VERSION 5.8 ;
BUSBITCHARS "[]" ;
DIVIDERCHAR "/" ;
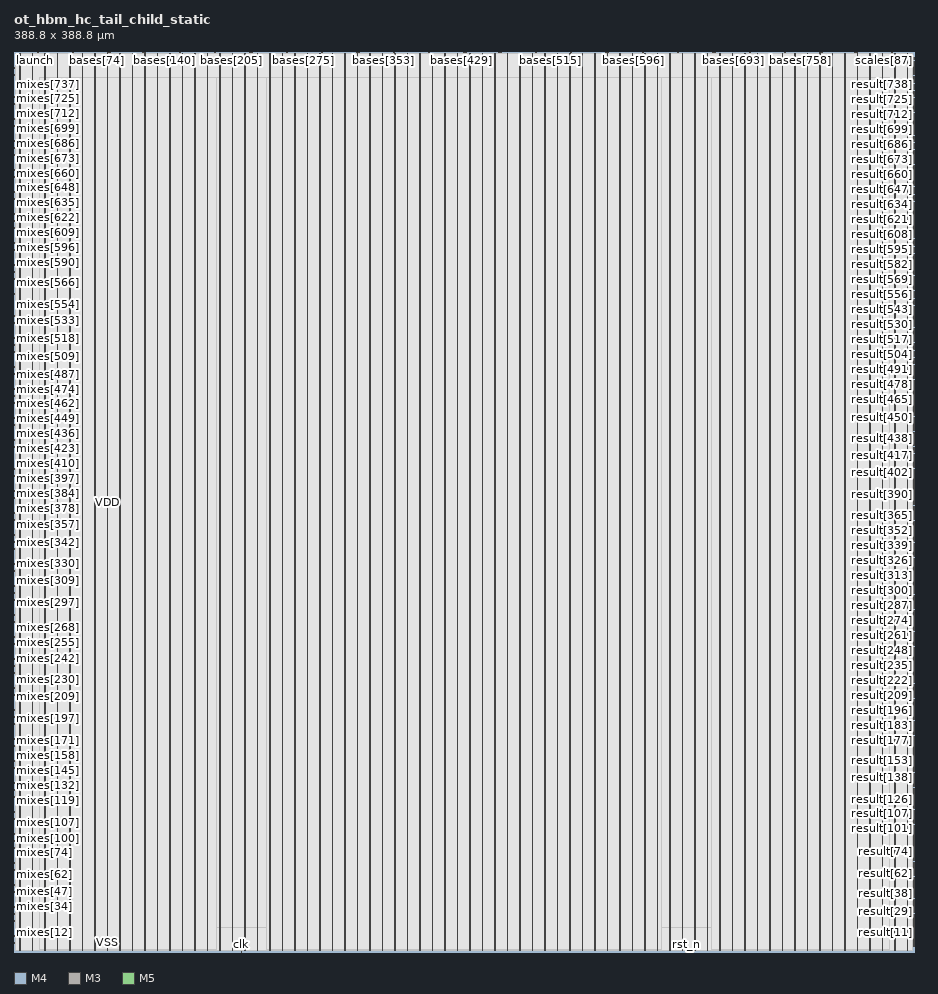
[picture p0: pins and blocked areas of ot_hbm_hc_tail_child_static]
MACRO ot_hbm_hc_tail_child_static
  CLASS BLOCK ;
  ORIGIN 0 0 ;
  FOREIGN ot_hbm_hc_tail_child_static 0 0 ;
  SIZE 388.8 BY 388.8 ;
  SYMMETRY X Y ;
  PIN mixes[0]
    DIRECTION INPUT ;
    USE SIGNAL ;
    PORT
      LAYER M4 ;
        RECT 0.000 2.400 0.192 2.424 ;
    END
  END mixes[0]
  PIN mixes[1]
    DIRECTION INPUT ;
    USE SIGNAL ;
    PORT
      LAYER M4 ;
        RECT 0.000 2.880 0.192 2.904 ;
    END
  END mixes[1]
  PIN mixes[2]
    DIRECTION INPUT ;
    USE SIGNAL ;
    PORT
      LAYER M4 ;
        RECT 0.000 3.408 0.192 3.432 ;
    END
  END mixes[2]
  PIN mixes[3]
    DIRECTION INPUT ;
    USE SIGNAL ;
    PORT
      LAYER M4 ;
        RECT 0.000 3.888 0.192 3.912 ;
    END
  END mixes[3]
  PIN mixes[4]
    DIRECTION INPUT ;
    USE SIGNAL ;
    PORT
      LAYER M4 ;
        RECT 0.000 4.416 0.192 4.440 ;
    END
  END mixes[4]
  PIN mixes[5]
    DIRECTION INPUT ;
    USE SIGNAL ;
    PORT
      LAYER M4 ;
        RECT 0.000 4.896 0.192 4.920 ;
    END
  END mixes[5]
  PIN mixes[6]
    DIRECTION INPUT ;
    USE SIGNAL ;
    PORT
      LAYER M4 ;
        RECT 0.000 5.424 0.192 5.448 ;
    END
  END mixes[6]
  PIN mixes[7]
    DIRECTION INPUT ;
    USE SIGNAL ;
    PORT
      LAYER M4 ;
        RECT 0.000 5.904 0.192 5.928 ;
    END
  END mixes[7]
  PIN mixes[8]
    DIRECTION INPUT ;
    USE SIGNAL ;
    PORT
      LAYER M4 ;
        RECT 0.000 6.384 0.192 6.408 ;
    END
  END mixes[8]
  PIN mixes[9]
    DIRECTION INPUT ;
    USE SIGNAL ;
    PORT
      LAYER M4 ;
        RECT 0.000 6.912 0.192 6.936 ;
    END
  END mixes[9]
  PIN mixes[10]
    DIRECTION INPUT ;
    USE SIGNAL ;
    PORT
      LAYER M4 ;
        RECT 0.000 7.392 0.192 7.416 ;
    END
  END mixes[10]
  PIN mixes[11]
    DIRECTION INPUT ;
    USE SIGNAL ;
    PORT
      LAYER M4 ;
        RECT 0.000 7.920 0.192 7.944 ;
    END
  END mixes[11]
  PIN mixes[12]
    DIRECTION INPUT ;
    USE SIGNAL ;
    PORT
      LAYER M4 ;
        RECT 0.000 8.400 0.192 8.424 ;
    END
  END mixes[12]
  PIN mixes[13]
    DIRECTION INPUT ;
    USE SIGNAL ;
    PORT
      LAYER M4 ;
        RECT 0.000 8.928 0.192 8.952 ;
    END
  END mixes[13]
  PIN mixes[14]
    DIRECTION INPUT ;
    USE SIGNAL ;
    PORT
      LAYER M4 ;
        RECT 0.000 9.408 0.192 9.432 ;
    END
  END mixes[14]
  PIN mixes[15]
    DIRECTION INPUT ;
    USE SIGNAL ;
    PORT
      LAYER M4 ;
        RECT 0.000 9.888 0.192 9.912 ;
    END
  END mixes[15]
  PIN mixes[16]
    DIRECTION INPUT ;
    USE SIGNAL ;
    PORT
      LAYER M4 ;
        RECT 0.000 10.416 0.192 10.440 ;
    END
  END mixes[16]
  PIN mixes[17]
    DIRECTION INPUT ;
    USE SIGNAL ;
    PORT
      LAYER M4 ;
        RECT 0.000 10.896 0.192 10.920 ;
    END
  END mixes[17]
  PIN mixes[18]
    DIRECTION INPUT ;
    USE SIGNAL ;
    PORT
      LAYER M4 ;
        RECT 0.000 11.424 0.192 11.448 ;
    END
  END mixes[18]
  PIN mixes[19]
    DIRECTION INPUT ;
    USE SIGNAL ;
    PORT
      LAYER M4 ;
        RECT 0.000 11.904 0.192 11.928 ;
    END
  END mixes[19]
  PIN mixes[20]
    DIRECTION INPUT ;
    USE SIGNAL ;
    PORT
      LAYER M4 ;
        RECT 0.000 12.432 0.192 12.456 ;
    END
  END mixes[20]
  PIN mixes[21]
    DIRECTION INPUT ;
    USE SIGNAL ;
    PORT
      LAYER M4 ;
        RECT 0.000 12.912 0.192 12.936 ;
    END
  END mixes[21]
  PIN mixes[22]
    DIRECTION INPUT ;
    USE SIGNAL ;
    PORT
      LAYER M4 ;
        RECT 0.000 13.392 0.192 13.416 ;
    END
  END mixes[22]
  PIN mixes[23]
    DIRECTION INPUT ;
    USE SIGNAL ;
    PORT
      LAYER M4 ;
        RECT 0.000 13.920 0.192 13.944 ;
    END
  END mixes[23]
  PIN mixes[24]
    DIRECTION INPUT ;
    USE SIGNAL ;
    PORT
      LAYER M4 ;
        RECT 0.000 14.400 0.192 14.424 ;
    END
  END mixes[24]
  PIN mixes[25]
    DIRECTION INPUT ;
    USE SIGNAL ;
    PORT
      LAYER M4 ;
        RECT 0.000 14.928 0.192 14.952 ;
    END
  END mixes[25]
  PIN mixes[26]
    DIRECTION INPUT ;
    USE SIGNAL ;
    PORT
      LAYER M4 ;
        RECT 0.000 15.408 0.192 15.432 ;
    END
  END mixes[26]
  PIN mixes[27]
    DIRECTION INPUT ;
    USE SIGNAL ;
    PORT
      LAYER M4 ;
        RECT 0.000 15.936 0.192 15.960 ;
    END
  END mixes[27]
  PIN mixes[28]
    DIRECTION INPUT ;
    USE SIGNAL ;
    PORT
      LAYER M4 ;
        RECT 0.000 16.416 0.192 16.440 ;
    END
  END mixes[28]
  PIN mixes[29]
    DIRECTION INPUT ;
    USE SIGNAL ;
    PORT
      LAYER M4 ;
        RECT 0.000 16.896 0.192 16.920 ;
    END
  END mixes[29]
  PIN mixes[30]
    DIRECTION INPUT ;
    USE SIGNAL ;
    PORT
      LAYER M4 ;
        RECT 0.000 17.424 0.192 17.448 ;
    END
  END mixes[30]
  PIN mixes[31]
    DIRECTION INPUT ;
    USE SIGNAL ;
    PORT
      LAYER M4 ;
        RECT 0.000 17.904 0.192 17.928 ;
    END
  END mixes[31]
  PIN mixes[32]
    DIRECTION INPUT ;
    USE SIGNAL ;
    PORT
      LAYER M4 ;
        RECT 0.000 18.432 0.192 18.456 ;
    END
  END mixes[32]
  PIN mixes[33]
    DIRECTION INPUT ;
    USE SIGNAL ;
    PORT
      LAYER M4 ;
        RECT 0.000 18.912 0.192 18.936 ;
    END
  END mixes[33]
  PIN mixes[34]
    DIRECTION INPUT ;
    USE SIGNAL ;
    PORT
      LAYER M4 ;
        RECT 0.000 19.440 0.192 19.464 ;
    END
  END mixes[34]
  PIN mixes[35]
    DIRECTION INPUT ;
    USE SIGNAL ;
    PORT
      LAYER M4 ;
        RECT 0.000 19.920 0.192 19.944 ;
    END
  END mixes[35]
  PIN mixes[36]
    DIRECTION INPUT ;
    USE SIGNAL ;
    PORT
      LAYER M4 ;
        RECT 0.000 20.400 0.192 20.424 ;
    END
  END mixes[36]
  PIN mixes[37]
    DIRECTION INPUT ;
    USE SIGNAL ;
    PORT
      LAYER M4 ;
        RECT 0.000 20.928 0.192 20.952 ;
    END
  END mixes[37]
  PIN mixes[38]
    DIRECTION INPUT ;
    USE SIGNAL ;
    PORT
      LAYER M4 ;
        RECT 0.000 21.408 0.192 21.432 ;
    END
  END mixes[38]
  PIN mixes[39]
    DIRECTION INPUT ;
    USE SIGNAL ;
    PORT
      LAYER M4 ;
        RECT 0.000 21.936 0.192 21.960 ;
    END
  END mixes[39]
  PIN mixes[40]
    DIRECTION INPUT ;
    USE SIGNAL ;
    PORT
      LAYER M4 ;
        RECT 0.000 22.416 0.192 22.440 ;
    END
  END mixes[40]
  PIN mixes[41]
    DIRECTION INPUT ;
    USE SIGNAL ;
    PORT
      LAYER M4 ;
        RECT 0.000 22.944 0.192 22.968 ;
    END
  END mixes[41]
  PIN mixes[42]
    DIRECTION INPUT ;
    USE SIGNAL ;
    PORT
      LAYER M4 ;
        RECT 0.000 23.424 0.192 23.448 ;
    END
  END mixes[42]
  PIN mixes[43]
    DIRECTION INPUT ;
    USE SIGNAL ;
    PORT
      LAYER M4 ;
        RECT 0.000 23.904 0.192 23.928 ;
    END
  END mixes[43]
  PIN mixes[44]
    DIRECTION INPUT ;
    USE SIGNAL ;
    PORT
      LAYER M4 ;
        RECT 0.000 24.432 0.192 24.456 ;
    END
  END mixes[44]
  PIN mixes[45]
    DIRECTION INPUT ;
    USE SIGNAL ;
    PORT
      LAYER M4 ;
        RECT 0.000 24.912 0.192 24.936 ;
    END
  END mixes[45]
  PIN mixes[46]
    DIRECTION INPUT ;
    USE SIGNAL ;
    PORT
      LAYER M4 ;
        RECT 0.000 25.440 0.192 25.464 ;
    END
  END mixes[46]
  PIN mixes[47]
    DIRECTION INPUT ;
    USE SIGNAL ;
    PORT
      LAYER M4 ;
        RECT 0.000 25.920 0.192 25.944 ;
    END
  END mixes[47]
  PIN mixes[48]
    DIRECTION INPUT ;
    USE SIGNAL ;
    PORT
      LAYER M4 ;
        RECT 0.000 26.448 0.192 26.472 ;
    END
  END mixes[48]
  PIN mixes[49]
    DIRECTION INPUT ;
    USE SIGNAL ;
    PORT
      LAYER M4 ;
        RECT 0.000 26.928 0.192 26.952 ;
    END
  END mixes[49]
  PIN mixes[50]
    DIRECTION INPUT ;
    USE SIGNAL ;
    PORT
      LAYER M4 ;
        RECT 0.000 27.408 0.192 27.432 ;
    END
  END mixes[50]
  PIN mixes[51]
    DIRECTION INPUT ;
    USE SIGNAL ;
    PORT
      LAYER M4 ;
        RECT 0.000 27.936 0.192 27.960 ;
    END
  END mixes[51]
  PIN mixes[52]
    DIRECTION INPUT ;
    USE SIGNAL ;
    PORT
      LAYER M4 ;
        RECT 0.000 28.416 0.192 28.440 ;
    END
  END mixes[52]
  PIN mixes[53]
    DIRECTION INPUT ;
    USE SIGNAL ;
    PORT
      LAYER M4 ;
        RECT 0.000 28.944 0.192 28.968 ;
    END
  END mixes[53]
  PIN mixes[54]
    DIRECTION INPUT ;
    USE SIGNAL ;
    PORT
      LAYER M4 ;
        RECT 0.000 29.424 0.192 29.448 ;
    END
  END mixes[54]
  PIN mixes[55]
    DIRECTION INPUT ;
    USE SIGNAL ;
    PORT
      LAYER M4 ;
        RECT 0.000 29.952 0.192 29.976 ;
    END
  END mixes[55]
  PIN mixes[56]
    DIRECTION INPUT ;
    USE SIGNAL ;
    PORT
      LAYER M4 ;
        RECT 0.000 30.432 0.192 30.456 ;
    END
  END mixes[56]
  PIN mixes[57]
    DIRECTION INPUT ;
    USE SIGNAL ;
    PORT
      LAYER M4 ;
        RECT 0.000 30.912 0.192 30.936 ;
    END
  END mixes[57]
  PIN mixes[58]
    DIRECTION INPUT ;
    USE SIGNAL ;
    PORT
      LAYER M4 ;
        RECT 0.000 31.440 0.192 31.464 ;
    END
  END mixes[58]
  PIN mixes[59]
    DIRECTION INPUT ;
    USE SIGNAL ;
    PORT
      LAYER M4 ;
        RECT 0.000 31.920 0.192 31.944 ;
    END
  END mixes[59]
  PIN mixes[60]
    DIRECTION INPUT ;
    USE SIGNAL ;
    PORT
      LAYER M4 ;
        RECT 0.000 32.448 0.192 32.472 ;
    END
  END mixes[60]
  PIN mixes[61]
    DIRECTION INPUT ;
    USE SIGNAL ;
    PORT
      LAYER M4 ;
        RECT 0.000 32.928 0.192 32.952 ;
    END
  END mixes[61]
  PIN mixes[62]
    DIRECTION INPUT ;
    USE SIGNAL ;
    PORT
      LAYER M4 ;
        RECT 0.000 33.456 0.192 33.480 ;
    END
  END mixes[62]
  PIN mixes[63]
    DIRECTION INPUT ;
    USE SIGNAL ;
    PORT
      LAYER M4 ;
        RECT 0.000 33.936 0.192 33.960 ;
    END
  END mixes[63]
  PIN mixes[64]
    DIRECTION INPUT ;
    USE SIGNAL ;
    PORT
      LAYER M4 ;
        RECT 0.000 34.416 0.192 34.440 ;
    END
  END mixes[64]
  PIN mixes[65]
    DIRECTION INPUT ;
    USE SIGNAL ;
    PORT
      LAYER M4 ;
        RECT 0.000 34.944 0.192 34.968 ;
    END
  END mixes[65]
  PIN mixes[66]
    DIRECTION INPUT ;
    USE SIGNAL ;
    PORT
      LAYER M4 ;
        RECT 0.000 35.424 0.192 35.448 ;
    END
  END mixes[66]
  PIN mixes[67]
    DIRECTION INPUT ;
    USE SIGNAL ;
    PORT
      LAYER M4 ;
        RECT 0.000 35.952 0.192 35.976 ;
    END
  END mixes[67]
  PIN mixes[68]
    DIRECTION INPUT ;
    USE SIGNAL ;
    PORT
      LAYER M4 ;
        RECT 0.000 36.432 0.192 36.456 ;
    END
  END mixes[68]
  PIN mixes[69]
    DIRECTION INPUT ;
    USE SIGNAL ;
    PORT
      LAYER M4 ;
        RECT 0.000 36.960 0.192 36.984 ;
    END
  END mixes[69]
  PIN mixes[70]
    DIRECTION INPUT ;
    USE SIGNAL ;
    PORT
      LAYER M4 ;
        RECT 0.000 37.440 0.192 37.464 ;
    END
  END mixes[70]
  PIN mixes[71]
    DIRECTION INPUT ;
    USE SIGNAL ;
    PORT
      LAYER M4 ;
        RECT 0.000 37.920 0.192 37.944 ;
    END
  END mixes[71]
  PIN mixes[72]
    DIRECTION INPUT ;
    USE SIGNAL ;
    PORT
      LAYER M4 ;
        RECT 0.000 38.448 0.192 38.472 ;
    END
  END mixes[72]
  PIN mixes[73]
    DIRECTION INPUT ;
    USE SIGNAL ;
    PORT
      LAYER M4 ;
        RECT 0.000 38.928 0.192 38.952 ;
    END
  END mixes[73]
  PIN mixes[74]
    DIRECTION INPUT ;
    USE SIGNAL ;
    PORT
      LAYER M4 ;
        RECT 0.000 39.456 0.192 39.480 ;
    END
  END mixes[74]
  PIN mixes[75]
    DIRECTION INPUT ;
    USE SIGNAL ;
    PORT
      LAYER M4 ;
        RECT 0.000 39.936 0.192 39.960 ;
    END
  END mixes[75]
  PIN mixes[76]
    DIRECTION INPUT ;
    USE SIGNAL ;
    PORT
      LAYER M4 ;
        RECT 0.000 40.464 0.192 40.488 ;
    END
  END mixes[76]
  PIN mixes[77]
    DIRECTION INPUT ;
    USE SIGNAL ;
    PORT
      LAYER M4 ;
        RECT 0.000 40.944 0.192 40.968 ;
    END
  END mixes[77]
  PIN mixes[78]
    DIRECTION INPUT ;
    USE SIGNAL ;
    PORT
      LAYER M4 ;
        RECT 0.000 41.424 0.192 41.448 ;
    END
  END mixes[78]
  PIN mixes[79]
    DIRECTION INPUT ;
    USE SIGNAL ;
    PORT
      LAYER M4 ;
        RECT 0.000 41.952 0.192 41.976 ;
    END
  END mixes[79]
  PIN mixes[80]
    DIRECTION INPUT ;
    USE SIGNAL ;
    PORT
      LAYER M4 ;
        RECT 0.000 42.432 0.192 42.456 ;
    END
  END mixes[80]
  PIN mixes[81]
    DIRECTION INPUT ;
    USE SIGNAL ;
    PORT
      LAYER M4 ;
        RECT 0.000 42.960 0.192 42.984 ;
    END
  END mixes[81]
  PIN mixes[82]
    DIRECTION INPUT ;
    USE SIGNAL ;
    PORT
      LAYER M4 ;
        RECT 0.000 43.440 0.192 43.464 ;
    END
  END mixes[82]
  PIN mixes[83]
    DIRECTION INPUT ;
    USE SIGNAL ;
    PORT
      LAYER M4 ;
        RECT 0.000 43.968 0.192 43.992 ;
    END
  END mixes[83]
  PIN mixes[84]
    DIRECTION INPUT ;
    USE SIGNAL ;
    PORT
      LAYER M4 ;
        RECT 0.000 44.448 0.192 44.472 ;
    END
  END mixes[84]
  PIN mixes[85]
    DIRECTION INPUT ;
    USE SIGNAL ;
    PORT
      LAYER M4 ;
        RECT 0.000 44.928 0.192 44.952 ;
    END
  END mixes[85]
  PIN mixes[86]
    DIRECTION INPUT ;
    USE SIGNAL ;
    PORT
      LAYER M4 ;
        RECT 0.000 45.456 0.192 45.480 ;
    END
  END mixes[86]
  PIN mixes[87]
    DIRECTION INPUT ;
    USE SIGNAL ;
    PORT
      LAYER M4 ;
        RECT 0.000 45.936 0.192 45.960 ;
    END
  END mixes[87]
  PIN mixes[88]
    DIRECTION INPUT ;
    USE SIGNAL ;
    PORT
      LAYER M4 ;
        RECT 0.000 46.464 0.192 46.488 ;
    END
  END mixes[88]
  PIN mixes[89]
    DIRECTION INPUT ;
    USE SIGNAL ;
    PORT
      LAYER M4 ;
        RECT 0.000 46.944 0.192 46.968 ;
    END
  END mixes[89]
  PIN mixes[90]
    DIRECTION INPUT ;
    USE SIGNAL ;
    PORT
      LAYER M4 ;
        RECT 0.000 47.472 0.192 47.496 ;
    END
  END mixes[90]
  PIN mixes[91]
    DIRECTION INPUT ;
    USE SIGNAL ;
    PORT
      LAYER M4 ;
        RECT 0.000 47.952 0.192 47.976 ;
    END
  END mixes[91]
  PIN mixes[92]
    DIRECTION INPUT ;
    USE SIGNAL ;
    PORT
      LAYER M4 ;
        RECT 0.000 48.432 0.192 48.456 ;
    END
  END mixes[92]
  PIN mixes[93]
    DIRECTION INPUT ;
    USE SIGNAL ;
    PORT
      LAYER M4 ;
        RECT 0.000 48.960 0.192 48.984 ;
    END
  END mixes[93]
  PIN mixes[94]
    DIRECTION INPUT ;
    USE SIGNAL ;
    PORT
      LAYER M4 ;
        RECT 0.000 49.440 0.192 49.464 ;
    END
  END mixes[94]
  PIN mixes[95]
    DIRECTION INPUT ;
    USE SIGNAL ;
    PORT
      LAYER M4 ;
        RECT 0.000 49.968 0.192 49.992 ;
    END
  END mixes[95]
  PIN mixes[96]
    DIRECTION INPUT ;
    USE SIGNAL ;
    PORT
      LAYER M4 ;
        RECT 0.000 50.448 0.192 50.472 ;
    END
  END mixes[96]
  PIN mixes[97]
    DIRECTION INPUT ;
    USE SIGNAL ;
    PORT
      LAYER M4 ;
        RECT 0.000 50.976 0.192 51.000 ;
    END
  END mixes[97]
  PIN mixes[98]
    DIRECTION INPUT ;
    USE SIGNAL ;
    PORT
      LAYER M4 ;
        RECT 0.000 51.456 0.192 51.480 ;
    END
  END mixes[98]
  PIN mixes[99]
    DIRECTION INPUT ;
    USE SIGNAL ;
    PORT
      LAYER M4 ;
        RECT 0.000 51.984 0.192 52.008 ;
    END
  END mixes[99]
  PIN mixes[100]
    DIRECTION INPUT ;
    USE SIGNAL ;
    PORT
      LAYER M4 ;
        RECT 0.000 52.464 0.192 52.488 ;
    END
  END mixes[100]
  PIN mixes[101]
    DIRECTION INPUT ;
    USE SIGNAL ;
    PORT
      LAYER M4 ;
        RECT 0.000 52.944 0.192 52.968 ;
    END
  END mixes[101]
  PIN mixes[102]
    DIRECTION INPUT ;
    USE SIGNAL ;
    PORT
      LAYER M4 ;
        RECT 0.000 53.472 0.192 53.496 ;
    END
  END mixes[102]
  PIN mixes[103]
    DIRECTION INPUT ;
    USE SIGNAL ;
    PORT
      LAYER M4 ;
        RECT 0.000 53.952 0.192 53.976 ;
    END
  END mixes[103]
  PIN mixes[104]
    DIRECTION INPUT ;
    USE SIGNAL ;
    PORT
      LAYER M4 ;
        RECT 0.000 54.480 0.192 54.504 ;
    END
  END mixes[104]
  PIN mixes[105]
    DIRECTION INPUT ;
    USE SIGNAL ;
    PORT
      LAYER M4 ;
        RECT 0.000 54.960 0.192 54.984 ;
    END
  END mixes[105]
  PIN mixes[106]
    DIRECTION INPUT ;
    USE SIGNAL ;
    PORT
      LAYER M4 ;
        RECT 0.000 55.488 0.192 55.512 ;
    END
  END mixes[106]
  PIN mixes[107]
    DIRECTION INPUT ;
    USE SIGNAL ;
    PORT
      LAYER M4 ;
        RECT 0.000 55.968 0.192 55.992 ;
    END
  END mixes[107]
  PIN mixes[108]
    DIRECTION INPUT ;
    USE SIGNAL ;
    PORT
      LAYER M4 ;
        RECT 0.000 56.448 0.192 56.472 ;
    END
  END mixes[108]
  PIN mixes[109]
    DIRECTION INPUT ;
    USE SIGNAL ;
    PORT
      LAYER M4 ;
        RECT 0.000 56.976 0.192 57.000 ;
    END
  END mixes[109]
  PIN mixes[110]
    DIRECTION INPUT ;
    USE SIGNAL ;
    PORT
      LAYER M4 ;
        RECT 0.000 57.456 0.192 57.480 ;
    END
  END mixes[110]
  PIN mixes[111]
    DIRECTION INPUT ;
    USE SIGNAL ;
    PORT
      LAYER M4 ;
        RECT 0.000 57.984 0.192 58.008 ;
    END
  END mixes[111]
  PIN mixes[112]
    DIRECTION INPUT ;
    USE SIGNAL ;
    PORT
      LAYER M4 ;
        RECT 0.000 58.464 0.192 58.488 ;
    END
  END mixes[112]
  PIN mixes[113]
    DIRECTION INPUT ;
    USE SIGNAL ;
    PORT
      LAYER M4 ;
        RECT 0.000 58.992 0.192 59.016 ;
    END
  END mixes[113]
  PIN mixes[114]
    DIRECTION INPUT ;
    USE SIGNAL ;
    PORT
      LAYER M4 ;
        RECT 0.000 59.472 0.192 59.496 ;
    END
  END mixes[114]
  PIN mixes[115]
    DIRECTION INPUT ;
    USE SIGNAL ;
    PORT
      LAYER M4 ;
        RECT 0.000 59.952 0.192 59.976 ;
    END
  END mixes[115]
  PIN mixes[116]
    DIRECTION INPUT ;
    USE SIGNAL ;
    PORT
      LAYER M4 ;
        RECT 0.000 60.480 0.192 60.504 ;
    END
  END mixes[116]
  PIN mixes[117]
    DIRECTION INPUT ;
    USE SIGNAL ;
    PORT
      LAYER M4 ;
        RECT 0.000 60.960 0.192 60.984 ;
    END
  END mixes[117]
  PIN mixes[118]
    DIRECTION INPUT ;
    USE SIGNAL ;
    PORT
      LAYER M4 ;
        RECT 0.000 61.488 0.192 61.512 ;
    END
  END mixes[118]
  PIN mixes[119]
    DIRECTION INPUT ;
    USE SIGNAL ;
    PORT
      LAYER M4 ;
        RECT 0.000 61.968 0.192 61.992 ;
    END
  END mixes[119]
  PIN mixes[120]
    DIRECTION INPUT ;
    USE SIGNAL ;
    PORT
      LAYER M4 ;
        RECT 0.000 62.496 0.192 62.520 ;
    END
  END mixes[120]
  PIN mixes[121]
    DIRECTION INPUT ;
    USE SIGNAL ;
    PORT
      LAYER M4 ;
        RECT 0.000 62.976 0.192 63.000 ;
    END
  END mixes[121]
  PIN mixes[122]
    DIRECTION INPUT ;
    USE SIGNAL ;
    PORT
      LAYER M4 ;
        RECT 0.000 63.456 0.192 63.480 ;
    END
  END mixes[122]
  PIN mixes[123]
    DIRECTION INPUT ;
    USE SIGNAL ;
    PORT
      LAYER M4 ;
        RECT 0.000 63.984 0.192 64.008 ;
    END
  END mixes[123]
  PIN mixes[124]
    DIRECTION INPUT ;
    USE SIGNAL ;
    PORT
      LAYER M4 ;
        RECT 0.000 64.464 0.192 64.488 ;
    END
  END mixes[124]
  PIN mixes[125]
    DIRECTION INPUT ;
    USE SIGNAL ;
    PORT
      LAYER M4 ;
        RECT 0.000 64.992 0.192 65.016 ;
    END
  END mixes[125]
  PIN mixes[126]
    DIRECTION INPUT ;
    USE SIGNAL ;
    PORT
      LAYER M4 ;
        RECT 0.000 65.472 0.192 65.496 ;
    END
  END mixes[126]
  PIN mixes[127]
    DIRECTION INPUT ;
    USE SIGNAL ;
    PORT
      LAYER M4 ;
        RECT 0.000 66.000 0.192 66.024 ;
    END
  END mixes[127]
  PIN mixes[128]
    DIRECTION INPUT ;
    USE SIGNAL ;
    PORT
      LAYER M4 ;
        RECT 0.000 66.480 0.192 66.504 ;
    END
  END mixes[128]
  PIN mixes[129]
    DIRECTION INPUT ;
    USE SIGNAL ;
    PORT
      LAYER M4 ;
        RECT 0.000 66.960 0.192 66.984 ;
    END
  END mixes[129]
  PIN mixes[130]
    DIRECTION INPUT ;
    USE SIGNAL ;
    PORT
      LAYER M4 ;
        RECT 0.000 67.488 0.192 67.512 ;
    END
  END mixes[130]
  PIN mixes[131]
    DIRECTION INPUT ;
    USE SIGNAL ;
    PORT
      LAYER M4 ;
        RECT 0.000 67.968 0.192 67.992 ;
    END
  END mixes[131]
  PIN mixes[132]
    DIRECTION INPUT ;
    USE SIGNAL ;
    PORT
      LAYER M4 ;
        RECT 0.000 68.496 0.192 68.520 ;
    END
  END mixes[132]
  PIN mixes[133]
    DIRECTION INPUT ;
    USE SIGNAL ;
    PORT
      LAYER M4 ;
        RECT 0.000 68.976 0.192 69.000 ;
    END
  END mixes[133]
  PIN mixes[134]
    DIRECTION INPUT ;
    USE SIGNAL ;
    PORT
      LAYER M4 ;
        RECT 0.000 69.504 0.192 69.528 ;
    END
  END mixes[134]
  PIN mixes[135]
    DIRECTION INPUT ;
    USE SIGNAL ;
    PORT
      LAYER M4 ;
        RECT 0.000 69.984 0.192 70.008 ;
    END
  END mixes[135]
  PIN mixes[136]
    DIRECTION INPUT ;
    USE SIGNAL ;
    PORT
      LAYER M4 ;
        RECT 0.000 70.464 0.192 70.488 ;
    END
  END mixes[136]
  PIN mixes[137]
    DIRECTION INPUT ;
    USE SIGNAL ;
    PORT
      LAYER M4 ;
        RECT 0.000 70.992 0.192 71.016 ;
    END
  END mixes[137]
  PIN mixes[138]
    DIRECTION INPUT ;
    USE SIGNAL ;
    PORT
      LAYER M4 ;
        RECT 0.000 71.472 0.192 71.496 ;
    END
  END mixes[138]
  PIN mixes[139]
    DIRECTION INPUT ;
    USE SIGNAL ;
    PORT
      LAYER M4 ;
        RECT 0.000 72.000 0.192 72.024 ;
    END
  END mixes[139]
  PIN mixes[140]
    DIRECTION INPUT ;
    USE SIGNAL ;
    PORT
      LAYER M4 ;
        RECT 0.000 72.480 0.192 72.504 ;
    END
  END mixes[140]
  PIN mixes[141]
    DIRECTION INPUT ;
    USE SIGNAL ;
    PORT
      LAYER M4 ;
        RECT 0.000 73.008 0.192 73.032 ;
    END
  END mixes[141]
  PIN mixes[142]
    DIRECTION INPUT ;
    USE SIGNAL ;
    PORT
      LAYER M4 ;
        RECT 0.000 73.488 0.192 73.512 ;
    END
  END mixes[142]
  PIN mixes[143]
    DIRECTION INPUT ;
    USE SIGNAL ;
    PORT
      LAYER M4 ;
        RECT 0.000 73.968 0.192 73.992 ;
    END
  END mixes[143]
  PIN mixes[144]
    DIRECTION INPUT ;
    USE SIGNAL ;
    PORT
      LAYER M4 ;
        RECT 0.000 74.496 0.192 74.520 ;
    END
  END mixes[144]
  PIN mixes[145]
    DIRECTION INPUT ;
    USE SIGNAL ;
    PORT
      LAYER M4 ;
        RECT 0.000 74.976 0.192 75.000 ;
    END
  END mixes[145]
  PIN mixes[146]
    DIRECTION INPUT ;
    USE SIGNAL ;
    PORT
      LAYER M4 ;
        RECT 0.000 75.504 0.192 75.528 ;
    END
  END mixes[146]
  PIN mixes[147]
    DIRECTION INPUT ;
    USE SIGNAL ;
    PORT
      LAYER M4 ;
        RECT 0.000 75.984 0.192 76.008 ;
    END
  END mixes[147]
  PIN mixes[148]
    DIRECTION INPUT ;
    USE SIGNAL ;
    PORT
      LAYER M4 ;
        RECT 0.000 76.512 0.192 76.536 ;
    END
  END mixes[148]
  PIN mixes[149]
    DIRECTION INPUT ;
    USE SIGNAL ;
    PORT
      LAYER M4 ;
        RECT 0.000 76.992 0.192 77.016 ;
    END
  END mixes[149]
  PIN mixes[150]
    DIRECTION INPUT ;
    USE SIGNAL ;
    PORT
      LAYER M4 ;
        RECT 0.000 77.472 0.192 77.496 ;
    END
  END mixes[150]
  PIN mixes[151]
    DIRECTION INPUT ;
    USE SIGNAL ;
    PORT
      LAYER M4 ;
        RECT 0.000 78.000 0.192 78.024 ;
    END
  END mixes[151]
  PIN mixes[152]
    DIRECTION INPUT ;
    USE SIGNAL ;
    PORT
      LAYER M4 ;
        RECT 0.000 78.480 0.192 78.504 ;
    END
  END mixes[152]
  PIN mixes[153]
    DIRECTION INPUT ;
    USE SIGNAL ;
    PORT
      LAYER M4 ;
        RECT 0.000 79.008 0.192 79.032 ;
    END
  END mixes[153]
  PIN mixes[154]
    DIRECTION INPUT ;
    USE SIGNAL ;
    PORT
      LAYER M4 ;
        RECT 0.000 79.488 0.192 79.512 ;
    END
  END mixes[154]
  PIN mixes[155]
    DIRECTION INPUT ;
    USE SIGNAL ;
    PORT
      LAYER M4 ;
        RECT 0.000 80.016 0.192 80.040 ;
    END
  END mixes[155]
  PIN mixes[156]
    DIRECTION INPUT ;
    USE SIGNAL ;
    PORT
      LAYER M4 ;
        RECT 0.000 80.496 0.192 80.520 ;
    END
  END mixes[156]
  PIN mixes[157]
    DIRECTION INPUT ;
    USE SIGNAL ;
    PORT
      LAYER M4 ;
        RECT 0.000 80.976 0.192 81.000 ;
    END
  END mixes[157]
  PIN mixes[158]
    DIRECTION INPUT ;
    USE SIGNAL ;
    PORT
      LAYER M4 ;
        RECT 0.000 81.504 0.192 81.528 ;
    END
  END mixes[158]
  PIN mixes[159]
    DIRECTION INPUT ;
    USE SIGNAL ;
    PORT
      LAYER M4 ;
        RECT 0.000 81.984 0.192 82.008 ;
    END
  END mixes[159]
  PIN mixes[160]
    DIRECTION INPUT ;
    USE SIGNAL ;
    PORT
      LAYER M4 ;
        RECT 0.000 82.512 0.192 82.536 ;
    END
  END mixes[160]
  PIN mixes[161]
    DIRECTION INPUT ;
    USE SIGNAL ;
    PORT
      LAYER M4 ;
        RECT 0.000 82.992 0.192 83.016 ;
    END
  END mixes[161]
  PIN mixes[162]
    DIRECTION INPUT ;
    USE SIGNAL ;
    PORT
      LAYER M4 ;
        RECT 0.000 83.520 0.192 83.544 ;
    END
  END mixes[162]
  PIN mixes[163]
    DIRECTION INPUT ;
    USE SIGNAL ;
    PORT
      LAYER M4 ;
        RECT 0.000 84.000 0.192 84.024 ;
    END
  END mixes[163]
  PIN mixes[164]
    DIRECTION INPUT ;
    USE SIGNAL ;
    PORT
      LAYER M4 ;
        RECT 0.000 84.480 0.192 84.504 ;
    END
  END mixes[164]
  PIN mixes[165]
    DIRECTION INPUT ;
    USE SIGNAL ;
    PORT
      LAYER M4 ;
        RECT 0.000 85.008 0.192 85.032 ;
    END
  END mixes[165]
  PIN mixes[166]
    DIRECTION INPUT ;
    USE SIGNAL ;
    PORT
      LAYER M4 ;
        RECT 0.000 85.488 0.192 85.512 ;
    END
  END mixes[166]
  PIN mixes[167]
    DIRECTION INPUT ;
    USE SIGNAL ;
    PORT
      LAYER M4 ;
        RECT 0.000 86.016 0.192 86.040 ;
    END
  END mixes[167]
  PIN mixes[168]
    DIRECTION INPUT ;
    USE SIGNAL ;
    PORT
      LAYER M4 ;
        RECT 0.000 86.496 0.192 86.520 ;
    END
  END mixes[168]
  PIN mixes[169]
    DIRECTION INPUT ;
    USE SIGNAL ;
    PORT
      LAYER M4 ;
        RECT 0.000 87.024 0.192 87.048 ;
    END
  END mixes[169]
  PIN mixes[170]
    DIRECTION INPUT ;
    USE SIGNAL ;
    PORT
      LAYER M4 ;
        RECT 0.000 87.504 0.192 87.528 ;
    END
  END mixes[170]
  PIN mixes[171]
    DIRECTION INPUT ;
    USE SIGNAL ;
    PORT
      LAYER M4 ;
        RECT 0.000 87.984 0.192 88.008 ;
    END
  END mixes[171]
  PIN mixes[172]
    DIRECTION INPUT ;
    USE SIGNAL ;
    PORT
      LAYER M4 ;
        RECT 0.000 88.512 0.192 88.536 ;
    END
  END mixes[172]
  PIN mixes[173]
    DIRECTION INPUT ;
    USE SIGNAL ;
    PORT
      LAYER M4 ;
        RECT 0.000 88.992 0.192 89.016 ;
    END
  END mixes[173]
  PIN mixes[174]
    DIRECTION INPUT ;
    USE SIGNAL ;
    PORT
      LAYER M4 ;
        RECT 0.000 89.520 0.192 89.544 ;
    END
  END mixes[174]
  PIN mixes[175]
    DIRECTION INPUT ;
    USE SIGNAL ;
    PORT
      LAYER M4 ;
        RECT 0.000 90.000 0.192 90.024 ;
    END
  END mixes[175]
  PIN mixes[176]
    DIRECTION INPUT ;
    USE SIGNAL ;
    PORT
      LAYER M4 ;
        RECT 0.000 90.528 0.192 90.552 ;
    END
  END mixes[176]
  PIN mixes[177]
    DIRECTION INPUT ;
    USE SIGNAL ;
    PORT
      LAYER M4 ;
        RECT 0.000 91.008 0.192 91.032 ;
    END
  END mixes[177]
  PIN mixes[178]
    DIRECTION INPUT ;
    USE SIGNAL ;
    PORT
      LAYER M4 ;
        RECT 0.000 91.488 0.192 91.512 ;
    END
  END mixes[178]
  PIN mixes[179]
    DIRECTION INPUT ;
    USE SIGNAL ;
    PORT
      LAYER M4 ;
        RECT 0.000 92.016 0.192 92.040 ;
    END
  END mixes[179]
  PIN mixes[180]
    DIRECTION INPUT ;
    USE SIGNAL ;
    PORT
      LAYER M4 ;
        RECT 0.000 92.496 0.192 92.520 ;
    END
  END mixes[180]
  PIN mixes[181]
    DIRECTION INPUT ;
    USE SIGNAL ;
    PORT
      LAYER M4 ;
        RECT 0.000 93.024 0.192 93.048 ;
    END
  END mixes[181]
  PIN mixes[182]
    DIRECTION INPUT ;
    USE SIGNAL ;
    PORT
      LAYER M4 ;
        RECT 0.000 93.504 0.192 93.528 ;
    END
  END mixes[182]
  PIN mixes[183]
    DIRECTION INPUT ;
    USE SIGNAL ;
    PORT
      LAYER M4 ;
        RECT 0.000 94.032 0.192 94.056 ;
    END
  END mixes[183]
  PIN mixes[184]
    DIRECTION INPUT ;
    USE SIGNAL ;
    PORT
      LAYER M4 ;
        RECT 0.000 94.512 0.192 94.536 ;
    END
  END mixes[184]
  PIN mixes[185]
    DIRECTION INPUT ;
    USE SIGNAL ;
    PORT
      LAYER M4 ;
        RECT 0.000 94.992 0.192 95.016 ;
    END
  END mixes[185]
  PIN mixes[186]
    DIRECTION INPUT ;
    USE SIGNAL ;
    PORT
      LAYER M4 ;
        RECT 0.000 95.520 0.192 95.544 ;
    END
  END mixes[186]
  PIN mixes[187]
    DIRECTION INPUT ;
    USE SIGNAL ;
    PORT
      LAYER M4 ;
        RECT 0.000 96.000 0.192 96.024 ;
    END
  END mixes[187]
  PIN mixes[188]
    DIRECTION INPUT ;
    USE SIGNAL ;
    PORT
      LAYER M4 ;
        RECT 0.000 96.528 0.192 96.552 ;
    END
  END mixes[188]
  PIN mixes[189]
    DIRECTION INPUT ;
    USE SIGNAL ;
    PORT
      LAYER M4 ;
        RECT 0.000 97.008 0.192 97.032 ;
    END
  END mixes[189]
  PIN mixes[190]
    DIRECTION INPUT ;
    USE SIGNAL ;
    PORT
      LAYER M4 ;
        RECT 0.000 97.536 0.192 97.560 ;
    END
  END mixes[190]
  PIN mixes[191]
    DIRECTION INPUT ;
    USE SIGNAL ;
    PORT
      LAYER M4 ;
        RECT 0.000 98.016 0.192 98.040 ;
    END
  END mixes[191]
  PIN mixes[192]
    DIRECTION INPUT ;
    USE SIGNAL ;
    PORT
      LAYER M4 ;
        RECT 0.000 98.496 0.192 98.520 ;
    END
  END mixes[192]
  PIN mixes[193]
    DIRECTION INPUT ;
    USE SIGNAL ;
    PORT
      LAYER M4 ;
        RECT 0.000 99.024 0.192 99.048 ;
    END
  END mixes[193]
  PIN mixes[194]
    DIRECTION INPUT ;
    USE SIGNAL ;
    PORT
      LAYER M4 ;
        RECT 0.000 99.504 0.192 99.528 ;
    END
  END mixes[194]
  PIN mixes[195]
    DIRECTION INPUT ;
    USE SIGNAL ;
    PORT
      LAYER M4 ;
        RECT 0.000 100.032 0.192 100.056 ;
    END
  END mixes[195]
  PIN mixes[196]
    DIRECTION INPUT ;
    USE SIGNAL ;
    PORT
      LAYER M4 ;
        RECT 0.000 100.512 0.192 100.536 ;
    END
  END mixes[196]
  PIN mixes[197]
    DIRECTION INPUT ;
    USE SIGNAL ;
    PORT
      LAYER M4 ;
        RECT 0.000 101.040 0.192 101.064 ;
    END
  END mixes[197]
  PIN mixes[198]
    DIRECTION INPUT ;
    USE SIGNAL ;
    PORT
      LAYER M4 ;
        RECT 0.000 101.520 0.192 101.544 ;
    END
  END mixes[198]
  PIN mixes[199]
    DIRECTION INPUT ;
    USE SIGNAL ;
    PORT
      LAYER M4 ;
        RECT 0.000 102.000 0.192 102.024 ;
    END
  END mixes[199]
  PIN mixes[200]
    DIRECTION INPUT ;
    USE SIGNAL ;
    PORT
      LAYER M4 ;
        RECT 0.000 102.528 0.192 102.552 ;
    END
  END mixes[200]
  PIN mixes[201]
    DIRECTION INPUT ;
    USE SIGNAL ;
    PORT
      LAYER M4 ;
        RECT 0.000 103.008 0.192 103.032 ;
    END
  END mixes[201]
  PIN mixes[202]
    DIRECTION INPUT ;
    USE SIGNAL ;
    PORT
      LAYER M4 ;
        RECT 0.000 103.536 0.192 103.560 ;
    END
  END mixes[202]
  PIN mixes[203]
    DIRECTION INPUT ;
    USE SIGNAL ;
    PORT
      LAYER M4 ;
        RECT 0.000 104.016 0.192 104.040 ;
    END
  END mixes[203]
  PIN mixes[204]
    DIRECTION INPUT ;
    USE SIGNAL ;
    PORT
      LAYER M4 ;
        RECT 0.000 104.544 0.192 104.568 ;
    END
  END mixes[204]
  PIN mixes[205]
    DIRECTION INPUT ;
    USE SIGNAL ;
    PORT
      LAYER M4 ;
        RECT 0.000 105.024 0.192 105.048 ;
    END
  END mixes[205]
  PIN mixes[206]
    DIRECTION INPUT ;
    USE SIGNAL ;
    PORT
      LAYER M4 ;
        RECT 0.000 105.504 0.192 105.528 ;
    END
  END mixes[206]
  PIN mixes[207]
    DIRECTION INPUT ;
    USE SIGNAL ;
    PORT
      LAYER M4 ;
        RECT 0.000 106.032 0.192 106.056 ;
    END
  END mixes[207]
  PIN mixes[208]
    DIRECTION INPUT ;
    USE SIGNAL ;
    PORT
      LAYER M4 ;
        RECT 0.000 106.512 0.192 106.536 ;
    END
  END mixes[208]
  PIN mixes[209]
    DIRECTION INPUT ;
    USE SIGNAL ;
    PORT
      LAYER M4 ;
        RECT 0.000 107.040 0.192 107.064 ;
    END
  END mixes[209]
  PIN mixes[210]
    DIRECTION INPUT ;
    USE SIGNAL ;
    PORT
      LAYER M4 ;
        RECT 0.000 107.520 0.192 107.544 ;
    END
  END mixes[210]
  PIN mixes[211]
    DIRECTION INPUT ;
    USE SIGNAL ;
    PORT
      LAYER M4 ;
        RECT 0.000 108.048 0.192 108.072 ;
    END
  END mixes[211]
  PIN mixes[212]
    DIRECTION INPUT ;
    USE SIGNAL ;
    PORT
      LAYER M4 ;
        RECT 0.000 108.528 0.192 108.552 ;
    END
  END mixes[212]
  PIN mixes[213]
    DIRECTION INPUT ;
    USE SIGNAL ;
    PORT
      LAYER M4 ;
        RECT 0.000 109.008 0.192 109.032 ;
    END
  END mixes[213]
  PIN mixes[214]
    DIRECTION INPUT ;
    USE SIGNAL ;
    PORT
      LAYER M4 ;
        RECT 0.000 109.536 0.192 109.560 ;
    END
  END mixes[214]
  PIN mixes[215]
    DIRECTION INPUT ;
    USE SIGNAL ;
    PORT
      LAYER M4 ;
        RECT 0.000 110.016 0.192 110.040 ;
    END
  END mixes[215]
  PIN mixes[216]
    DIRECTION INPUT ;
    USE SIGNAL ;
    PORT
      LAYER M4 ;
        RECT 0.000 110.544 0.192 110.568 ;
    END
  END mixes[216]
  PIN mixes[217]
    DIRECTION INPUT ;
    USE SIGNAL ;
    PORT
      LAYER M4 ;
        RECT 0.000 111.024 0.192 111.048 ;
    END
  END mixes[217]
  PIN mixes[218]
    DIRECTION INPUT ;
    USE SIGNAL ;
    PORT
      LAYER M4 ;
        RECT 0.000 111.552 0.192 111.576 ;
    END
  END mixes[218]
  PIN mixes[219]
    DIRECTION INPUT ;
    USE SIGNAL ;
    PORT
      LAYER M4 ;
        RECT 0.000 112.032 0.192 112.056 ;
    END
  END mixes[219]
  PIN mixes[220]
    DIRECTION INPUT ;
    USE SIGNAL ;
    PORT
      LAYER M4 ;
        RECT 0.000 112.512 0.192 112.536 ;
    END
  END mixes[220]
  PIN mixes[221]
    DIRECTION INPUT ;
    USE SIGNAL ;
    PORT
      LAYER M4 ;
        RECT 0.000 113.040 0.192 113.064 ;
    END
  END mixes[221]
  PIN mixes[222]
    DIRECTION INPUT ;
    USE SIGNAL ;
    PORT
      LAYER M4 ;
        RECT 0.000 113.520 0.192 113.544 ;
    END
  END mixes[222]
  PIN mixes[223]
    DIRECTION INPUT ;
    USE SIGNAL ;
    PORT
      LAYER M4 ;
        RECT 0.000 114.048 0.192 114.072 ;
    END
  END mixes[223]
  PIN mixes[224]
    DIRECTION INPUT ;
    USE SIGNAL ;
    PORT
      LAYER M4 ;
        RECT 0.000 114.528 0.192 114.552 ;
    END
  END mixes[224]
  PIN mixes[225]
    DIRECTION INPUT ;
    USE SIGNAL ;
    PORT
      LAYER M4 ;
        RECT 0.000 115.056 0.192 115.080 ;
    END
  END mixes[225]
  PIN mixes[226]
    DIRECTION INPUT ;
    USE SIGNAL ;
    PORT
      LAYER M4 ;
        RECT 0.000 115.536 0.192 115.560 ;
    END
  END mixes[226]
  PIN mixes[227]
    DIRECTION INPUT ;
    USE SIGNAL ;
    PORT
      LAYER M4 ;
        RECT 0.000 116.064 0.192 116.088 ;
    END
  END mixes[227]
  PIN mixes[228]
    DIRECTION INPUT ;
    USE SIGNAL ;
    PORT
      LAYER M4 ;
        RECT 0.000 116.544 0.192 116.568 ;
    END
  END mixes[228]
  PIN mixes[229]
    DIRECTION INPUT ;
    USE SIGNAL ;
    PORT
      LAYER M4 ;
        RECT 0.000 117.024 0.192 117.048 ;
    END
  END mixes[229]
  PIN mixes[230]
    DIRECTION INPUT ;
    USE SIGNAL ;
    PORT
      LAYER M4 ;
        RECT 0.000 117.552 0.192 117.576 ;
    END
  END mixes[230]
  PIN mixes[231]
    DIRECTION INPUT ;
    USE SIGNAL ;
    PORT
      LAYER M4 ;
        RECT 0.000 118.032 0.192 118.056 ;
    END
  END mixes[231]
  PIN mixes[232]
    DIRECTION INPUT ;
    USE SIGNAL ;
    PORT
      LAYER M4 ;
        RECT 0.000 118.560 0.192 118.584 ;
    END
  END mixes[232]
  PIN mixes[233]
    DIRECTION INPUT ;
    USE SIGNAL ;
    PORT
      LAYER M4 ;
        RECT 0.000 119.040 0.192 119.064 ;
    END
  END mixes[233]
  PIN mixes[234]
    DIRECTION INPUT ;
    USE SIGNAL ;
    PORT
      LAYER M4 ;
        RECT 0.000 119.568 0.192 119.592 ;
    END
  END mixes[234]
  PIN mixes[235]
    DIRECTION INPUT ;
    USE SIGNAL ;
    PORT
      LAYER M4 ;
        RECT 0.000 120.048 0.192 120.072 ;
    END
  END mixes[235]
  PIN mixes[236]
    DIRECTION INPUT ;
    USE SIGNAL ;
    PORT
      LAYER M4 ;
        RECT 0.000 120.528 0.192 120.552 ;
    END
  END mixes[236]
  PIN mixes[237]
    DIRECTION INPUT ;
    USE SIGNAL ;
    PORT
      LAYER M4 ;
        RECT 0.000 121.056 0.192 121.080 ;
    END
  END mixes[237]
  PIN mixes[238]
    DIRECTION INPUT ;
    USE SIGNAL ;
    PORT
      LAYER M4 ;
        RECT 0.000 121.536 0.192 121.560 ;
    END
  END mixes[238]
  PIN mixes[239]
    DIRECTION INPUT ;
    USE SIGNAL ;
    PORT
      LAYER M4 ;
        RECT 0.000 122.064 0.192 122.088 ;
    END
  END mixes[239]
  PIN mixes[240]
    DIRECTION INPUT ;
    USE SIGNAL ;
    PORT
      LAYER M4 ;
        RECT 0.000 122.544 0.192 122.568 ;
    END
  END mixes[240]
  PIN mixes[241]
    DIRECTION INPUT ;
    USE SIGNAL ;
    PORT
      LAYER M4 ;
        RECT 0.000 123.072 0.192 123.096 ;
    END
  END mixes[241]
  PIN mixes[242]
    DIRECTION INPUT ;
    USE SIGNAL ;
    PORT
      LAYER M4 ;
        RECT 0.000 123.552 0.192 123.576 ;
    END
  END mixes[242]
  PIN mixes[243]
    DIRECTION INPUT ;
    USE SIGNAL ;
    PORT
      LAYER M4 ;
        RECT 0.000 124.032 0.192 124.056 ;
    END
  END mixes[243]
  PIN mixes[244]
    DIRECTION INPUT ;
    USE SIGNAL ;
    PORT
      LAYER M4 ;
        RECT 0.000 124.560 0.192 124.584 ;
    END
  END mixes[244]
  PIN mixes[245]
    DIRECTION INPUT ;
    USE SIGNAL ;
    PORT
      LAYER M4 ;
        RECT 0.000 125.040 0.192 125.064 ;
    END
  END mixes[245]
  PIN mixes[246]
    DIRECTION INPUT ;
    USE SIGNAL ;
    PORT
      LAYER M4 ;
        RECT 0.000 125.568 0.192 125.592 ;
    END
  END mixes[246]
  PIN mixes[247]
    DIRECTION INPUT ;
    USE SIGNAL ;
    PORT
      LAYER M4 ;
        RECT 0.000 126.048 0.192 126.072 ;
    END
  END mixes[247]
  PIN mixes[248]
    DIRECTION INPUT ;
    USE SIGNAL ;
    PORT
      LAYER M4 ;
        RECT 0.000 126.576 0.192 126.600 ;
    END
  END mixes[248]
  PIN mixes[249]
    DIRECTION INPUT ;
    USE SIGNAL ;
    PORT
      LAYER M4 ;
        RECT 0.000 127.056 0.192 127.080 ;
    END
  END mixes[249]
  PIN mixes[250]
    DIRECTION INPUT ;
    USE SIGNAL ;
    PORT
      LAYER M4 ;
        RECT 0.000 127.536 0.192 127.560 ;
    END
  END mixes[250]
  PIN mixes[251]
    DIRECTION INPUT ;
    USE SIGNAL ;
    PORT
      LAYER M4 ;
        RECT 0.000 128.064 0.192 128.088 ;
    END
  END mixes[251]
  PIN mixes[252]
    DIRECTION INPUT ;
    USE SIGNAL ;
    PORT
      LAYER M4 ;
        RECT 0.000 128.544 0.192 128.568 ;
    END
  END mixes[252]
  PIN mixes[253]
    DIRECTION INPUT ;
    USE SIGNAL ;
    PORT
      LAYER M4 ;
        RECT 0.000 129.072 0.192 129.096 ;
    END
  END mixes[253]
  PIN mixes[254]
    DIRECTION INPUT ;
    USE SIGNAL ;
    PORT
      LAYER M4 ;
        RECT 0.000 129.552 0.192 129.576 ;
    END
  END mixes[254]
  PIN mixes[255]
    DIRECTION INPUT ;
    USE SIGNAL ;
    PORT
      LAYER M4 ;
        RECT 0.000 130.080 0.192 130.104 ;
    END
  END mixes[255]
  PIN mixes[256]
    DIRECTION INPUT ;
    USE SIGNAL ;
    PORT
      LAYER M4 ;
        RECT 0.000 130.560 0.192 130.584 ;
    END
  END mixes[256]
  PIN mixes[257]
    DIRECTION INPUT ;
    USE SIGNAL ;
    PORT
      LAYER M4 ;
        RECT 0.000 131.040 0.192 131.064 ;
    END
  END mixes[257]
  PIN mixes[258]
    DIRECTION INPUT ;
    USE SIGNAL ;
    PORT
      LAYER M4 ;
        RECT 0.000 131.568 0.192 131.592 ;
    END
  END mixes[258]
  PIN mixes[259]
    DIRECTION INPUT ;
    USE SIGNAL ;
    PORT
      LAYER M4 ;
        RECT 0.000 132.048 0.192 132.072 ;
    END
  END mixes[259]
  PIN mixes[260]
    DIRECTION INPUT ;
    USE SIGNAL ;
    PORT
      LAYER M4 ;
        RECT 0.000 132.576 0.192 132.600 ;
    END
  END mixes[260]
  PIN mixes[261]
    DIRECTION INPUT ;
    USE SIGNAL ;
    PORT
      LAYER M4 ;
        RECT 0.000 133.056 0.192 133.080 ;
    END
  END mixes[261]
  PIN mixes[262]
    DIRECTION INPUT ;
    USE SIGNAL ;
    PORT
      LAYER M4 ;
        RECT 0.000 133.584 0.192 133.608 ;
    END
  END mixes[262]
  PIN mixes[263]
    DIRECTION INPUT ;
    USE SIGNAL ;
    PORT
      LAYER M4 ;
        RECT 0.000 134.064 0.192 134.088 ;
    END
  END mixes[263]
  PIN mixes[264]
    DIRECTION INPUT ;
    USE SIGNAL ;
    PORT
      LAYER M4 ;
        RECT 0.000 134.544 0.192 134.568 ;
    END
  END mixes[264]
  PIN mixes[265]
    DIRECTION INPUT ;
    USE SIGNAL ;
    PORT
      LAYER M4 ;
        RECT 0.000 135.072 0.192 135.096 ;
    END
  END mixes[265]
  PIN mixes[266]
    DIRECTION INPUT ;
    USE SIGNAL ;
    PORT
      LAYER M4 ;
        RECT 0.000 135.552 0.192 135.576 ;
    END
  END mixes[266]
  PIN mixes[267]
    DIRECTION INPUT ;
    USE SIGNAL ;
    PORT
      LAYER M4 ;
        RECT 0.000 136.080 0.192 136.104 ;
    END
  END mixes[267]
  PIN mixes[268]
    DIRECTION INPUT ;
    USE SIGNAL ;
    PORT
      LAYER M4 ;
        RECT 0.000 136.560 0.192 136.584 ;
    END
  END mixes[268]
  PIN mixes[269]
    DIRECTION INPUT ;
    USE SIGNAL ;
    PORT
      LAYER M4 ;
        RECT 0.000 137.088 0.192 137.112 ;
    END
  END mixes[269]
  PIN mixes[270]
    DIRECTION INPUT ;
    USE SIGNAL ;
    PORT
      LAYER M4 ;
        RECT 0.000 137.568 0.192 137.592 ;
    END
  END mixes[270]
  PIN mixes[271]
    DIRECTION INPUT ;
    USE SIGNAL ;
    PORT
      LAYER M4 ;
        RECT 0.000 138.048 0.192 138.072 ;
    END
  END mixes[271]
  PIN mixes[272]
    DIRECTION INPUT ;
    USE SIGNAL ;
    PORT
      LAYER M4 ;
        RECT 0.000 138.576 0.192 138.600 ;
    END
  END mixes[272]
  PIN mixes[273]
    DIRECTION INPUT ;
    USE SIGNAL ;
    PORT
      LAYER M4 ;
        RECT 0.000 139.056 0.192 139.080 ;
    END
  END mixes[273]
  PIN mixes[274]
    DIRECTION INPUT ;
    USE SIGNAL ;
    PORT
      LAYER M4 ;
        RECT 0.000 139.584 0.192 139.608 ;
    END
  END mixes[274]
  PIN mixes[275]
    DIRECTION INPUT ;
    USE SIGNAL ;
    PORT
      LAYER M4 ;
        RECT 0.000 140.064 0.192 140.088 ;
    END
  END mixes[275]
  PIN mixes[276]
    DIRECTION INPUT ;
    USE SIGNAL ;
    PORT
      LAYER M4 ;
        RECT 0.000 140.592 0.192 140.616 ;
    END
  END mixes[276]
  PIN mixes[277]
    DIRECTION INPUT ;
    USE SIGNAL ;
    PORT
      LAYER M4 ;
        RECT 0.000 141.072 0.192 141.096 ;
    END
  END mixes[277]
  PIN mixes[278]
    DIRECTION INPUT ;
    USE SIGNAL ;
    PORT
      LAYER M4 ;
        RECT 0.000 141.552 0.192 141.576 ;
    END
  END mixes[278]
  PIN mixes[279]
    DIRECTION INPUT ;
    USE SIGNAL ;
    PORT
      LAYER M4 ;
        RECT 0.000 142.080 0.192 142.104 ;
    END
  END mixes[279]
  PIN mixes[280]
    DIRECTION INPUT ;
    USE SIGNAL ;
    PORT
      LAYER M4 ;
        RECT 0.000 142.560 0.192 142.584 ;
    END
  END mixes[280]
  PIN mixes[281]
    DIRECTION INPUT ;
    USE SIGNAL ;
    PORT
      LAYER M4 ;
        RECT 0.000 143.088 0.192 143.112 ;
    END
  END mixes[281]
  PIN mixes[282]
    DIRECTION INPUT ;
    USE SIGNAL ;
    PORT
      LAYER M4 ;
        RECT 0.000 143.568 0.192 143.592 ;
    END
  END mixes[282]
  PIN mixes[283]
    DIRECTION INPUT ;
    USE SIGNAL ;
    PORT
      LAYER M4 ;
        RECT 0.000 144.096 0.192 144.120 ;
    END
  END mixes[283]
  PIN mixes[284]
    DIRECTION INPUT ;
    USE SIGNAL ;
    PORT
      LAYER M4 ;
        RECT 0.000 144.576 0.192 144.600 ;
    END
  END mixes[284]
  PIN mixes[285]
    DIRECTION INPUT ;
    USE SIGNAL ;
    PORT
      LAYER M4 ;
        RECT 0.000 145.056 0.192 145.080 ;
    END
  END mixes[285]
  PIN mixes[286]
    DIRECTION INPUT ;
    USE SIGNAL ;
    PORT
      LAYER M4 ;
        RECT 0.000 145.584 0.192 145.608 ;
    END
  END mixes[286]
  PIN mixes[287]
    DIRECTION INPUT ;
    USE SIGNAL ;
    PORT
      LAYER M4 ;
        RECT 0.000 146.064 0.192 146.088 ;
    END
  END mixes[287]
  PIN mixes[288]
    DIRECTION INPUT ;
    USE SIGNAL ;
    PORT
      LAYER M4 ;
        RECT 0.000 146.592 0.192 146.616 ;
    END
  END mixes[288]
  PIN mixes[289]
    DIRECTION INPUT ;
    USE SIGNAL ;
    PORT
      LAYER M4 ;
        RECT 0.000 147.072 0.192 147.096 ;
    END
  END mixes[289]
  PIN mixes[290]
    DIRECTION INPUT ;
    USE SIGNAL ;
    PORT
      LAYER M4 ;
        RECT 0.000 147.600 0.192 147.624 ;
    END
  END mixes[290]
  PIN mixes[291]
    DIRECTION INPUT ;
    USE SIGNAL ;
    PORT
      LAYER M4 ;
        RECT 0.000 148.080 0.192 148.104 ;
    END
  END mixes[291]
  PIN mixes[292]
    DIRECTION INPUT ;
    USE SIGNAL ;
    PORT
      LAYER M4 ;
        RECT 0.000 148.560 0.192 148.584 ;
    END
  END mixes[292]
  PIN mixes[293]
    DIRECTION INPUT ;
    USE SIGNAL ;
    PORT
      LAYER M4 ;
        RECT 0.000 149.088 0.192 149.112 ;
    END
  END mixes[293]
  PIN mixes[294]
    DIRECTION INPUT ;
    USE SIGNAL ;
    PORT
      LAYER M4 ;
        RECT 0.000 149.568 0.192 149.592 ;
    END
  END mixes[294]
  PIN mixes[295]
    DIRECTION INPUT ;
    USE SIGNAL ;
    PORT
      LAYER M4 ;
        RECT 0.000 150.096 0.192 150.120 ;
    END
  END mixes[295]
  PIN mixes[296]
    DIRECTION INPUT ;
    USE SIGNAL ;
    PORT
      LAYER M4 ;
        RECT 0.000 150.576 0.192 150.600 ;
    END
  END mixes[296]
  PIN mixes[297]
    DIRECTION INPUT ;
    USE SIGNAL ;
    PORT
      LAYER M4 ;
        RECT 0.000 151.104 0.192 151.128 ;
    END
  END mixes[297]
  PIN mixes[298]
    DIRECTION INPUT ;
    USE SIGNAL ;
    PORT
      LAYER M4 ;
        RECT 0.000 151.584 0.192 151.608 ;
    END
  END mixes[298]
  PIN mixes[299]
    DIRECTION INPUT ;
    USE SIGNAL ;
    PORT
      LAYER M4 ;
        RECT 0.000 152.064 0.192 152.088 ;
    END
  END mixes[299]
  PIN mixes[300]
    DIRECTION INPUT ;
    USE SIGNAL ;
    PORT
      LAYER M4 ;
        RECT 0.000 152.592 0.192 152.616 ;
    END
  END mixes[300]
  PIN mixes[301]
    DIRECTION INPUT ;
    USE SIGNAL ;
    PORT
      LAYER M4 ;
        RECT 0.000 153.072 0.192 153.096 ;
    END
  END mixes[301]
  PIN mixes[302]
    DIRECTION INPUT ;
    USE SIGNAL ;
    PORT
      LAYER M4 ;
        RECT 0.000 153.600 0.192 153.624 ;
    END
  END mixes[302]
  PIN mixes[303]
    DIRECTION INPUT ;
    USE SIGNAL ;
    PORT
      LAYER M4 ;
        RECT 0.000 154.080 0.192 154.104 ;
    END
  END mixes[303]
  PIN mixes[304]
    DIRECTION INPUT ;
    USE SIGNAL ;
    PORT
      LAYER M4 ;
        RECT 0.000 154.608 0.192 154.632 ;
    END
  END mixes[304]
  PIN mixes[305]
    DIRECTION INPUT ;
    USE SIGNAL ;
    PORT
      LAYER M4 ;
        RECT 0.000 155.088 0.192 155.112 ;
    END
  END mixes[305]
  PIN mixes[306]
    DIRECTION INPUT ;
    USE SIGNAL ;
    PORT
      LAYER M4 ;
        RECT 0.000 155.568 0.192 155.592 ;
    END
  END mixes[306]
  PIN mixes[307]
    DIRECTION INPUT ;
    USE SIGNAL ;
    PORT
      LAYER M4 ;
        RECT 0.000 156.096 0.192 156.120 ;
    END
  END mixes[307]
  PIN mixes[308]
    DIRECTION INPUT ;
    USE SIGNAL ;
    PORT
      LAYER M4 ;
        RECT 0.000 156.576 0.192 156.600 ;
    END
  END mixes[308]
  PIN mixes[309]
    DIRECTION INPUT ;
    USE SIGNAL ;
    PORT
      LAYER M4 ;
        RECT 0.000 157.104 0.192 157.128 ;
    END
  END mixes[309]
  PIN mixes[310]
    DIRECTION INPUT ;
    USE SIGNAL ;
    PORT
      LAYER M4 ;
        RECT 0.000 157.584 0.192 157.608 ;
    END
  END mixes[310]
  PIN mixes[311]
    DIRECTION INPUT ;
    USE SIGNAL ;
    PORT
      LAYER M4 ;
        RECT 0.000 158.112 0.192 158.136 ;
    END
  END mixes[311]
  PIN mixes[312]
    DIRECTION INPUT ;
    USE SIGNAL ;
    PORT
      LAYER M4 ;
        RECT 0.000 158.592 0.192 158.616 ;
    END
  END mixes[312]
  PIN mixes[313]
    DIRECTION INPUT ;
    USE SIGNAL ;
    PORT
      LAYER M4 ;
        RECT 0.000 159.072 0.192 159.096 ;
    END
  END mixes[313]
  PIN mixes[314]
    DIRECTION INPUT ;
    USE SIGNAL ;
    PORT
      LAYER M4 ;
        RECT 0.000 159.600 0.192 159.624 ;
    END
  END mixes[314]
  PIN mixes[315]
    DIRECTION INPUT ;
    USE SIGNAL ;
    PORT
      LAYER M4 ;
        RECT 0.000 160.080 0.192 160.104 ;
    END
  END mixes[315]
  PIN mixes[316]
    DIRECTION INPUT ;
    USE SIGNAL ;
    PORT
      LAYER M4 ;
        RECT 0.000 160.608 0.192 160.632 ;
    END
  END mixes[316]
  PIN mixes[317]
    DIRECTION INPUT ;
    USE SIGNAL ;
    PORT
      LAYER M4 ;
        RECT 0.000 161.088 0.192 161.112 ;
    END
  END mixes[317]
  PIN mixes[318]
    DIRECTION INPUT ;
    USE SIGNAL ;
    PORT
      LAYER M4 ;
        RECT 0.000 161.616 0.192 161.640 ;
    END
  END mixes[318]
  PIN mixes[319]
    DIRECTION INPUT ;
    USE SIGNAL ;
    PORT
      LAYER M4 ;
        RECT 0.000 162.096 0.192 162.120 ;
    END
  END mixes[319]
  PIN mixes[320]
    DIRECTION INPUT ;
    USE SIGNAL ;
    PORT
      LAYER M4 ;
        RECT 0.000 162.576 0.192 162.600 ;
    END
  END mixes[320]
  PIN mixes[321]
    DIRECTION INPUT ;
    USE SIGNAL ;
    PORT
      LAYER M4 ;
        RECT 0.000 163.104 0.192 163.128 ;
    END
  END mixes[321]
  PIN mixes[322]
    DIRECTION INPUT ;
    USE SIGNAL ;
    PORT
      LAYER M4 ;
        RECT 0.000 163.584 0.192 163.608 ;
    END
  END mixes[322]
  PIN mixes[323]
    DIRECTION INPUT ;
    USE SIGNAL ;
    PORT
      LAYER M4 ;
        RECT 0.000 164.112 0.192 164.136 ;
    END
  END mixes[323]
  PIN mixes[324]
    DIRECTION INPUT ;
    USE SIGNAL ;
    PORT
      LAYER M4 ;
        RECT 0.000 164.592 0.192 164.616 ;
    END
  END mixes[324]
  PIN mixes[325]
    DIRECTION INPUT ;
    USE SIGNAL ;
    PORT
      LAYER M4 ;
        RECT 0.000 165.120 0.192 165.144 ;
    END
  END mixes[325]
  PIN mixes[326]
    DIRECTION INPUT ;
    USE SIGNAL ;
    PORT
      LAYER M4 ;
        RECT 0.000 165.600 0.192 165.624 ;
    END
  END mixes[326]
  PIN mixes[327]
    DIRECTION INPUT ;
    USE SIGNAL ;
    PORT
      LAYER M4 ;
        RECT 0.000 166.080 0.192 166.104 ;
    END
  END mixes[327]
  PIN mixes[328]
    DIRECTION INPUT ;
    USE SIGNAL ;
    PORT
      LAYER M4 ;
        RECT 0.000 166.608 0.192 166.632 ;
    END
  END mixes[328]
  PIN mixes[329]
    DIRECTION INPUT ;
    USE SIGNAL ;
    PORT
      LAYER M4 ;
        RECT 0.000 167.088 0.192 167.112 ;
    END
  END mixes[329]
  PIN mixes[330]
    DIRECTION INPUT ;
    USE SIGNAL ;
    PORT
      LAYER M4 ;
        RECT 0.000 167.616 0.192 167.640 ;
    END
  END mixes[330]
  PIN mixes[331]
    DIRECTION INPUT ;
    USE SIGNAL ;
    PORT
      LAYER M4 ;
        RECT 0.000 168.096 0.192 168.120 ;
    END
  END mixes[331]
  PIN mixes[332]
    DIRECTION INPUT ;
    USE SIGNAL ;
    PORT
      LAYER M4 ;
        RECT 0.000 168.624 0.192 168.648 ;
    END
  END mixes[332]
  PIN mixes[333]
    DIRECTION INPUT ;
    USE SIGNAL ;
    PORT
      LAYER M4 ;
        RECT 0.000 169.104 0.192 169.128 ;
    END
  END mixes[333]
  PIN mixes[334]
    DIRECTION INPUT ;
    USE SIGNAL ;
    PORT
      LAYER M4 ;
        RECT 0.000 169.584 0.192 169.608 ;
    END
  END mixes[334]
  PIN mixes[335]
    DIRECTION INPUT ;
    USE SIGNAL ;
    PORT
      LAYER M4 ;
        RECT 0.000 170.112 0.192 170.136 ;
    END
  END mixes[335]
  PIN mixes[336]
    DIRECTION INPUT ;
    USE SIGNAL ;
    PORT
      LAYER M4 ;
        RECT 0.000 170.592 0.192 170.616 ;
    END
  END mixes[336]
  PIN mixes[337]
    DIRECTION INPUT ;
    USE SIGNAL ;
    PORT
      LAYER M4 ;
        RECT 0.000 171.120 0.192 171.144 ;
    END
  END mixes[337]
  PIN mixes[338]
    DIRECTION INPUT ;
    USE SIGNAL ;
    PORT
      LAYER M4 ;
        RECT 0.000 171.600 0.192 171.624 ;
    END
  END mixes[338]
  PIN mixes[339]
    DIRECTION INPUT ;
    USE SIGNAL ;
    PORT
      LAYER M4 ;
        RECT 0.000 172.128 0.192 172.152 ;
    END
  END mixes[339]
  PIN mixes[340]
    DIRECTION INPUT ;
    USE SIGNAL ;
    PORT
      LAYER M4 ;
        RECT 0.000 172.608 0.192 172.632 ;
    END
  END mixes[340]
  PIN mixes[341]
    DIRECTION INPUT ;
    USE SIGNAL ;
    PORT
      LAYER M4 ;
        RECT 0.000 173.088 0.192 173.112 ;
    END
  END mixes[341]
  PIN mixes[342]
    DIRECTION INPUT ;
    USE SIGNAL ;
    PORT
      LAYER M4 ;
        RECT 0.000 173.616 0.192 173.640 ;
    END
  END mixes[342]
  PIN mixes[343]
    DIRECTION INPUT ;
    USE SIGNAL ;
    PORT
      LAYER M4 ;
        RECT 0.000 174.096 0.192 174.120 ;
    END
  END mixes[343]
  PIN mixes[344]
    DIRECTION INPUT ;
    USE SIGNAL ;
    PORT
      LAYER M4 ;
        RECT 0.000 174.624 0.192 174.648 ;
    END
  END mixes[344]
  PIN mixes[345]
    DIRECTION INPUT ;
    USE SIGNAL ;
    PORT
      LAYER M4 ;
        RECT 0.000 175.104 0.192 175.128 ;
    END
  END mixes[345]
  PIN mixes[346]
    DIRECTION INPUT ;
    USE SIGNAL ;
    PORT
      LAYER M4 ;
        RECT 0.000 175.632 0.192 175.656 ;
    END
  END mixes[346]
  PIN mixes[347]
    DIRECTION INPUT ;
    USE SIGNAL ;
    PORT
      LAYER M4 ;
        RECT 0.000 176.112 0.192 176.136 ;
    END
  END mixes[347]
  PIN mixes[348]
    DIRECTION INPUT ;
    USE SIGNAL ;
    PORT
      LAYER M4 ;
        RECT 0.000 176.592 0.192 176.616 ;
    END
  END mixes[348]
  PIN mixes[349]
    DIRECTION INPUT ;
    USE SIGNAL ;
    PORT
      LAYER M4 ;
        RECT 0.000 177.120 0.192 177.144 ;
    END
  END mixes[349]
  PIN mixes[350]
    DIRECTION INPUT ;
    USE SIGNAL ;
    PORT
      LAYER M4 ;
        RECT 0.000 177.600 0.192 177.624 ;
    END
  END mixes[350]
  PIN mixes[351]
    DIRECTION INPUT ;
    USE SIGNAL ;
    PORT
      LAYER M4 ;
        RECT 0.000 178.128 0.192 178.152 ;
    END
  END mixes[351]
  PIN mixes[352]
    DIRECTION INPUT ;
    USE SIGNAL ;
    PORT
      LAYER M4 ;
        RECT 0.000 178.608 0.192 178.632 ;
    END
  END mixes[352]
  PIN mixes[353]
    DIRECTION INPUT ;
    USE SIGNAL ;
    PORT
      LAYER M4 ;
        RECT 0.000 179.136 0.192 179.160 ;
    END
  END mixes[353]
  PIN mixes[354]
    DIRECTION INPUT ;
    USE SIGNAL ;
    PORT
      LAYER M4 ;
        RECT 0.000 179.616 0.192 179.640 ;
    END
  END mixes[354]
  PIN mixes[355]
    DIRECTION INPUT ;
    USE SIGNAL ;
    PORT
      LAYER M4 ;
        RECT 0.000 180.144 0.192 180.168 ;
    END
  END mixes[355]
  PIN mixes[356]
    DIRECTION INPUT ;
    USE SIGNAL ;
    PORT
      LAYER M4 ;
        RECT 0.000 180.624 0.192 180.648 ;
    END
  END mixes[356]
  PIN mixes[357]
    DIRECTION INPUT ;
    USE SIGNAL ;
    PORT
      LAYER M4 ;
        RECT 0.000 181.104 0.192 181.128 ;
    END
  END mixes[357]
  PIN mixes[358]
    DIRECTION INPUT ;
    USE SIGNAL ;
    PORT
      LAYER M4 ;
        RECT 0.000 181.632 0.192 181.656 ;
    END
  END mixes[358]
  PIN mixes[359]
    DIRECTION INPUT ;
    USE SIGNAL ;
    PORT
      LAYER M4 ;
        RECT 0.000 182.112 0.192 182.136 ;
    END
  END mixes[359]
  PIN mixes[360]
    DIRECTION INPUT ;
    USE SIGNAL ;
    PORT
      LAYER M4 ;
        RECT 0.000 182.640 0.192 182.664 ;
    END
  END mixes[360]
  PIN mixes[361]
    DIRECTION INPUT ;
    USE SIGNAL ;
    PORT
      LAYER M4 ;
        RECT 0.000 183.120 0.192 183.144 ;
    END
  END mixes[361]
  PIN mixes[362]
    DIRECTION INPUT ;
    USE SIGNAL ;
    PORT
      LAYER M4 ;
        RECT 0.000 183.648 0.192 183.672 ;
    END
  END mixes[362]
  PIN mixes[363]
    DIRECTION INPUT ;
    USE SIGNAL ;
    PORT
      LAYER M4 ;
        RECT 0.000 184.128 0.192 184.152 ;
    END
  END mixes[363]
  PIN mixes[364]
    DIRECTION INPUT ;
    USE SIGNAL ;
    PORT
      LAYER M4 ;
        RECT 0.000 184.608 0.192 184.632 ;
    END
  END mixes[364]
  PIN mixes[365]
    DIRECTION INPUT ;
    USE SIGNAL ;
    PORT
      LAYER M4 ;
        RECT 0.000 185.136 0.192 185.160 ;
    END
  END mixes[365]
  PIN mixes[366]
    DIRECTION INPUT ;
    USE SIGNAL ;
    PORT
      LAYER M4 ;
        RECT 0.000 185.616 0.192 185.640 ;
    END
  END mixes[366]
  PIN mixes[367]
    DIRECTION INPUT ;
    USE SIGNAL ;
    PORT
      LAYER M4 ;
        RECT 0.000 186.144 0.192 186.168 ;
    END
  END mixes[367]
  PIN mixes[368]
    DIRECTION INPUT ;
    USE SIGNAL ;
    PORT
      LAYER M4 ;
        RECT 0.000 186.624 0.192 186.648 ;
    END
  END mixes[368]
  PIN mixes[369]
    DIRECTION INPUT ;
    USE SIGNAL ;
    PORT
      LAYER M4 ;
        RECT 0.000 187.152 0.192 187.176 ;
    END
  END mixes[369]
  PIN mixes[370]
    DIRECTION INPUT ;
    USE SIGNAL ;
    PORT
      LAYER M4 ;
        RECT 0.000 187.632 0.192 187.656 ;
    END
  END mixes[370]
  PIN mixes[371]
    DIRECTION INPUT ;
    USE SIGNAL ;
    PORT
      LAYER M4 ;
        RECT 0.000 188.112 0.192 188.136 ;
    END
  END mixes[371]
  PIN mixes[372]
    DIRECTION INPUT ;
    USE SIGNAL ;
    PORT
      LAYER M4 ;
        RECT 0.000 188.640 0.192 188.664 ;
    END
  END mixes[372]
  PIN mixes[373]
    DIRECTION INPUT ;
    USE SIGNAL ;
    PORT
      LAYER M4 ;
        RECT 0.000 189.120 0.192 189.144 ;
    END
  END mixes[373]
  PIN mixes[374]
    DIRECTION INPUT ;
    USE SIGNAL ;
    PORT
      LAYER M4 ;
        RECT 0.000 189.648 0.192 189.672 ;
    END
  END mixes[374]
  PIN mixes[375]
    DIRECTION INPUT ;
    USE SIGNAL ;
    PORT
      LAYER M4 ;
        RECT 0.000 190.128 0.192 190.152 ;
    END
  END mixes[375]
  PIN mixes[376]
    DIRECTION INPUT ;
    USE SIGNAL ;
    PORT
      LAYER M4 ;
        RECT 0.000 190.656 0.192 190.680 ;
    END
  END mixes[376]
  PIN mixes[377]
    DIRECTION INPUT ;
    USE SIGNAL ;
    PORT
      LAYER M4 ;
        RECT 0.000 191.136 0.192 191.160 ;
    END
  END mixes[377]
  PIN mixes[378]
    DIRECTION INPUT ;
    USE SIGNAL ;
    PORT
      LAYER M4 ;
        RECT 0.000 191.616 0.192 191.640 ;
    END
  END mixes[378]
  PIN mixes[379]
    DIRECTION INPUT ;
    USE SIGNAL ;
    PORT
      LAYER M4 ;
        RECT 0.000 192.144 0.192 192.168 ;
    END
  END mixes[379]
  PIN mixes[380]
    DIRECTION INPUT ;
    USE SIGNAL ;
    PORT
      LAYER M4 ;
        RECT 0.000 192.624 0.192 192.648 ;
    END
  END mixes[380]
  PIN mixes[381]
    DIRECTION INPUT ;
    USE SIGNAL ;
    PORT
      LAYER M4 ;
        RECT 0.000 193.152 0.192 193.176 ;
    END
  END mixes[381]
  PIN mixes[382]
    DIRECTION INPUT ;
    USE SIGNAL ;
    PORT
      LAYER M4 ;
        RECT 0.000 193.632 0.192 193.656 ;
    END
  END mixes[382]
  PIN mixes[383]
    DIRECTION INPUT ;
    USE SIGNAL ;
    PORT
      LAYER M4 ;
        RECT 0.000 194.160 0.192 194.184 ;
    END
  END mixes[383]
  PIN mixes[384]
    DIRECTION INPUT ;
    USE SIGNAL ;
    PORT
      LAYER M4 ;
        RECT 0.000 194.640 0.192 194.664 ;
    END
  END mixes[384]
  PIN mixes[385]
    DIRECTION INPUT ;
    USE SIGNAL ;
    PORT
      LAYER M4 ;
        RECT 0.000 195.120 0.192 195.144 ;
    END
  END mixes[385]
  PIN mixes[386]
    DIRECTION INPUT ;
    USE SIGNAL ;
    PORT
      LAYER M4 ;
        RECT 0.000 195.648 0.192 195.672 ;
    END
  END mixes[386]
  PIN mixes[387]
    DIRECTION INPUT ;
    USE SIGNAL ;
    PORT
      LAYER M4 ;
        RECT 0.000 196.128 0.192 196.152 ;
    END
  END mixes[387]
  PIN mixes[388]
    DIRECTION INPUT ;
    USE SIGNAL ;
    PORT
      LAYER M4 ;
        RECT 0.000 196.656 0.192 196.680 ;
    END
  END mixes[388]
  PIN mixes[389]
    DIRECTION INPUT ;
    USE SIGNAL ;
    PORT
      LAYER M4 ;
        RECT 0.000 197.136 0.192 197.160 ;
    END
  END mixes[389]
  PIN mixes[390]
    DIRECTION INPUT ;
    USE SIGNAL ;
    PORT
      LAYER M4 ;
        RECT 0.000 197.664 0.192 197.688 ;
    END
  END mixes[390]
  PIN mixes[391]
    DIRECTION INPUT ;
    USE SIGNAL ;
    PORT
      LAYER M4 ;
        RECT 0.000 198.144 0.192 198.168 ;
    END
  END mixes[391]
  PIN mixes[392]
    DIRECTION INPUT ;
    USE SIGNAL ;
    PORT
      LAYER M4 ;
        RECT 0.000 198.624 0.192 198.648 ;
    END
  END mixes[392]
  PIN mixes[393]
    DIRECTION INPUT ;
    USE SIGNAL ;
    PORT
      LAYER M4 ;
        RECT 0.000 199.152 0.192 199.176 ;
    END
  END mixes[393]
  PIN mixes[394]
    DIRECTION INPUT ;
    USE SIGNAL ;
    PORT
      LAYER M4 ;
        RECT 0.000 199.632 0.192 199.656 ;
    END
  END mixes[394]
  PIN mixes[395]
    DIRECTION INPUT ;
    USE SIGNAL ;
    PORT
      LAYER M4 ;
        RECT 0.000 200.160 0.192 200.184 ;
    END
  END mixes[395]
  PIN mixes[396]
    DIRECTION INPUT ;
    USE SIGNAL ;
    PORT
      LAYER M4 ;
        RECT 0.000 200.640 0.192 200.664 ;
    END
  END mixes[396]
  PIN mixes[397]
    DIRECTION INPUT ;
    USE SIGNAL ;
    PORT
      LAYER M4 ;
        RECT 0.000 201.168 0.192 201.192 ;
    END
  END mixes[397]
  PIN mixes[398]
    DIRECTION INPUT ;
    USE SIGNAL ;
    PORT
      LAYER M4 ;
        RECT 0.000 201.648 0.192 201.672 ;
    END
  END mixes[398]
  PIN mixes[399]
    DIRECTION INPUT ;
    USE SIGNAL ;
    PORT
      LAYER M4 ;
        RECT 0.000 202.128 0.192 202.152 ;
    END
  END mixes[399]
  PIN mixes[400]
    DIRECTION INPUT ;
    USE SIGNAL ;
    PORT
      LAYER M4 ;
        RECT 0.000 202.656 0.192 202.680 ;
    END
  END mixes[400]
  PIN mixes[401]
    DIRECTION INPUT ;
    USE SIGNAL ;
    PORT
      LAYER M4 ;
        RECT 0.000 203.136 0.192 203.160 ;
    END
  END mixes[401]
  PIN mixes[402]
    DIRECTION INPUT ;
    USE SIGNAL ;
    PORT
      LAYER M4 ;
        RECT 0.000 203.664 0.192 203.688 ;
    END
  END mixes[402]
  PIN mixes[403]
    DIRECTION INPUT ;
    USE SIGNAL ;
    PORT
      LAYER M4 ;
        RECT 0.000 204.144 0.192 204.168 ;
    END
  END mixes[403]
  PIN mixes[404]
    DIRECTION INPUT ;
    USE SIGNAL ;
    PORT
      LAYER M4 ;
        RECT 0.000 204.672 0.192 204.696 ;
    END
  END mixes[404]
  PIN mixes[405]
    DIRECTION INPUT ;
    USE SIGNAL ;
    PORT
      LAYER M4 ;
        RECT 0.000 205.152 0.192 205.176 ;
    END
  END mixes[405]
  PIN mixes[406]
    DIRECTION INPUT ;
    USE SIGNAL ;
    PORT
      LAYER M4 ;
        RECT 0.000 205.632 0.192 205.656 ;
    END
  END mixes[406]
  PIN mixes[407]
    DIRECTION INPUT ;
    USE SIGNAL ;
    PORT
      LAYER M4 ;
        RECT 0.000 206.160 0.192 206.184 ;
    END
  END mixes[407]
  PIN mixes[408]
    DIRECTION INPUT ;
    USE SIGNAL ;
    PORT
      LAYER M4 ;
        RECT 0.000 206.640 0.192 206.664 ;
    END
  END mixes[408]
  PIN mixes[409]
    DIRECTION INPUT ;
    USE SIGNAL ;
    PORT
      LAYER M4 ;
        RECT 0.000 207.168 0.192 207.192 ;
    END
  END mixes[409]
  PIN mixes[410]
    DIRECTION INPUT ;
    USE SIGNAL ;
    PORT
      LAYER M4 ;
        RECT 0.000 207.648 0.192 207.672 ;
    END
  END mixes[410]
  PIN mixes[411]
    DIRECTION INPUT ;
    USE SIGNAL ;
    PORT
      LAYER M4 ;
        RECT 0.000 208.176 0.192 208.200 ;
    END
  END mixes[411]
  PIN mixes[412]
    DIRECTION INPUT ;
    USE SIGNAL ;
    PORT
      LAYER M4 ;
        RECT 0.000 208.656 0.192 208.680 ;
    END
  END mixes[412]
  PIN mixes[413]
    DIRECTION INPUT ;
    USE SIGNAL ;
    PORT
      LAYER M4 ;
        RECT 0.000 209.136 0.192 209.160 ;
    END
  END mixes[413]
  PIN mixes[414]
    DIRECTION INPUT ;
    USE SIGNAL ;
    PORT
      LAYER M4 ;
        RECT 0.000 209.664 0.192 209.688 ;
    END
  END mixes[414]
  PIN mixes[415]
    DIRECTION INPUT ;
    USE SIGNAL ;
    PORT
      LAYER M4 ;
        RECT 0.000 210.144 0.192 210.168 ;
    END
  END mixes[415]
  PIN mixes[416]
    DIRECTION INPUT ;
    USE SIGNAL ;
    PORT
      LAYER M4 ;
        RECT 0.000 210.672 0.192 210.696 ;
    END
  END mixes[416]
  PIN mixes[417]
    DIRECTION INPUT ;
    USE SIGNAL ;
    PORT
      LAYER M4 ;
        RECT 0.000 211.152 0.192 211.176 ;
    END
  END mixes[417]
  PIN mixes[418]
    DIRECTION INPUT ;
    USE SIGNAL ;
    PORT
      LAYER M4 ;
        RECT 0.000 211.680 0.192 211.704 ;
    END
  END mixes[418]
  PIN mixes[419]
    DIRECTION INPUT ;
    USE SIGNAL ;
    PORT
      LAYER M4 ;
        RECT 0.000 212.160 0.192 212.184 ;
    END
  END mixes[419]
  PIN mixes[420]
    DIRECTION INPUT ;
    USE SIGNAL ;
    PORT
      LAYER M4 ;
        RECT 0.000 212.640 0.192 212.664 ;
    END
  END mixes[420]
  PIN mixes[421]
    DIRECTION INPUT ;
    USE SIGNAL ;
    PORT
      LAYER M4 ;
        RECT 0.000 213.168 0.192 213.192 ;
    END
  END mixes[421]
  PIN mixes[422]
    DIRECTION INPUT ;
    USE SIGNAL ;
    PORT
      LAYER M4 ;
        RECT 0.000 213.648 0.192 213.672 ;
    END
  END mixes[422]
  PIN mixes[423]
    DIRECTION INPUT ;
    USE SIGNAL ;
    PORT
      LAYER M4 ;
        RECT 0.000 214.176 0.192 214.200 ;
    END
  END mixes[423]
  PIN mixes[424]
    DIRECTION INPUT ;
    USE SIGNAL ;
    PORT
      LAYER M4 ;
        RECT 0.000 214.656 0.192 214.680 ;
    END
  END mixes[424]
  PIN mixes[425]
    DIRECTION INPUT ;
    USE SIGNAL ;
    PORT
      LAYER M4 ;
        RECT 0.000 215.184 0.192 215.208 ;
    END
  END mixes[425]
  PIN mixes[426]
    DIRECTION INPUT ;
    USE SIGNAL ;
    PORT
      LAYER M4 ;
        RECT 0.000 215.664 0.192 215.688 ;
    END
  END mixes[426]
  PIN mixes[427]
    DIRECTION INPUT ;
    USE SIGNAL ;
    PORT
      LAYER M4 ;
        RECT 0.000 216.144 0.192 216.168 ;
    END
  END mixes[427]
  PIN mixes[428]
    DIRECTION INPUT ;
    USE SIGNAL ;
    PORT
      LAYER M4 ;
        RECT 0.000 216.672 0.192 216.696 ;
    END
  END mixes[428]
  PIN mixes[429]
    DIRECTION INPUT ;
    USE SIGNAL ;
    PORT
      LAYER M4 ;
        RECT 0.000 217.152 0.192 217.176 ;
    END
  END mixes[429]
  PIN mixes[430]
    DIRECTION INPUT ;
    USE SIGNAL ;
    PORT
      LAYER M4 ;
        RECT 0.000 217.680 0.192 217.704 ;
    END
  END mixes[430]
  PIN mixes[431]
    DIRECTION INPUT ;
    USE SIGNAL ;
    PORT
      LAYER M4 ;
        RECT 0.000 218.160 0.192 218.184 ;
    END
  END mixes[431]
  PIN mixes[432]
    DIRECTION INPUT ;
    USE SIGNAL ;
    PORT
      LAYER M4 ;
        RECT 0.000 218.688 0.192 218.712 ;
    END
  END mixes[432]
  PIN mixes[433]
    DIRECTION INPUT ;
    USE SIGNAL ;
    PORT
      LAYER M4 ;
        RECT 0.000 219.168 0.192 219.192 ;
    END
  END mixes[433]
  PIN mixes[434]
    DIRECTION INPUT ;
    USE SIGNAL ;
    PORT
      LAYER M4 ;
        RECT 0.000 219.648 0.192 219.672 ;
    END
  END mixes[434]
  PIN mixes[435]
    DIRECTION INPUT ;
    USE SIGNAL ;
    PORT
      LAYER M4 ;
        RECT 0.000 220.176 0.192 220.200 ;
    END
  END mixes[435]
  PIN mixes[436]
    DIRECTION INPUT ;
    USE SIGNAL ;
    PORT
      LAYER M4 ;
        RECT 0.000 220.656 0.192 220.680 ;
    END
  END mixes[436]
  PIN mixes[437]
    DIRECTION INPUT ;
    USE SIGNAL ;
    PORT
      LAYER M4 ;
        RECT 0.000 221.184 0.192 221.208 ;
    END
  END mixes[437]
  PIN mixes[438]
    DIRECTION INPUT ;
    USE SIGNAL ;
    PORT
      LAYER M4 ;
        RECT 0.000 221.664 0.192 221.688 ;
    END
  END mixes[438]
  PIN mixes[439]
    DIRECTION INPUT ;
    USE SIGNAL ;
    PORT
      LAYER M4 ;
        RECT 0.000 222.192 0.192 222.216 ;
    END
  END mixes[439]
  PIN mixes[440]
    DIRECTION INPUT ;
    USE SIGNAL ;
    PORT
      LAYER M4 ;
        RECT 0.000 222.672 0.192 222.696 ;
    END
  END mixes[440]
  PIN mixes[441]
    DIRECTION INPUT ;
    USE SIGNAL ;
    PORT
      LAYER M4 ;
        RECT 0.000 223.152 0.192 223.176 ;
    END
  END mixes[441]
  PIN mixes[442]
    DIRECTION INPUT ;
    USE SIGNAL ;
    PORT
      LAYER M4 ;
        RECT 0.000 223.680 0.192 223.704 ;
    END
  END mixes[442]
  PIN mixes[443]
    DIRECTION INPUT ;
    USE SIGNAL ;
    PORT
      LAYER M4 ;
        RECT 0.000 224.160 0.192 224.184 ;
    END
  END mixes[443]
  PIN mixes[444]
    DIRECTION INPUT ;
    USE SIGNAL ;
    PORT
      LAYER M4 ;
        RECT 0.000 224.688 0.192 224.712 ;
    END
  END mixes[444]
  PIN mixes[445]
    DIRECTION INPUT ;
    USE SIGNAL ;
    PORT
      LAYER M4 ;
        RECT 0.000 225.168 0.192 225.192 ;
    END
  END mixes[445]
  PIN mixes[446]
    DIRECTION INPUT ;
    USE SIGNAL ;
    PORT
      LAYER M4 ;
        RECT 0.000 225.696 0.192 225.720 ;
    END
  END mixes[446]
  PIN mixes[447]
    DIRECTION INPUT ;
    USE SIGNAL ;
    PORT
      LAYER M4 ;
        RECT 0.000 226.176 0.192 226.200 ;
    END
  END mixes[447]
  PIN mixes[448]
    DIRECTION INPUT ;
    USE SIGNAL ;
    PORT
      LAYER M4 ;
        RECT 0.000 226.656 0.192 226.680 ;
    END
  END mixes[448]
  PIN mixes[449]
    DIRECTION INPUT ;
    USE SIGNAL ;
    PORT
      LAYER M4 ;
        RECT 0.000 227.184 0.192 227.208 ;
    END
  END mixes[449]
  PIN mixes[450]
    DIRECTION INPUT ;
    USE SIGNAL ;
    PORT
      LAYER M4 ;
        RECT 0.000 227.664 0.192 227.688 ;
    END
  END mixes[450]
  PIN mixes[451]
    DIRECTION INPUT ;
    USE SIGNAL ;
    PORT
      LAYER M4 ;
        RECT 0.000 228.192 0.192 228.216 ;
    END
  END mixes[451]
  PIN mixes[452]
    DIRECTION INPUT ;
    USE SIGNAL ;
    PORT
      LAYER M4 ;
        RECT 0.000 228.672 0.192 228.696 ;
    END
  END mixes[452]
  PIN mixes[453]
    DIRECTION INPUT ;
    USE SIGNAL ;
    PORT
      LAYER M4 ;
        RECT 0.000 229.200 0.192 229.224 ;
    END
  END mixes[453]
  PIN mixes[454]
    DIRECTION INPUT ;
    USE SIGNAL ;
    PORT
      LAYER M4 ;
        RECT 0.000 229.680 0.192 229.704 ;
    END
  END mixes[454]
  PIN mixes[455]
    DIRECTION INPUT ;
    USE SIGNAL ;
    PORT
      LAYER M4 ;
        RECT 0.000 230.160 0.192 230.184 ;
    END
  END mixes[455]
  PIN mixes[456]
    DIRECTION INPUT ;
    USE SIGNAL ;
    PORT
      LAYER M4 ;
        RECT 0.000 230.688 0.192 230.712 ;
    END
  END mixes[456]
  PIN mixes[457]
    DIRECTION INPUT ;
    USE SIGNAL ;
    PORT
      LAYER M4 ;
        RECT 0.000 231.168 0.192 231.192 ;
    END
  END mixes[457]
  PIN mixes[458]
    DIRECTION INPUT ;
    USE SIGNAL ;
    PORT
      LAYER M4 ;
        RECT 0.000 231.696 0.192 231.720 ;
    END
  END mixes[458]
  PIN mixes[459]
    DIRECTION INPUT ;
    USE SIGNAL ;
    PORT
      LAYER M4 ;
        RECT 0.000 232.176 0.192 232.200 ;
    END
  END mixes[459]
  PIN mixes[460]
    DIRECTION INPUT ;
    USE SIGNAL ;
    PORT
      LAYER M4 ;
        RECT 0.000 232.704 0.192 232.728 ;
    END
  END mixes[460]
  PIN mixes[461]
    DIRECTION INPUT ;
    USE SIGNAL ;
    PORT
      LAYER M4 ;
        RECT 0.000 233.184 0.192 233.208 ;
    END
  END mixes[461]
  PIN mixes[462]
    DIRECTION INPUT ;
    USE SIGNAL ;
    PORT
      LAYER M4 ;
        RECT 0.000 233.664 0.192 233.688 ;
    END
  END mixes[462]
  PIN mixes[463]
    DIRECTION INPUT ;
    USE SIGNAL ;
    PORT
      LAYER M4 ;
        RECT 0.000 234.192 0.192 234.216 ;
    END
  END mixes[463]
  PIN mixes[464]
    DIRECTION INPUT ;
    USE SIGNAL ;
    PORT
      LAYER M4 ;
        RECT 0.000 234.672 0.192 234.696 ;
    END
  END mixes[464]
  PIN mixes[465]
    DIRECTION INPUT ;
    USE SIGNAL ;
    PORT
      LAYER M4 ;
        RECT 0.000 235.200 0.192 235.224 ;
    END
  END mixes[465]
  PIN mixes[466]
    DIRECTION INPUT ;
    USE SIGNAL ;
    PORT
      LAYER M4 ;
        RECT 0.000 235.680 0.192 235.704 ;
    END
  END mixes[466]
  PIN mixes[467]
    DIRECTION INPUT ;
    USE SIGNAL ;
    PORT
      LAYER M4 ;
        RECT 0.000 236.208 0.192 236.232 ;
    END
  END mixes[467]
  PIN mixes[468]
    DIRECTION INPUT ;
    USE SIGNAL ;
    PORT
      LAYER M4 ;
        RECT 0.000 236.688 0.192 236.712 ;
    END
  END mixes[468]
  PIN mixes[469]
    DIRECTION INPUT ;
    USE SIGNAL ;
    PORT
      LAYER M4 ;
        RECT 0.000 237.168 0.192 237.192 ;
    END
  END mixes[469]
  PIN mixes[470]
    DIRECTION INPUT ;
    USE SIGNAL ;
    PORT
      LAYER M4 ;
        RECT 0.000 237.696 0.192 237.720 ;
    END
  END mixes[470]
  PIN mixes[471]
    DIRECTION INPUT ;
    USE SIGNAL ;
    PORT
      LAYER M4 ;
        RECT 0.000 238.176 0.192 238.200 ;
    END
  END mixes[471]
  PIN mixes[472]
    DIRECTION INPUT ;
    USE SIGNAL ;
    PORT
      LAYER M4 ;
        RECT 0.000 238.704 0.192 238.728 ;
    END
  END mixes[472]
  PIN mixes[473]
    DIRECTION INPUT ;
    USE SIGNAL ;
    PORT
      LAYER M4 ;
        RECT 0.000 239.184 0.192 239.208 ;
    END
  END mixes[473]
  PIN mixes[474]
    DIRECTION INPUT ;
    USE SIGNAL ;
    PORT
      LAYER M4 ;
        RECT 0.000 239.712 0.192 239.736 ;
    END
  END mixes[474]
  PIN mixes[475]
    DIRECTION INPUT ;
    USE SIGNAL ;
    PORT
      LAYER M4 ;
        RECT 0.000 240.192 0.192 240.216 ;
    END
  END mixes[475]
  PIN mixes[476]
    DIRECTION INPUT ;
    USE SIGNAL ;
    PORT
      LAYER M4 ;
        RECT 0.000 240.672 0.192 240.696 ;
    END
  END mixes[476]
  PIN mixes[477]
    DIRECTION INPUT ;
    USE SIGNAL ;
    PORT
      LAYER M4 ;
        RECT 0.000 241.200 0.192 241.224 ;
    END
  END mixes[477]
  PIN mixes[478]
    DIRECTION INPUT ;
    USE SIGNAL ;
    PORT
      LAYER M4 ;
        RECT 0.000 241.680 0.192 241.704 ;
    END
  END mixes[478]
  PIN mixes[479]
    DIRECTION INPUT ;
    USE SIGNAL ;
    PORT
      LAYER M4 ;
        RECT 0.000 242.208 0.192 242.232 ;
    END
  END mixes[479]
  PIN mixes[480]
    DIRECTION INPUT ;
    USE SIGNAL ;
    PORT
      LAYER M4 ;
        RECT 0.000 242.688 0.192 242.712 ;
    END
  END mixes[480]
  PIN mixes[481]
    DIRECTION INPUT ;
    USE SIGNAL ;
    PORT
      LAYER M4 ;
        RECT 0.000 243.216 0.192 243.240 ;
    END
  END mixes[481]
  PIN mixes[482]
    DIRECTION INPUT ;
    USE SIGNAL ;
    PORT
      LAYER M4 ;
        RECT 0.000 243.696 0.192 243.720 ;
    END
  END mixes[482]
  PIN mixes[483]
    DIRECTION INPUT ;
    USE SIGNAL ;
    PORT
      LAYER M4 ;
        RECT 0.000 244.224 0.192 244.248 ;
    END
  END mixes[483]
  PIN mixes[484]
    DIRECTION INPUT ;
    USE SIGNAL ;
    PORT
      LAYER M4 ;
        RECT 0.000 244.704 0.192 244.728 ;
    END
  END mixes[484]
  PIN mixes[485]
    DIRECTION INPUT ;
    USE SIGNAL ;
    PORT
      LAYER M4 ;
        RECT 0.000 245.184 0.192 245.208 ;
    END
  END mixes[485]
  PIN mixes[486]
    DIRECTION INPUT ;
    USE SIGNAL ;
    PORT
      LAYER M4 ;
        RECT 0.000 245.712 0.192 245.736 ;
    END
  END mixes[486]
  PIN mixes[487]
    DIRECTION INPUT ;
    USE SIGNAL ;
    PORT
      LAYER M4 ;
        RECT 0.000 246.192 0.192 246.216 ;
    END
  END mixes[487]
  PIN mixes[488]
    DIRECTION INPUT ;
    USE SIGNAL ;
    PORT
      LAYER M4 ;
        RECT 0.000 246.720 0.192 246.744 ;
    END
  END mixes[488]
  PIN mixes[489]
    DIRECTION INPUT ;
    USE SIGNAL ;
    PORT
      LAYER M4 ;
        RECT 0.000 247.200 0.192 247.224 ;
    END
  END mixes[489]
  PIN mixes[490]
    DIRECTION INPUT ;
    USE SIGNAL ;
    PORT
      LAYER M4 ;
        RECT 0.000 247.728 0.192 247.752 ;
    END
  END mixes[490]
  PIN mixes[491]
    DIRECTION INPUT ;
    USE SIGNAL ;
    PORT
      LAYER M4 ;
        RECT 0.000 248.208 0.192 248.232 ;
    END
  END mixes[491]
  PIN mixes[492]
    DIRECTION INPUT ;
    USE SIGNAL ;
    PORT
      LAYER M4 ;
        RECT 0.000 248.688 0.192 248.712 ;
    END
  END mixes[492]
  PIN mixes[493]
    DIRECTION INPUT ;
    USE SIGNAL ;
    PORT
      LAYER M4 ;
        RECT 0.000 249.216 0.192 249.240 ;
    END
  END mixes[493]
  PIN mixes[494]
    DIRECTION INPUT ;
    USE SIGNAL ;
    PORT
      LAYER M4 ;
        RECT 0.000 249.696 0.192 249.720 ;
    END
  END mixes[494]
  PIN mixes[495]
    DIRECTION INPUT ;
    USE SIGNAL ;
    PORT
      LAYER M4 ;
        RECT 0.000 250.224 0.192 250.248 ;
    END
  END mixes[495]
  PIN mixes[496]
    DIRECTION INPUT ;
    USE SIGNAL ;
    PORT
      LAYER M4 ;
        RECT 0.000 250.704 0.192 250.728 ;
    END
  END mixes[496]
  PIN mixes[497]
    DIRECTION INPUT ;
    USE SIGNAL ;
    PORT
      LAYER M4 ;
        RECT 0.000 251.232 0.192 251.256 ;
    END
  END mixes[497]
  PIN mixes[498]
    DIRECTION INPUT ;
    USE SIGNAL ;
    PORT
      LAYER M4 ;
        RECT 0.000 251.712 0.192 251.736 ;
    END
  END mixes[498]
  PIN mixes[499]
    DIRECTION INPUT ;
    USE SIGNAL ;
    PORT
      LAYER M4 ;
        RECT 0.000 252.192 0.192 252.216 ;
    END
  END mixes[499]
  PIN mixes[500]
    DIRECTION INPUT ;
    USE SIGNAL ;
    PORT
      LAYER M4 ;
        RECT 0.000 252.720 0.192 252.744 ;
    END
  END mixes[500]
  PIN mixes[501]
    DIRECTION INPUT ;
    USE SIGNAL ;
    PORT
      LAYER M4 ;
        RECT 0.000 253.200 0.192 253.224 ;
    END
  END mixes[501]
  PIN mixes[502]
    DIRECTION INPUT ;
    USE SIGNAL ;
    PORT
      LAYER M4 ;
        RECT 0.000 253.728 0.192 253.752 ;
    END
  END mixes[502]
  PIN mixes[503]
    DIRECTION INPUT ;
    USE SIGNAL ;
    PORT
      LAYER M4 ;
        RECT 0.000 254.208 0.192 254.232 ;
    END
  END mixes[503]
  PIN mixes[504]
    DIRECTION INPUT ;
    USE SIGNAL ;
    PORT
      LAYER M4 ;
        RECT 0.000 254.736 0.192 254.760 ;
    END
  END mixes[504]
  PIN mixes[505]
    DIRECTION INPUT ;
    USE SIGNAL ;
    PORT
      LAYER M4 ;
        RECT 0.000 255.216 0.192 255.240 ;
    END
  END mixes[505]
  PIN mixes[506]
    DIRECTION INPUT ;
    USE SIGNAL ;
    PORT
      LAYER M4 ;
        RECT 0.000 255.696 0.192 255.720 ;
    END
  END mixes[506]
  PIN mixes[507]
    DIRECTION INPUT ;
    USE SIGNAL ;
    PORT
      LAYER M4 ;
        RECT 0.000 256.224 0.192 256.248 ;
    END
  END mixes[507]
  PIN mixes[508]
    DIRECTION INPUT ;
    USE SIGNAL ;
    PORT
      LAYER M4 ;
        RECT 0.000 256.704 0.192 256.728 ;
    END
  END mixes[508]
  PIN mixes[509]
    DIRECTION INPUT ;
    USE SIGNAL ;
    PORT
      LAYER M4 ;
        RECT 0.000 257.232 0.192 257.256 ;
    END
  END mixes[509]
  PIN mixes[510]
    DIRECTION INPUT ;
    USE SIGNAL ;
    PORT
      LAYER M4 ;
        RECT 0.000 257.712 0.192 257.736 ;
    END
  END mixes[510]
  PIN mixes[511]
    DIRECTION INPUT ;
    USE SIGNAL ;
    PORT
      LAYER M4 ;
        RECT 0.000 258.240 0.192 258.264 ;
    END
  END mixes[511]
  PIN mixes[512]
    DIRECTION INPUT ;
    USE SIGNAL ;
    PORT
      LAYER M4 ;
        RECT 0.000 258.720 0.192 258.744 ;
    END
  END mixes[512]
  PIN mixes[513]
    DIRECTION INPUT ;
    USE SIGNAL ;
    PORT
      LAYER M4 ;
        RECT 0.000 259.200 0.192 259.224 ;
    END
  END mixes[513]
  PIN mixes[514]
    DIRECTION INPUT ;
    USE SIGNAL ;
    PORT
      LAYER M4 ;
        RECT 0.000 259.728 0.192 259.752 ;
    END
  END mixes[514]
  PIN mixes[515]
    DIRECTION INPUT ;
    USE SIGNAL ;
    PORT
      LAYER M4 ;
        RECT 0.000 260.208 0.192 260.232 ;
    END
  END mixes[515]
  PIN mixes[516]
    DIRECTION INPUT ;
    USE SIGNAL ;
    PORT
      LAYER M4 ;
        RECT 0.000 260.736 0.192 260.760 ;
    END
  END mixes[516]
  PIN mixes[517]
    DIRECTION INPUT ;
    USE SIGNAL ;
    PORT
      LAYER M4 ;
        RECT 0.000 261.216 0.192 261.240 ;
    END
  END mixes[517]
  PIN mixes[518]
    DIRECTION INPUT ;
    USE SIGNAL ;
    PORT
      LAYER M4 ;
        RECT 0.000 261.744 0.192 261.768 ;
    END
  END mixes[518]
  PIN mixes[519]
    DIRECTION INPUT ;
    USE SIGNAL ;
    PORT
      LAYER M4 ;
        RECT 0.000 262.224 0.192 262.248 ;
    END
  END mixes[519]
  PIN mixes[520]
    DIRECTION INPUT ;
    USE SIGNAL ;
    PORT
      LAYER M4 ;
        RECT 0.000 262.704 0.192 262.728 ;
    END
  END mixes[520]
  PIN mixes[521]
    DIRECTION INPUT ;
    USE SIGNAL ;
    PORT
      LAYER M4 ;
        RECT 0.000 263.232 0.192 263.256 ;
    END
  END mixes[521]
  PIN mixes[522]
    DIRECTION INPUT ;
    USE SIGNAL ;
    PORT
      LAYER M4 ;
        RECT 0.000 263.712 0.192 263.736 ;
    END
  END mixes[522]
  PIN mixes[523]
    DIRECTION INPUT ;
    USE SIGNAL ;
    PORT
      LAYER M4 ;
        RECT 0.000 264.240 0.192 264.264 ;
    END
  END mixes[523]
  PIN mixes[524]
    DIRECTION INPUT ;
    USE SIGNAL ;
    PORT
      LAYER M4 ;
        RECT 0.000 264.720 0.192 264.744 ;
    END
  END mixes[524]
  PIN mixes[525]
    DIRECTION INPUT ;
    USE SIGNAL ;
    PORT
      LAYER M4 ;
        RECT 0.000 265.248 0.192 265.272 ;
    END
  END mixes[525]
  PIN mixes[526]
    DIRECTION INPUT ;
    USE SIGNAL ;
    PORT
      LAYER M4 ;
        RECT 0.000 265.728 0.192 265.752 ;
    END
  END mixes[526]
  PIN mixes[527]
    DIRECTION INPUT ;
    USE SIGNAL ;
    PORT
      LAYER M4 ;
        RECT 0.000 266.208 0.192 266.232 ;
    END
  END mixes[527]
  PIN mixes[528]
    DIRECTION INPUT ;
    USE SIGNAL ;
    PORT
      LAYER M4 ;
        RECT 0.000 266.736 0.192 266.760 ;
    END
  END mixes[528]
  PIN mixes[529]
    DIRECTION INPUT ;
    USE SIGNAL ;
    PORT
      LAYER M4 ;
        RECT 0.000 267.216 0.192 267.240 ;
    END
  END mixes[529]
  PIN mixes[530]
    DIRECTION INPUT ;
    USE SIGNAL ;
    PORT
      LAYER M4 ;
        RECT 0.000 267.744 0.192 267.768 ;
    END
  END mixes[530]
  PIN mixes[531]
    DIRECTION INPUT ;
    USE SIGNAL ;
    PORT
      LAYER M4 ;
        RECT 0.000 268.224 0.192 268.248 ;
    END
  END mixes[531]
  PIN mixes[532]
    DIRECTION INPUT ;
    USE SIGNAL ;
    PORT
      LAYER M4 ;
        RECT 0.000 268.752 0.192 268.776 ;
    END
  END mixes[532]
  PIN mixes[533]
    DIRECTION INPUT ;
    USE SIGNAL ;
    PORT
      LAYER M4 ;
        RECT 0.000 269.232 0.192 269.256 ;
    END
  END mixes[533]
  PIN mixes[534]
    DIRECTION INPUT ;
    USE SIGNAL ;
    PORT
      LAYER M4 ;
        RECT 0.000 269.712 0.192 269.736 ;
    END
  END mixes[534]
  PIN mixes[535]
    DIRECTION INPUT ;
    USE SIGNAL ;
    PORT
      LAYER M4 ;
        RECT 0.000 270.240 0.192 270.264 ;
    END
  END mixes[535]
  PIN mixes[536]
    DIRECTION INPUT ;
    USE SIGNAL ;
    PORT
      LAYER M4 ;
        RECT 0.000 270.720 0.192 270.744 ;
    END
  END mixes[536]
  PIN mixes[537]
    DIRECTION INPUT ;
    USE SIGNAL ;
    PORT
      LAYER M4 ;
        RECT 0.000 271.248 0.192 271.272 ;
    END
  END mixes[537]
  PIN mixes[538]
    DIRECTION INPUT ;
    USE SIGNAL ;
    PORT
      LAYER M4 ;
        RECT 0.000 271.728 0.192 271.752 ;
    END
  END mixes[538]
  PIN mixes[539]
    DIRECTION INPUT ;
    USE SIGNAL ;
    PORT
      LAYER M4 ;
        RECT 0.000 272.256 0.192 272.280 ;
    END
  END mixes[539]
  PIN mixes[540]
    DIRECTION INPUT ;
    USE SIGNAL ;
    PORT
      LAYER M4 ;
        RECT 0.000 272.736 0.192 272.760 ;
    END
  END mixes[540]
  PIN mixes[541]
    DIRECTION INPUT ;
    USE SIGNAL ;
    PORT
      LAYER M4 ;
        RECT 0.000 273.216 0.192 273.240 ;
    END
  END mixes[541]
  PIN mixes[542]
    DIRECTION INPUT ;
    USE SIGNAL ;
    PORT
      LAYER M4 ;
        RECT 0.000 273.744 0.192 273.768 ;
    END
  END mixes[542]
  PIN mixes[543]
    DIRECTION INPUT ;
    USE SIGNAL ;
    PORT
      LAYER M4 ;
        RECT 0.000 274.224 0.192 274.248 ;
    END
  END mixes[543]
  PIN mixes[544]
    DIRECTION INPUT ;
    USE SIGNAL ;
    PORT
      LAYER M4 ;
        RECT 0.000 274.752 0.192 274.776 ;
    END
  END mixes[544]
  PIN mixes[545]
    DIRECTION INPUT ;
    USE SIGNAL ;
    PORT
      LAYER M4 ;
        RECT 0.000 275.232 0.192 275.256 ;
    END
  END mixes[545]
  PIN mixes[546]
    DIRECTION INPUT ;
    USE SIGNAL ;
    PORT
      LAYER M4 ;
        RECT 0.000 275.760 0.192 275.784 ;
    END
  END mixes[546]
  PIN mixes[547]
    DIRECTION INPUT ;
    USE SIGNAL ;
    PORT
      LAYER M4 ;
        RECT 0.000 276.240 0.192 276.264 ;
    END
  END mixes[547]
  PIN mixes[548]
    DIRECTION INPUT ;
    USE SIGNAL ;
    PORT
      LAYER M4 ;
        RECT 0.000 276.720 0.192 276.744 ;
    END
  END mixes[548]
  PIN mixes[549]
    DIRECTION INPUT ;
    USE SIGNAL ;
    PORT
      LAYER M4 ;
        RECT 0.000 277.248 0.192 277.272 ;
    END
  END mixes[549]
  PIN mixes[550]
    DIRECTION INPUT ;
    USE SIGNAL ;
    PORT
      LAYER M4 ;
        RECT 0.000 277.728 0.192 277.752 ;
    END
  END mixes[550]
  PIN mixes[551]
    DIRECTION INPUT ;
    USE SIGNAL ;
    PORT
      LAYER M4 ;
        RECT 0.000 278.256 0.192 278.280 ;
    END
  END mixes[551]
  PIN mixes[552]
    DIRECTION INPUT ;
    USE SIGNAL ;
    PORT
      LAYER M4 ;
        RECT 0.000 278.736 0.192 278.760 ;
    END
  END mixes[552]
  PIN mixes[553]
    DIRECTION INPUT ;
    USE SIGNAL ;
    PORT
      LAYER M4 ;
        RECT 0.000 279.264 0.192 279.288 ;
    END
  END mixes[553]
  PIN mixes[554]
    DIRECTION INPUT ;
    USE SIGNAL ;
    PORT
      LAYER M4 ;
        RECT 0.000 279.744 0.192 279.768 ;
    END
  END mixes[554]
  PIN mixes[555]
    DIRECTION INPUT ;
    USE SIGNAL ;
    PORT
      LAYER M4 ;
        RECT 0.000 280.224 0.192 280.248 ;
    END
  END mixes[555]
  PIN mixes[556]
    DIRECTION INPUT ;
    USE SIGNAL ;
    PORT
      LAYER M4 ;
        RECT 0.000 280.752 0.192 280.776 ;
    END
  END mixes[556]
  PIN mixes[557]
    DIRECTION INPUT ;
    USE SIGNAL ;
    PORT
      LAYER M4 ;
        RECT 0.000 281.232 0.192 281.256 ;
    END
  END mixes[557]
  PIN mixes[558]
    DIRECTION INPUT ;
    USE SIGNAL ;
    PORT
      LAYER M4 ;
        RECT 0.000 281.760 0.192 281.784 ;
    END
  END mixes[558]
  PIN mixes[559]
    DIRECTION INPUT ;
    USE SIGNAL ;
    PORT
      LAYER M4 ;
        RECT 0.000 282.240 0.192 282.264 ;
    END
  END mixes[559]
  PIN mixes[560]
    DIRECTION INPUT ;
    USE SIGNAL ;
    PORT
      LAYER M4 ;
        RECT 0.000 282.768 0.192 282.792 ;
    END
  END mixes[560]
  PIN mixes[561]
    DIRECTION INPUT ;
    USE SIGNAL ;
    PORT
      LAYER M4 ;
        RECT 0.000 283.248 0.192 283.272 ;
    END
  END mixes[561]
  PIN mixes[562]
    DIRECTION INPUT ;
    USE SIGNAL ;
    PORT
      LAYER M4 ;
        RECT 0.000 283.728 0.192 283.752 ;
    END
  END mixes[562]
  PIN mixes[563]
    DIRECTION INPUT ;
    USE SIGNAL ;
    PORT
      LAYER M4 ;
        RECT 0.000 284.256 0.192 284.280 ;
    END
  END mixes[563]
  PIN mixes[564]
    DIRECTION INPUT ;
    USE SIGNAL ;
    PORT
      LAYER M4 ;
        RECT 0.000 284.736 0.192 284.760 ;
    END
  END mixes[564]
  PIN mixes[565]
    DIRECTION INPUT ;
    USE SIGNAL ;
    PORT
      LAYER M4 ;
        RECT 0.000 285.264 0.192 285.288 ;
    END
  END mixes[565]
  PIN mixes[566]
    DIRECTION INPUT ;
    USE SIGNAL ;
    PORT
      LAYER M4 ;
        RECT 0.000 285.744 0.192 285.768 ;
    END
  END mixes[566]
  PIN mixes[567]
    DIRECTION INPUT ;
    USE SIGNAL ;
    PORT
      LAYER M4 ;
        RECT 0.000 286.272 0.192 286.296 ;
    END
  END mixes[567]
  PIN mixes[568]
    DIRECTION INPUT ;
    USE SIGNAL ;
    PORT
      LAYER M4 ;
        RECT 0.000 286.752 0.192 286.776 ;
    END
  END mixes[568]
  PIN mixes[569]
    DIRECTION INPUT ;
    USE SIGNAL ;
    PORT
      LAYER M4 ;
        RECT 0.000 287.232 0.192 287.256 ;
    END
  END mixes[569]
  PIN mixes[570]
    DIRECTION INPUT ;
    USE SIGNAL ;
    PORT
      LAYER M4 ;
        RECT 0.000 287.760 0.192 287.784 ;
    END
  END mixes[570]
  PIN mixes[571]
    DIRECTION INPUT ;
    USE SIGNAL ;
    PORT
      LAYER M4 ;
        RECT 0.000 288.240 0.192 288.264 ;
    END
  END mixes[571]
  PIN mixes[572]
    DIRECTION INPUT ;
    USE SIGNAL ;
    PORT
      LAYER M4 ;
        RECT 0.000 288.768 0.192 288.792 ;
    END
  END mixes[572]
  PIN mixes[573]
    DIRECTION INPUT ;
    USE SIGNAL ;
    PORT
      LAYER M4 ;
        RECT 0.000 289.248 0.192 289.272 ;
    END
  END mixes[573]
  PIN mixes[574]
    DIRECTION INPUT ;
    USE SIGNAL ;
    PORT
      LAYER M4 ;
        RECT 0.000 289.776 0.192 289.800 ;
    END
  END mixes[574]
  PIN mixes[575]
    DIRECTION INPUT ;
    USE SIGNAL ;
    PORT
      LAYER M4 ;
        RECT 0.000 290.256 0.192 290.280 ;
    END
  END mixes[575]
  PIN mixes[576]
    DIRECTION INPUT ;
    USE SIGNAL ;
    PORT
      LAYER M4 ;
        RECT 0.000 290.736 0.192 290.760 ;
    END
  END mixes[576]
  PIN mixes[577]
    DIRECTION INPUT ;
    USE SIGNAL ;
    PORT
      LAYER M4 ;
        RECT 0.000 291.264 0.192 291.288 ;
    END
  END mixes[577]
  PIN mixes[578]
    DIRECTION INPUT ;
    USE SIGNAL ;
    PORT
      LAYER M4 ;
        RECT 0.000 291.744 0.192 291.768 ;
    END
  END mixes[578]
  PIN mixes[579]
    DIRECTION INPUT ;
    USE SIGNAL ;
    PORT
      LAYER M4 ;
        RECT 0.000 292.272 0.192 292.296 ;
    END
  END mixes[579]
  PIN mixes[580]
    DIRECTION INPUT ;
    USE SIGNAL ;
    PORT
      LAYER M4 ;
        RECT 0.000 292.752 0.192 292.776 ;
    END
  END mixes[580]
  PIN mixes[581]
    DIRECTION INPUT ;
    USE SIGNAL ;
    PORT
      LAYER M4 ;
        RECT 0.000 293.280 0.192 293.304 ;
    END
  END mixes[581]
  PIN mixes[582]
    DIRECTION INPUT ;
    USE SIGNAL ;
    PORT
      LAYER M4 ;
        RECT 0.000 293.760 0.192 293.784 ;
    END
  END mixes[582]
  PIN mixes[583]
    DIRECTION INPUT ;
    USE SIGNAL ;
    PORT
      LAYER M4 ;
        RECT 0.000 294.240 0.192 294.264 ;
    END
  END mixes[583]
  PIN mixes[584]
    DIRECTION INPUT ;
    USE SIGNAL ;
    PORT
      LAYER M4 ;
        RECT 0.000 294.768 0.192 294.792 ;
    END
  END mixes[584]
  PIN mixes[585]
    DIRECTION INPUT ;
    USE SIGNAL ;
    PORT
      LAYER M4 ;
        RECT 0.000 295.248 0.192 295.272 ;
    END
  END mixes[585]
  PIN mixes[586]
    DIRECTION INPUT ;
    USE SIGNAL ;
    PORT
      LAYER M4 ;
        RECT 0.000 295.776 0.192 295.800 ;
    END
  END mixes[586]
  PIN mixes[587]
    DIRECTION INPUT ;
    USE SIGNAL ;
    PORT
      LAYER M4 ;
        RECT 0.000 296.256 0.192 296.280 ;
    END
  END mixes[587]
  PIN mixes[588]
    DIRECTION INPUT ;
    USE SIGNAL ;
    PORT
      LAYER M4 ;
        RECT 0.000 296.784 0.192 296.808 ;
    END
  END mixes[588]
  PIN mixes[589]
    DIRECTION INPUT ;
    USE SIGNAL ;
    PORT
      LAYER M4 ;
        RECT 0.000 297.264 0.192 297.288 ;
    END
  END mixes[589]
  PIN mixes[590]
    DIRECTION INPUT ;
    USE SIGNAL ;
    PORT
      LAYER M4 ;
        RECT 0.000 297.744 0.192 297.768 ;
    END
  END mixes[590]
  PIN mixes[591]
    DIRECTION INPUT ;
    USE SIGNAL ;
    PORT
      LAYER M4 ;
        RECT 0.000 298.272 0.192 298.296 ;
    END
  END mixes[591]
  PIN mixes[592]
    DIRECTION INPUT ;
    USE SIGNAL ;
    PORT
      LAYER M4 ;
        RECT 0.000 298.752 0.192 298.776 ;
    END
  END mixes[592]
  PIN mixes[593]
    DIRECTION INPUT ;
    USE SIGNAL ;
    PORT
      LAYER M4 ;
        RECT 0.000 299.280 0.192 299.304 ;
    END
  END mixes[593]
  PIN mixes[594]
    DIRECTION INPUT ;
    USE SIGNAL ;
    PORT
      LAYER M4 ;
        RECT 0.000 299.760 0.192 299.784 ;
    END
  END mixes[594]
  PIN mixes[595]
    DIRECTION INPUT ;
    USE SIGNAL ;
    PORT
      LAYER M4 ;
        RECT 0.000 300.288 0.192 300.312 ;
    END
  END mixes[595]
  PIN mixes[596]
    DIRECTION INPUT ;
    USE SIGNAL ;
    PORT
      LAYER M4 ;
        RECT 0.000 300.768 0.192 300.792 ;
    END
  END mixes[596]
  PIN mixes[597]
    DIRECTION INPUT ;
    USE SIGNAL ;
    PORT
      LAYER M4 ;
        RECT 0.000 301.248 0.192 301.272 ;
    END
  END mixes[597]
  PIN mixes[598]
    DIRECTION INPUT ;
    USE SIGNAL ;
    PORT
      LAYER M4 ;
        RECT 0.000 301.776 0.192 301.800 ;
    END
  END mixes[598]
  PIN mixes[599]
    DIRECTION INPUT ;
    USE SIGNAL ;
    PORT
      LAYER M4 ;
        RECT 0.000 302.256 0.192 302.280 ;
    END
  END mixes[599]
  PIN mixes[600]
    DIRECTION INPUT ;
    USE SIGNAL ;
    PORT
      LAYER M4 ;
        RECT 0.000 302.784 0.192 302.808 ;
    END
  END mixes[600]
  PIN mixes[601]
    DIRECTION INPUT ;
    USE SIGNAL ;
    PORT
      LAYER M4 ;
        RECT 0.000 303.264 0.192 303.288 ;
    END
  END mixes[601]
  PIN mixes[602]
    DIRECTION INPUT ;
    USE SIGNAL ;
    PORT
      LAYER M4 ;
        RECT 0.000 303.792 0.192 303.816 ;
    END
  END mixes[602]
  PIN mixes[603]
    DIRECTION INPUT ;
    USE SIGNAL ;
    PORT
      LAYER M4 ;
        RECT 0.000 304.272 0.192 304.296 ;
    END
  END mixes[603]
  PIN mixes[604]
    DIRECTION INPUT ;
    USE SIGNAL ;
    PORT
      LAYER M4 ;
        RECT 0.000 304.752 0.192 304.776 ;
    END
  END mixes[604]
  PIN mixes[605]
    DIRECTION INPUT ;
    USE SIGNAL ;
    PORT
      LAYER M4 ;
        RECT 0.000 305.280 0.192 305.304 ;
    END
  END mixes[605]
  PIN mixes[606]
    DIRECTION INPUT ;
    USE SIGNAL ;
    PORT
      LAYER M4 ;
        RECT 0.000 305.760 0.192 305.784 ;
    END
  END mixes[606]
  PIN mixes[607]
    DIRECTION INPUT ;
    USE SIGNAL ;
    PORT
      LAYER M4 ;
        RECT 0.000 306.288 0.192 306.312 ;
    END
  END mixes[607]
  PIN mixes[608]
    DIRECTION INPUT ;
    USE SIGNAL ;
    PORT
      LAYER M4 ;
        RECT 0.000 306.768 0.192 306.792 ;
    END
  END mixes[608]
  PIN mixes[609]
    DIRECTION INPUT ;
    USE SIGNAL ;
    PORT
      LAYER M4 ;
        RECT 0.000 307.296 0.192 307.320 ;
    END
  END mixes[609]
  PIN mixes[610]
    DIRECTION INPUT ;
    USE SIGNAL ;
    PORT
      LAYER M4 ;
        RECT 0.000 307.776 0.192 307.800 ;
    END
  END mixes[610]
  PIN mixes[611]
    DIRECTION INPUT ;
    USE SIGNAL ;
    PORT
      LAYER M4 ;
        RECT 0.000 308.304 0.192 308.328 ;
    END
  END mixes[611]
  PIN mixes[612]
    DIRECTION INPUT ;
    USE SIGNAL ;
    PORT
      LAYER M4 ;
        RECT 0.000 308.784 0.192 308.808 ;
    END
  END mixes[612]
  PIN mixes[613]
    DIRECTION INPUT ;
    USE SIGNAL ;
    PORT
      LAYER M4 ;
        RECT 0.000 309.264 0.192 309.288 ;
    END
  END mixes[613]
  PIN mixes[614]
    DIRECTION INPUT ;
    USE SIGNAL ;
    PORT
      LAYER M4 ;
        RECT 0.000 309.792 0.192 309.816 ;
    END
  END mixes[614]
  PIN mixes[615]
    DIRECTION INPUT ;
    USE SIGNAL ;
    PORT
      LAYER M4 ;
        RECT 0.000 310.272 0.192 310.296 ;
    END
  END mixes[615]
  PIN mixes[616]
    DIRECTION INPUT ;
    USE SIGNAL ;
    PORT
      LAYER M4 ;
        RECT 0.000 310.800 0.192 310.824 ;
    END
  END mixes[616]
  PIN mixes[617]
    DIRECTION INPUT ;
    USE SIGNAL ;
    PORT
      LAYER M4 ;
        RECT 0.000 311.280 0.192 311.304 ;
    END
  END mixes[617]
  PIN mixes[618]
    DIRECTION INPUT ;
    USE SIGNAL ;
    PORT
      LAYER M4 ;
        RECT 0.000 311.808 0.192 311.832 ;
    END
  END mixes[618]
  PIN mixes[619]
    DIRECTION INPUT ;
    USE SIGNAL ;
    PORT
      LAYER M4 ;
        RECT 0.000 312.288 0.192 312.312 ;
    END
  END mixes[619]
  PIN mixes[620]
    DIRECTION INPUT ;
    USE SIGNAL ;
    PORT
      LAYER M4 ;
        RECT 0.000 312.768 0.192 312.792 ;
    END
  END mixes[620]
  PIN mixes[621]
    DIRECTION INPUT ;
    USE SIGNAL ;
    PORT
      LAYER M4 ;
        RECT 0.000 313.296 0.192 313.320 ;
    END
  END mixes[621]
  PIN mixes[622]
    DIRECTION INPUT ;
    USE SIGNAL ;
    PORT
      LAYER M4 ;
        RECT 0.000 313.776 0.192 313.800 ;
    END
  END mixes[622]
  PIN mixes[623]
    DIRECTION INPUT ;
    USE SIGNAL ;
    PORT
      LAYER M4 ;
        RECT 0.000 314.304 0.192 314.328 ;
    END
  END mixes[623]
  PIN mixes[624]
    DIRECTION INPUT ;
    USE SIGNAL ;
    PORT
      LAYER M4 ;
        RECT 0.000 314.784 0.192 314.808 ;
    END
  END mixes[624]
  PIN mixes[625]
    DIRECTION INPUT ;
    USE SIGNAL ;
    PORT
      LAYER M4 ;
        RECT 0.000 315.312 0.192 315.336 ;
    END
  END mixes[625]
  PIN mixes[626]
    DIRECTION INPUT ;
    USE SIGNAL ;
    PORT
      LAYER M4 ;
        RECT 0.000 315.792 0.192 315.816 ;
    END
  END mixes[626]
  PIN mixes[627]
    DIRECTION INPUT ;
    USE SIGNAL ;
    PORT
      LAYER M4 ;
        RECT 0.000 316.272 0.192 316.296 ;
    END
  END mixes[627]
  PIN mixes[628]
    DIRECTION INPUT ;
    USE SIGNAL ;
    PORT
      LAYER M4 ;
        RECT 0.000 316.800 0.192 316.824 ;
    END
  END mixes[628]
  PIN mixes[629]
    DIRECTION INPUT ;
    USE SIGNAL ;
    PORT
      LAYER M4 ;
        RECT 0.000 317.280 0.192 317.304 ;
    END
  END mixes[629]
  PIN mixes[630]
    DIRECTION INPUT ;
    USE SIGNAL ;
    PORT
      LAYER M4 ;
        RECT 0.000 317.808 0.192 317.832 ;
    END
  END mixes[630]
  PIN mixes[631]
    DIRECTION INPUT ;
    USE SIGNAL ;
    PORT
      LAYER M4 ;
        RECT 0.000 318.288 0.192 318.312 ;
    END
  END mixes[631]
  PIN mixes[632]
    DIRECTION INPUT ;
    USE SIGNAL ;
    PORT
      LAYER M4 ;
        RECT 0.000 318.816 0.192 318.840 ;
    END
  END mixes[632]
  PIN mixes[633]
    DIRECTION INPUT ;
    USE SIGNAL ;
    PORT
      LAYER M4 ;
        RECT 0.000 319.296 0.192 319.320 ;
    END
  END mixes[633]
  PIN mixes[634]
    DIRECTION INPUT ;
    USE SIGNAL ;
    PORT
      LAYER M4 ;
        RECT 0.000 319.776 0.192 319.800 ;
    END
  END mixes[634]
  PIN mixes[635]
    DIRECTION INPUT ;
    USE SIGNAL ;
    PORT
      LAYER M4 ;
        RECT 0.000 320.304 0.192 320.328 ;
    END
  END mixes[635]
  PIN mixes[636]
    DIRECTION INPUT ;
    USE SIGNAL ;
    PORT
      LAYER M4 ;
        RECT 0.000 320.784 0.192 320.808 ;
    END
  END mixes[636]
  PIN mixes[637]
    DIRECTION INPUT ;
    USE SIGNAL ;
    PORT
      LAYER M4 ;
        RECT 0.000 321.312 0.192 321.336 ;
    END
  END mixes[637]
  PIN mixes[638]
    DIRECTION INPUT ;
    USE SIGNAL ;
    PORT
      LAYER M4 ;
        RECT 0.000 321.792 0.192 321.816 ;
    END
  END mixes[638]
  PIN mixes[639]
    DIRECTION INPUT ;
    USE SIGNAL ;
    PORT
      LAYER M4 ;
        RECT 0.000 322.320 0.192 322.344 ;
    END
  END mixes[639]
  PIN mixes[640]
    DIRECTION INPUT ;
    USE SIGNAL ;
    PORT
      LAYER M4 ;
        RECT 0.000 322.800 0.192 322.824 ;
    END
  END mixes[640]
  PIN mixes[641]
    DIRECTION INPUT ;
    USE SIGNAL ;
    PORT
      LAYER M4 ;
        RECT 0.000 323.280 0.192 323.304 ;
    END
  END mixes[641]
  PIN mixes[642]
    DIRECTION INPUT ;
    USE SIGNAL ;
    PORT
      LAYER M4 ;
        RECT 0.000 323.808 0.192 323.832 ;
    END
  END mixes[642]
  PIN mixes[643]
    DIRECTION INPUT ;
    USE SIGNAL ;
    PORT
      LAYER M4 ;
        RECT 0.000 324.288 0.192 324.312 ;
    END
  END mixes[643]
  PIN mixes[644]
    DIRECTION INPUT ;
    USE SIGNAL ;
    PORT
      LAYER M4 ;
        RECT 0.000 324.816 0.192 324.840 ;
    END
  END mixes[644]
  PIN mixes[645]
    DIRECTION INPUT ;
    USE SIGNAL ;
    PORT
      LAYER M4 ;
        RECT 0.000 325.296 0.192 325.320 ;
    END
  END mixes[645]
  PIN mixes[646]
    DIRECTION INPUT ;
    USE SIGNAL ;
    PORT
      LAYER M4 ;
        RECT 0.000 325.824 0.192 325.848 ;
    END
  END mixes[646]
  PIN mixes[647]
    DIRECTION INPUT ;
    USE SIGNAL ;
    PORT
      LAYER M4 ;
        RECT 0.000 326.304 0.192 326.328 ;
    END
  END mixes[647]
  PIN mixes[648]
    DIRECTION INPUT ;
    USE SIGNAL ;
    PORT
      LAYER M4 ;
        RECT 0.000 326.784 0.192 326.808 ;
    END
  END mixes[648]
  PIN mixes[649]
    DIRECTION INPUT ;
    USE SIGNAL ;
    PORT
      LAYER M4 ;
        RECT 0.000 327.312 0.192 327.336 ;
    END
  END mixes[649]
  PIN mixes[650]
    DIRECTION INPUT ;
    USE SIGNAL ;
    PORT
      LAYER M4 ;
        RECT 0.000 327.792 0.192 327.816 ;
    END
  END mixes[650]
  PIN mixes[651]
    DIRECTION INPUT ;
    USE SIGNAL ;
    PORT
      LAYER M4 ;
        RECT 0.000 328.320 0.192 328.344 ;
    END
  END mixes[651]
  PIN mixes[652]
    DIRECTION INPUT ;
    USE SIGNAL ;
    PORT
      LAYER M4 ;
        RECT 0.000 328.800 0.192 328.824 ;
    END
  END mixes[652]
  PIN mixes[653]
    DIRECTION INPUT ;
    USE SIGNAL ;
    PORT
      LAYER M4 ;
        RECT 0.000 329.328 0.192 329.352 ;
    END
  END mixes[653]
  PIN mixes[654]
    DIRECTION INPUT ;
    USE SIGNAL ;
    PORT
      LAYER M4 ;
        RECT 0.000 329.808 0.192 329.832 ;
    END
  END mixes[654]
  PIN mixes[655]
    DIRECTION INPUT ;
    USE SIGNAL ;
    PORT
      LAYER M4 ;
        RECT 0.000 330.288 0.192 330.312 ;
    END
  END mixes[655]
  PIN mixes[656]
    DIRECTION INPUT ;
    USE SIGNAL ;
    PORT
      LAYER M4 ;
        RECT 0.000 330.816 0.192 330.840 ;
    END
  END mixes[656]
  PIN mixes[657]
    DIRECTION INPUT ;
    USE SIGNAL ;
    PORT
      LAYER M4 ;
        RECT 0.000 331.296 0.192 331.320 ;
    END
  END mixes[657]
  PIN mixes[658]
    DIRECTION INPUT ;
    USE SIGNAL ;
    PORT
      LAYER M4 ;
        RECT 0.000 331.824 0.192 331.848 ;
    END
  END mixes[658]
  PIN mixes[659]
    DIRECTION INPUT ;
    USE SIGNAL ;
    PORT
      LAYER M4 ;
        RECT 0.000 332.304 0.192 332.328 ;
    END
  END mixes[659]
  PIN mixes[660]
    DIRECTION INPUT ;
    USE SIGNAL ;
    PORT
      LAYER M4 ;
        RECT 0.000 332.832 0.192 332.856 ;
    END
  END mixes[660]
  PIN mixes[661]
    DIRECTION INPUT ;
    USE SIGNAL ;
    PORT
      LAYER M4 ;
        RECT 0.000 333.312 0.192 333.336 ;
    END
  END mixes[661]
  PIN mixes[662]
    DIRECTION INPUT ;
    USE SIGNAL ;
    PORT
      LAYER M4 ;
        RECT 0.000 333.792 0.192 333.816 ;
    END
  END mixes[662]
  PIN mixes[663]
    DIRECTION INPUT ;
    USE SIGNAL ;
    PORT
      LAYER M4 ;
        RECT 0.000 334.320 0.192 334.344 ;
    END
  END mixes[663]
  PIN mixes[664]
    DIRECTION INPUT ;
    USE SIGNAL ;
    PORT
      LAYER M4 ;
        RECT 0.000 334.800 0.192 334.824 ;
    END
  END mixes[664]
  PIN mixes[665]
    DIRECTION INPUT ;
    USE SIGNAL ;
    PORT
      LAYER M4 ;
        RECT 0.000 335.328 0.192 335.352 ;
    END
  END mixes[665]
  PIN mixes[666]
    DIRECTION INPUT ;
    USE SIGNAL ;
    PORT
      LAYER M4 ;
        RECT 0.000 335.808 0.192 335.832 ;
    END
  END mixes[666]
  PIN mixes[667]
    DIRECTION INPUT ;
    USE SIGNAL ;
    PORT
      LAYER M4 ;
        RECT 0.000 336.336 0.192 336.360 ;
    END
  END mixes[667]
  PIN mixes[668]
    DIRECTION INPUT ;
    USE SIGNAL ;
    PORT
      LAYER M4 ;
        RECT 0.000 336.816 0.192 336.840 ;
    END
  END mixes[668]
  PIN mixes[669]
    DIRECTION INPUT ;
    USE SIGNAL ;
    PORT
      LAYER M4 ;
        RECT 0.000 337.296 0.192 337.320 ;
    END
  END mixes[669]
  PIN mixes[670]
    DIRECTION INPUT ;
    USE SIGNAL ;
    PORT
      LAYER M4 ;
        RECT 0.000 337.824 0.192 337.848 ;
    END
  END mixes[670]
  PIN mixes[671]
    DIRECTION INPUT ;
    USE SIGNAL ;
    PORT
      LAYER M4 ;
        RECT 0.000 338.304 0.192 338.328 ;
    END
  END mixes[671]
  PIN mixes[672]
    DIRECTION INPUT ;
    USE SIGNAL ;
    PORT
      LAYER M4 ;
        RECT 0.000 338.832 0.192 338.856 ;
    END
  END mixes[672]
  PIN mixes[673]
    DIRECTION INPUT ;
    USE SIGNAL ;
    PORT
      LAYER M4 ;
        RECT 0.000 339.312 0.192 339.336 ;
    END
  END mixes[673]
  PIN mixes[674]
    DIRECTION INPUT ;
    USE SIGNAL ;
    PORT
      LAYER M4 ;
        RECT 0.000 339.840 0.192 339.864 ;
    END
  END mixes[674]
  PIN mixes[675]
    DIRECTION INPUT ;
    USE SIGNAL ;
    PORT
      LAYER M4 ;
        RECT 0.000 340.320 0.192 340.344 ;
    END
  END mixes[675]
  PIN mixes[676]
    DIRECTION INPUT ;
    USE SIGNAL ;
    PORT
      LAYER M4 ;
        RECT 0.000 340.800 0.192 340.824 ;
    END
  END mixes[676]
  PIN mixes[677]
    DIRECTION INPUT ;
    USE SIGNAL ;
    PORT
      LAYER M4 ;
        RECT 0.000 341.328 0.192 341.352 ;
    END
  END mixes[677]
  PIN mixes[678]
    DIRECTION INPUT ;
    USE SIGNAL ;
    PORT
      LAYER M4 ;
        RECT 0.000 341.808 0.192 341.832 ;
    END
  END mixes[678]
  PIN mixes[679]
    DIRECTION INPUT ;
    USE SIGNAL ;
    PORT
      LAYER M4 ;
        RECT 0.000 342.336 0.192 342.360 ;
    END
  END mixes[679]
  PIN mixes[680]
    DIRECTION INPUT ;
    USE SIGNAL ;
    PORT
      LAYER M4 ;
        RECT 0.000 342.816 0.192 342.840 ;
    END
  END mixes[680]
  PIN mixes[681]
    DIRECTION INPUT ;
    USE SIGNAL ;
    PORT
      LAYER M4 ;
        RECT 0.000 343.344 0.192 343.368 ;
    END
  END mixes[681]
  PIN mixes[682]
    DIRECTION INPUT ;
    USE SIGNAL ;
    PORT
      LAYER M4 ;
        RECT 0.000 343.824 0.192 343.848 ;
    END
  END mixes[682]
  PIN mixes[683]
    DIRECTION INPUT ;
    USE SIGNAL ;
    PORT
      LAYER M4 ;
        RECT 0.000 344.304 0.192 344.328 ;
    END
  END mixes[683]
  PIN mixes[684]
    DIRECTION INPUT ;
    USE SIGNAL ;
    PORT
      LAYER M4 ;
        RECT 0.000 344.832 0.192 344.856 ;
    END
  END mixes[684]
  PIN mixes[685]
    DIRECTION INPUT ;
    USE SIGNAL ;
    PORT
      LAYER M4 ;
        RECT 0.000 345.312 0.192 345.336 ;
    END
  END mixes[685]
  PIN mixes[686]
    DIRECTION INPUT ;
    USE SIGNAL ;
    PORT
      LAYER M4 ;
        RECT 0.000 345.840 0.192 345.864 ;
    END
  END mixes[686]
  PIN mixes[687]
    DIRECTION INPUT ;
    USE SIGNAL ;
    PORT
      LAYER M4 ;
        RECT 0.000 346.320 0.192 346.344 ;
    END
  END mixes[687]
  PIN mixes[688]
    DIRECTION INPUT ;
    USE SIGNAL ;
    PORT
      LAYER M4 ;
        RECT 0.000 346.848 0.192 346.872 ;
    END
  END mixes[688]
  PIN mixes[689]
    DIRECTION INPUT ;
    USE SIGNAL ;
    PORT
      LAYER M4 ;
        RECT 0.000 347.328 0.192 347.352 ;
    END
  END mixes[689]
  PIN mixes[690]
    DIRECTION INPUT ;
    USE SIGNAL ;
    PORT
      LAYER M4 ;
        RECT 0.000 347.808 0.192 347.832 ;
    END
  END mixes[690]
  PIN mixes[691]
    DIRECTION INPUT ;
    USE SIGNAL ;
    PORT
      LAYER M4 ;
        RECT 0.000 348.336 0.192 348.360 ;
    END
  END mixes[691]
  PIN mixes[692]
    DIRECTION INPUT ;
    USE SIGNAL ;
    PORT
      LAYER M4 ;
        RECT 0.000 348.816 0.192 348.840 ;
    END
  END mixes[692]
  PIN mixes[693]
    DIRECTION INPUT ;
    USE SIGNAL ;
    PORT
      LAYER M4 ;
        RECT 0.000 349.344 0.192 349.368 ;
    END
  END mixes[693]
  PIN mixes[694]
    DIRECTION INPUT ;
    USE SIGNAL ;
    PORT
      LAYER M4 ;
        RECT 0.000 349.824 0.192 349.848 ;
    END
  END mixes[694]
  PIN mixes[695]
    DIRECTION INPUT ;
    USE SIGNAL ;
    PORT
      LAYER M4 ;
        RECT 0.000 350.352 0.192 350.376 ;
    END
  END mixes[695]
  PIN mixes[696]
    DIRECTION INPUT ;
    USE SIGNAL ;
    PORT
      LAYER M4 ;
        RECT 0.000 350.832 0.192 350.856 ;
    END
  END mixes[696]
  PIN mixes[697]
    DIRECTION INPUT ;
    USE SIGNAL ;
    PORT
      LAYER M4 ;
        RECT 0.000 351.312 0.192 351.336 ;
    END
  END mixes[697]
  PIN mixes[698]
    DIRECTION INPUT ;
    USE SIGNAL ;
    PORT
      LAYER M4 ;
        RECT 0.000 351.840 0.192 351.864 ;
    END
  END mixes[698]
  PIN mixes[699]
    DIRECTION INPUT ;
    USE SIGNAL ;
    PORT
      LAYER M4 ;
        RECT 0.000 352.320 0.192 352.344 ;
    END
  END mixes[699]
  PIN mixes[700]
    DIRECTION INPUT ;
    USE SIGNAL ;
    PORT
      LAYER M4 ;
        RECT 0.000 352.848 0.192 352.872 ;
    END
  END mixes[700]
  PIN mixes[701]
    DIRECTION INPUT ;
    USE SIGNAL ;
    PORT
      LAYER M4 ;
        RECT 0.000 353.328 0.192 353.352 ;
    END
  END mixes[701]
  PIN mixes[702]
    DIRECTION INPUT ;
    USE SIGNAL ;
    PORT
      LAYER M4 ;
        RECT 0.000 353.856 0.192 353.880 ;
    END
  END mixes[702]
  PIN mixes[703]
    DIRECTION INPUT ;
    USE SIGNAL ;
    PORT
      LAYER M4 ;
        RECT 0.000 354.336 0.192 354.360 ;
    END
  END mixes[703]
  PIN mixes[704]
    DIRECTION INPUT ;
    USE SIGNAL ;
    PORT
      LAYER M4 ;
        RECT 0.000 354.816 0.192 354.840 ;
    END
  END mixes[704]
  PIN mixes[705]
    DIRECTION INPUT ;
    USE SIGNAL ;
    PORT
      LAYER M4 ;
        RECT 0.000 355.344 0.192 355.368 ;
    END
  END mixes[705]
  PIN mixes[706]
    DIRECTION INPUT ;
    USE SIGNAL ;
    PORT
      LAYER M4 ;
        RECT 0.000 355.824 0.192 355.848 ;
    END
  END mixes[706]
  PIN mixes[707]
    DIRECTION INPUT ;
    USE SIGNAL ;
    PORT
      LAYER M4 ;
        RECT 0.000 356.352 0.192 356.376 ;
    END
  END mixes[707]
  PIN mixes[708]
    DIRECTION INPUT ;
    USE SIGNAL ;
    PORT
      LAYER M4 ;
        RECT 0.000 356.832 0.192 356.856 ;
    END
  END mixes[708]
  PIN mixes[709]
    DIRECTION INPUT ;
    USE SIGNAL ;
    PORT
      LAYER M4 ;
        RECT 0.000 357.360 0.192 357.384 ;
    END
  END mixes[709]
  PIN mixes[710]
    DIRECTION INPUT ;
    USE SIGNAL ;
    PORT
      LAYER M4 ;
        RECT 0.000 357.840 0.192 357.864 ;
    END
  END mixes[710]
  PIN mixes[711]
    DIRECTION INPUT ;
    USE SIGNAL ;
    PORT
      LAYER M4 ;
        RECT 0.000 358.320 0.192 358.344 ;
    END
  END mixes[711]
  PIN mixes[712]
    DIRECTION INPUT ;
    USE SIGNAL ;
    PORT
      LAYER M4 ;
        RECT 0.000 358.848 0.192 358.872 ;
    END
  END mixes[712]
  PIN mixes[713]
    DIRECTION INPUT ;
    USE SIGNAL ;
    PORT
      LAYER M4 ;
        RECT 0.000 359.328 0.192 359.352 ;
    END
  END mixes[713]
  PIN mixes[714]
    DIRECTION INPUT ;
    USE SIGNAL ;
    PORT
      LAYER M4 ;
        RECT 0.000 359.856 0.192 359.880 ;
    END
  END mixes[714]
  PIN mixes[715]
    DIRECTION INPUT ;
    USE SIGNAL ;
    PORT
      LAYER M4 ;
        RECT 0.000 360.336 0.192 360.360 ;
    END
  END mixes[715]
  PIN mixes[716]
    DIRECTION INPUT ;
    USE SIGNAL ;
    PORT
      LAYER M4 ;
        RECT 0.000 360.864 0.192 360.888 ;
    END
  END mixes[716]
  PIN mixes[717]
    DIRECTION INPUT ;
    USE SIGNAL ;
    PORT
      LAYER M4 ;
        RECT 0.000 361.344 0.192 361.368 ;
    END
  END mixes[717]
  PIN mixes[718]
    DIRECTION INPUT ;
    USE SIGNAL ;
    PORT
      LAYER M4 ;
        RECT 0.000 361.824 0.192 361.848 ;
    END
  END mixes[718]
  PIN mixes[719]
    DIRECTION INPUT ;
    USE SIGNAL ;
    PORT
      LAYER M4 ;
        RECT 0.000 362.352 0.192 362.376 ;
    END
  END mixes[719]
  PIN mixes[720]
    DIRECTION INPUT ;
    USE SIGNAL ;
    PORT
      LAYER M4 ;
        RECT 0.000 362.832 0.192 362.856 ;
    END
  END mixes[720]
  PIN mixes[721]
    DIRECTION INPUT ;
    USE SIGNAL ;
    PORT
      LAYER M4 ;
        RECT 0.000 363.360 0.192 363.384 ;
    END
  END mixes[721]
  PIN mixes[722]
    DIRECTION INPUT ;
    USE SIGNAL ;
    PORT
      LAYER M4 ;
        RECT 0.000 363.840 0.192 363.864 ;
    END
  END mixes[722]
  PIN mixes[723]
    DIRECTION INPUT ;
    USE SIGNAL ;
    PORT
      LAYER M4 ;
        RECT 0.000 364.368 0.192 364.392 ;
    END
  END mixes[723]
  PIN mixes[724]
    DIRECTION INPUT ;
    USE SIGNAL ;
    PORT
      LAYER M4 ;
        RECT 0.000 364.848 0.192 364.872 ;
    END
  END mixes[724]
  PIN mixes[725]
    DIRECTION INPUT ;
    USE SIGNAL ;
    PORT
      LAYER M4 ;
        RECT 0.000 365.328 0.192 365.352 ;
    END
  END mixes[725]
  PIN mixes[726]
    DIRECTION INPUT ;
    USE SIGNAL ;
    PORT
      LAYER M4 ;
        RECT 0.000 365.856 0.192 365.880 ;
    END
  END mixes[726]
  PIN mixes[727]
    DIRECTION INPUT ;
    USE SIGNAL ;
    PORT
      LAYER M4 ;
        RECT 0.000 366.336 0.192 366.360 ;
    END
  END mixes[727]
  PIN mixes[728]
    DIRECTION INPUT ;
    USE SIGNAL ;
    PORT
      LAYER M4 ;
        RECT 0.000 366.864 0.192 366.888 ;
    END
  END mixes[728]
  PIN mixes[729]
    DIRECTION INPUT ;
    USE SIGNAL ;
    PORT
      LAYER M4 ;
        RECT 0.000 367.344 0.192 367.368 ;
    END
  END mixes[729]
  PIN mixes[730]
    DIRECTION INPUT ;
    USE SIGNAL ;
    PORT
      LAYER M4 ;
        RECT 0.000 367.872 0.192 367.896 ;
    END
  END mixes[730]
  PIN mixes[731]
    DIRECTION INPUT ;
    USE SIGNAL ;
    PORT
      LAYER M4 ;
        RECT 0.000 368.352 0.192 368.376 ;
    END
  END mixes[731]
  PIN mixes[732]
    DIRECTION INPUT ;
    USE SIGNAL ;
    PORT
      LAYER M4 ;
        RECT 0.000 368.832 0.192 368.856 ;
    END
  END mixes[732]
  PIN mixes[733]
    DIRECTION INPUT ;
    USE SIGNAL ;
    PORT
      LAYER M4 ;
        RECT 0.000 369.360 0.192 369.384 ;
    END
  END mixes[733]
  PIN mixes[734]
    DIRECTION INPUT ;
    USE SIGNAL ;
    PORT
      LAYER M4 ;
        RECT 0.000 369.840 0.192 369.864 ;
    END
  END mixes[734]
  PIN mixes[735]
    DIRECTION INPUT ;
    USE SIGNAL ;
    PORT
      LAYER M4 ;
        RECT 0.000 370.368 0.192 370.392 ;
    END
  END mixes[735]
  PIN mixes[736]
    DIRECTION INPUT ;
    USE SIGNAL ;
    PORT
      LAYER M4 ;
        RECT 0.000 370.848 0.192 370.872 ;
    END
  END mixes[736]
  PIN mixes[737]
    DIRECTION INPUT ;
    USE SIGNAL ;
    PORT
      LAYER M4 ;
        RECT 0.000 371.376 0.192 371.400 ;
    END
  END mixes[737]
  PIN mixes[738]
    DIRECTION INPUT ;
    USE SIGNAL ;
    PORT
      LAYER M4 ;
        RECT 0.000 371.856 0.192 371.880 ;
    END
  END mixes[738]
  PIN mixes[739]
    DIRECTION INPUT ;
    USE SIGNAL ;
    PORT
      LAYER M4 ;
        RECT 0.000 372.384 0.192 372.408 ;
    END
  END mixes[739]
  PIN mixes[740]
    DIRECTION INPUT ;
    USE SIGNAL ;
    PORT
      LAYER M4 ;
        RECT 0.000 372.864 0.192 372.888 ;
    END
  END mixes[740]
  PIN mixes[741]
    DIRECTION INPUT ;
    USE SIGNAL ;
    PORT
      LAYER M4 ;
        RECT 0.000 373.344 0.192 373.368 ;
    END
  END mixes[741]
  PIN mixes[742]
    DIRECTION INPUT ;
    USE SIGNAL ;
    PORT
      LAYER M4 ;
        RECT 0.000 373.872 0.192 373.896 ;
    END
  END mixes[742]
  PIN mixes[743]
    DIRECTION INPUT ;
    USE SIGNAL ;
    PORT
      LAYER M4 ;
        RECT 0.000 374.352 0.192 374.376 ;
    END
  END mixes[743]
  PIN mixes[744]
    DIRECTION INPUT ;
    USE SIGNAL ;
    PORT
      LAYER M4 ;
        RECT 0.000 374.880 0.192 374.904 ;
    END
  END mixes[744]
  PIN mixes[745]
    DIRECTION INPUT ;
    USE SIGNAL ;
    PORT
      LAYER M4 ;
        RECT 0.000 375.360 0.192 375.384 ;
    END
  END mixes[745]
  PIN mixes[746]
    DIRECTION INPUT ;
    USE SIGNAL ;
    PORT
      LAYER M4 ;
        RECT 0.000 375.888 0.192 375.912 ;
    END
  END mixes[746]
  PIN mixes[747]
    DIRECTION INPUT ;
    USE SIGNAL ;
    PORT
      LAYER M4 ;
        RECT 0.000 376.368 0.192 376.392 ;
    END
  END mixes[747]
  PIN mixes[748]
    DIRECTION INPUT ;
    USE SIGNAL ;
    PORT
      LAYER M4 ;
        RECT 0.000 376.848 0.192 376.872 ;
    END
  END mixes[748]
  PIN mixes[749]
    DIRECTION INPUT ;
    USE SIGNAL ;
    PORT
      LAYER M4 ;
        RECT 0.000 377.376 0.192 377.400 ;
    END
  END mixes[749]
  PIN mixes[750]
    DIRECTION INPUT ;
    USE SIGNAL ;
    PORT
      LAYER M4 ;
        RECT 0.000 377.856 0.192 377.880 ;
    END
  END mixes[750]
  PIN mixes[751]
    DIRECTION INPUT ;
    USE SIGNAL ;
    PORT
      LAYER M4 ;
        RECT 0.000 378.384 0.192 378.408 ;
    END
  END mixes[751]
  PIN mixes[752]
    DIRECTION INPUT ;
    USE SIGNAL ;
    PORT
      LAYER M4 ;
        RECT 0.000 378.864 0.192 378.888 ;
    END
  END mixes[752]
  PIN mixes[753]
    DIRECTION INPUT ;
    USE SIGNAL ;
    PORT
      LAYER M4 ;
        RECT 0.000 379.392 0.192 379.416 ;
    END
  END mixes[753]
  PIN mixes[754]
    DIRECTION INPUT ;
    USE SIGNAL ;
    PORT
      LAYER M4 ;
        RECT 0.000 379.872 0.192 379.896 ;
    END
  END mixes[754]
  PIN mixes[755]
    DIRECTION INPUT ;
    USE SIGNAL ;
    PORT
      LAYER M4 ;
        RECT 0.000 380.352 0.192 380.376 ;
    END
  END mixes[755]
  PIN mixes[756]
    DIRECTION INPUT ;
    USE SIGNAL ;
    PORT
      LAYER M4 ;
        RECT 0.000 380.880 0.192 380.904 ;
    END
  END mixes[756]
  PIN mixes[757]
    DIRECTION INPUT ;
    USE SIGNAL ;
    PORT
      LAYER M4 ;
        RECT 0.000 381.360 0.192 381.384 ;
    END
  END mixes[757]
  PIN mixes[758]
    DIRECTION INPUT ;
    USE SIGNAL ;
    PORT
      LAYER M4 ;
        RECT 0.000 381.888 0.192 381.912 ;
    END
  END mixes[758]
  PIN mixes[759]
    DIRECTION INPUT ;
    USE SIGNAL ;
    PORT
      LAYER M4 ;
        RECT 0.000 382.368 0.192 382.392 ;
    END
  END mixes[759]
  PIN mixes[760]
    DIRECTION INPUT ;
    USE SIGNAL ;
    PORT
      LAYER M4 ;
        RECT 0.000 382.896 0.192 382.920 ;
    END
  END mixes[760]
  PIN mixes[761]
    DIRECTION INPUT ;
    USE SIGNAL ;
    PORT
      LAYER M4 ;
        RECT 0.000 383.376 0.192 383.400 ;
    END
  END mixes[761]
  PIN mixes[762]
    DIRECTION INPUT ;
    USE SIGNAL ;
    PORT
      LAYER M4 ;
        RECT 0.000 383.856 0.192 383.880 ;
    END
  END mixes[762]
  PIN mixes[763]
    DIRECTION INPUT ;
    USE SIGNAL ;
    PORT
      LAYER M4 ;
        RECT 0.000 384.384 0.192 384.408 ;
    END
  END mixes[763]
  PIN mixes[764]
    DIRECTION INPUT ;
    USE SIGNAL ;
    PORT
      LAYER M4 ;
        RECT 0.000 384.864 0.192 384.888 ;
    END
  END mixes[764]
  PIN mixes[765]
    DIRECTION INPUT ;
    USE SIGNAL ;
    PORT
      LAYER M4 ;
        RECT 0.000 385.392 0.192 385.416 ;
    END
  END mixes[765]
  PIN mixes[766]
    DIRECTION INPUT ;
    USE SIGNAL ;
    PORT
      LAYER M4 ;
        RECT 0.000 385.872 0.192 385.896 ;
    END
  END mixes[766]
  PIN mixes[767]
    DIRECTION INPUT ;
    USE SIGNAL ;
    PORT
      LAYER M4 ;
        RECT 0.000 386.400 0.192 386.424 ;
    END
  END mixes[767]
  PIN launch
    DIRECTION INPUT ;
    USE SIGNAL ;
    PORT
      LAYER M3 ;
        RECT 2.373 388.608 2.397 388.800 ;
    END
  END launch
  PIN bases[0]
    DIRECTION INPUT ;
    USE SIGNAL ;
    PORT
      LAYER M5 ;
        RECT 2.832 388.608 2.856 388.800 ;
    END
  END bases[0]
  PIN bases[1]
    DIRECTION INPUT ;
    USE SIGNAL ;
    PORT
      LAYER M3 ;
        RECT 3.273 388.608 3.297 388.800 ;
    END
  END bases[1]
  PIN bases[2]
    DIRECTION INPUT ;
    USE SIGNAL ;
    PORT
      LAYER M5 ;
        RECT 3.696 388.608 3.720 388.800 ;
    END
  END bases[2]
  PIN bases[3]
    DIRECTION INPUT ;
    USE SIGNAL ;
    PORT
      LAYER M3 ;
        RECT 4.137 388.608 4.161 388.800 ;
    END
  END bases[3]
  PIN bases[4]
    DIRECTION INPUT ;
    USE SIGNAL ;
    PORT
      LAYER M5 ;
        RECT 4.608 388.608 4.632 388.800 ;
    END
  END bases[4]
  PIN bases[5]
    DIRECTION INPUT ;
    USE SIGNAL ;
    PORT
      LAYER M3 ;
        RECT 5.037 388.608 5.061 388.800 ;
    END
  END bases[5]
  PIN bases[6]
    DIRECTION INPUT ;
    USE SIGNAL ;
    PORT
      LAYER M5 ;
        RECT 5.472 388.608 5.496 388.800 ;
    END
  END bases[6]
  PIN bases[7]
    DIRECTION INPUT ;
    USE SIGNAL ;
    PORT
      LAYER M3 ;
        RECT 5.937 388.608 5.961 388.800 ;
    END
  END bases[7]
  PIN bases[8]
    DIRECTION INPUT ;
    USE SIGNAL ;
    PORT
      LAYER M5 ;
        RECT 6.384 388.608 6.408 388.800 ;
    END
  END bases[8]
  PIN bases[9]
    DIRECTION INPUT ;
    USE SIGNAL ;
    PORT
      LAYER M3 ;
        RECT 6.801 388.608 6.825 388.800 ;
    END
  END bases[9]
  PIN bases[10]
    DIRECTION INPUT ;
    USE SIGNAL ;
    PORT
      LAYER M5 ;
        RECT 7.248 388.608 7.272 388.800 ;
    END
  END bases[10]
  PIN bases[11]
    DIRECTION INPUT ;
    USE SIGNAL ;
    PORT
      LAYER M3 ;
        RECT 7.701 388.608 7.725 388.800 ;
    END
  END bases[11]
  PIN bases[12]
    DIRECTION INPUT ;
    USE SIGNAL ;
    PORT
      LAYER M5 ;
        RECT 8.160 388.608 8.184 388.800 ;
    END
  END bases[12]
  PIN bases[13]
    DIRECTION INPUT ;
    USE SIGNAL ;
    PORT
      LAYER M3 ;
        RECT 8.601 388.608 8.625 388.800 ;
    END
  END bases[13]
  PIN bases[14]
    DIRECTION INPUT ;
    USE SIGNAL ;
    PORT
      LAYER M5 ;
        RECT 9.024 388.608 9.048 388.800 ;
    END
  END bases[14]
  PIN bases[15]
    DIRECTION INPUT ;
    USE SIGNAL ;
    PORT
      LAYER M3 ;
        RECT 9.465 388.608 9.489 388.800 ;
    END
  END bases[15]
  PIN bases[16]
    DIRECTION INPUT ;
    USE SIGNAL ;
    PORT
      LAYER M5 ;
        RECT 9.936 388.608 9.960 388.800 ;
    END
  END bases[16]
  PIN bases[17]
    DIRECTION INPUT ;
    USE SIGNAL ;
    PORT
      LAYER M3 ;
        RECT 10.365 388.608 10.389 388.800 ;
    END
  END bases[17]
  PIN bases[18]
    DIRECTION INPUT ;
    USE SIGNAL ;
    PORT
      LAYER M5 ;
        RECT 10.800 388.608 10.824 388.800 ;
    END
  END bases[18]
  PIN bases[19]
    DIRECTION INPUT ;
    USE SIGNAL ;
    PORT
      LAYER M3 ;
        RECT 11.265 388.608 11.289 388.800 ;
    END
  END bases[19]
  PIN bases[20]
    DIRECTION INPUT ;
    USE SIGNAL ;
    PORT
      LAYER M5 ;
        RECT 11.712 388.608 11.736 388.800 ;
    END
  END bases[20]
  PIN bases[21]
    DIRECTION INPUT ;
    USE SIGNAL ;
    PORT
      LAYER M3 ;
        RECT 12.165 388.608 12.189 388.800 ;
    END
  END bases[21]
  PIN bases[22]
    DIRECTION INPUT ;
    USE SIGNAL ;
    PORT
      LAYER M5 ;
        RECT 12.576 388.608 12.600 388.800 ;
    END
  END bases[22]
  PIN bases[23]
    DIRECTION INPUT ;
    USE SIGNAL ;
    PORT
      LAYER M3 ;
        RECT 13.029 388.608 13.053 388.800 ;
    END
  END bases[23]
  PIN bases[24]
    DIRECTION INPUT ;
    USE SIGNAL ;
    PORT
      LAYER M5 ;
        RECT 13.488 388.608 13.512 388.800 ;
    END
  END bases[24]
  PIN bases[25]
    DIRECTION INPUT ;
    USE SIGNAL ;
    PORT
      LAYER M3 ;
        RECT 13.929 388.608 13.953 388.800 ;
    END
  END bases[25]
  PIN bases[26]
    DIRECTION INPUT ;
    USE SIGNAL ;
    PORT
      LAYER M5 ;
        RECT 14.352 388.608 14.376 388.800 ;
    END
  END bases[26]
  PIN bases[27]
    DIRECTION INPUT ;
    USE SIGNAL ;
    PORT
      LAYER M3 ;
        RECT 14.829 388.608 14.853 388.800 ;
    END
  END bases[27]
  PIN bases[28]
    DIRECTION INPUT ;
    USE SIGNAL ;
    PORT
      LAYER M5 ;
        RECT 15.264 388.608 15.288 388.800 ;
    END
  END bases[28]
  PIN bases[29]
    DIRECTION INPUT ;
    USE SIGNAL ;
    PORT
      LAYER M3 ;
        RECT 15.693 388.608 15.717 388.800 ;
    END
  END bases[29]
  PIN bases[30]
    DIRECTION INPUT ;
    USE SIGNAL ;
    PORT
      LAYER M5 ;
        RECT 16.128 388.608 16.152 388.800 ;
    END
  END bases[30]
  PIN bases[31]
    DIRECTION INPUT ;
    USE SIGNAL ;
    PORT
      LAYER M3 ;
        RECT 16.593 388.608 16.617 388.800 ;
    END
  END bases[31]
  PIN bases[32]
    DIRECTION INPUT ;
    USE SIGNAL ;
    PORT
      LAYER M5 ;
        RECT 17.040 388.608 17.064 388.800 ;
    END
  END bases[32]
  PIN bases[33]
    DIRECTION INPUT ;
    USE SIGNAL ;
    PORT
      LAYER M3 ;
        RECT 17.493 388.608 17.517 388.800 ;
    END
  END bases[33]
  PIN bases[34]
    DIRECTION INPUT ;
    USE SIGNAL ;
    PORT
      LAYER M5 ;
        RECT 17.904 388.608 17.928 388.800 ;
    END
  END bases[34]
  PIN bases[35]
    DIRECTION INPUT ;
    USE SIGNAL ;
    PORT
      LAYER M3 ;
        RECT 18.357 388.608 18.381 388.800 ;
    END
  END bases[35]
  PIN bases[36]
    DIRECTION INPUT ;
    USE SIGNAL ;
    PORT
      LAYER M5 ;
        RECT 18.816 388.608 18.840 388.800 ;
    END
  END bases[36]
  PIN bases[37]
    DIRECTION INPUT ;
    USE SIGNAL ;
    PORT
      LAYER M3 ;
        RECT 19.257 388.608 19.281 388.800 ;
    END
  END bases[37]
  PIN bases[38]
    DIRECTION INPUT ;
    USE SIGNAL ;
    PORT
      LAYER M5 ;
        RECT 19.728 388.608 19.752 388.800 ;
    END
  END bases[38]
  PIN bases[39]
    DIRECTION INPUT ;
    USE SIGNAL ;
    PORT
      LAYER M3 ;
        RECT 20.157 388.608 20.181 388.800 ;
    END
  END bases[39]
  PIN bases[40]
    DIRECTION INPUT ;
    USE SIGNAL ;
    PORT
      LAYER M5 ;
        RECT 20.592 388.608 20.616 388.800 ;
    END
  END bases[40]
  PIN bases[41]
    DIRECTION INPUT ;
    USE SIGNAL ;
    PORT
      LAYER M3 ;
        RECT 21.021 388.608 21.045 388.800 ;
    END
  END bases[41]
  PIN bases[42]
    DIRECTION INPUT ;
    USE SIGNAL ;
    PORT
      LAYER M5 ;
        RECT 21.504 388.608 21.528 388.800 ;
    END
  END bases[42]
  PIN bases[43]
    DIRECTION INPUT ;
    USE SIGNAL ;
    PORT
      LAYER M3 ;
        RECT 21.921 388.608 21.945 388.800 ;
    END
  END bases[43]
  PIN bases[44]
    DIRECTION INPUT ;
    USE SIGNAL ;
    PORT
      LAYER M5 ;
        RECT 22.368 388.608 22.392 388.800 ;
    END
  END bases[44]
  PIN bases[45]
    DIRECTION INPUT ;
    USE SIGNAL ;
    PORT
      LAYER M3 ;
        RECT 22.821 388.608 22.845 388.800 ;
    END
  END bases[45]
  PIN bases[46]
    DIRECTION INPUT ;
    USE SIGNAL ;
    PORT
      LAYER M5 ;
        RECT 23.280 388.608 23.304 388.800 ;
    END
  END bases[46]
  PIN bases[47]
    DIRECTION INPUT ;
    USE SIGNAL ;
    PORT
      LAYER M3 ;
        RECT 23.721 388.608 23.745 388.800 ;
    END
  END bases[47]
  PIN bases[48]
    DIRECTION INPUT ;
    USE SIGNAL ;
    PORT
      LAYER M5 ;
        RECT 24.144 388.608 24.168 388.800 ;
    END
  END bases[48]
  PIN bases[49]
    DIRECTION INPUT ;
    USE SIGNAL ;
    PORT
      LAYER M3 ;
        RECT 24.585 388.608 24.609 388.800 ;
    END
  END bases[49]
  PIN bases[50]
    DIRECTION INPUT ;
    USE SIGNAL ;
    PORT
      LAYER M5 ;
        RECT 25.056 388.608 25.080 388.800 ;
    END
  END bases[50]
  PIN bases[51]
    DIRECTION INPUT ;
    USE SIGNAL ;
    PORT
      LAYER M3 ;
        RECT 25.485 388.608 25.509 388.800 ;
    END
  END bases[51]
  PIN bases[52]
    DIRECTION INPUT ;
    USE SIGNAL ;
    PORT
      LAYER M5 ;
        RECT 25.920 388.608 25.944 388.800 ;
    END
  END bases[52]
  PIN bases[53]
    DIRECTION INPUT ;
    USE SIGNAL ;
    PORT
      LAYER M3 ;
        RECT 26.385 388.608 26.409 388.800 ;
    END
  END bases[53]
  PIN bases[54]
    DIRECTION INPUT ;
    USE SIGNAL ;
    PORT
      LAYER M5 ;
        RECT 26.832 388.608 26.856 388.800 ;
    END
  END bases[54]
  PIN bases[55]
    DIRECTION INPUT ;
    USE SIGNAL ;
    PORT
      LAYER M3 ;
        RECT 27.249 388.608 27.273 388.800 ;
    END
  END bases[55]
  PIN bases[56]
    DIRECTION INPUT ;
    USE SIGNAL ;
    PORT
      LAYER M5 ;
        RECT 27.696 388.608 27.720 388.800 ;
    END
  END bases[56]
  PIN bases[57]
    DIRECTION INPUT ;
    USE SIGNAL ;
    PORT
      LAYER M3 ;
        RECT 28.149 388.608 28.173 388.800 ;
    END
  END bases[57]
  PIN bases[58]
    DIRECTION INPUT ;
    USE SIGNAL ;
    PORT
      LAYER M5 ;
        RECT 28.608 388.608 28.632 388.800 ;
    END
  END bases[58]
  PIN bases[59]
    DIRECTION INPUT ;
    USE SIGNAL ;
    PORT
      LAYER M3 ;
        RECT 29.049 388.608 29.073 388.800 ;
    END
  END bases[59]
  PIN bases[60]
    DIRECTION INPUT ;
    USE SIGNAL ;
    PORT
      LAYER M5 ;
        RECT 29.472 388.608 29.496 388.800 ;
    END
  END bases[60]
  PIN bases[61]
    DIRECTION INPUT ;
    USE SIGNAL ;
    PORT
      LAYER M3 ;
        RECT 29.913 388.608 29.937 388.800 ;
    END
  END bases[61]
  PIN bases[62]
    DIRECTION INPUT ;
    USE SIGNAL ;
    PORT
      LAYER M5 ;
        RECT 30.384 388.608 30.408 388.800 ;
    END
  END bases[62]
  PIN bases[63]
    DIRECTION INPUT ;
    USE SIGNAL ;
    PORT
      LAYER M3 ;
        RECT 30.813 388.608 30.837 388.800 ;
    END
  END bases[63]
  PIN bases[64]
    DIRECTION INPUT ;
    USE SIGNAL ;
    PORT
      LAYER M5 ;
        RECT 31.248 388.608 31.272 388.800 ;
    END
  END bases[64]
  PIN bases[65]
    DIRECTION INPUT ;
    USE SIGNAL ;
    PORT
      LAYER M3 ;
        RECT 31.713 388.608 31.737 388.800 ;
    END
  END bases[65]
  PIN bases[66]
    DIRECTION INPUT ;
    USE SIGNAL ;
    PORT
      LAYER M5 ;
        RECT 32.160 388.608 32.184 388.800 ;
    END
  END bases[66]
  PIN bases[67]
    DIRECTION INPUT ;
    USE SIGNAL ;
    PORT
      LAYER M3 ;
        RECT 32.613 388.608 32.637 388.800 ;
    END
  END bases[67]
  PIN bases[68]
    DIRECTION INPUT ;
    USE SIGNAL ;
    PORT
      LAYER M5 ;
        RECT 33.024 388.608 33.048 388.800 ;
    END
  END bases[68]
  PIN bases[69]
    DIRECTION INPUT ;
    USE SIGNAL ;
    PORT
      LAYER M3 ;
        RECT 33.477 388.608 33.501 388.800 ;
    END
  END bases[69]
  PIN bases[70]
    DIRECTION INPUT ;
    USE SIGNAL ;
    PORT
      LAYER M5 ;
        RECT 33.936 388.608 33.960 388.800 ;
    END
  END bases[70]
  PIN bases[71]
    DIRECTION INPUT ;
    USE SIGNAL ;
    PORT
      LAYER M3 ;
        RECT 34.377 388.608 34.401 388.800 ;
    END
  END bases[71]
  PIN bases[72]
    DIRECTION INPUT ;
    USE SIGNAL ;
    PORT
      LAYER M5 ;
        RECT 34.800 388.608 34.824 388.800 ;
    END
  END bases[72]
  PIN bases[73]
    DIRECTION INPUT ;
    USE SIGNAL ;
    PORT
      LAYER M3 ;
        RECT 35.277 388.608 35.301 388.800 ;
    END
  END bases[73]
  PIN bases[74]
    DIRECTION INPUT ;
    USE SIGNAL ;
    PORT
      LAYER M5 ;
        RECT 35.712 388.608 35.736 388.800 ;
    END
  END bases[74]
  PIN bases[75]
    DIRECTION INPUT ;
    USE SIGNAL ;
    PORT
      LAYER M3 ;
        RECT 36.141 388.608 36.165 388.800 ;
    END
  END bases[75]
  PIN bases[76]
    DIRECTION INPUT ;
    USE SIGNAL ;
    PORT
      LAYER M5 ;
        RECT 36.576 388.608 36.600 388.800 ;
    END
  END bases[76]
  PIN bases[77]
    DIRECTION INPUT ;
    USE SIGNAL ;
    PORT
      LAYER M3 ;
        RECT 37.041 388.608 37.065 388.800 ;
    END
  END bases[77]
  PIN bases[78]
    DIRECTION INPUT ;
    USE SIGNAL ;
    PORT
      LAYER M5 ;
        RECT 37.488 388.608 37.512 388.800 ;
    END
  END bases[78]
  PIN bases[79]
    DIRECTION INPUT ;
    USE SIGNAL ;
    PORT
      LAYER M3 ;
        RECT 37.941 388.608 37.965 388.800 ;
    END
  END bases[79]
  PIN bases[80]
    DIRECTION INPUT ;
    USE SIGNAL ;
    PORT
      LAYER M5 ;
        RECT 38.352 388.608 38.376 388.800 ;
    END
  END bases[80]
  PIN bases[81]
    DIRECTION INPUT ;
    USE SIGNAL ;
    PORT
      LAYER M3 ;
        RECT 38.805 388.608 38.829 388.800 ;
    END
  END bases[81]
  PIN bases[82]
    DIRECTION INPUT ;
    USE SIGNAL ;
    PORT
      LAYER M5 ;
        RECT 39.264 388.608 39.288 388.800 ;
    END
  END bases[82]
  PIN bases[83]
    DIRECTION INPUT ;
    USE SIGNAL ;
    PORT
      LAYER M3 ;
        RECT 39.705 388.608 39.729 388.800 ;
    END
  END bases[83]
  PIN bases[84]
    DIRECTION INPUT ;
    USE SIGNAL ;
    PORT
      LAYER M5 ;
        RECT 40.128 388.608 40.152 388.800 ;
    END
  END bases[84]
  PIN bases[85]
    DIRECTION INPUT ;
    USE SIGNAL ;
    PORT
      LAYER M3 ;
        RECT 40.605 388.608 40.629 388.800 ;
    END
  END bases[85]
  PIN bases[86]
    DIRECTION INPUT ;
    USE SIGNAL ;
    PORT
      LAYER M5 ;
        RECT 41.040 388.608 41.064 388.800 ;
    END
  END bases[86]
  PIN bases[87]
    DIRECTION INPUT ;
    USE SIGNAL ;
    PORT
      LAYER M3 ;
        RECT 41.469 388.608 41.493 388.800 ;
    END
  END bases[87]
  PIN bases[88]
    DIRECTION INPUT ;
    USE SIGNAL ;
    PORT
      LAYER M5 ;
        RECT 41.952 388.608 41.976 388.800 ;
    END
  END bases[88]
  PIN bases[89]
    DIRECTION INPUT ;
    USE SIGNAL ;
    PORT
      LAYER M3 ;
        RECT 42.369 388.608 42.393 388.800 ;
    END
  END bases[89]
  PIN bases[90]
    DIRECTION INPUT ;
    USE SIGNAL ;
    PORT
      LAYER M5 ;
        RECT 42.816 388.608 42.840 388.800 ;
    END
  END bases[90]
  PIN bases[91]
    DIRECTION INPUT ;
    USE SIGNAL ;
    PORT
      LAYER M3 ;
        RECT 43.269 388.608 43.293 388.800 ;
    END
  END bases[91]
  PIN bases[92]
    DIRECTION INPUT ;
    USE SIGNAL ;
    PORT
      LAYER M5 ;
        RECT 43.728 388.608 43.752 388.800 ;
    END
  END bases[92]
  PIN bases[93]
    DIRECTION INPUT ;
    USE SIGNAL ;
    PORT
      LAYER M3 ;
        RECT 44.169 388.608 44.193 388.800 ;
    END
  END bases[93]
  PIN bases[94]
    DIRECTION INPUT ;
    USE SIGNAL ;
    PORT
      LAYER M5 ;
        RECT 44.592 388.608 44.616 388.800 ;
    END
  END bases[94]
  PIN bases[95]
    DIRECTION INPUT ;
    USE SIGNAL ;
    PORT
      LAYER M3 ;
        RECT 45.033 388.608 45.057 388.800 ;
    END
  END bases[95]
  PIN bases[96]
    DIRECTION INPUT ;
    USE SIGNAL ;
    PORT
      LAYER M5 ;
        RECT 45.504 388.608 45.528 388.800 ;
    END
  END bases[96]
  PIN bases[97]
    DIRECTION INPUT ;
    USE SIGNAL ;
    PORT
      LAYER M3 ;
        RECT 45.933 388.608 45.957 388.800 ;
    END
  END bases[97]
  PIN bases[98]
    DIRECTION INPUT ;
    USE SIGNAL ;
    PORT
      LAYER M5 ;
        RECT 46.368 388.608 46.392 388.800 ;
    END
  END bases[98]
  PIN bases[99]
    DIRECTION INPUT ;
    USE SIGNAL ;
    PORT
      LAYER M3 ;
        RECT 46.833 388.608 46.857 388.800 ;
    END
  END bases[99]
  PIN bases[100]
    DIRECTION INPUT ;
    USE SIGNAL ;
    PORT
      LAYER M5 ;
        RECT 47.280 388.608 47.304 388.800 ;
    END
  END bases[100]
  PIN bases[101]
    DIRECTION INPUT ;
    USE SIGNAL ;
    PORT
      LAYER M3 ;
        RECT 47.697 388.608 47.721 388.800 ;
    END
  END bases[101]
  PIN bases[102]
    DIRECTION INPUT ;
    USE SIGNAL ;
    PORT
      LAYER M5 ;
        RECT 48.144 388.608 48.168 388.800 ;
    END
  END bases[102]
  PIN bases[103]
    DIRECTION INPUT ;
    USE SIGNAL ;
    PORT
      LAYER M3 ;
        RECT 48.597 388.608 48.621 388.800 ;
    END
  END bases[103]
  PIN bases[104]
    DIRECTION INPUT ;
    USE SIGNAL ;
    PORT
      LAYER M5 ;
        RECT 49.056 388.608 49.080 388.800 ;
    END
  END bases[104]
  PIN bases[105]
    DIRECTION INPUT ;
    USE SIGNAL ;
    PORT
      LAYER M3 ;
        RECT 49.497 388.608 49.521 388.800 ;
    END
  END bases[105]
  PIN bases[106]
    DIRECTION INPUT ;
    USE SIGNAL ;
    PORT
      LAYER M5 ;
        RECT 49.920 388.608 49.944 388.800 ;
    END
  END bases[106]
  PIN bases[107]
    DIRECTION INPUT ;
    USE SIGNAL ;
    PORT
      LAYER M3 ;
        RECT 50.361 388.608 50.385 388.800 ;
    END
  END bases[107]
  PIN bases[108]
    DIRECTION INPUT ;
    USE SIGNAL ;
    PORT
      LAYER M5 ;
        RECT 50.832 388.608 50.856 388.800 ;
    END
  END bases[108]
  PIN bases[109]
    DIRECTION INPUT ;
    USE SIGNAL ;
    PORT
      LAYER M3 ;
        RECT 51.261 388.608 51.285 388.800 ;
    END
  END bases[109]
  PIN bases[110]
    DIRECTION INPUT ;
    USE SIGNAL ;
    PORT
      LAYER M5 ;
        RECT 51.696 388.608 51.720 388.800 ;
    END
  END bases[110]
  PIN bases[111]
    DIRECTION INPUT ;
    USE SIGNAL ;
    PORT
      LAYER M3 ;
        RECT 52.161 388.608 52.185 388.800 ;
    END
  END bases[111]
  PIN bases[112]
    DIRECTION INPUT ;
    USE SIGNAL ;
    PORT
      LAYER M5 ;
        RECT 52.608 388.608 52.632 388.800 ;
    END
  END bases[112]
  PIN bases[113]
    DIRECTION INPUT ;
    USE SIGNAL ;
    PORT
      LAYER M3 ;
        RECT 53.025 388.608 53.049 388.800 ;
    END
  END bases[113]
  PIN bases[114]
    DIRECTION INPUT ;
    USE SIGNAL ;
    PORT
      LAYER M5 ;
        RECT 53.472 388.608 53.496 388.800 ;
    END
  END bases[114]
  PIN bases[115]
    DIRECTION INPUT ;
    USE SIGNAL ;
    PORT
      LAYER M3 ;
        RECT 53.925 388.608 53.949 388.800 ;
    END
  END bases[115]
  PIN bases[116]
    DIRECTION INPUT ;
    USE SIGNAL ;
    PORT
      LAYER M5 ;
        RECT 54.384 388.608 54.408 388.800 ;
    END
  END bases[116]
  PIN bases[117]
    DIRECTION INPUT ;
    USE SIGNAL ;
    PORT
      LAYER M3 ;
        RECT 54.825 388.608 54.849 388.800 ;
    END
  END bases[117]
  PIN bases[118]
    DIRECTION INPUT ;
    USE SIGNAL ;
    PORT
      LAYER M5 ;
        RECT 55.248 388.608 55.272 388.800 ;
    END
  END bases[118]
  PIN bases[119]
    DIRECTION INPUT ;
    USE SIGNAL ;
    PORT
      LAYER M3 ;
        RECT 55.725 388.608 55.749 388.800 ;
    END
  END bases[119]
  PIN bases[120]
    DIRECTION INPUT ;
    USE SIGNAL ;
    PORT
      LAYER M5 ;
        RECT 56.160 388.608 56.184 388.800 ;
    END
  END bases[120]
  PIN bases[121]
    DIRECTION INPUT ;
    USE SIGNAL ;
    PORT
      LAYER M3 ;
        RECT 56.589 388.608 56.613 388.800 ;
    END
  END bases[121]
  PIN bases[122]
    DIRECTION INPUT ;
    USE SIGNAL ;
    PORT
      LAYER M5 ;
        RECT 57.024 388.608 57.048 388.800 ;
    END
  END bases[122]
  PIN bases[123]
    DIRECTION INPUT ;
    USE SIGNAL ;
    PORT
      LAYER M3 ;
        RECT 57.489 388.608 57.513 388.800 ;
    END
  END bases[123]
  PIN bases[124]
    DIRECTION INPUT ;
    USE SIGNAL ;
    PORT
      LAYER M5 ;
        RECT 57.936 388.608 57.960 388.800 ;
    END
  END bases[124]
  PIN bases[125]
    DIRECTION INPUT ;
    USE SIGNAL ;
    PORT
      LAYER M3 ;
        RECT 58.389 388.608 58.413 388.800 ;
    END
  END bases[125]
  PIN bases[126]
    DIRECTION INPUT ;
    USE SIGNAL ;
    PORT
      LAYER M5 ;
        RECT 58.800 388.608 58.824 388.800 ;
    END
  END bases[126]
  PIN bases[127]
    DIRECTION INPUT ;
    USE SIGNAL ;
    PORT
      LAYER M3 ;
        RECT 59.253 388.608 59.277 388.800 ;
    END
  END bases[127]
  PIN bases[128]
    DIRECTION INPUT ;
    USE SIGNAL ;
    PORT
      LAYER M5 ;
        RECT 59.712 388.608 59.736 388.800 ;
    END
  END bases[128]
  PIN bases[129]
    DIRECTION INPUT ;
    USE SIGNAL ;
    PORT
      LAYER M3 ;
        RECT 60.153 388.608 60.177 388.800 ;
    END
  END bases[129]
  PIN bases[130]
    DIRECTION INPUT ;
    USE SIGNAL ;
    PORT
      LAYER M5 ;
        RECT 60.576 388.608 60.600 388.800 ;
    END
  END bases[130]
  PIN bases[131]
    DIRECTION INPUT ;
    USE SIGNAL ;
    PORT
      LAYER M3 ;
        RECT 61.053 388.608 61.077 388.800 ;
    END
  END bases[131]
  PIN bases[132]
    DIRECTION INPUT ;
    USE SIGNAL ;
    PORT
      LAYER M5 ;
        RECT 61.488 388.608 61.512 388.800 ;
    END
  END bases[132]
  PIN bases[133]
    DIRECTION INPUT ;
    USE SIGNAL ;
    PORT
      LAYER M3 ;
        RECT 61.917 388.608 61.941 388.800 ;
    END
  END bases[133]
  PIN bases[134]
    DIRECTION INPUT ;
    USE SIGNAL ;
    PORT
      LAYER M5 ;
        RECT 62.352 388.608 62.376 388.800 ;
    END
  END bases[134]
  PIN bases[135]
    DIRECTION INPUT ;
    USE SIGNAL ;
    PORT
      LAYER M3 ;
        RECT 62.817 388.608 62.841 388.800 ;
    END
  END bases[135]
  PIN bases[136]
    DIRECTION INPUT ;
    USE SIGNAL ;
    PORT
      LAYER M5 ;
        RECT 63.264 388.608 63.288 388.800 ;
    END
  END bases[136]
  PIN bases[137]
    DIRECTION INPUT ;
    USE SIGNAL ;
    PORT
      LAYER M3 ;
        RECT 63.717 388.608 63.741 388.800 ;
    END
  END bases[137]
  PIN bases[138]
    DIRECTION INPUT ;
    USE SIGNAL ;
    PORT
      LAYER M5 ;
        RECT 64.176 388.608 64.200 388.800 ;
    END
  END bases[138]
  PIN bases[139]
    DIRECTION INPUT ;
    USE SIGNAL ;
    PORT
      LAYER M3 ;
        RECT 64.581 388.608 64.605 388.800 ;
    END
  END bases[139]
  PIN bases[140]
    DIRECTION INPUT ;
    USE SIGNAL ;
    PORT
      LAYER M5 ;
        RECT 65.040 388.608 65.064 388.800 ;
    END
  END bases[140]
  PIN bases[141]
    DIRECTION INPUT ;
    USE SIGNAL ;
    PORT
      LAYER M3 ;
        RECT 65.481 388.608 65.505 388.800 ;
    END
  END bases[141]
  PIN bases[142]
    DIRECTION INPUT ;
    USE SIGNAL ;
    PORT
      LAYER M5 ;
        RECT 65.952 388.608 65.976 388.800 ;
    END
  END bases[142]
  PIN bases[143]
    DIRECTION INPUT ;
    USE SIGNAL ;
    PORT
      LAYER M3 ;
        RECT 66.381 388.608 66.405 388.800 ;
    END
  END bases[143]
  PIN bases[144]
    DIRECTION INPUT ;
    USE SIGNAL ;
    PORT
      LAYER M5 ;
        RECT 66.816 388.608 66.840 388.800 ;
    END
  END bases[144]
  PIN bases[145]
    DIRECTION INPUT ;
    USE SIGNAL ;
    PORT
      LAYER M3 ;
        RECT 67.281 388.608 67.305 388.800 ;
    END
  END bases[145]
  PIN bases[146]
    DIRECTION INPUT ;
    USE SIGNAL ;
    PORT
      LAYER M5 ;
        RECT 67.728 388.608 67.752 388.800 ;
    END
  END bases[146]
  PIN bases[147]
    DIRECTION INPUT ;
    USE SIGNAL ;
    PORT
      LAYER M3 ;
        RECT 68.145 388.608 68.169 388.800 ;
    END
  END bases[147]
  PIN bases[148]
    DIRECTION INPUT ;
    USE SIGNAL ;
    PORT
      LAYER M5 ;
        RECT 68.592 388.608 68.616 388.800 ;
    END
  END bases[148]
  PIN bases[149]
    DIRECTION INPUT ;
    USE SIGNAL ;
    PORT
      LAYER M3 ;
        RECT 69.045 388.608 69.069 388.800 ;
    END
  END bases[149]
  PIN bases[150]
    DIRECTION INPUT ;
    USE SIGNAL ;
    PORT
      LAYER M5 ;
        RECT 69.504 388.608 69.528 388.800 ;
    END
  END bases[150]
  PIN bases[151]
    DIRECTION INPUT ;
    USE SIGNAL ;
    PORT
      LAYER M3 ;
        RECT 69.945 388.608 69.969 388.800 ;
    END
  END bases[151]
  PIN bases[152]
    DIRECTION INPUT ;
    USE SIGNAL ;
    PORT
      LAYER M5 ;
        RECT 70.368 388.608 70.392 388.800 ;
    END
  END bases[152]
  PIN bases[153]
    DIRECTION INPUT ;
    USE SIGNAL ;
    PORT
      LAYER M3 ;
        RECT 70.809 388.608 70.833 388.800 ;
    END
  END bases[153]
  PIN bases[154]
    DIRECTION INPUT ;
    USE SIGNAL ;
    PORT
      LAYER M5 ;
        RECT 71.280 388.608 71.304 388.800 ;
    END
  END bases[154]
  PIN bases[155]
    DIRECTION INPUT ;
    USE SIGNAL ;
    PORT
      LAYER M3 ;
        RECT 71.709 388.608 71.733 388.800 ;
    END
  END bases[155]
  PIN bases[156]
    DIRECTION INPUT ;
    USE SIGNAL ;
    PORT
      LAYER M5 ;
        RECT 72.144 388.608 72.168 388.800 ;
    END
  END bases[156]
  PIN bases[157]
    DIRECTION INPUT ;
    USE SIGNAL ;
    PORT
      LAYER M3 ;
        RECT 72.609 388.608 72.633 388.800 ;
    END
  END bases[157]
  PIN bases[158]
    DIRECTION INPUT ;
    USE SIGNAL ;
    PORT
      LAYER M5 ;
        RECT 73.056 388.608 73.080 388.800 ;
    END
  END bases[158]
  PIN bases[159]
    DIRECTION INPUT ;
    USE SIGNAL ;
    PORT
      LAYER M3 ;
        RECT 73.473 388.608 73.497 388.800 ;
    END
  END bases[159]
  PIN bases[160]
    DIRECTION INPUT ;
    USE SIGNAL ;
    PORT
      LAYER M5 ;
        RECT 73.920 388.608 73.944 388.800 ;
    END
  END bases[160]
  PIN bases[161]
    DIRECTION INPUT ;
    USE SIGNAL ;
    PORT
      LAYER M3 ;
        RECT 74.373 388.608 74.397 388.800 ;
    END
  END bases[161]
  PIN bases[162]
    DIRECTION INPUT ;
    USE SIGNAL ;
    PORT
      LAYER M5 ;
        RECT 74.832 388.608 74.856 388.800 ;
    END
  END bases[162]
  PIN bases[163]
    DIRECTION INPUT ;
    USE SIGNAL ;
    PORT
      LAYER M3 ;
        RECT 75.273 388.608 75.297 388.800 ;
    END
  END bases[163]
  PIN bases[164]
    DIRECTION INPUT ;
    USE SIGNAL ;
    PORT
      LAYER M5 ;
        RECT 75.696 388.608 75.720 388.800 ;
    END
  END bases[164]
  PIN bases[165]
    DIRECTION INPUT ;
    USE SIGNAL ;
    PORT
      LAYER M3 ;
        RECT 76.137 388.608 76.161 388.800 ;
    END
  END bases[165]
  PIN bases[166]
    DIRECTION INPUT ;
    USE SIGNAL ;
    PORT
      LAYER M5 ;
        RECT 76.608 388.608 76.632 388.800 ;
    END
  END bases[166]
  PIN bases[167]
    DIRECTION INPUT ;
    USE SIGNAL ;
    PORT
      LAYER M3 ;
        RECT 77.037 388.608 77.061 388.800 ;
    END
  END bases[167]
  PIN bases[168]
    DIRECTION INPUT ;
    USE SIGNAL ;
    PORT
      LAYER M5 ;
        RECT 77.472 388.608 77.496 388.800 ;
    END
  END bases[168]
  PIN bases[169]
    DIRECTION INPUT ;
    USE SIGNAL ;
    PORT
      LAYER M3 ;
        RECT 77.937 388.608 77.961 388.800 ;
    END
  END bases[169]
  PIN bases[170]
    DIRECTION INPUT ;
    USE SIGNAL ;
    PORT
      LAYER M5 ;
        RECT 78.384 388.608 78.408 388.800 ;
    END
  END bases[170]
  PIN bases[171]
    DIRECTION INPUT ;
    USE SIGNAL ;
    PORT
      LAYER M3 ;
        RECT 78.837 388.608 78.861 388.800 ;
    END
  END bases[171]
  PIN bases[172]
    DIRECTION INPUT ;
    USE SIGNAL ;
    PORT
      LAYER M5 ;
        RECT 79.248 388.608 79.272 388.800 ;
    END
  END bases[172]
  PIN bases[173]
    DIRECTION INPUT ;
    USE SIGNAL ;
    PORT
      LAYER M3 ;
        RECT 79.701 388.608 79.725 388.800 ;
    END
  END bases[173]
  PIN bases[174]
    DIRECTION INPUT ;
    USE SIGNAL ;
    PORT
      LAYER M5 ;
        RECT 80.160 388.608 80.184 388.800 ;
    END
  END bases[174]
  PIN bases[175]
    DIRECTION INPUT ;
    USE SIGNAL ;
    PORT
      LAYER M3 ;
        RECT 80.601 388.608 80.625 388.800 ;
    END
  END bases[175]
  PIN bases[176]
    DIRECTION INPUT ;
    USE SIGNAL ;
    PORT
      LAYER M5 ;
        RECT 81.024 388.608 81.048 388.800 ;
    END
  END bases[176]
  PIN bases[177]
    DIRECTION INPUT ;
    USE SIGNAL ;
    PORT
      LAYER M3 ;
        RECT 81.501 388.608 81.525 388.800 ;
    END
  END bases[177]
  PIN bases[178]
    DIRECTION INPUT ;
    USE SIGNAL ;
    PORT
      LAYER M5 ;
        RECT 81.936 388.608 81.960 388.800 ;
    END
  END bases[178]
  PIN bases[179]
    DIRECTION INPUT ;
    USE SIGNAL ;
    PORT
      LAYER M3 ;
        RECT 82.365 388.608 82.389 388.800 ;
    END
  END bases[179]
  PIN bases[180]
    DIRECTION INPUT ;
    USE SIGNAL ;
    PORT
      LAYER M5 ;
        RECT 82.800 388.608 82.824 388.800 ;
    END
  END bases[180]
  PIN bases[181]
    DIRECTION INPUT ;
    USE SIGNAL ;
    PORT
      LAYER M3 ;
        RECT 83.265 388.608 83.289 388.800 ;
    END
  END bases[181]
  PIN bases[182]
    DIRECTION INPUT ;
    USE SIGNAL ;
    PORT
      LAYER M5 ;
        RECT 83.712 388.608 83.736 388.800 ;
    END
  END bases[182]
  PIN bases[183]
    DIRECTION INPUT ;
    USE SIGNAL ;
    PORT
      LAYER M3 ;
        RECT 84.165 388.608 84.189 388.800 ;
    END
  END bases[183]
  PIN bases[184]
    DIRECTION INPUT ;
    USE SIGNAL ;
    PORT
      LAYER M5 ;
        RECT 84.624 388.608 84.648 388.800 ;
    END
  END bases[184]
  PIN bases[185]
    DIRECTION INPUT ;
    USE SIGNAL ;
    PORT
      LAYER M3 ;
        RECT 85.029 388.608 85.053 388.800 ;
    END
  END bases[185]
  PIN bases[186]
    DIRECTION INPUT ;
    USE SIGNAL ;
    PORT
      LAYER M5 ;
        RECT 85.488 388.608 85.512 388.800 ;
    END
  END bases[186]
  PIN bases[187]
    DIRECTION INPUT ;
    USE SIGNAL ;
    PORT
      LAYER M3 ;
        RECT 85.929 388.608 85.953 388.800 ;
    END
  END bases[187]
  PIN bases[188]
    DIRECTION INPUT ;
    USE SIGNAL ;
    PORT
      LAYER M5 ;
        RECT 86.400 388.608 86.424 388.800 ;
    END
  END bases[188]
  PIN bases[189]
    DIRECTION INPUT ;
    USE SIGNAL ;
    PORT
      LAYER M3 ;
        RECT 86.829 388.608 86.853 388.800 ;
    END
  END bases[189]
  PIN bases[190]
    DIRECTION INPUT ;
    USE SIGNAL ;
    PORT
      LAYER M5 ;
        RECT 87.264 388.608 87.288 388.800 ;
    END
  END bases[190]
  PIN bases[191]
    DIRECTION INPUT ;
    USE SIGNAL ;
    PORT
      LAYER M3 ;
        RECT 87.729 388.608 87.753 388.800 ;
    END
  END bases[191]
  PIN bases[192]
    DIRECTION INPUT ;
    USE SIGNAL ;
    PORT
      LAYER M5 ;
        RECT 88.176 388.608 88.200 388.800 ;
    END
  END bases[192]
  PIN bases[193]
    DIRECTION INPUT ;
    USE SIGNAL ;
    PORT
      LAYER M3 ;
        RECT 88.593 388.608 88.617 388.800 ;
    END
  END bases[193]
  PIN bases[194]
    DIRECTION INPUT ;
    USE SIGNAL ;
    PORT
      LAYER M5 ;
        RECT 89.040 388.608 89.064 388.800 ;
    END
  END bases[194]
  PIN bases[195]
    DIRECTION INPUT ;
    USE SIGNAL ;
    PORT
      LAYER M3 ;
        RECT 89.493 388.608 89.517 388.800 ;
    END
  END bases[195]
  PIN bases[196]
    DIRECTION INPUT ;
    USE SIGNAL ;
    PORT
      LAYER M5 ;
        RECT 89.952 388.608 89.976 388.800 ;
    END
  END bases[196]
  PIN bases[197]
    DIRECTION INPUT ;
    USE SIGNAL ;
    PORT
      LAYER M3 ;
        RECT 90.393 388.608 90.417 388.800 ;
    END
  END bases[197]
  PIN bases[198]
    DIRECTION INPUT ;
    USE SIGNAL ;
    PORT
      LAYER M5 ;
        RECT 90.816 388.608 90.840 388.800 ;
    END
  END bases[198]
  PIN bases[199]
    DIRECTION INPUT ;
    USE SIGNAL ;
    PORT
      LAYER M3 ;
        RECT 91.257 388.608 91.281 388.800 ;
    END
  END bases[199]
  PIN bases[200]
    DIRECTION INPUT ;
    USE SIGNAL ;
    PORT
      LAYER M5 ;
        RECT 91.728 388.608 91.752 388.800 ;
    END
  END bases[200]
  PIN bases[201]
    DIRECTION INPUT ;
    USE SIGNAL ;
    PORT
      LAYER M3 ;
        RECT 92.157 388.608 92.181 388.800 ;
    END
  END bases[201]
  PIN bases[202]
    DIRECTION INPUT ;
    USE SIGNAL ;
    PORT
      LAYER M5 ;
        RECT 92.592 388.608 92.616 388.800 ;
    END
  END bases[202]
  PIN bases[203]
    DIRECTION INPUT ;
    USE SIGNAL ;
    PORT
      LAYER M3 ;
        RECT 93.057 388.608 93.081 388.800 ;
    END
  END bases[203]
  PIN bases[204]
    DIRECTION INPUT ;
    USE SIGNAL ;
    PORT
      LAYER M5 ;
        RECT 93.504 388.608 93.528 388.800 ;
    END
  END bases[204]
  PIN bases[205]
    DIRECTION INPUT ;
    USE SIGNAL ;
    PORT
      LAYER M3 ;
        RECT 93.921 388.608 93.945 388.800 ;
    END
  END bases[205]
  PIN bases[206]
    DIRECTION INPUT ;
    USE SIGNAL ;
    PORT
      LAYER M5 ;
        RECT 94.368 388.608 94.392 388.800 ;
    END
  END bases[206]
  PIN bases[207]
    DIRECTION INPUT ;
    USE SIGNAL ;
    PORT
      LAYER M3 ;
        RECT 94.821 388.608 94.845 388.800 ;
    END
  END bases[207]
  PIN bases[208]
    DIRECTION INPUT ;
    USE SIGNAL ;
    PORT
      LAYER M5 ;
        RECT 95.280 388.608 95.304 388.800 ;
    END
  END bases[208]
  PIN bases[209]
    DIRECTION INPUT ;
    USE SIGNAL ;
    PORT
      LAYER M3 ;
        RECT 95.721 388.608 95.745 388.800 ;
    END
  END bases[209]
  PIN bases[210]
    DIRECTION INPUT ;
    USE SIGNAL ;
    PORT
      LAYER M5 ;
        RECT 96.144 388.608 96.168 388.800 ;
    END
  END bases[210]
  PIN bases[211]
    DIRECTION INPUT ;
    USE SIGNAL ;
    PORT
      LAYER M3 ;
        RECT 96.585 388.608 96.609 388.800 ;
    END
  END bases[211]
  PIN bases[212]
    DIRECTION INPUT ;
    USE SIGNAL ;
    PORT
      LAYER M5 ;
        RECT 97.056 388.608 97.080 388.800 ;
    END
  END bases[212]
  PIN bases[213]
    DIRECTION INPUT ;
    USE SIGNAL ;
    PORT
      LAYER M3 ;
        RECT 97.485 388.608 97.509 388.800 ;
    END
  END bases[213]
  PIN bases[214]
    DIRECTION INPUT ;
    USE SIGNAL ;
    PORT
      LAYER M5 ;
        RECT 97.920 388.608 97.944 388.800 ;
    END
  END bases[214]
  PIN bases[215]
    DIRECTION INPUT ;
    USE SIGNAL ;
    PORT
      LAYER M3 ;
        RECT 98.385 388.608 98.409 388.800 ;
    END
  END bases[215]
  PIN bases[216]
    DIRECTION INPUT ;
    USE SIGNAL ;
    PORT
      LAYER M5 ;
        RECT 98.832 388.608 98.856 388.800 ;
    END
  END bases[216]
  PIN bases[217]
    DIRECTION INPUT ;
    USE SIGNAL ;
    PORT
      LAYER M3 ;
        RECT 99.285 388.608 99.309 388.800 ;
    END
  END bases[217]
  PIN bases[218]
    DIRECTION INPUT ;
    USE SIGNAL ;
    PORT
      LAYER M5 ;
        RECT 99.696 388.608 99.720 388.800 ;
    END
  END bases[218]
  PIN bases[219]
    DIRECTION INPUT ;
    USE SIGNAL ;
    PORT
      LAYER M3 ;
        RECT 100.149 388.608 100.173 388.800 ;
    END
  END bases[219]
  PIN bases[220]
    DIRECTION INPUT ;
    USE SIGNAL ;
    PORT
      LAYER M5 ;
        RECT 100.608 388.608 100.632 388.800 ;
    END
  END bases[220]
  PIN bases[221]
    DIRECTION INPUT ;
    USE SIGNAL ;
    PORT
      LAYER M3 ;
        RECT 101.049 388.608 101.073 388.800 ;
    END
  END bases[221]
  PIN bases[222]
    DIRECTION INPUT ;
    USE SIGNAL ;
    PORT
      LAYER M5 ;
        RECT 101.472 388.608 101.496 388.800 ;
    END
  END bases[222]
  PIN bases[223]
    DIRECTION INPUT ;
    USE SIGNAL ;
    PORT
      LAYER M3 ;
        RECT 101.949 388.608 101.973 388.800 ;
    END
  END bases[223]
  PIN bases[224]
    DIRECTION INPUT ;
    USE SIGNAL ;
    PORT
      LAYER M5 ;
        RECT 102.384 388.608 102.408 388.800 ;
    END
  END bases[224]
  PIN bases[225]
    DIRECTION INPUT ;
    USE SIGNAL ;
    PORT
      LAYER M3 ;
        RECT 102.813 388.608 102.837 388.800 ;
    END
  END bases[225]
  PIN bases[226]
    DIRECTION INPUT ;
    USE SIGNAL ;
    PORT
      LAYER M5 ;
        RECT 103.248 388.608 103.272 388.800 ;
    END
  END bases[226]
  PIN bases[227]
    DIRECTION INPUT ;
    USE SIGNAL ;
    PORT
      LAYER M3 ;
        RECT 103.713 388.608 103.737 388.800 ;
    END
  END bases[227]
  PIN bases[228]
    DIRECTION INPUT ;
    USE SIGNAL ;
    PORT
      LAYER M5 ;
        RECT 104.160 388.608 104.184 388.800 ;
    END
  END bases[228]
  PIN bases[229]
    DIRECTION INPUT ;
    USE SIGNAL ;
    PORT
      LAYER M3 ;
        RECT 104.613 388.608 104.637 388.800 ;
    END
  END bases[229]
  PIN bases[230]
    DIRECTION INPUT ;
    USE SIGNAL ;
    PORT
      LAYER M5 ;
        RECT 105.024 388.608 105.048 388.800 ;
    END
  END bases[230]
  PIN bases[231]
    DIRECTION INPUT ;
    USE SIGNAL ;
    PORT
      LAYER M3 ;
        RECT 105.477 388.608 105.501 388.800 ;
    END
  END bases[231]
  PIN bases[232]
    DIRECTION INPUT ;
    USE SIGNAL ;
    PORT
      LAYER M5 ;
        RECT 105.936 388.608 105.960 388.800 ;
    END
  END bases[232]
  PIN bases[233]
    DIRECTION INPUT ;
    USE SIGNAL ;
    PORT
      LAYER M3 ;
        RECT 106.377 388.608 106.401 388.800 ;
    END
  END bases[233]
  PIN bases[234]
    DIRECTION INPUT ;
    USE SIGNAL ;
    PORT
      LAYER M5 ;
        RECT 106.848 388.608 106.872 388.800 ;
    END
  END bases[234]
  PIN bases[235]
    DIRECTION INPUT ;
    USE SIGNAL ;
    PORT
      LAYER M3 ;
        RECT 107.277 388.608 107.301 388.800 ;
    END
  END bases[235]
  PIN bases[236]
    DIRECTION INPUT ;
    USE SIGNAL ;
    PORT
      LAYER M5 ;
        RECT 107.712 388.608 107.736 388.800 ;
    END
  END bases[236]
  PIN bases[237]
    DIRECTION INPUT ;
    USE SIGNAL ;
    PORT
      LAYER M3 ;
        RECT 108.141 388.608 108.165 388.800 ;
    END
  END bases[237]
  PIN bases[238]
    DIRECTION INPUT ;
    USE SIGNAL ;
    PORT
      LAYER M5 ;
        RECT 108.624 388.608 108.648 388.800 ;
    END
  END bases[238]
  PIN bases[239]
    DIRECTION INPUT ;
    USE SIGNAL ;
    PORT
      LAYER M3 ;
        RECT 109.041 388.608 109.065 388.800 ;
    END
  END bases[239]
  PIN bases[240]
    DIRECTION INPUT ;
    USE SIGNAL ;
    PORT
      LAYER M5 ;
        RECT 109.488 388.608 109.512 388.800 ;
    END
  END bases[240]
  PIN bases[241]
    DIRECTION INPUT ;
    USE SIGNAL ;
    PORT
      LAYER M3 ;
        RECT 109.941 388.608 109.965 388.800 ;
    END
  END bases[241]
  PIN bases[242]
    DIRECTION INPUT ;
    USE SIGNAL ;
    PORT
      LAYER M5 ;
        RECT 110.400 388.608 110.424 388.800 ;
    END
  END bases[242]
  PIN bases[243]
    DIRECTION INPUT ;
    USE SIGNAL ;
    PORT
      LAYER M3 ;
        RECT 110.841 388.608 110.865 388.800 ;
    END
  END bases[243]
  PIN bases[244]
    DIRECTION INPUT ;
    USE SIGNAL ;
    PORT
      LAYER M5 ;
        RECT 111.264 388.608 111.288 388.800 ;
    END
  END bases[244]
  PIN bases[245]
    DIRECTION INPUT ;
    USE SIGNAL ;
    PORT
      LAYER M3 ;
        RECT 111.705 388.608 111.729 388.800 ;
    END
  END bases[245]
  PIN bases[246]
    DIRECTION INPUT ;
    USE SIGNAL ;
    PORT
      LAYER M5 ;
        RECT 112.176 388.608 112.200 388.800 ;
    END
  END bases[246]
  PIN bases[247]
    DIRECTION INPUT ;
    USE SIGNAL ;
    PORT
      LAYER M3 ;
        RECT 112.605 388.608 112.629 388.800 ;
    END
  END bases[247]
  PIN bases[248]
    DIRECTION INPUT ;
    USE SIGNAL ;
    PORT
      LAYER M5 ;
        RECT 113.040 388.608 113.064 388.800 ;
    END
  END bases[248]
  PIN bases[249]
    DIRECTION INPUT ;
    USE SIGNAL ;
    PORT
      LAYER M3 ;
        RECT 113.505 388.608 113.529 388.800 ;
    END
  END bases[249]
  PIN bases[250]
    DIRECTION INPUT ;
    USE SIGNAL ;
    PORT
      LAYER M5 ;
        RECT 113.952 388.608 113.976 388.800 ;
    END
  END bases[250]
  PIN bases[251]
    DIRECTION INPUT ;
    USE SIGNAL ;
    PORT
      LAYER M3 ;
        RECT 114.369 388.608 114.393 388.800 ;
    END
  END bases[251]
  PIN bases[252]
    DIRECTION INPUT ;
    USE SIGNAL ;
    PORT
      LAYER M5 ;
        RECT 114.816 388.608 114.840 388.800 ;
    END
  END bases[252]
  PIN bases[253]
    DIRECTION INPUT ;
    USE SIGNAL ;
    PORT
      LAYER M3 ;
        RECT 115.269 388.608 115.293 388.800 ;
    END
  END bases[253]
  PIN bases[254]
    DIRECTION INPUT ;
    USE SIGNAL ;
    PORT
      LAYER M5 ;
        RECT 115.728 388.608 115.752 388.800 ;
    END
  END bases[254]
  PIN bases[255]
    DIRECTION INPUT ;
    USE SIGNAL ;
    PORT
      LAYER M3 ;
        RECT 116.169 388.608 116.193 388.800 ;
    END
  END bases[255]
  PIN bases[256]
    DIRECTION INPUT ;
    USE SIGNAL ;
    PORT
      LAYER M5 ;
        RECT 116.592 388.608 116.616 388.800 ;
    END
  END bases[256]
  PIN bases[257]
    DIRECTION INPUT ;
    USE SIGNAL ;
    PORT
      LAYER M3 ;
        RECT 117.033 388.608 117.057 388.800 ;
    END
  END bases[257]
  PIN bases[258]
    DIRECTION INPUT ;
    USE SIGNAL ;
    PORT
      LAYER M5 ;
        RECT 117.504 388.608 117.528 388.800 ;
    END
  END bases[258]
  PIN bases[259]
    DIRECTION INPUT ;
    USE SIGNAL ;
    PORT
      LAYER M3 ;
        RECT 117.933 388.608 117.957 388.800 ;
    END
  END bases[259]
  PIN bases[260]
    DIRECTION INPUT ;
    USE SIGNAL ;
    PORT
      LAYER M5 ;
        RECT 118.368 388.608 118.392 388.800 ;
    END
  END bases[260]
  PIN bases[261]
    DIRECTION INPUT ;
    USE SIGNAL ;
    PORT
      LAYER M3 ;
        RECT 118.833 388.608 118.857 388.800 ;
    END
  END bases[261]
  PIN bases[262]
    DIRECTION INPUT ;
    USE SIGNAL ;
    PORT
      LAYER M5 ;
        RECT 119.280 388.608 119.304 388.800 ;
    END
  END bases[262]
  PIN bases[263]
    DIRECTION INPUT ;
    USE SIGNAL ;
    PORT
      LAYER M3 ;
        RECT 119.697 388.608 119.721 388.800 ;
    END
  END bases[263]
  PIN bases[264]
    DIRECTION INPUT ;
    USE SIGNAL ;
    PORT
      LAYER M5 ;
        RECT 120.144 388.608 120.168 388.800 ;
    END
  END bases[264]
  PIN bases[265]
    DIRECTION INPUT ;
    USE SIGNAL ;
    PORT
      LAYER M3 ;
        RECT 120.597 388.608 120.621 388.800 ;
    END
  END bases[265]
  PIN bases[266]
    DIRECTION INPUT ;
    USE SIGNAL ;
    PORT
      LAYER M5 ;
        RECT 121.056 388.608 121.080 388.800 ;
    END
  END bases[266]
  PIN bases[267]
    DIRECTION INPUT ;
    USE SIGNAL ;
    PORT
      LAYER M3 ;
        RECT 121.497 388.608 121.521 388.800 ;
    END
  END bases[267]
  PIN bases[268]
    DIRECTION INPUT ;
    USE SIGNAL ;
    PORT
      LAYER M5 ;
        RECT 121.920 388.608 121.944 388.800 ;
    END
  END bases[268]
  PIN bases[269]
    DIRECTION INPUT ;
    USE SIGNAL ;
    PORT
      LAYER M3 ;
        RECT 122.397 388.608 122.421 388.800 ;
    END
  END bases[269]
  PIN bases[270]
    DIRECTION INPUT ;
    USE SIGNAL ;
    PORT
      LAYER M5 ;
        RECT 122.832 388.608 122.856 388.800 ;
    END
  END bases[270]
  PIN bases[271]
    DIRECTION INPUT ;
    USE SIGNAL ;
    PORT
      LAYER M3 ;
        RECT 123.261 388.608 123.285 388.800 ;
    END
  END bases[271]
  PIN bases[272]
    DIRECTION INPUT ;
    USE SIGNAL ;
    PORT
      LAYER M5 ;
        RECT 123.696 388.608 123.720 388.800 ;
    END
  END bases[272]
  PIN bases[273]
    DIRECTION INPUT ;
    USE SIGNAL ;
    PORT
      LAYER M3 ;
        RECT 124.161 388.608 124.185 388.800 ;
    END
  END bases[273]
  PIN bases[274]
    DIRECTION INPUT ;
    USE SIGNAL ;
    PORT
      LAYER M5 ;
        RECT 124.608 388.608 124.632 388.800 ;
    END
  END bases[274]
  PIN bases[275]
    DIRECTION INPUT ;
    USE SIGNAL ;
    PORT
      LAYER M3 ;
        RECT 125.061 388.608 125.085 388.800 ;
    END
  END bases[275]
  PIN bases[276]
    DIRECTION INPUT ;
    USE SIGNAL ;
    PORT
      LAYER M5 ;
        RECT 125.472 388.608 125.496 388.800 ;
    END
  END bases[276]
  PIN bases[277]
    DIRECTION INPUT ;
    USE SIGNAL ;
    PORT
      LAYER M3 ;
        RECT 125.925 388.608 125.949 388.800 ;
    END
  END bases[277]
  PIN bases[278]
    DIRECTION INPUT ;
    USE SIGNAL ;
    PORT
      LAYER M5 ;
        RECT 126.384 388.608 126.408 388.800 ;
    END
  END bases[278]
  PIN bases[279]
    DIRECTION INPUT ;
    USE SIGNAL ;
    PORT
      LAYER M3 ;
        RECT 126.825 388.608 126.849 388.800 ;
    END
  END bases[279]
  PIN bases[280]
    DIRECTION INPUT ;
    USE SIGNAL ;
    PORT
      LAYER M5 ;
        RECT 127.248 388.608 127.272 388.800 ;
    END
  END bases[280]
  PIN bases[281]
    DIRECTION INPUT ;
    USE SIGNAL ;
    PORT
      LAYER M3 ;
        RECT 127.725 388.608 127.749 388.800 ;
    END
  END bases[281]
  PIN bases[282]
    DIRECTION INPUT ;
    USE SIGNAL ;
    PORT
      LAYER M5 ;
        RECT 128.160 388.608 128.184 388.800 ;
    END
  END bases[282]
  PIN bases[283]
    DIRECTION INPUT ;
    USE SIGNAL ;
    PORT
      LAYER M3 ;
        RECT 128.589 388.608 128.613 388.800 ;
    END
  END bases[283]
  PIN bases[284]
    DIRECTION INPUT ;
    USE SIGNAL ;
    PORT
      LAYER M5 ;
        RECT 129.072 388.608 129.096 388.800 ;
    END
  END bases[284]
  PIN bases[285]
    DIRECTION INPUT ;
    USE SIGNAL ;
    PORT
      LAYER M3 ;
        RECT 129.489 388.608 129.513 388.800 ;
    END
  END bases[285]
  PIN bases[286]
    DIRECTION INPUT ;
    USE SIGNAL ;
    PORT
      LAYER M5 ;
        RECT 129.936 388.608 129.960 388.800 ;
    END
  END bases[286]
  PIN bases[287]
    DIRECTION INPUT ;
    USE SIGNAL ;
    PORT
      LAYER M3 ;
        RECT 130.389 388.608 130.413 388.800 ;
    END
  END bases[287]
  PIN bases[288]
    DIRECTION INPUT ;
    USE SIGNAL ;
    PORT
      LAYER M5 ;
        RECT 130.848 388.608 130.872 388.800 ;
    END
  END bases[288]
  PIN bases[289]
    DIRECTION INPUT ;
    USE SIGNAL ;
    PORT
      LAYER M3 ;
        RECT 131.289 388.608 131.313 388.800 ;
    END
  END bases[289]
  PIN bases[290]
    DIRECTION INPUT ;
    USE SIGNAL ;
    PORT
      LAYER M5 ;
        RECT 131.712 388.608 131.736 388.800 ;
    END
  END bases[290]
  PIN bases[291]
    DIRECTION INPUT ;
    USE SIGNAL ;
    PORT
      LAYER M3 ;
        RECT 132.153 388.608 132.177 388.800 ;
    END
  END bases[291]
  PIN bases[292]
    DIRECTION INPUT ;
    USE SIGNAL ;
    PORT
      LAYER M5 ;
        RECT 132.624 388.608 132.648 388.800 ;
    END
  END bases[292]
  PIN bases[293]
    DIRECTION INPUT ;
    USE SIGNAL ;
    PORT
      LAYER M3 ;
        RECT 133.053 388.608 133.077 388.800 ;
    END
  END bases[293]
  PIN bases[294]
    DIRECTION INPUT ;
    USE SIGNAL ;
    PORT
      LAYER M5 ;
        RECT 133.488 388.608 133.512 388.800 ;
    END
  END bases[294]
  PIN bases[295]
    DIRECTION INPUT ;
    USE SIGNAL ;
    PORT
      LAYER M3 ;
        RECT 133.953 388.608 133.977 388.800 ;
    END
  END bases[295]
  PIN bases[296]
    DIRECTION INPUT ;
    USE SIGNAL ;
    PORT
      LAYER M5 ;
        RECT 134.400 388.608 134.424 388.800 ;
    END
  END bases[296]
  PIN bases[297]
    DIRECTION INPUT ;
    USE SIGNAL ;
    PORT
      LAYER M3 ;
        RECT 134.817 388.608 134.841 388.800 ;
    END
  END bases[297]
  PIN bases[298]
    DIRECTION INPUT ;
    USE SIGNAL ;
    PORT
      LAYER M5 ;
        RECT 135.264 388.608 135.288 388.800 ;
    END
  END bases[298]
  PIN bases[299]
    DIRECTION INPUT ;
    USE SIGNAL ;
    PORT
      LAYER M3 ;
        RECT 135.717 388.608 135.741 388.800 ;
    END
  END bases[299]
  PIN bases[300]
    DIRECTION INPUT ;
    USE SIGNAL ;
    PORT
      LAYER M5 ;
        RECT 136.176 388.608 136.200 388.800 ;
    END
  END bases[300]
  PIN bases[301]
    DIRECTION INPUT ;
    USE SIGNAL ;
    PORT
      LAYER M3 ;
        RECT 136.617 388.608 136.641 388.800 ;
    END
  END bases[301]
  PIN bases[302]
    DIRECTION INPUT ;
    USE SIGNAL ;
    PORT
      LAYER M5 ;
        RECT 137.040 388.608 137.064 388.800 ;
    END
  END bases[302]
  PIN bases[303]
    DIRECTION INPUT ;
    USE SIGNAL ;
    PORT
      LAYER M3 ;
        RECT 137.481 388.608 137.505 388.800 ;
    END
  END bases[303]
  PIN bases[304]
    DIRECTION INPUT ;
    USE SIGNAL ;
    PORT
      LAYER M5 ;
        RECT 137.952 388.608 137.976 388.800 ;
    END
  END bases[304]
  PIN bases[305]
    DIRECTION INPUT ;
    USE SIGNAL ;
    PORT
      LAYER M3 ;
        RECT 138.381 388.608 138.405 388.800 ;
    END
  END bases[305]
  PIN bases[306]
    DIRECTION INPUT ;
    USE SIGNAL ;
    PORT
      LAYER M5 ;
        RECT 138.816 388.608 138.840 388.800 ;
    END
  END bases[306]
  PIN bases[307]
    DIRECTION INPUT ;
    USE SIGNAL ;
    PORT
      LAYER M3 ;
        RECT 139.281 388.608 139.305 388.800 ;
    END
  END bases[307]
  PIN bases[308]
    DIRECTION INPUT ;
    USE SIGNAL ;
    PORT
      LAYER M5 ;
        RECT 139.728 388.608 139.752 388.800 ;
    END
  END bases[308]
  PIN bases[309]
    DIRECTION INPUT ;
    USE SIGNAL ;
    PORT
      LAYER M3 ;
        RECT 140.145 388.608 140.169 388.800 ;
    END
  END bases[309]
  PIN bases[310]
    DIRECTION INPUT ;
    USE SIGNAL ;
    PORT
      LAYER M5 ;
        RECT 140.592 388.608 140.616 388.800 ;
    END
  END bases[310]
  PIN bases[311]
    DIRECTION INPUT ;
    USE SIGNAL ;
    PORT
      LAYER M3 ;
        RECT 141.045 388.608 141.069 388.800 ;
    END
  END bases[311]
  PIN bases[312]
    DIRECTION INPUT ;
    USE SIGNAL ;
    PORT
      LAYER M5 ;
        RECT 141.504 388.608 141.528 388.800 ;
    END
  END bases[312]
  PIN bases[313]
    DIRECTION INPUT ;
    USE SIGNAL ;
    PORT
      LAYER M3 ;
        RECT 141.945 388.608 141.969 388.800 ;
    END
  END bases[313]
  PIN bases[314]
    DIRECTION INPUT ;
    USE SIGNAL ;
    PORT
      LAYER M5 ;
        RECT 142.368 388.608 142.392 388.800 ;
    END
  END bases[314]
  PIN bases[315]
    DIRECTION INPUT ;
    USE SIGNAL ;
    PORT
      LAYER M3 ;
        RECT 142.845 388.608 142.869 388.800 ;
    END
  END bases[315]
  PIN bases[316]
    DIRECTION INPUT ;
    USE SIGNAL ;
    PORT
      LAYER M5 ;
        RECT 143.280 388.608 143.304 388.800 ;
    END
  END bases[316]
  PIN bases[317]
    DIRECTION INPUT ;
    USE SIGNAL ;
    PORT
      LAYER M3 ;
        RECT 143.709 388.608 143.733 388.800 ;
    END
  END bases[317]
  PIN bases[318]
    DIRECTION INPUT ;
    USE SIGNAL ;
    PORT
      LAYER M5 ;
        RECT 144.144 388.608 144.168 388.800 ;
    END
  END bases[318]
  PIN bases[319]
    DIRECTION INPUT ;
    USE SIGNAL ;
    PORT
      LAYER M3 ;
        RECT 144.609 388.608 144.633 388.800 ;
    END
  END bases[319]
  PIN bases[320]
    DIRECTION INPUT ;
    USE SIGNAL ;
    PORT
      LAYER M5 ;
        RECT 145.056 388.608 145.080 388.800 ;
    END
  END bases[320]
  PIN bases[321]
    DIRECTION INPUT ;
    USE SIGNAL ;
    PORT
      LAYER M3 ;
        RECT 145.509 388.608 145.533 388.800 ;
    END
  END bases[321]
  PIN bases[322]
    DIRECTION INPUT ;
    USE SIGNAL ;
    PORT
      LAYER M5 ;
        RECT 145.920 388.608 145.944 388.800 ;
    END
  END bases[322]
  PIN bases[323]
    DIRECTION INPUT ;
    USE SIGNAL ;
    PORT
      LAYER M3 ;
        RECT 146.373 388.608 146.397 388.800 ;
    END
  END bases[323]
  PIN bases[324]
    DIRECTION INPUT ;
    USE SIGNAL ;
    PORT
      LAYER M5 ;
        RECT 146.832 388.608 146.856 388.800 ;
    END
  END bases[324]
  PIN bases[325]
    DIRECTION INPUT ;
    USE SIGNAL ;
    PORT
      LAYER M3 ;
        RECT 147.273 388.608 147.297 388.800 ;
    END
  END bases[325]
  PIN bases[326]
    DIRECTION INPUT ;
    USE SIGNAL ;
    PORT
      LAYER M5 ;
        RECT 147.696 388.608 147.720 388.800 ;
    END
  END bases[326]
  PIN bases[327]
    DIRECTION INPUT ;
    USE SIGNAL ;
    PORT
      LAYER M3 ;
        RECT 148.173 388.608 148.197 388.800 ;
    END
  END bases[327]
  PIN bases[328]
    DIRECTION INPUT ;
    USE SIGNAL ;
    PORT
      LAYER M5 ;
        RECT 148.608 388.608 148.632 388.800 ;
    END
  END bases[328]
  PIN bases[329]
    DIRECTION INPUT ;
    USE SIGNAL ;
    PORT
      LAYER M3 ;
        RECT 149.037 388.608 149.061 388.800 ;
    END
  END bases[329]
  PIN bases[330]
    DIRECTION INPUT ;
    USE SIGNAL ;
    PORT
      LAYER M5 ;
        RECT 149.472 388.608 149.496 388.800 ;
    END
  END bases[330]
  PIN bases[331]
    DIRECTION INPUT ;
    USE SIGNAL ;
    PORT
      LAYER M3 ;
        RECT 149.937 388.608 149.961 388.800 ;
    END
  END bases[331]
  PIN bases[332]
    DIRECTION INPUT ;
    USE SIGNAL ;
    PORT
      LAYER M5 ;
        RECT 150.384 388.608 150.408 388.800 ;
    END
  END bases[332]
  PIN bases[333]
    DIRECTION INPUT ;
    USE SIGNAL ;
    PORT
      LAYER M3 ;
        RECT 150.837 388.608 150.861 388.800 ;
    END
  END bases[333]
  PIN bases[334]
    DIRECTION INPUT ;
    USE SIGNAL ;
    PORT
      LAYER M5 ;
        RECT 151.296 388.608 151.320 388.800 ;
    END
  END bases[334]
  PIN bases[335]
    DIRECTION INPUT ;
    USE SIGNAL ;
    PORT
      LAYER M3 ;
        RECT 151.701 388.608 151.725 388.800 ;
    END
  END bases[335]
  PIN bases[336]
    DIRECTION INPUT ;
    USE SIGNAL ;
    PORT
      LAYER M5 ;
        RECT 152.160 388.608 152.184 388.800 ;
    END
  END bases[336]
  PIN bases[337]
    DIRECTION INPUT ;
    USE SIGNAL ;
    PORT
      LAYER M3 ;
        RECT 152.601 388.608 152.625 388.800 ;
    END
  END bases[337]
  PIN bases[338]
    DIRECTION INPUT ;
    USE SIGNAL ;
    PORT
      LAYER M5 ;
        RECT 153.072 388.608 153.096 388.800 ;
    END
  END bases[338]
  PIN bases[339]
    DIRECTION INPUT ;
    USE SIGNAL ;
    PORT
      LAYER M3 ;
        RECT 153.501 388.608 153.525 388.800 ;
    END
  END bases[339]
  PIN bases[340]
    DIRECTION INPUT ;
    USE SIGNAL ;
    PORT
      LAYER M5 ;
        RECT 153.936 388.608 153.960 388.800 ;
    END
  END bases[340]
  PIN bases[341]
    DIRECTION INPUT ;
    USE SIGNAL ;
    PORT
      LAYER M3 ;
        RECT 154.401 388.608 154.425 388.800 ;
    END
  END bases[341]
  PIN bases[342]
    DIRECTION INPUT ;
    USE SIGNAL ;
    PORT
      LAYER M5 ;
        RECT 154.848 388.608 154.872 388.800 ;
    END
  END bases[342]
  PIN bases[343]
    DIRECTION INPUT ;
    USE SIGNAL ;
    PORT
      LAYER M3 ;
        RECT 155.265 388.608 155.289 388.800 ;
    END
  END bases[343]
  PIN bases[344]
    DIRECTION INPUT ;
    USE SIGNAL ;
    PORT
      LAYER M5 ;
        RECT 155.712 388.608 155.736 388.800 ;
    END
  END bases[344]
  PIN bases[345]
    DIRECTION INPUT ;
    USE SIGNAL ;
    PORT
      LAYER M3 ;
        RECT 156.165 388.608 156.189 388.800 ;
    END
  END bases[345]
  PIN bases[346]
    DIRECTION INPUT ;
    USE SIGNAL ;
    PORT
      LAYER M5 ;
        RECT 156.624 388.608 156.648 388.800 ;
    END
  END bases[346]
  PIN bases[347]
    DIRECTION INPUT ;
    USE SIGNAL ;
    PORT
      LAYER M3 ;
        RECT 157.065 388.608 157.089 388.800 ;
    END
  END bases[347]
  PIN bases[348]
    DIRECTION INPUT ;
    USE SIGNAL ;
    PORT
      LAYER M5 ;
        RECT 157.488 388.608 157.512 388.800 ;
    END
  END bases[348]
  PIN bases[349]
    DIRECTION INPUT ;
    USE SIGNAL ;
    PORT
      LAYER M3 ;
        RECT 157.929 388.608 157.953 388.800 ;
    END
  END bases[349]
  PIN bases[350]
    DIRECTION INPUT ;
    USE SIGNAL ;
    PORT
      LAYER M5 ;
        RECT 158.400 388.608 158.424 388.800 ;
    END
  END bases[350]
  PIN bases[351]
    DIRECTION INPUT ;
    USE SIGNAL ;
    PORT
      LAYER M3 ;
        RECT 158.829 388.608 158.853 388.800 ;
    END
  END bases[351]
  PIN bases[352]
    DIRECTION INPUT ;
    USE SIGNAL ;
    PORT
      LAYER M5 ;
        RECT 159.264 388.608 159.288 388.800 ;
    END
  END bases[352]
  PIN bases[353]
    DIRECTION INPUT ;
    USE SIGNAL ;
    PORT
      LAYER M3 ;
        RECT 159.729 388.608 159.753 388.800 ;
    END
  END bases[353]
  PIN bases[354]
    DIRECTION INPUT ;
    USE SIGNAL ;
    PORT
      LAYER M5 ;
        RECT 160.176 388.608 160.200 388.800 ;
    END
  END bases[354]
  PIN bases[355]
    DIRECTION INPUT ;
    USE SIGNAL ;
    PORT
      LAYER M3 ;
        RECT 160.593 388.608 160.617 388.800 ;
    END
  END bases[355]
  PIN bases[356]
    DIRECTION INPUT ;
    USE SIGNAL ;
    PORT
      LAYER M5 ;
        RECT 161.040 388.608 161.064 388.800 ;
    END
  END bases[356]
  PIN bases[357]
    DIRECTION INPUT ;
    USE SIGNAL ;
    PORT
      LAYER M3 ;
        RECT 161.493 388.608 161.517 388.800 ;
    END
  END bases[357]
  PIN bases[358]
    DIRECTION INPUT ;
    USE SIGNAL ;
    PORT
      LAYER M5 ;
        RECT 161.952 388.608 161.976 388.800 ;
    END
  END bases[358]
  PIN bases[359]
    DIRECTION INPUT ;
    USE SIGNAL ;
    PORT
      LAYER M3 ;
        RECT 162.393 388.608 162.417 388.800 ;
    END
  END bases[359]
  PIN bases[360]
    DIRECTION INPUT ;
    USE SIGNAL ;
    PORT
      LAYER M5 ;
        RECT 162.816 388.608 162.840 388.800 ;
    END
  END bases[360]
  PIN bases[361]
    DIRECTION INPUT ;
    USE SIGNAL ;
    PORT
      LAYER M3 ;
        RECT 163.257 388.608 163.281 388.800 ;
    END
  END bases[361]
  PIN bases[362]
    DIRECTION INPUT ;
    USE SIGNAL ;
    PORT
      LAYER M5 ;
        RECT 163.728 388.608 163.752 388.800 ;
    END
  END bases[362]
  PIN bases[363]
    DIRECTION INPUT ;
    USE SIGNAL ;
    PORT
      LAYER M3 ;
        RECT 164.157 388.608 164.181 388.800 ;
    END
  END bases[363]
  PIN bases[364]
    DIRECTION INPUT ;
    USE SIGNAL ;
    PORT
      LAYER M5 ;
        RECT 164.592 388.608 164.616 388.800 ;
    END
  END bases[364]
  PIN bases[365]
    DIRECTION INPUT ;
    USE SIGNAL ;
    PORT
      LAYER M3 ;
        RECT 165.057 388.608 165.081 388.800 ;
    END
  END bases[365]
  PIN bases[366]
    DIRECTION INPUT ;
    USE SIGNAL ;
    PORT
      LAYER M5 ;
        RECT 165.504 388.608 165.528 388.800 ;
    END
  END bases[366]
  PIN bases[367]
    DIRECTION INPUT ;
    USE SIGNAL ;
    PORT
      LAYER M3 ;
        RECT 165.957 388.608 165.981 388.800 ;
    END
  END bases[367]
  PIN bases[368]
    DIRECTION INPUT ;
    USE SIGNAL ;
    PORT
      LAYER M5 ;
        RECT 166.368 388.608 166.392 388.800 ;
    END
  END bases[368]
  PIN bases[369]
    DIRECTION INPUT ;
    USE SIGNAL ;
    PORT
      LAYER M3 ;
        RECT 166.821 388.608 166.845 388.800 ;
    END
  END bases[369]
  PIN bases[370]
    DIRECTION INPUT ;
    USE SIGNAL ;
    PORT
      LAYER M5 ;
        RECT 167.280 388.608 167.304 388.800 ;
    END
  END bases[370]
  PIN bases[371]
    DIRECTION INPUT ;
    USE SIGNAL ;
    PORT
      LAYER M3 ;
        RECT 167.721 388.608 167.745 388.800 ;
    END
  END bases[371]
  PIN bases[372]
    DIRECTION INPUT ;
    USE SIGNAL ;
    PORT
      LAYER M5 ;
        RECT 168.144 388.608 168.168 388.800 ;
    END
  END bases[372]
  PIN bases[373]
    DIRECTION INPUT ;
    USE SIGNAL ;
    PORT
      LAYER M3 ;
        RECT 168.621 388.608 168.645 388.800 ;
    END
  END bases[373]
  PIN bases[374]
    DIRECTION INPUT ;
    USE SIGNAL ;
    PORT
      LAYER M5 ;
        RECT 169.056 388.608 169.080 388.800 ;
    END
  END bases[374]
  PIN bases[375]
    DIRECTION INPUT ;
    USE SIGNAL ;
    PORT
      LAYER M3 ;
        RECT 169.485 388.608 169.509 388.800 ;
    END
  END bases[375]
  PIN bases[376]
    DIRECTION INPUT ;
    USE SIGNAL ;
    PORT
      LAYER M5 ;
        RECT 169.920 388.608 169.944 388.800 ;
    END
  END bases[376]
  PIN bases[377]
    DIRECTION INPUT ;
    USE SIGNAL ;
    PORT
      LAYER M3 ;
        RECT 170.385 388.608 170.409 388.800 ;
    END
  END bases[377]
  PIN bases[378]
    DIRECTION INPUT ;
    USE SIGNAL ;
    PORT
      LAYER M5 ;
        RECT 170.832 388.608 170.856 388.800 ;
    END
  END bases[378]
  PIN bases[379]
    DIRECTION INPUT ;
    USE SIGNAL ;
    PORT
      LAYER M3 ;
        RECT 171.285 388.608 171.309 388.800 ;
    END
  END bases[379]
  PIN bases[380]
    DIRECTION INPUT ;
    USE SIGNAL ;
    PORT
      LAYER M5 ;
        RECT 171.696 388.608 171.720 388.800 ;
    END
  END bases[380]
  PIN bases[381]
    DIRECTION INPUT ;
    USE SIGNAL ;
    PORT
      LAYER M3 ;
        RECT 172.149 388.608 172.173 388.800 ;
    END
  END bases[381]
  PIN bases[382]
    DIRECTION INPUT ;
    USE SIGNAL ;
    PORT
      LAYER M5 ;
        RECT 172.608 388.608 172.632 388.800 ;
    END
  END bases[382]
  PIN bases[383]
    DIRECTION INPUT ;
    USE SIGNAL ;
    PORT
      LAYER M3 ;
        RECT 173.049 388.608 173.073 388.800 ;
    END
  END bases[383]
  PIN bases[384]
    DIRECTION INPUT ;
    USE SIGNAL ;
    PORT
      LAYER M5 ;
        RECT 173.520 388.608 173.544 388.800 ;
    END
  END bases[384]
  PIN bases[385]
    DIRECTION INPUT ;
    USE SIGNAL ;
    PORT
      LAYER M3 ;
        RECT 173.949 388.608 173.973 388.800 ;
    END
  END bases[385]
  PIN bases[386]
    DIRECTION INPUT ;
    USE SIGNAL ;
    PORT
      LAYER M5 ;
        RECT 174.384 388.608 174.408 388.800 ;
    END
  END bases[386]
  PIN bases[387]
    DIRECTION INPUT ;
    USE SIGNAL ;
    PORT
      LAYER M3 ;
        RECT 174.813 388.608 174.837 388.800 ;
    END
  END bases[387]
  PIN bases[388]
    DIRECTION INPUT ;
    USE SIGNAL ;
    PORT
      LAYER M5 ;
        RECT 175.296 388.608 175.320 388.800 ;
    END
  END bases[388]
  PIN bases[389]
    DIRECTION INPUT ;
    USE SIGNAL ;
    PORT
      LAYER M3 ;
        RECT 175.713 388.608 175.737 388.800 ;
    END
  END bases[389]
  PIN bases[390]
    DIRECTION INPUT ;
    USE SIGNAL ;
    PORT
      LAYER M5 ;
        RECT 176.160 388.608 176.184 388.800 ;
    END
  END bases[390]
  PIN bases[391]
    DIRECTION INPUT ;
    USE SIGNAL ;
    PORT
      LAYER M3 ;
        RECT 176.613 388.608 176.637 388.800 ;
    END
  END bases[391]
  PIN bases[392]
    DIRECTION INPUT ;
    USE SIGNAL ;
    PORT
      LAYER M5 ;
        RECT 177.072 388.608 177.096 388.800 ;
    END
  END bases[392]
  PIN bases[393]
    DIRECTION INPUT ;
    USE SIGNAL ;
    PORT
      LAYER M3 ;
        RECT 177.513 388.608 177.537 388.800 ;
    END
  END bases[393]
  PIN bases[394]
    DIRECTION INPUT ;
    USE SIGNAL ;
    PORT
      LAYER M5 ;
        RECT 177.936 388.608 177.960 388.800 ;
    END
  END bases[394]
  PIN bases[395]
    DIRECTION INPUT ;
    USE SIGNAL ;
    PORT
      LAYER M3 ;
        RECT 178.377 388.608 178.401 388.800 ;
    END
  END bases[395]
  PIN bases[396]
    DIRECTION INPUT ;
    USE SIGNAL ;
    PORT
      LAYER M5 ;
        RECT 178.848 388.608 178.872 388.800 ;
    END
  END bases[396]
  PIN bases[397]
    DIRECTION INPUT ;
    USE SIGNAL ;
    PORT
      LAYER M3 ;
        RECT 179.277 388.608 179.301 388.800 ;
    END
  END bases[397]
  PIN bases[398]
    DIRECTION INPUT ;
    USE SIGNAL ;
    PORT
      LAYER M5 ;
        RECT 179.712 388.608 179.736 388.800 ;
    END
  END bases[398]
  PIN bases[399]
    DIRECTION INPUT ;
    USE SIGNAL ;
    PORT
      LAYER M3 ;
        RECT 180.177 388.608 180.201 388.800 ;
    END
  END bases[399]
  PIN bases[400]
    DIRECTION INPUT ;
    USE SIGNAL ;
    PORT
      LAYER M5 ;
        RECT 180.624 388.608 180.648 388.800 ;
    END
  END bases[400]
  PIN bases[401]
    DIRECTION INPUT ;
    USE SIGNAL ;
    PORT
      LAYER M3 ;
        RECT 181.041 388.608 181.065 388.800 ;
    END
  END bases[401]
  PIN bases[402]
    DIRECTION INPUT ;
    USE SIGNAL ;
    PORT
      LAYER M5 ;
        RECT 181.488 388.608 181.512 388.800 ;
    END
  END bases[402]
  PIN bases[403]
    DIRECTION INPUT ;
    USE SIGNAL ;
    PORT
      LAYER M3 ;
        RECT 181.941 388.608 181.965 388.800 ;
    END
  END bases[403]
  PIN bases[404]
    DIRECTION INPUT ;
    USE SIGNAL ;
    PORT
      LAYER M5 ;
        RECT 182.400 388.608 182.424 388.800 ;
    END
  END bases[404]
  PIN bases[405]
    DIRECTION INPUT ;
    USE SIGNAL ;
    PORT
      LAYER M3 ;
        RECT 182.841 388.608 182.865 388.800 ;
    END
  END bases[405]
  PIN bases[406]
    DIRECTION INPUT ;
    USE SIGNAL ;
    PORT
      LAYER M5 ;
        RECT 183.264 388.608 183.288 388.800 ;
    END
  END bases[406]
  PIN bases[407]
    DIRECTION INPUT ;
    USE SIGNAL ;
    PORT
      LAYER M3 ;
        RECT 183.705 388.608 183.729 388.800 ;
    END
  END bases[407]
  PIN bases[408]
    DIRECTION INPUT ;
    USE SIGNAL ;
    PORT
      LAYER M5 ;
        RECT 184.176 388.608 184.200 388.800 ;
    END
  END bases[408]
  PIN bases[409]
    DIRECTION INPUT ;
    USE SIGNAL ;
    PORT
      LAYER M3 ;
        RECT 184.605 388.608 184.629 388.800 ;
    END
  END bases[409]
  PIN bases[410]
    DIRECTION INPUT ;
    USE SIGNAL ;
    PORT
      LAYER M5 ;
        RECT 185.040 388.608 185.064 388.800 ;
    END
  END bases[410]
  PIN bases[411]
    DIRECTION INPUT ;
    USE SIGNAL ;
    PORT
      LAYER M3 ;
        RECT 185.505 388.608 185.529 388.800 ;
    END
  END bases[411]
  PIN bases[412]
    DIRECTION INPUT ;
    USE SIGNAL ;
    PORT
      LAYER M5 ;
        RECT 185.952 388.608 185.976 388.800 ;
    END
  END bases[412]
  PIN bases[413]
    DIRECTION INPUT ;
    USE SIGNAL ;
    PORT
      LAYER M3 ;
        RECT 186.405 388.608 186.429 388.800 ;
    END
  END bases[413]
  PIN bases[414]
    DIRECTION INPUT ;
    USE SIGNAL ;
    PORT
      LAYER M5 ;
        RECT 186.816 388.608 186.840 388.800 ;
    END
  END bases[414]
  PIN bases[415]
    DIRECTION INPUT ;
    USE SIGNAL ;
    PORT
      LAYER M3 ;
        RECT 187.269 388.608 187.293 388.800 ;
    END
  END bases[415]
  PIN bases[416]
    DIRECTION INPUT ;
    USE SIGNAL ;
    PORT
      LAYER M5 ;
        RECT 187.728 388.608 187.752 388.800 ;
    END
  END bases[416]
  PIN bases[417]
    DIRECTION INPUT ;
    USE SIGNAL ;
    PORT
      LAYER M3 ;
        RECT 188.169 388.608 188.193 388.800 ;
    END
  END bases[417]
  PIN bases[418]
    DIRECTION INPUT ;
    USE SIGNAL ;
    PORT
      LAYER M5 ;
        RECT 188.592 388.608 188.616 388.800 ;
    END
  END bases[418]
  PIN bases[419]
    DIRECTION INPUT ;
    USE SIGNAL ;
    PORT
      LAYER M3 ;
        RECT 189.069 388.608 189.093 388.800 ;
    END
  END bases[419]
  PIN bases[420]
    DIRECTION INPUT ;
    USE SIGNAL ;
    PORT
      LAYER M5 ;
        RECT 189.504 388.608 189.528 388.800 ;
    END
  END bases[420]
  PIN bases[421]
    DIRECTION INPUT ;
    USE SIGNAL ;
    PORT
      LAYER M3 ;
        RECT 189.933 388.608 189.957 388.800 ;
    END
  END bases[421]
  PIN bases[422]
    DIRECTION INPUT ;
    USE SIGNAL ;
    PORT
      LAYER M5 ;
        RECT 190.368 388.608 190.392 388.800 ;
    END
  END bases[422]
  PIN bases[423]
    DIRECTION INPUT ;
    USE SIGNAL ;
    PORT
      LAYER M3 ;
        RECT 190.833 388.608 190.857 388.800 ;
    END
  END bases[423]
  PIN bases[424]
    DIRECTION INPUT ;
    USE SIGNAL ;
    PORT
      LAYER M5 ;
        RECT 191.280 388.608 191.304 388.800 ;
    END
  END bases[424]
  PIN bases[425]
    DIRECTION INPUT ;
    USE SIGNAL ;
    PORT
      LAYER M3 ;
        RECT 191.733 388.608 191.757 388.800 ;
    END
  END bases[425]
  PIN bases[426]
    DIRECTION INPUT ;
    USE SIGNAL ;
    PORT
      LAYER M5 ;
        RECT 192.144 388.608 192.168 388.800 ;
    END
  END bases[426]
  PIN bases[427]
    DIRECTION INPUT ;
    USE SIGNAL ;
    PORT
      LAYER M3 ;
        RECT 192.597 388.608 192.621 388.800 ;
    END
  END bases[427]
  PIN bases[428]
    DIRECTION INPUT ;
    USE SIGNAL ;
    PORT
      LAYER M5 ;
        RECT 193.056 388.608 193.080 388.800 ;
    END
  END bases[428]
  PIN bases[429]
    DIRECTION INPUT ;
    USE SIGNAL ;
    PORT
      LAYER M3 ;
        RECT 193.497 388.608 193.521 388.800 ;
    END
  END bases[429]
  PIN bases[430]
    DIRECTION INPUT ;
    USE SIGNAL ;
    PORT
      LAYER M5 ;
        RECT 193.920 388.608 193.944 388.800 ;
    END
  END bases[430]
  PIN bases[431]
    DIRECTION INPUT ;
    USE SIGNAL ;
    PORT
      LAYER M3 ;
        RECT 194.397 388.608 194.421 388.800 ;
    END
  END bases[431]
  PIN bases[432]
    DIRECTION INPUT ;
    USE SIGNAL ;
    PORT
      LAYER M5 ;
        RECT 194.832 388.608 194.856 388.800 ;
    END
  END bases[432]
  PIN bases[433]
    DIRECTION INPUT ;
    USE SIGNAL ;
    PORT
      LAYER M3 ;
        RECT 195.261 388.608 195.285 388.800 ;
    END
  END bases[433]
  PIN bases[434]
    DIRECTION INPUT ;
    USE SIGNAL ;
    PORT
      LAYER M5 ;
        RECT 195.744 388.608 195.768 388.800 ;
    END
  END bases[434]
  PIN bases[435]
    DIRECTION INPUT ;
    USE SIGNAL ;
    PORT
      LAYER M3 ;
        RECT 196.161 388.608 196.185 388.800 ;
    END
  END bases[435]
  PIN bases[436]
    DIRECTION INPUT ;
    USE SIGNAL ;
    PORT
      LAYER M5 ;
        RECT 196.608 388.608 196.632 388.800 ;
    END
  END bases[436]
  PIN bases[437]
    DIRECTION INPUT ;
    USE SIGNAL ;
    PORT
      LAYER M3 ;
        RECT 197.061 388.608 197.085 388.800 ;
    END
  END bases[437]
  PIN bases[438]
    DIRECTION INPUT ;
    USE SIGNAL ;
    PORT
      LAYER M5 ;
        RECT 197.520 388.608 197.544 388.800 ;
    END
  END bases[438]
  PIN bases[439]
    DIRECTION INPUT ;
    USE SIGNAL ;
    PORT
      LAYER M3 ;
        RECT 197.961 388.608 197.985 388.800 ;
    END
  END bases[439]
  PIN bases[440]
    DIRECTION INPUT ;
    USE SIGNAL ;
    PORT
      LAYER M5 ;
        RECT 198.384 388.608 198.408 388.800 ;
    END
  END bases[440]
  PIN bases[441]
    DIRECTION INPUT ;
    USE SIGNAL ;
    PORT
      LAYER M3 ;
        RECT 198.825 388.608 198.849 388.800 ;
    END
  END bases[441]
  PIN bases[442]
    DIRECTION INPUT ;
    USE SIGNAL ;
    PORT
      LAYER M5 ;
        RECT 199.296 388.608 199.320 388.800 ;
    END
  END bases[442]
  PIN bases[443]
    DIRECTION INPUT ;
    USE SIGNAL ;
    PORT
      LAYER M3 ;
        RECT 199.725 388.608 199.749 388.800 ;
    END
  END bases[443]
  PIN bases[444]
    DIRECTION INPUT ;
    USE SIGNAL ;
    PORT
      LAYER M5 ;
        RECT 200.160 388.608 200.184 388.800 ;
    END
  END bases[444]
  PIN bases[445]
    DIRECTION INPUT ;
    USE SIGNAL ;
    PORT
      LAYER M3 ;
        RECT 200.625 388.608 200.649 388.800 ;
    END
  END bases[445]
  PIN bases[446]
    DIRECTION INPUT ;
    USE SIGNAL ;
    PORT
      LAYER M5 ;
        RECT 201.072 388.608 201.096 388.800 ;
    END
  END bases[446]
  PIN bases[447]
    DIRECTION INPUT ;
    USE SIGNAL ;
    PORT
      LAYER M3 ;
        RECT 201.489 388.608 201.513 388.800 ;
    END
  END bases[447]
  PIN bases[448]
    DIRECTION INPUT ;
    USE SIGNAL ;
    PORT
      LAYER M5 ;
        RECT 201.936 388.608 201.960 388.800 ;
    END
  END bases[448]
  PIN bases[449]
    DIRECTION INPUT ;
    USE SIGNAL ;
    PORT
      LAYER M3 ;
        RECT 202.389 388.608 202.413 388.800 ;
    END
  END bases[449]
  PIN bases[450]
    DIRECTION INPUT ;
    USE SIGNAL ;
    PORT
      LAYER M5 ;
        RECT 202.848 388.608 202.872 388.800 ;
    END
  END bases[450]
  PIN bases[451]
    DIRECTION INPUT ;
    USE SIGNAL ;
    PORT
      LAYER M3 ;
        RECT 203.289 388.608 203.313 388.800 ;
    END
  END bases[451]
  PIN bases[452]
    DIRECTION INPUT ;
    USE SIGNAL ;
    PORT
      LAYER M5 ;
        RECT 203.712 388.608 203.736 388.800 ;
    END
  END bases[452]
  PIN bases[453]
    DIRECTION INPUT ;
    USE SIGNAL ;
    PORT
      LAYER M3 ;
        RECT 204.153 388.608 204.177 388.800 ;
    END
  END bases[453]
  PIN bases[454]
    DIRECTION INPUT ;
    USE SIGNAL ;
    PORT
      LAYER M5 ;
        RECT 204.624 388.608 204.648 388.800 ;
    END
  END bases[454]
  PIN bases[455]
    DIRECTION INPUT ;
    USE SIGNAL ;
    PORT
      LAYER M3 ;
        RECT 205.053 388.608 205.077 388.800 ;
    END
  END bases[455]
  PIN bases[456]
    DIRECTION INPUT ;
    USE SIGNAL ;
    PORT
      LAYER M5 ;
        RECT 205.488 388.608 205.512 388.800 ;
    END
  END bases[456]
  PIN bases[457]
    DIRECTION INPUT ;
    USE SIGNAL ;
    PORT
      LAYER M3 ;
        RECT 205.953 388.608 205.977 388.800 ;
    END
  END bases[457]
  PIN bases[458]
    DIRECTION INPUT ;
    USE SIGNAL ;
    PORT
      LAYER M5 ;
        RECT 206.400 388.608 206.424 388.800 ;
    END
  END bases[458]
  PIN bases[459]
    DIRECTION INPUT ;
    USE SIGNAL ;
    PORT
      LAYER M3 ;
        RECT 206.817 388.608 206.841 388.800 ;
    END
  END bases[459]
  PIN bases[460]
    DIRECTION INPUT ;
    USE SIGNAL ;
    PORT
      LAYER M5 ;
        RECT 207.264 388.608 207.288 388.800 ;
    END
  END bases[460]
  PIN bases[461]
    DIRECTION INPUT ;
    USE SIGNAL ;
    PORT
      LAYER M3 ;
        RECT 207.717 388.608 207.741 388.800 ;
    END
  END bases[461]
  PIN bases[462]
    DIRECTION INPUT ;
    USE SIGNAL ;
    PORT
      LAYER M5 ;
        RECT 208.176 388.608 208.200 388.800 ;
    END
  END bases[462]
  PIN bases[463]
    DIRECTION INPUT ;
    USE SIGNAL ;
    PORT
      LAYER M3 ;
        RECT 208.617 388.608 208.641 388.800 ;
    END
  END bases[463]
  PIN bases[464]
    DIRECTION INPUT ;
    USE SIGNAL ;
    PORT
      LAYER M5 ;
        RECT 209.040 388.608 209.064 388.800 ;
    END
  END bases[464]
  PIN bases[465]
    DIRECTION INPUT ;
    USE SIGNAL ;
    PORT
      LAYER M3 ;
        RECT 209.517 388.608 209.541 388.800 ;
    END
  END bases[465]
  PIN bases[466]
    DIRECTION INPUT ;
    USE SIGNAL ;
    PORT
      LAYER M5 ;
        RECT 209.952 388.608 209.976 388.800 ;
    END
  END bases[466]
  PIN bases[467]
    DIRECTION INPUT ;
    USE SIGNAL ;
    PORT
      LAYER M3 ;
        RECT 210.381 388.608 210.405 388.800 ;
    END
  END bases[467]
  PIN bases[468]
    DIRECTION INPUT ;
    USE SIGNAL ;
    PORT
      LAYER M5 ;
        RECT 210.816 388.608 210.840 388.800 ;
    END
  END bases[468]
  PIN bases[469]
    DIRECTION INPUT ;
    USE SIGNAL ;
    PORT
      LAYER M3 ;
        RECT 211.281 388.608 211.305 388.800 ;
    END
  END bases[469]
  PIN bases[470]
    DIRECTION INPUT ;
    USE SIGNAL ;
    PORT
      LAYER M5 ;
        RECT 211.728 388.608 211.752 388.800 ;
    END
  END bases[470]
  PIN bases[471]
    DIRECTION INPUT ;
    USE SIGNAL ;
    PORT
      LAYER M3 ;
        RECT 212.181 388.608 212.205 388.800 ;
    END
  END bases[471]
  PIN bases[472]
    DIRECTION INPUT ;
    USE SIGNAL ;
    PORT
      LAYER M5 ;
        RECT 212.592 388.608 212.616 388.800 ;
    END
  END bases[472]
  PIN bases[473]
    DIRECTION INPUT ;
    USE SIGNAL ;
    PORT
      LAYER M3 ;
        RECT 213.045 388.608 213.069 388.800 ;
    END
  END bases[473]
  PIN bases[474]
    DIRECTION INPUT ;
    USE SIGNAL ;
    PORT
      LAYER M5 ;
        RECT 213.504 388.608 213.528 388.800 ;
    END
  END bases[474]
  PIN bases[475]
    DIRECTION INPUT ;
    USE SIGNAL ;
    PORT
      LAYER M3 ;
        RECT 213.945 388.608 213.969 388.800 ;
    END
  END bases[475]
  PIN bases[476]
    DIRECTION INPUT ;
    USE SIGNAL ;
    PORT
      LAYER M5 ;
        RECT 214.368 388.608 214.392 388.800 ;
    END
  END bases[476]
  PIN bases[477]
    DIRECTION INPUT ;
    USE SIGNAL ;
    PORT
      LAYER M3 ;
        RECT 214.845 388.608 214.869 388.800 ;
    END
  END bases[477]
  PIN bases[478]
    DIRECTION INPUT ;
    USE SIGNAL ;
    PORT
      LAYER M5 ;
        RECT 215.280 388.608 215.304 388.800 ;
    END
  END bases[478]
  PIN bases[479]
    DIRECTION INPUT ;
    USE SIGNAL ;
    PORT
      LAYER M3 ;
        RECT 215.709 388.608 215.733 388.800 ;
    END
  END bases[479]
  PIN bases[480]
    DIRECTION INPUT ;
    USE SIGNAL ;
    PORT
      LAYER M5 ;
        RECT 216.144 388.608 216.168 388.800 ;
    END
  END bases[480]
  PIN bases[481]
    DIRECTION INPUT ;
    USE SIGNAL ;
    PORT
      LAYER M3 ;
        RECT 216.609 388.608 216.633 388.800 ;
    END
  END bases[481]
  PIN bases[482]
    DIRECTION INPUT ;
    USE SIGNAL ;
    PORT
      LAYER M5 ;
        RECT 217.056 388.608 217.080 388.800 ;
    END
  END bases[482]
  PIN bases[483]
    DIRECTION INPUT ;
    USE SIGNAL ;
    PORT
      LAYER M3 ;
        RECT 217.509 388.608 217.533 388.800 ;
    END
  END bases[483]
  PIN bases[484]
    DIRECTION INPUT ;
    USE SIGNAL ;
    PORT
      LAYER M5 ;
        RECT 217.968 388.608 217.992 388.800 ;
    END
  END bases[484]
  PIN bases[485]
    DIRECTION INPUT ;
    USE SIGNAL ;
    PORT
      LAYER M3 ;
        RECT 218.373 388.608 218.397 388.800 ;
    END
  END bases[485]
  PIN bases[486]
    DIRECTION INPUT ;
    USE SIGNAL ;
    PORT
      LAYER M5 ;
        RECT 218.832 388.608 218.856 388.800 ;
    END
  END bases[486]
  PIN bases[487]
    DIRECTION INPUT ;
    USE SIGNAL ;
    PORT
      LAYER M3 ;
        RECT 219.273 388.608 219.297 388.800 ;
    END
  END bases[487]
  PIN bases[488]
    DIRECTION INPUT ;
    USE SIGNAL ;
    PORT
      LAYER M5 ;
        RECT 219.744 388.608 219.768 388.800 ;
    END
  END bases[488]
  PIN bases[489]
    DIRECTION INPUT ;
    USE SIGNAL ;
    PORT
      LAYER M3 ;
        RECT 220.173 388.608 220.197 388.800 ;
    END
  END bases[489]
  PIN bases[490]
    DIRECTION INPUT ;
    USE SIGNAL ;
    PORT
      LAYER M5 ;
        RECT 220.608 388.608 220.632 388.800 ;
    END
  END bases[490]
  PIN bases[491]
    DIRECTION INPUT ;
    USE SIGNAL ;
    PORT
      LAYER M3 ;
        RECT 221.073 388.608 221.097 388.800 ;
    END
  END bases[491]
  PIN bases[492]
    DIRECTION INPUT ;
    USE SIGNAL ;
    PORT
      LAYER M5 ;
        RECT 221.520 388.608 221.544 388.800 ;
    END
  END bases[492]
  PIN bases[493]
    DIRECTION INPUT ;
    USE SIGNAL ;
    PORT
      LAYER M3 ;
        RECT 221.937 388.608 221.961 388.800 ;
    END
  END bases[493]
  PIN bases[494]
    DIRECTION INPUT ;
    USE SIGNAL ;
    PORT
      LAYER M5 ;
        RECT 222.384 388.608 222.408 388.800 ;
    END
  END bases[494]
  PIN bases[495]
    DIRECTION INPUT ;
    USE SIGNAL ;
    PORT
      LAYER M3 ;
        RECT 222.837 388.608 222.861 388.800 ;
    END
  END bases[495]
  PIN bases[496]
    DIRECTION INPUT ;
    USE SIGNAL ;
    PORT
      LAYER M5 ;
        RECT 223.296 388.608 223.320 388.800 ;
    END
  END bases[496]
  PIN bases[497]
    DIRECTION INPUT ;
    USE SIGNAL ;
    PORT
      LAYER M3 ;
        RECT 223.737 388.608 223.761 388.800 ;
    END
  END bases[497]
  PIN bases[498]
    DIRECTION INPUT ;
    USE SIGNAL ;
    PORT
      LAYER M5 ;
        RECT 224.160 388.608 224.184 388.800 ;
    END
  END bases[498]
  PIN bases[499]
    DIRECTION INPUT ;
    USE SIGNAL ;
    PORT
      LAYER M3 ;
        RECT 224.601 388.608 224.625 388.800 ;
    END
  END bases[499]
  PIN bases[500]
    DIRECTION INPUT ;
    USE SIGNAL ;
    PORT
      LAYER M5 ;
        RECT 225.072 388.608 225.096 388.800 ;
    END
  END bases[500]
  PIN bases[501]
    DIRECTION INPUT ;
    USE SIGNAL ;
    PORT
      LAYER M3 ;
        RECT 225.501 388.608 225.525 388.800 ;
    END
  END bases[501]
  PIN bases[502]
    DIRECTION INPUT ;
    USE SIGNAL ;
    PORT
      LAYER M5 ;
        RECT 225.936 388.608 225.960 388.800 ;
    END
  END bases[502]
  PIN bases[503]
    DIRECTION INPUT ;
    USE SIGNAL ;
    PORT
      LAYER M3 ;
        RECT 226.401 388.608 226.425 388.800 ;
    END
  END bases[503]
  PIN bases[504]
    DIRECTION INPUT ;
    USE SIGNAL ;
    PORT
      LAYER M5 ;
        RECT 226.848 388.608 226.872 388.800 ;
    END
  END bases[504]
  PIN bases[505]
    DIRECTION INPUT ;
    USE SIGNAL ;
    PORT
      LAYER M3 ;
        RECT 227.265 388.608 227.289 388.800 ;
    END
  END bases[505]
  PIN bases[506]
    DIRECTION INPUT ;
    USE SIGNAL ;
    PORT
      LAYER M5 ;
        RECT 227.712 388.608 227.736 388.800 ;
    END
  END bases[506]
  PIN bases[507]
    DIRECTION INPUT ;
    USE SIGNAL ;
    PORT
      LAYER M3 ;
        RECT 228.165 388.608 228.189 388.800 ;
    END
  END bases[507]
  PIN bases[508]
    DIRECTION INPUT ;
    USE SIGNAL ;
    PORT
      LAYER M5 ;
        RECT 228.624 388.608 228.648 388.800 ;
    END
  END bases[508]
  PIN bases[509]
    DIRECTION INPUT ;
    USE SIGNAL ;
    PORT
      LAYER M3 ;
        RECT 229.065 388.608 229.089 388.800 ;
    END
  END bases[509]
  PIN bases[510]
    DIRECTION INPUT ;
    USE SIGNAL ;
    PORT
      LAYER M5 ;
        RECT 229.488 388.608 229.512 388.800 ;
    END
  END bases[510]
  PIN bases[511]
    DIRECTION INPUT ;
    USE SIGNAL ;
    PORT
      LAYER M3 ;
        RECT 229.929 388.608 229.953 388.800 ;
    END
  END bases[511]
  PIN bases[512]
    DIRECTION INPUT ;
    USE SIGNAL ;
    PORT
      LAYER M5 ;
        RECT 230.400 388.608 230.424 388.800 ;
    END
  END bases[512]
  PIN bases[513]
    DIRECTION INPUT ;
    USE SIGNAL ;
    PORT
      LAYER M3 ;
        RECT 230.829 388.608 230.853 388.800 ;
    END
  END bases[513]
  PIN bases[514]
    DIRECTION INPUT ;
    USE SIGNAL ;
    PORT
      LAYER M5 ;
        RECT 231.264 388.608 231.288 388.800 ;
    END
  END bases[514]
  PIN bases[515]
    DIRECTION INPUT ;
    USE SIGNAL ;
    PORT
      LAYER M3 ;
        RECT 231.729 388.608 231.753 388.800 ;
    END
  END bases[515]
  PIN bases[516]
    DIRECTION INPUT ;
    USE SIGNAL ;
    PORT
      LAYER M5 ;
        RECT 232.176 388.608 232.200 388.800 ;
    END
  END bases[516]
  PIN bases[517]
    DIRECTION INPUT ;
    USE SIGNAL ;
    PORT
      LAYER M3 ;
        RECT 232.629 388.608 232.653 388.800 ;
    END
  END bases[517]
  PIN bases[518]
    DIRECTION INPUT ;
    USE SIGNAL ;
    PORT
      LAYER M5 ;
        RECT 233.040 388.608 233.064 388.800 ;
    END
  END bases[518]
  PIN bases[519]
    DIRECTION INPUT ;
    USE SIGNAL ;
    PORT
      LAYER M3 ;
        RECT 233.493 388.608 233.517 388.800 ;
    END
  END bases[519]
  PIN bases[520]
    DIRECTION INPUT ;
    USE SIGNAL ;
    PORT
      LAYER M5 ;
        RECT 233.952 388.608 233.976 388.800 ;
    END
  END bases[520]
  PIN bases[521]
    DIRECTION INPUT ;
    USE SIGNAL ;
    PORT
      LAYER M3 ;
        RECT 234.393 388.608 234.417 388.800 ;
    END
  END bases[521]
  PIN bases[522]
    DIRECTION INPUT ;
    USE SIGNAL ;
    PORT
      LAYER M5 ;
        RECT 234.816 388.608 234.840 388.800 ;
    END
  END bases[522]
  PIN bases[523]
    DIRECTION INPUT ;
    USE SIGNAL ;
    PORT
      LAYER M3 ;
        RECT 235.293 388.608 235.317 388.800 ;
    END
  END bases[523]
  PIN bases[524]
    DIRECTION INPUT ;
    USE SIGNAL ;
    PORT
      LAYER M5 ;
        RECT 235.728 388.608 235.752 388.800 ;
    END
  END bases[524]
  PIN bases[525]
    DIRECTION INPUT ;
    USE SIGNAL ;
    PORT
      LAYER M3 ;
        RECT 236.157 388.608 236.181 388.800 ;
    END
  END bases[525]
  PIN bases[526]
    DIRECTION INPUT ;
    USE SIGNAL ;
    PORT
      LAYER M5 ;
        RECT 236.592 388.608 236.616 388.800 ;
    END
  END bases[526]
  PIN bases[527]
    DIRECTION INPUT ;
    USE SIGNAL ;
    PORT
      LAYER M3 ;
        RECT 237.057 388.608 237.081 388.800 ;
    END
  END bases[527]
  PIN bases[528]
    DIRECTION INPUT ;
    USE SIGNAL ;
    PORT
      LAYER M5 ;
        RECT 237.504 388.608 237.528 388.800 ;
    END
  END bases[528]
  PIN bases[529]
    DIRECTION INPUT ;
    USE SIGNAL ;
    PORT
      LAYER M3 ;
        RECT 237.957 388.608 237.981 388.800 ;
    END
  END bases[529]
  PIN bases[530]
    DIRECTION INPUT ;
    USE SIGNAL ;
    PORT
      LAYER M5 ;
        RECT 238.416 388.608 238.440 388.800 ;
    END
  END bases[530]
  PIN bases[531]
    DIRECTION INPUT ;
    USE SIGNAL ;
    PORT
      LAYER M3 ;
        RECT 238.821 388.608 238.845 388.800 ;
    END
  END bases[531]
  PIN bases[532]
    DIRECTION INPUT ;
    USE SIGNAL ;
    PORT
      LAYER M5 ;
        RECT 239.280 388.608 239.304 388.800 ;
    END
  END bases[532]
  PIN bases[533]
    DIRECTION INPUT ;
    USE SIGNAL ;
    PORT
      LAYER M3 ;
        RECT 239.721 388.608 239.745 388.800 ;
    END
  END bases[533]
  PIN bases[534]
    DIRECTION INPUT ;
    USE SIGNAL ;
    PORT
      LAYER M5 ;
        RECT 240.192 388.608 240.216 388.800 ;
    END
  END bases[534]
  PIN bases[535]
    DIRECTION INPUT ;
    USE SIGNAL ;
    PORT
      LAYER M3 ;
        RECT 240.621 388.608 240.645 388.800 ;
    END
  END bases[535]
  PIN bases[536]
    DIRECTION INPUT ;
    USE SIGNAL ;
    PORT
      LAYER M5 ;
        RECT 241.056 388.608 241.080 388.800 ;
    END
  END bases[536]
  PIN bases[537]
    DIRECTION INPUT ;
    USE SIGNAL ;
    PORT
      LAYER M3 ;
        RECT 241.521 388.608 241.545 388.800 ;
    END
  END bases[537]
  PIN bases[538]
    DIRECTION INPUT ;
    USE SIGNAL ;
    PORT
      LAYER M5 ;
        RECT 241.968 388.608 241.992 388.800 ;
    END
  END bases[538]
  PIN bases[539]
    DIRECTION INPUT ;
    USE SIGNAL ;
    PORT
      LAYER M3 ;
        RECT 242.385 388.608 242.409 388.800 ;
    END
  END bases[539]
  PIN bases[540]
    DIRECTION INPUT ;
    USE SIGNAL ;
    PORT
      LAYER M5 ;
        RECT 242.832 388.608 242.856 388.800 ;
    END
  END bases[540]
  PIN bases[541]
    DIRECTION INPUT ;
    USE SIGNAL ;
    PORT
      LAYER M3 ;
        RECT 243.285 388.608 243.309 388.800 ;
    END
  END bases[541]
  PIN bases[542]
    DIRECTION INPUT ;
    USE SIGNAL ;
    PORT
      LAYER M5 ;
        RECT 243.744 388.608 243.768 388.800 ;
    END
  END bases[542]
  PIN bases[543]
    DIRECTION INPUT ;
    USE SIGNAL ;
    PORT
      LAYER M3 ;
        RECT 244.185 388.608 244.209 388.800 ;
    END
  END bases[543]
  PIN bases[544]
    DIRECTION INPUT ;
    USE SIGNAL ;
    PORT
      LAYER M5 ;
        RECT 244.608 388.608 244.632 388.800 ;
    END
  END bases[544]
  PIN bases[545]
    DIRECTION INPUT ;
    USE SIGNAL ;
    PORT
      LAYER M3 ;
        RECT 245.049 388.608 245.073 388.800 ;
    END
  END bases[545]
  PIN bases[546]
    DIRECTION INPUT ;
    USE SIGNAL ;
    PORT
      LAYER M5 ;
        RECT 245.520 388.608 245.544 388.800 ;
    END
  END bases[546]
  PIN bases[547]
    DIRECTION INPUT ;
    USE SIGNAL ;
    PORT
      LAYER M3 ;
        RECT 245.949 388.608 245.973 388.800 ;
    END
  END bases[547]
  PIN bases[548]
    DIRECTION INPUT ;
    USE SIGNAL ;
    PORT
      LAYER M5 ;
        RECT 246.384 388.608 246.408 388.800 ;
    END
  END bases[548]
  PIN bases[549]
    DIRECTION INPUT ;
    USE SIGNAL ;
    PORT
      LAYER M3 ;
        RECT 246.849 388.608 246.873 388.800 ;
    END
  END bases[549]
  PIN bases[550]
    DIRECTION INPUT ;
    USE SIGNAL ;
    PORT
      LAYER M5 ;
        RECT 247.296 388.608 247.320 388.800 ;
    END
  END bases[550]
  PIN bases[551]
    DIRECTION INPUT ;
    USE SIGNAL ;
    PORT
      LAYER M3 ;
        RECT 247.713 388.608 247.737 388.800 ;
    END
  END bases[551]
  PIN bases[552]
    DIRECTION INPUT ;
    USE SIGNAL ;
    PORT
      LAYER M5 ;
        RECT 248.160 388.608 248.184 388.800 ;
    END
  END bases[552]
  PIN bases[553]
    DIRECTION INPUT ;
    USE SIGNAL ;
    PORT
      LAYER M3 ;
        RECT 248.613 388.608 248.637 388.800 ;
    END
  END bases[553]
  PIN bases[554]
    DIRECTION INPUT ;
    USE SIGNAL ;
    PORT
      LAYER M5 ;
        RECT 249.072 388.608 249.096 388.800 ;
    END
  END bases[554]
  PIN bases[555]
    DIRECTION INPUT ;
    USE SIGNAL ;
    PORT
      LAYER M3 ;
        RECT 249.513 388.608 249.537 388.800 ;
    END
  END bases[555]
  PIN bases[556]
    DIRECTION INPUT ;
    USE SIGNAL ;
    PORT
      LAYER M5 ;
        RECT 249.936 388.608 249.960 388.800 ;
    END
  END bases[556]
  PIN bases[557]
    DIRECTION INPUT ;
    USE SIGNAL ;
    PORT
      LAYER M3 ;
        RECT 250.377 388.608 250.401 388.800 ;
    END
  END bases[557]
  PIN bases[558]
    DIRECTION INPUT ;
    USE SIGNAL ;
    PORT
      LAYER M5 ;
        RECT 250.848 388.608 250.872 388.800 ;
    END
  END bases[558]
  PIN bases[559]
    DIRECTION INPUT ;
    USE SIGNAL ;
    PORT
      LAYER M3 ;
        RECT 251.277 388.608 251.301 388.800 ;
    END
  END bases[559]
  PIN bases[560]
    DIRECTION INPUT ;
    USE SIGNAL ;
    PORT
      LAYER M5 ;
        RECT 251.712 388.608 251.736 388.800 ;
    END
  END bases[560]
  PIN bases[561]
    DIRECTION INPUT ;
    USE SIGNAL ;
    PORT
      LAYER M3 ;
        RECT 252.177 388.608 252.201 388.800 ;
    END
  END bases[561]
  PIN bases[562]
    DIRECTION INPUT ;
    USE SIGNAL ;
    PORT
      LAYER M5 ;
        RECT 252.624 388.608 252.648 388.800 ;
    END
  END bases[562]
  PIN bases[563]
    DIRECTION INPUT ;
    USE SIGNAL ;
    PORT
      LAYER M3 ;
        RECT 253.077 388.608 253.101 388.800 ;
    END
  END bases[563]
  PIN bases[564]
    DIRECTION INPUT ;
    USE SIGNAL ;
    PORT
      LAYER M5 ;
        RECT 253.488 388.608 253.512 388.800 ;
    END
  END bases[564]
  PIN bases[565]
    DIRECTION INPUT ;
    USE SIGNAL ;
    PORT
      LAYER M3 ;
        RECT 253.941 388.608 253.965 388.800 ;
    END
  END bases[565]
  PIN bases[566]
    DIRECTION INPUT ;
    USE SIGNAL ;
    PORT
      LAYER M5 ;
        RECT 254.400 388.608 254.424 388.800 ;
    END
  END bases[566]
  PIN bases[567]
    DIRECTION INPUT ;
    USE SIGNAL ;
    PORT
      LAYER M3 ;
        RECT 254.841 388.608 254.865 388.800 ;
    END
  END bases[567]
  PIN bases[568]
    DIRECTION INPUT ;
    USE SIGNAL ;
    PORT
      LAYER M5 ;
        RECT 255.264 388.608 255.288 388.800 ;
    END
  END bases[568]
  PIN bases[569]
    DIRECTION INPUT ;
    USE SIGNAL ;
    PORT
      LAYER M3 ;
        RECT 255.741 388.608 255.765 388.800 ;
    END
  END bases[569]
  PIN bases[570]
    DIRECTION INPUT ;
    USE SIGNAL ;
    PORT
      LAYER M5 ;
        RECT 256.176 388.608 256.200 388.800 ;
    END
  END bases[570]
  PIN bases[571]
    DIRECTION INPUT ;
    USE SIGNAL ;
    PORT
      LAYER M3 ;
        RECT 256.605 388.608 256.629 388.800 ;
    END
  END bases[571]
  PIN bases[572]
    DIRECTION INPUT ;
    USE SIGNAL ;
    PORT
      LAYER M5 ;
        RECT 257.040 388.608 257.064 388.800 ;
    END
  END bases[572]
  PIN bases[573]
    DIRECTION INPUT ;
    USE SIGNAL ;
    PORT
      LAYER M3 ;
        RECT 257.505 388.608 257.529 388.800 ;
    END
  END bases[573]
  PIN bases[574]
    DIRECTION INPUT ;
    USE SIGNAL ;
    PORT
      LAYER M5 ;
        RECT 257.952 388.608 257.976 388.800 ;
    END
  END bases[574]
  PIN bases[575]
    DIRECTION INPUT ;
    USE SIGNAL ;
    PORT
      LAYER M3 ;
        RECT 258.405 388.608 258.429 388.800 ;
    END
  END bases[575]
  PIN bases[576]
    DIRECTION INPUT ;
    USE SIGNAL ;
    PORT
      LAYER M5 ;
        RECT 258.816 388.608 258.840 388.800 ;
    END
  END bases[576]
  PIN bases[577]
    DIRECTION INPUT ;
    USE SIGNAL ;
    PORT
      LAYER M3 ;
        RECT 259.269 388.608 259.293 388.800 ;
    END
  END bases[577]
  PIN bases[578]
    DIRECTION INPUT ;
    USE SIGNAL ;
    PORT
      LAYER M5 ;
        RECT 259.728 388.608 259.752 388.800 ;
    END
  END bases[578]
  PIN bases[579]
    DIRECTION INPUT ;
    USE SIGNAL ;
    PORT
      LAYER M3 ;
        RECT 260.169 388.608 260.193 388.800 ;
    END
  END bases[579]
  PIN bases[580]
    DIRECTION INPUT ;
    USE SIGNAL ;
    PORT
      LAYER M5 ;
        RECT 260.640 388.608 260.664 388.800 ;
    END
  END bases[580]
  PIN bases[581]
    DIRECTION INPUT ;
    USE SIGNAL ;
    PORT
      LAYER M3 ;
        RECT 261.069 388.608 261.093 388.800 ;
    END
  END bases[581]
  PIN bases[582]
    DIRECTION INPUT ;
    USE SIGNAL ;
    PORT
      LAYER M5 ;
        RECT 261.504 388.608 261.528 388.800 ;
    END
  END bases[582]
  PIN bases[583]
    DIRECTION INPUT ;
    USE SIGNAL ;
    PORT
      LAYER M3 ;
        RECT 261.933 388.608 261.957 388.800 ;
    END
  END bases[583]
  PIN bases[584]
    DIRECTION INPUT ;
    USE SIGNAL ;
    PORT
      LAYER M5 ;
        RECT 262.416 388.608 262.440 388.800 ;
    END
  END bases[584]
  PIN bases[585]
    DIRECTION INPUT ;
    USE SIGNAL ;
    PORT
      LAYER M3 ;
        RECT 262.833 388.608 262.857 388.800 ;
    END
  END bases[585]
  PIN bases[586]
    DIRECTION INPUT ;
    USE SIGNAL ;
    PORT
      LAYER M5 ;
        RECT 263.280 388.608 263.304 388.800 ;
    END
  END bases[586]
  PIN bases[587]
    DIRECTION INPUT ;
    USE SIGNAL ;
    PORT
      LAYER M3 ;
        RECT 263.733 388.608 263.757 388.800 ;
    END
  END bases[587]
  PIN bases[588]
    DIRECTION INPUT ;
    USE SIGNAL ;
    PORT
      LAYER M5 ;
        RECT 264.192 388.608 264.216 388.800 ;
    END
  END bases[588]
  PIN bases[589]
    DIRECTION INPUT ;
    USE SIGNAL ;
    PORT
      LAYER M3 ;
        RECT 264.633 388.608 264.657 388.800 ;
    END
  END bases[589]
  PIN bases[590]
    DIRECTION INPUT ;
    USE SIGNAL ;
    PORT
      LAYER M5 ;
        RECT 265.056 388.608 265.080 388.800 ;
    END
  END bases[590]
  PIN bases[591]
    DIRECTION INPUT ;
    USE SIGNAL ;
    PORT
      LAYER M3 ;
        RECT 265.497 388.608 265.521 388.800 ;
    END
  END bases[591]
  PIN bases[592]
    DIRECTION INPUT ;
    USE SIGNAL ;
    PORT
      LAYER M5 ;
        RECT 265.968 388.608 265.992 388.800 ;
    END
  END bases[592]
  PIN bases[593]
    DIRECTION INPUT ;
    USE SIGNAL ;
    PORT
      LAYER M3 ;
        RECT 266.397 388.608 266.421 388.800 ;
    END
  END bases[593]
  PIN bases[594]
    DIRECTION INPUT ;
    USE SIGNAL ;
    PORT
      LAYER M5 ;
        RECT 266.832 388.608 266.856 388.800 ;
    END
  END bases[594]
  PIN bases[595]
    DIRECTION INPUT ;
    USE SIGNAL ;
    PORT
      LAYER M3 ;
        RECT 267.297 388.608 267.321 388.800 ;
    END
  END bases[595]
  PIN bases[596]
    DIRECTION INPUT ;
    USE SIGNAL ;
    PORT
      LAYER M5 ;
        RECT 267.744 388.608 267.768 388.800 ;
    END
  END bases[596]
  PIN bases[597]
    DIRECTION INPUT ;
    USE SIGNAL ;
    PORT
      LAYER M3 ;
        RECT 268.161 388.608 268.185 388.800 ;
    END
  END bases[597]
  PIN bases[598]
    DIRECTION INPUT ;
    USE SIGNAL ;
    PORT
      LAYER M5 ;
        RECT 268.608 388.608 268.632 388.800 ;
    END
  END bases[598]
  PIN bases[599]
    DIRECTION INPUT ;
    USE SIGNAL ;
    PORT
      LAYER M3 ;
        RECT 269.061 388.608 269.085 388.800 ;
    END
  END bases[599]
  PIN bases[600]
    DIRECTION INPUT ;
    USE SIGNAL ;
    PORT
      LAYER M5 ;
        RECT 269.520 388.608 269.544 388.800 ;
    END
  END bases[600]
  PIN bases[601]
    DIRECTION INPUT ;
    USE SIGNAL ;
    PORT
      LAYER M3 ;
        RECT 269.961 388.608 269.985 388.800 ;
    END
  END bases[601]
  PIN bases[602]
    DIRECTION INPUT ;
    USE SIGNAL ;
    PORT
      LAYER M5 ;
        RECT 270.384 388.608 270.408 388.800 ;
    END
  END bases[602]
  PIN bases[603]
    DIRECTION INPUT ;
    USE SIGNAL ;
    PORT
      LAYER M3 ;
        RECT 270.825 388.608 270.849 388.800 ;
    END
  END bases[603]
  PIN bases[604]
    DIRECTION INPUT ;
    USE SIGNAL ;
    PORT
      LAYER M5 ;
        RECT 271.296 388.608 271.320 388.800 ;
    END
  END bases[604]
  PIN bases[605]
    DIRECTION INPUT ;
    USE SIGNAL ;
    PORT
      LAYER M3 ;
        RECT 271.725 388.608 271.749 388.800 ;
    END
  END bases[605]
  PIN bases[606]
    DIRECTION INPUT ;
    USE SIGNAL ;
    PORT
      LAYER M5 ;
        RECT 272.160 388.608 272.184 388.800 ;
    END
  END bases[606]
  PIN bases[607]
    DIRECTION INPUT ;
    USE SIGNAL ;
    PORT
      LAYER M3 ;
        RECT 272.625 388.608 272.649 388.800 ;
    END
  END bases[607]
  PIN bases[608]
    DIRECTION INPUT ;
    USE SIGNAL ;
    PORT
      LAYER M5 ;
        RECT 273.072 388.608 273.096 388.800 ;
    END
  END bases[608]
  PIN bases[609]
    DIRECTION INPUT ;
    USE SIGNAL ;
    PORT
      LAYER M3 ;
        RECT 273.489 388.608 273.513 388.800 ;
    END
  END bases[609]
  PIN bases[610]
    DIRECTION INPUT ;
    USE SIGNAL ;
    PORT
      LAYER M5 ;
        RECT 273.936 388.608 273.960 388.800 ;
    END
  END bases[610]
  PIN bases[611]
    DIRECTION INPUT ;
    USE SIGNAL ;
    PORT
      LAYER M3 ;
        RECT 274.389 388.608 274.413 388.800 ;
    END
  END bases[611]
  PIN bases[612]
    DIRECTION INPUT ;
    USE SIGNAL ;
    PORT
      LAYER M5 ;
        RECT 274.848 388.608 274.872 388.800 ;
    END
  END bases[612]
  PIN bases[613]
    DIRECTION INPUT ;
    USE SIGNAL ;
    PORT
      LAYER M3 ;
        RECT 275.289 388.608 275.313 388.800 ;
    END
  END bases[613]
  PIN bases[614]
    DIRECTION INPUT ;
    USE SIGNAL ;
    PORT
      LAYER M5 ;
        RECT 275.712 388.608 275.736 388.800 ;
    END
  END bases[614]
  PIN bases[615]
    DIRECTION INPUT ;
    USE SIGNAL ;
    PORT
      LAYER M3 ;
        RECT 276.189 388.608 276.213 388.800 ;
    END
  END bases[615]
  PIN bases[616]
    DIRECTION INPUT ;
    USE SIGNAL ;
    PORT
      LAYER M5 ;
        RECT 276.624 388.608 276.648 388.800 ;
    END
  END bases[616]
  PIN bases[617]
    DIRECTION INPUT ;
    USE SIGNAL ;
    PORT
      LAYER M3 ;
        RECT 277.053 388.608 277.077 388.800 ;
    END
  END bases[617]
  PIN bases[618]
    DIRECTION INPUT ;
    USE SIGNAL ;
    PORT
      LAYER M5 ;
        RECT 277.488 388.608 277.512 388.800 ;
    END
  END bases[618]
  PIN bases[619]
    DIRECTION INPUT ;
    USE SIGNAL ;
    PORT
      LAYER M3 ;
        RECT 277.953 388.608 277.977 388.800 ;
    END
  END bases[619]
  PIN bases[620]
    DIRECTION INPUT ;
    USE SIGNAL ;
    PORT
      LAYER M5 ;
        RECT 278.400 388.608 278.424 388.800 ;
    END
  END bases[620]
  PIN bases[621]
    DIRECTION INPUT ;
    USE SIGNAL ;
    PORT
      LAYER M3 ;
        RECT 278.853 388.608 278.877 388.800 ;
    END
  END bases[621]
  PIN bases[622]
    DIRECTION INPUT ;
    USE SIGNAL ;
    PORT
      LAYER M5 ;
        RECT 279.264 388.608 279.288 388.800 ;
    END
  END bases[622]
  PIN bases[623]
    DIRECTION INPUT ;
    USE SIGNAL ;
    PORT
      LAYER M3 ;
        RECT 279.717 388.608 279.741 388.800 ;
    END
  END bases[623]
  PIN bases[624]
    DIRECTION INPUT ;
    USE SIGNAL ;
    PORT
      LAYER M5 ;
        RECT 280.176 388.608 280.200 388.800 ;
    END
  END bases[624]
  PIN bases[625]
    DIRECTION INPUT ;
    USE SIGNAL ;
    PORT
      LAYER M3 ;
        RECT 280.617 388.608 280.641 388.800 ;
    END
  END bases[625]
  PIN bases[626]
    DIRECTION INPUT ;
    USE SIGNAL ;
    PORT
      LAYER M5 ;
        RECT 281.040 388.608 281.064 388.800 ;
    END
  END bases[626]
  PIN bases[627]
    DIRECTION INPUT ;
    USE SIGNAL ;
    PORT
      LAYER M3 ;
        RECT 281.517 388.608 281.541 388.800 ;
    END
  END bases[627]
  PIN bases[628]
    DIRECTION INPUT ;
    USE SIGNAL ;
    PORT
      LAYER M5 ;
        RECT 281.952 388.608 281.976 388.800 ;
    END
  END bases[628]
  PIN bases[629]
    DIRECTION INPUT ;
    USE SIGNAL ;
    PORT
      LAYER M3 ;
        RECT 282.381 388.608 282.405 388.800 ;
    END
  END bases[629]
  PIN bases[630]
    DIRECTION INPUT ;
    USE SIGNAL ;
    PORT
      LAYER M5 ;
        RECT 282.864 388.608 282.888 388.800 ;
    END
  END bases[630]
  PIN bases[631]
    DIRECTION INPUT ;
    USE SIGNAL ;
    PORT
      LAYER M3 ;
        RECT 283.281 388.608 283.305 388.800 ;
    END
  END bases[631]
  PIN bases[632]
    DIRECTION INPUT ;
    USE SIGNAL ;
    PORT
      LAYER M5 ;
        RECT 283.728 388.608 283.752 388.800 ;
    END
  END bases[632]
  PIN bases[633]
    DIRECTION INPUT ;
    USE SIGNAL ;
    PORT
      LAYER M3 ;
        RECT 284.181 388.608 284.205 388.800 ;
    END
  END bases[633]
  PIN bases[634]
    DIRECTION INPUT ;
    USE SIGNAL ;
    PORT
      LAYER M5 ;
        RECT 284.640 388.608 284.664 388.800 ;
    END
  END bases[634]
  PIN bases[635]
    DIRECTION INPUT ;
    USE SIGNAL ;
    PORT
      LAYER M3 ;
        RECT 285.081 388.608 285.105 388.800 ;
    END
  END bases[635]
  PIN bases[636]
    DIRECTION INPUT ;
    USE SIGNAL ;
    PORT
      LAYER M5 ;
        RECT 285.504 388.608 285.528 388.800 ;
    END
  END bases[636]
  PIN bases[637]
    DIRECTION INPUT ;
    USE SIGNAL ;
    PORT
      LAYER M3 ;
        RECT 285.945 388.608 285.969 388.800 ;
    END
  END bases[637]
  PIN bases[638]
    DIRECTION INPUT ;
    USE SIGNAL ;
    PORT
      LAYER M5 ;
        RECT 286.416 388.608 286.440 388.800 ;
    END
  END bases[638]
  PIN bases[639]
    DIRECTION INPUT ;
    USE SIGNAL ;
    PORT
      LAYER M3 ;
        RECT 286.845 388.608 286.869 388.800 ;
    END
  END bases[639]
  PIN bases[640]
    DIRECTION INPUT ;
    USE SIGNAL ;
    PORT
      LAYER M5 ;
        RECT 287.280 388.608 287.304 388.800 ;
    END
  END bases[640]
  PIN bases[641]
    DIRECTION INPUT ;
    USE SIGNAL ;
    PORT
      LAYER M3 ;
        RECT 287.745 388.608 287.769 388.800 ;
    END
  END bases[641]
  PIN bases[642]
    DIRECTION INPUT ;
    USE SIGNAL ;
    PORT
      LAYER M5 ;
        RECT 288.192 388.608 288.216 388.800 ;
    END
  END bases[642]
  PIN bases[643]
    DIRECTION INPUT ;
    USE SIGNAL ;
    PORT
      LAYER M3 ;
        RECT 288.609 388.608 288.633 388.800 ;
    END
  END bases[643]
  PIN bases[644]
    DIRECTION INPUT ;
    USE SIGNAL ;
    PORT
      LAYER M5 ;
        RECT 289.056 388.608 289.080 388.800 ;
    END
  END bases[644]
  PIN bases[645]
    DIRECTION INPUT ;
    USE SIGNAL ;
    PORT
      LAYER M3 ;
        RECT 289.509 388.608 289.533 388.800 ;
    END
  END bases[645]
  PIN bases[646]
    DIRECTION INPUT ;
    USE SIGNAL ;
    PORT
      LAYER M5 ;
        RECT 289.968 388.608 289.992 388.800 ;
    END
  END bases[646]
  PIN bases[647]
    DIRECTION INPUT ;
    USE SIGNAL ;
    PORT
      LAYER M3 ;
        RECT 290.409 388.608 290.433 388.800 ;
    END
  END bases[647]
  PIN bases[648]
    DIRECTION INPUT ;
    USE SIGNAL ;
    PORT
      LAYER M5 ;
        RECT 290.832 388.608 290.856 388.800 ;
    END
  END bases[648]
  PIN bases[649]
    DIRECTION INPUT ;
    USE SIGNAL ;
    PORT
      LAYER M3 ;
        RECT 291.273 388.608 291.297 388.800 ;
    END
  END bases[649]
  PIN bases[650]
    DIRECTION INPUT ;
    USE SIGNAL ;
    PORT
      LAYER M5 ;
        RECT 291.744 388.608 291.768 388.800 ;
    END
  END bases[650]
  PIN bases[651]
    DIRECTION INPUT ;
    USE SIGNAL ;
    PORT
      LAYER M3 ;
        RECT 292.173 388.608 292.197 388.800 ;
    END
  END bases[651]
  PIN bases[652]
    DIRECTION INPUT ;
    USE SIGNAL ;
    PORT
      LAYER M5 ;
        RECT 292.608 388.608 292.632 388.800 ;
    END
  END bases[652]
  PIN bases[653]
    DIRECTION INPUT ;
    USE SIGNAL ;
    PORT
      LAYER M3 ;
        RECT 293.073 388.608 293.097 388.800 ;
    END
  END bases[653]
  PIN bases[654]
    DIRECTION INPUT ;
    USE SIGNAL ;
    PORT
      LAYER M5 ;
        RECT 293.520 388.608 293.544 388.800 ;
    END
  END bases[654]
  PIN bases[655]
    DIRECTION INPUT ;
    USE SIGNAL ;
    PORT
      LAYER M3 ;
        RECT 293.937 388.608 293.961 388.800 ;
    END
  END bases[655]
  PIN bases[656]
    DIRECTION INPUT ;
    USE SIGNAL ;
    PORT
      LAYER M5 ;
        RECT 294.384 388.608 294.408 388.800 ;
    END
  END bases[656]
  PIN bases[657]
    DIRECTION INPUT ;
    USE SIGNAL ;
    PORT
      LAYER M3 ;
        RECT 294.837 388.608 294.861 388.800 ;
    END
  END bases[657]
  PIN bases[658]
    DIRECTION INPUT ;
    USE SIGNAL ;
    PORT
      LAYER M5 ;
        RECT 295.296 388.608 295.320 388.800 ;
    END
  END bases[658]
  PIN bases[659]
    DIRECTION INPUT ;
    USE SIGNAL ;
    PORT
      LAYER M3 ;
        RECT 295.737 388.608 295.761 388.800 ;
    END
  END bases[659]
  PIN bases[660]
    DIRECTION INPUT ;
    USE SIGNAL ;
    PORT
      LAYER M5 ;
        RECT 296.160 388.608 296.184 388.800 ;
    END
  END bases[660]
  PIN bases[661]
    DIRECTION INPUT ;
    USE SIGNAL ;
    PORT
      LAYER M3 ;
        RECT 296.637 388.608 296.661 388.800 ;
    END
  END bases[661]
  PIN bases[662]
    DIRECTION INPUT ;
    USE SIGNAL ;
    PORT
      LAYER M5 ;
        RECT 297.072 388.608 297.096 388.800 ;
    END
  END bases[662]
  PIN bases[663]
    DIRECTION INPUT ;
    USE SIGNAL ;
    PORT
      LAYER M3 ;
        RECT 297.501 388.608 297.525 388.800 ;
    END
  END bases[663]
  PIN bases[664]
    DIRECTION INPUT ;
    USE SIGNAL ;
    PORT
      LAYER M5 ;
        RECT 297.936 388.608 297.960 388.800 ;
    END
  END bases[664]
  PIN bases[665]
    DIRECTION INPUT ;
    USE SIGNAL ;
    PORT
      LAYER M3 ;
        RECT 298.401 388.608 298.425 388.800 ;
    END
  END bases[665]
  PIN bases[666]
    DIRECTION INPUT ;
    USE SIGNAL ;
    PORT
      LAYER M5 ;
        RECT 298.848 388.608 298.872 388.800 ;
    END
  END bases[666]
  PIN bases[667]
    DIRECTION INPUT ;
    USE SIGNAL ;
    PORT
      LAYER M3 ;
        RECT 299.301 388.608 299.325 388.800 ;
    END
  END bases[667]
  PIN bases[668]
    DIRECTION INPUT ;
    USE SIGNAL ;
    PORT
      LAYER M5 ;
        RECT 299.712 388.608 299.736 388.800 ;
    END
  END bases[668]
  PIN bases[669]
    DIRECTION INPUT ;
    USE SIGNAL ;
    PORT
      LAYER M3 ;
        RECT 300.165 388.608 300.189 388.800 ;
    END
  END bases[669]
  PIN bases[670]
    DIRECTION INPUT ;
    USE SIGNAL ;
    PORT
      LAYER M5 ;
        RECT 300.624 388.608 300.648 388.800 ;
    END
  END bases[670]
  PIN bases[671]
    DIRECTION INPUT ;
    USE SIGNAL ;
    PORT
      LAYER M3 ;
        RECT 301.065 388.608 301.089 388.800 ;
    END
  END bases[671]
  PIN bases[672]
    DIRECTION INPUT ;
    USE SIGNAL ;
    PORT
      LAYER M5 ;
        RECT 301.488 388.608 301.512 388.800 ;
    END
  END bases[672]
  PIN bases[673]
    DIRECTION INPUT ;
    USE SIGNAL ;
    PORT
      LAYER M3 ;
        RECT 301.965 388.608 301.989 388.800 ;
    END
  END bases[673]
  PIN bases[674]
    DIRECTION INPUT ;
    USE SIGNAL ;
    PORT
      LAYER M5 ;
        RECT 302.400 388.608 302.424 388.800 ;
    END
  END bases[674]
  PIN bases[675]
    DIRECTION INPUT ;
    USE SIGNAL ;
    PORT
      LAYER M3 ;
        RECT 302.829 388.608 302.853 388.800 ;
    END
  END bases[675]
  PIN bases[676]
    DIRECTION INPUT ;
    USE SIGNAL ;
    PORT
      LAYER M5 ;
        RECT 303.264 388.608 303.288 388.800 ;
    END
  END bases[676]
  PIN bases[677]
    DIRECTION INPUT ;
    USE SIGNAL ;
    PORT
      LAYER M3 ;
        RECT 303.729 388.608 303.753 388.800 ;
    END
  END bases[677]
  PIN bases[678]
    DIRECTION INPUT ;
    USE SIGNAL ;
    PORT
      LAYER M5 ;
        RECT 304.176 388.608 304.200 388.800 ;
    END
  END bases[678]
  PIN bases[679]
    DIRECTION INPUT ;
    USE SIGNAL ;
    PORT
      LAYER M3 ;
        RECT 304.629 388.608 304.653 388.800 ;
    END
  END bases[679]
  PIN bases[680]
    DIRECTION INPUT ;
    USE SIGNAL ;
    PORT
      LAYER M5 ;
        RECT 305.088 388.608 305.112 388.800 ;
    END
  END bases[680]
  PIN bases[681]
    DIRECTION INPUT ;
    USE SIGNAL ;
    PORT
      LAYER M3 ;
        RECT 305.493 388.608 305.517 388.800 ;
    END
  END bases[681]
  PIN bases[682]
    DIRECTION INPUT ;
    USE SIGNAL ;
    PORT
      LAYER M5 ;
        RECT 305.952 388.608 305.976 388.800 ;
    END
  END bases[682]
  PIN bases[683]
    DIRECTION INPUT ;
    USE SIGNAL ;
    PORT
      LAYER M3 ;
        RECT 306.393 388.608 306.417 388.800 ;
    END
  END bases[683]
  PIN bases[684]
    DIRECTION INPUT ;
    USE SIGNAL ;
    PORT
      LAYER M5 ;
        RECT 306.864 388.608 306.888 388.800 ;
    END
  END bases[684]
  PIN bases[685]
    DIRECTION INPUT ;
    USE SIGNAL ;
    PORT
      LAYER M3 ;
        RECT 307.293 388.608 307.317 388.800 ;
    END
  END bases[685]
  PIN bases[686]
    DIRECTION INPUT ;
    USE SIGNAL ;
    PORT
      LAYER M5 ;
        RECT 307.728 388.608 307.752 388.800 ;
    END
  END bases[686]
  PIN bases[687]
    DIRECTION INPUT ;
    USE SIGNAL ;
    PORT
      LAYER M3 ;
        RECT 308.193 388.608 308.217 388.800 ;
    END
  END bases[687]
  PIN bases[688]
    DIRECTION INPUT ;
    USE SIGNAL ;
    PORT
      LAYER M5 ;
        RECT 308.640 388.608 308.664 388.800 ;
    END
  END bases[688]
  PIN bases[689]
    DIRECTION INPUT ;
    USE SIGNAL ;
    PORT
      LAYER M3 ;
        RECT 309.057 388.608 309.081 388.800 ;
    END
  END bases[689]
  PIN bases[690]
    DIRECTION INPUT ;
    USE SIGNAL ;
    PORT
      LAYER M5 ;
        RECT 309.504 388.608 309.528 388.800 ;
    END
  END bases[690]
  PIN bases[691]
    DIRECTION INPUT ;
    USE SIGNAL ;
    PORT
      LAYER M3 ;
        RECT 309.957 388.608 309.981 388.800 ;
    END
  END bases[691]
  PIN bases[692]
    DIRECTION INPUT ;
    USE SIGNAL ;
    PORT
      LAYER M5 ;
        RECT 310.416 388.608 310.440 388.800 ;
    END
  END bases[692]
  PIN bases[693]
    DIRECTION INPUT ;
    USE SIGNAL ;
    PORT
      LAYER M3 ;
        RECT 310.857 388.608 310.881 388.800 ;
    END
  END bases[693]
  PIN bases[694]
    DIRECTION INPUT ;
    USE SIGNAL ;
    PORT
      LAYER M5 ;
        RECT 311.280 388.608 311.304 388.800 ;
    END
  END bases[694]
  PIN bases[695]
    DIRECTION INPUT ;
    USE SIGNAL ;
    PORT
      LAYER M3 ;
        RECT 311.721 388.608 311.745 388.800 ;
    END
  END bases[695]
  PIN bases[696]
    DIRECTION INPUT ;
    USE SIGNAL ;
    PORT
      LAYER M5 ;
        RECT 312.192 388.608 312.216 388.800 ;
    END
  END bases[696]
  PIN bases[697]
    DIRECTION INPUT ;
    USE SIGNAL ;
    PORT
      LAYER M3 ;
        RECT 312.621 388.608 312.645 388.800 ;
    END
  END bases[697]
  PIN bases[698]
    DIRECTION INPUT ;
    USE SIGNAL ;
    PORT
      LAYER M5 ;
        RECT 313.056 388.608 313.080 388.800 ;
    END
  END bases[698]
  PIN bases[699]
    DIRECTION INPUT ;
    USE SIGNAL ;
    PORT
      LAYER M3 ;
        RECT 313.521 388.608 313.545 388.800 ;
    END
  END bases[699]
  PIN bases[700]
    DIRECTION INPUT ;
    USE SIGNAL ;
    PORT
      LAYER M5 ;
        RECT 313.968 388.608 313.992 388.800 ;
    END
  END bases[700]
  PIN bases[701]
    DIRECTION INPUT ;
    USE SIGNAL ;
    PORT
      LAYER M3 ;
        RECT 314.385 388.608 314.409 388.800 ;
    END
  END bases[701]
  PIN bases[702]
    DIRECTION INPUT ;
    USE SIGNAL ;
    PORT
      LAYER M5 ;
        RECT 314.832 388.608 314.856 388.800 ;
    END
  END bases[702]
  PIN bases[703]
    DIRECTION INPUT ;
    USE SIGNAL ;
    PORT
      LAYER M3 ;
        RECT 315.285 388.608 315.309 388.800 ;
    END
  END bases[703]
  PIN bases[704]
    DIRECTION INPUT ;
    USE SIGNAL ;
    PORT
      LAYER M5 ;
        RECT 315.744 388.608 315.768 388.800 ;
    END
  END bases[704]
  PIN bases[705]
    DIRECTION INPUT ;
    USE SIGNAL ;
    PORT
      LAYER M3 ;
        RECT 316.185 388.608 316.209 388.800 ;
    END
  END bases[705]
  PIN bases[706]
    DIRECTION INPUT ;
    USE SIGNAL ;
    PORT
      LAYER M5 ;
        RECT 316.608 388.608 316.632 388.800 ;
    END
  END bases[706]
  PIN bases[707]
    DIRECTION INPUT ;
    USE SIGNAL ;
    PORT
      LAYER M3 ;
        RECT 317.049 388.608 317.073 388.800 ;
    END
  END bases[707]
  PIN bases[708]
    DIRECTION INPUT ;
    USE SIGNAL ;
    PORT
      LAYER M5 ;
        RECT 317.520 388.608 317.544 388.800 ;
    END
  END bases[708]
  PIN bases[709]
    DIRECTION INPUT ;
    USE SIGNAL ;
    PORT
      LAYER M3 ;
        RECT 317.949 388.608 317.973 388.800 ;
    END
  END bases[709]
  PIN bases[710]
    DIRECTION INPUT ;
    USE SIGNAL ;
    PORT
      LAYER M5 ;
        RECT 318.384 388.608 318.408 388.800 ;
    END
  END bases[710]
  PIN bases[711]
    DIRECTION INPUT ;
    USE SIGNAL ;
    PORT
      LAYER M3 ;
        RECT 318.849 388.608 318.873 388.800 ;
    END
  END bases[711]
  PIN bases[712]
    DIRECTION INPUT ;
    USE SIGNAL ;
    PORT
      LAYER M5 ;
        RECT 319.296 388.608 319.320 388.800 ;
    END
  END bases[712]
  PIN bases[713]
    DIRECTION INPUT ;
    USE SIGNAL ;
    PORT
      LAYER M3 ;
        RECT 319.749 388.608 319.773 388.800 ;
    END
  END bases[713]
  PIN bases[714]
    DIRECTION INPUT ;
    USE SIGNAL ;
    PORT
      LAYER M5 ;
        RECT 320.160 388.608 320.184 388.800 ;
    END
  END bases[714]
  PIN bases[715]
    DIRECTION INPUT ;
    USE SIGNAL ;
    PORT
      LAYER M3 ;
        RECT 320.613 388.608 320.637 388.800 ;
    END
  END bases[715]
  PIN bases[716]
    DIRECTION INPUT ;
    USE SIGNAL ;
    PORT
      LAYER M5 ;
        RECT 321.072 388.608 321.096 388.800 ;
    END
  END bases[716]
  PIN bases[717]
    DIRECTION INPUT ;
    USE SIGNAL ;
    PORT
      LAYER M3 ;
        RECT 321.513 388.608 321.537 388.800 ;
    END
  END bases[717]
  PIN bases[718]
    DIRECTION INPUT ;
    USE SIGNAL ;
    PORT
      LAYER M5 ;
        RECT 321.936 388.608 321.960 388.800 ;
    END
  END bases[718]
  PIN bases[719]
    DIRECTION INPUT ;
    USE SIGNAL ;
    PORT
      LAYER M3 ;
        RECT 322.413 388.608 322.437 388.800 ;
    END
  END bases[719]
  PIN bases[720]
    DIRECTION INPUT ;
    USE SIGNAL ;
    PORT
      LAYER M5 ;
        RECT 322.848 388.608 322.872 388.800 ;
    END
  END bases[720]
  PIN bases[721]
    DIRECTION INPUT ;
    USE SIGNAL ;
    PORT
      LAYER M3 ;
        RECT 323.277 388.608 323.301 388.800 ;
    END
  END bases[721]
  PIN bases[722]
    DIRECTION INPUT ;
    USE SIGNAL ;
    PORT
      LAYER M5 ;
        RECT 323.712 388.608 323.736 388.800 ;
    END
  END bases[722]
  PIN bases[723]
    DIRECTION INPUT ;
    USE SIGNAL ;
    PORT
      LAYER M3 ;
        RECT 324.177 388.608 324.201 388.800 ;
    END
  END bases[723]
  PIN bases[724]
    DIRECTION INPUT ;
    USE SIGNAL ;
    PORT
      LAYER M5 ;
        RECT 324.624 388.608 324.648 388.800 ;
    END
  END bases[724]
  PIN bases[725]
    DIRECTION INPUT ;
    USE SIGNAL ;
    PORT
      LAYER M3 ;
        RECT 325.077 388.608 325.101 388.800 ;
    END
  END bases[725]
  PIN bases[726]
    DIRECTION INPUT ;
    USE SIGNAL ;
    PORT
      LAYER M5 ;
        RECT 325.488 388.608 325.512 388.800 ;
    END
  END bases[726]
  PIN bases[727]
    DIRECTION INPUT ;
    USE SIGNAL ;
    PORT
      LAYER M3 ;
        RECT 325.941 388.608 325.965 388.800 ;
    END
  END bases[727]
  PIN bases[728]
    DIRECTION INPUT ;
    USE SIGNAL ;
    PORT
      LAYER M5 ;
        RECT 326.400 388.608 326.424 388.800 ;
    END
  END bases[728]
  PIN bases[729]
    DIRECTION INPUT ;
    USE SIGNAL ;
    PORT
      LAYER M3 ;
        RECT 326.841 388.608 326.865 388.800 ;
    END
  END bases[729]
  PIN bases[730]
    DIRECTION INPUT ;
    USE SIGNAL ;
    PORT
      LAYER M5 ;
        RECT 327.312 388.608 327.336 388.800 ;
    END
  END bases[730]
  PIN bases[731]
    DIRECTION INPUT ;
    USE SIGNAL ;
    PORT
      LAYER M3 ;
        RECT 327.741 388.608 327.765 388.800 ;
    END
  END bases[731]
  PIN bases[732]
    DIRECTION INPUT ;
    USE SIGNAL ;
    PORT
      LAYER M5 ;
        RECT 328.176 388.608 328.200 388.800 ;
    END
  END bases[732]
  PIN bases[733]
    DIRECTION INPUT ;
    USE SIGNAL ;
    PORT
      LAYER M3 ;
        RECT 328.605 388.608 328.629 388.800 ;
    END
  END bases[733]
  PIN bases[734]
    DIRECTION INPUT ;
    USE SIGNAL ;
    PORT
      LAYER M5 ;
        RECT 329.088 388.608 329.112 388.800 ;
    END
  END bases[734]
  PIN bases[735]
    DIRECTION INPUT ;
    USE SIGNAL ;
    PORT
      LAYER M3 ;
        RECT 329.505 388.608 329.529 388.800 ;
    END
  END bases[735]
  PIN bases[736]
    DIRECTION INPUT ;
    USE SIGNAL ;
    PORT
      LAYER M5 ;
        RECT 329.952 388.608 329.976 388.800 ;
    END
  END bases[736]
  PIN bases[737]
    DIRECTION INPUT ;
    USE SIGNAL ;
    PORT
      LAYER M3 ;
        RECT 330.405 388.608 330.429 388.800 ;
    END
  END bases[737]
  PIN bases[738]
    DIRECTION INPUT ;
    USE SIGNAL ;
    PORT
      LAYER M5 ;
        RECT 330.864 388.608 330.888 388.800 ;
    END
  END bases[738]
  PIN bases[739]
    DIRECTION INPUT ;
    USE SIGNAL ;
    PORT
      LAYER M3 ;
        RECT 331.305 388.608 331.329 388.800 ;
    END
  END bases[739]
  PIN bases[740]
    DIRECTION INPUT ;
    USE SIGNAL ;
    PORT
      LAYER M5 ;
        RECT 331.728 388.608 331.752 388.800 ;
    END
  END bases[740]
  PIN bases[741]
    DIRECTION INPUT ;
    USE SIGNAL ;
    PORT
      LAYER M3 ;
        RECT 332.169 388.608 332.193 388.800 ;
    END
  END bases[741]
  PIN bases[742]
    DIRECTION INPUT ;
    USE SIGNAL ;
    PORT
      LAYER M5 ;
        RECT 332.640 388.608 332.664 388.800 ;
    END
  END bases[742]
  PIN bases[743]
    DIRECTION INPUT ;
    USE SIGNAL ;
    PORT
      LAYER M3 ;
        RECT 333.069 388.608 333.093 388.800 ;
    END
  END bases[743]
  PIN bases[744]
    DIRECTION INPUT ;
    USE SIGNAL ;
    PORT
      LAYER M5 ;
        RECT 333.504 388.608 333.528 388.800 ;
    END
  END bases[744]
  PIN bases[745]
    DIRECTION INPUT ;
    USE SIGNAL ;
    PORT
      LAYER M3 ;
        RECT 333.969 388.608 333.993 388.800 ;
    END
  END bases[745]
  PIN bases[746]
    DIRECTION INPUT ;
    USE SIGNAL ;
    PORT
      LAYER M5 ;
        RECT 334.416 388.608 334.440 388.800 ;
    END
  END bases[746]
  PIN bases[747]
    DIRECTION INPUT ;
    USE SIGNAL ;
    PORT
      LAYER M3 ;
        RECT 334.833 388.608 334.857 388.800 ;
    END
  END bases[747]
  PIN bases[748]
    DIRECTION INPUT ;
    USE SIGNAL ;
    PORT
      LAYER M5 ;
        RECT 335.280 388.608 335.304 388.800 ;
    END
  END bases[748]
  PIN bases[749]
    DIRECTION INPUT ;
    USE SIGNAL ;
    PORT
      LAYER M3 ;
        RECT 335.733 388.608 335.757 388.800 ;
    END
  END bases[749]
  PIN bases[750]
    DIRECTION INPUT ;
    USE SIGNAL ;
    PORT
      LAYER M5 ;
        RECT 336.192 388.608 336.216 388.800 ;
    END
  END bases[750]
  PIN bases[751]
    DIRECTION INPUT ;
    USE SIGNAL ;
    PORT
      LAYER M3 ;
        RECT 336.633 388.608 336.657 388.800 ;
    END
  END bases[751]
  PIN bases[752]
    DIRECTION INPUT ;
    USE SIGNAL ;
    PORT
      LAYER M5 ;
        RECT 337.056 388.608 337.080 388.800 ;
    END
  END bases[752]
  PIN bases[753]
    DIRECTION INPUT ;
    USE SIGNAL ;
    PORT
      LAYER M3 ;
        RECT 337.497 388.608 337.521 388.800 ;
    END
  END bases[753]
  PIN bases[754]
    DIRECTION INPUT ;
    USE SIGNAL ;
    PORT
      LAYER M5 ;
        RECT 337.968 388.608 337.992 388.800 ;
    END
  END bases[754]
  PIN bases[755]
    DIRECTION INPUT ;
    USE SIGNAL ;
    PORT
      LAYER M3 ;
        RECT 338.397 388.608 338.421 388.800 ;
    END
  END bases[755]
  PIN bases[756]
    DIRECTION INPUT ;
    USE SIGNAL ;
    PORT
      LAYER M5 ;
        RECT 338.832 388.608 338.856 388.800 ;
    END
  END bases[756]
  PIN bases[757]
    DIRECTION INPUT ;
    USE SIGNAL ;
    PORT
      LAYER M3 ;
        RECT 339.297 388.608 339.321 388.800 ;
    END
  END bases[757]
  PIN bases[758]
    DIRECTION INPUT ;
    USE SIGNAL ;
    PORT
      LAYER M5 ;
        RECT 339.744 388.608 339.768 388.800 ;
    END
  END bases[758]
  PIN bases[759]
    DIRECTION INPUT ;
    USE SIGNAL ;
    PORT
      LAYER M3 ;
        RECT 340.197 388.608 340.221 388.800 ;
    END
  END bases[759]
  PIN bases[760]
    DIRECTION INPUT ;
    USE SIGNAL ;
    PORT
      LAYER M5 ;
        RECT 340.608 388.608 340.632 388.800 ;
    END
  END bases[760]
  PIN bases[761]
    DIRECTION INPUT ;
    USE SIGNAL ;
    PORT
      LAYER M3 ;
        RECT 341.061 388.608 341.085 388.800 ;
    END
  END bases[761]
  PIN bases[762]
    DIRECTION INPUT ;
    USE SIGNAL ;
    PORT
      LAYER M5 ;
        RECT 341.520 388.608 341.544 388.800 ;
    END
  END bases[762]
  PIN bases[763]
    DIRECTION INPUT ;
    USE SIGNAL ;
    PORT
      LAYER M3 ;
        RECT 341.961 388.608 341.985 388.800 ;
    END
  END bases[763]
  PIN bases[764]
    DIRECTION INPUT ;
    USE SIGNAL ;
    PORT
      LAYER M5 ;
        RECT 342.384 388.608 342.408 388.800 ;
    END
  END bases[764]
  PIN bases[765]
    DIRECTION INPUT ;
    USE SIGNAL ;
    PORT
      LAYER M3 ;
        RECT 342.861 388.608 342.885 388.800 ;
    END
  END bases[765]
  PIN bases[766]
    DIRECTION INPUT ;
    USE SIGNAL ;
    PORT
      LAYER M5 ;
        RECT 343.296 388.608 343.320 388.800 ;
    END
  END bases[766]
  PIN bases[767]
    DIRECTION INPUT ;
    USE SIGNAL ;
    PORT
      LAYER M3 ;
        RECT 343.725 388.608 343.749 388.800 ;
    END
  END bases[767]
  PIN scales[0]
    DIRECTION INPUT ;
    USE SIGNAL ;
    PORT
      LAYER M5 ;
        RECT 344.160 388.608 344.184 388.800 ;
    END
  END scales[0]
  PIN scales[1]
    DIRECTION INPUT ;
    USE SIGNAL ;
    PORT
      LAYER M3 ;
        RECT 344.625 388.608 344.649 388.800 ;
    END
  END scales[1]
  PIN scales[2]
    DIRECTION INPUT ;
    USE SIGNAL ;
    PORT
      LAYER M5 ;
        RECT 345.072 388.608 345.096 388.800 ;
    END
  END scales[2]
  PIN scales[3]
    DIRECTION INPUT ;
    USE SIGNAL ;
    PORT
      LAYER M3 ;
        RECT 345.525 388.608 345.549 388.800 ;
    END
  END scales[3]
  PIN scales[4]
    DIRECTION INPUT ;
    USE SIGNAL ;
    PORT
      LAYER M5 ;
        RECT 345.936 388.608 345.960 388.800 ;
    END
  END scales[4]
  PIN scales[5]
    DIRECTION INPUT ;
    USE SIGNAL ;
    PORT
      LAYER M3 ;
        RECT 346.389 388.608 346.413 388.800 ;
    END
  END scales[5]
  PIN scales[6]
    DIRECTION INPUT ;
    USE SIGNAL ;
    PORT
      LAYER M5 ;
        RECT 346.848 388.608 346.872 388.800 ;
    END
  END scales[6]
  PIN scales[7]
    DIRECTION INPUT ;
    USE SIGNAL ;
    PORT
      LAYER M3 ;
        RECT 347.289 388.608 347.313 388.800 ;
    END
  END scales[7]
  PIN scales[8]
    DIRECTION INPUT ;
    USE SIGNAL ;
    PORT
      LAYER M5 ;
        RECT 347.712 388.608 347.736 388.800 ;
    END
  END scales[8]
  PIN scales[9]
    DIRECTION INPUT ;
    USE SIGNAL ;
    PORT
      LAYER M3 ;
        RECT 348.189 388.608 348.213 388.800 ;
    END
  END scales[9]
  PIN scales[10]
    DIRECTION INPUT ;
    USE SIGNAL ;
    PORT
      LAYER M5 ;
        RECT 348.624 388.608 348.648 388.800 ;
    END
  END scales[10]
  PIN scales[11]
    DIRECTION INPUT ;
    USE SIGNAL ;
    PORT
      LAYER M3 ;
        RECT 349.053 388.608 349.077 388.800 ;
    END
  END scales[11]
  PIN scales[12]
    DIRECTION INPUT ;
    USE SIGNAL ;
    PORT
      LAYER M5 ;
        RECT 349.536 388.608 349.560 388.800 ;
    END
  END scales[12]
  PIN scales[13]
    DIRECTION INPUT ;
    USE SIGNAL ;
    PORT
      LAYER M3 ;
        RECT 349.953 388.608 349.977 388.800 ;
    END
  END scales[13]
  PIN scales[14]
    DIRECTION INPUT ;
    USE SIGNAL ;
    PORT
      LAYER M5 ;
        RECT 350.400 388.608 350.424 388.800 ;
    END
  END scales[14]
  PIN scales[15]
    DIRECTION INPUT ;
    USE SIGNAL ;
    PORT
      LAYER M3 ;
        RECT 350.853 388.608 350.877 388.800 ;
    END
  END scales[15]
  PIN scales[16]
    DIRECTION INPUT ;
    USE SIGNAL ;
    PORT
      LAYER M5 ;
        RECT 351.312 388.608 351.336 388.800 ;
    END
  END scales[16]
  PIN scales[17]
    DIRECTION INPUT ;
    USE SIGNAL ;
    PORT
      LAYER M3 ;
        RECT 351.753 388.608 351.777 388.800 ;
    END
  END scales[17]
  PIN scales[18]
    DIRECTION INPUT ;
    USE SIGNAL ;
    PORT
      LAYER M5 ;
        RECT 352.176 388.608 352.200 388.800 ;
    END
  END scales[18]
  PIN scales[19]
    DIRECTION INPUT ;
    USE SIGNAL ;
    PORT
      LAYER M3 ;
        RECT 352.617 388.608 352.641 388.800 ;
    END
  END scales[19]
  PIN scales[20]
    DIRECTION INPUT ;
    USE SIGNAL ;
    PORT
      LAYER M5 ;
        RECT 353.088 388.608 353.112 388.800 ;
    END
  END scales[20]
  PIN scales[21]
    DIRECTION INPUT ;
    USE SIGNAL ;
    PORT
      LAYER M3 ;
        RECT 353.517 388.608 353.541 388.800 ;
    END
  END scales[21]
  PIN scales[22]
    DIRECTION INPUT ;
    USE SIGNAL ;
    PORT
      LAYER M5 ;
        RECT 353.952 388.608 353.976 388.800 ;
    END
  END scales[22]
  PIN scales[23]
    DIRECTION INPUT ;
    USE SIGNAL ;
    PORT
      LAYER M3 ;
        RECT 354.417 388.608 354.441 388.800 ;
    END
  END scales[23]
  PIN scales[24]
    DIRECTION INPUT ;
    USE SIGNAL ;
    PORT
      LAYER M5 ;
        RECT 354.864 388.608 354.888 388.800 ;
    END
  END scales[24]
  PIN scales[25]
    DIRECTION INPUT ;
    USE SIGNAL ;
    PORT
      LAYER M3 ;
        RECT 355.281 388.608 355.305 388.800 ;
    END
  END scales[25]
  PIN scales[26]
    DIRECTION INPUT ;
    USE SIGNAL ;
    PORT
      LAYER M5 ;
        RECT 355.728 388.608 355.752 388.800 ;
    END
  END scales[26]
  PIN scales[27]
    DIRECTION INPUT ;
    USE SIGNAL ;
    PORT
      LAYER M3 ;
        RECT 356.181 388.608 356.205 388.800 ;
    END
  END scales[27]
  PIN scales[28]
    DIRECTION INPUT ;
    USE SIGNAL ;
    PORT
      LAYER M5 ;
        RECT 356.640 388.608 356.664 388.800 ;
    END
  END scales[28]
  PIN scales[29]
    DIRECTION INPUT ;
    USE SIGNAL ;
    PORT
      LAYER M3 ;
        RECT 357.081 388.608 357.105 388.800 ;
    END
  END scales[29]
  PIN scales[30]
    DIRECTION INPUT ;
    USE SIGNAL ;
    PORT
      LAYER M5 ;
        RECT 357.504 388.608 357.528 388.800 ;
    END
  END scales[30]
  PIN scales[31]
    DIRECTION INPUT ;
    USE SIGNAL ;
    PORT
      LAYER M3 ;
        RECT 357.945 388.608 357.969 388.800 ;
    END
  END scales[31]
  PIN scales[32]
    DIRECTION INPUT ;
    USE SIGNAL ;
    PORT
      LAYER M5 ;
        RECT 358.416 388.608 358.440 388.800 ;
    END
  END scales[32]
  PIN scales[33]
    DIRECTION INPUT ;
    USE SIGNAL ;
    PORT
      LAYER M3 ;
        RECT 358.845 388.608 358.869 388.800 ;
    END
  END scales[33]
  PIN scales[34]
    DIRECTION INPUT ;
    USE SIGNAL ;
    PORT
      LAYER M5 ;
        RECT 359.280 388.608 359.304 388.800 ;
    END
  END scales[34]
  PIN scales[35]
    DIRECTION INPUT ;
    USE SIGNAL ;
    PORT
      LAYER M3 ;
        RECT 359.745 388.608 359.769 388.800 ;
    END
  END scales[35]
  PIN scales[36]
    DIRECTION INPUT ;
    USE SIGNAL ;
    PORT
      LAYER M5 ;
        RECT 360.192 388.608 360.216 388.800 ;
    END
  END scales[36]
  PIN scales[37]
    DIRECTION INPUT ;
    USE SIGNAL ;
    PORT
      LAYER M3 ;
        RECT 360.609 388.608 360.633 388.800 ;
    END
  END scales[37]
  PIN scales[38]
    DIRECTION INPUT ;
    USE SIGNAL ;
    PORT
      LAYER M5 ;
        RECT 361.056 388.608 361.080 388.800 ;
    END
  END scales[38]
  PIN scales[39]
    DIRECTION INPUT ;
    USE SIGNAL ;
    PORT
      LAYER M3 ;
        RECT 361.509 388.608 361.533 388.800 ;
    END
  END scales[39]
  PIN scales[40]
    DIRECTION INPUT ;
    USE SIGNAL ;
    PORT
      LAYER M5 ;
        RECT 361.968 388.608 361.992 388.800 ;
    END
  END scales[40]
  PIN scales[41]
    DIRECTION INPUT ;
    USE SIGNAL ;
    PORT
      LAYER M3 ;
        RECT 362.409 388.608 362.433 388.800 ;
    END
  END scales[41]
  PIN scales[42]
    DIRECTION INPUT ;
    USE SIGNAL ;
    PORT
      LAYER M5 ;
        RECT 362.832 388.608 362.856 388.800 ;
    END
  END scales[42]
  PIN scales[43]
    DIRECTION INPUT ;
    USE SIGNAL ;
    PORT
      LAYER M3 ;
        RECT 363.309 388.608 363.333 388.800 ;
    END
  END scales[43]
  PIN scales[44]
    DIRECTION INPUT ;
    USE SIGNAL ;
    PORT
      LAYER M5 ;
        RECT 363.744 388.608 363.768 388.800 ;
    END
  END scales[44]
  PIN scales[45]
    DIRECTION INPUT ;
    USE SIGNAL ;
    PORT
      LAYER M3 ;
        RECT 364.173 388.608 364.197 388.800 ;
    END
  END scales[45]
  PIN scales[46]
    DIRECTION INPUT ;
    USE SIGNAL ;
    PORT
      LAYER M5 ;
        RECT 364.608 388.608 364.632 388.800 ;
    END
  END scales[46]
  PIN scales[47]
    DIRECTION INPUT ;
    USE SIGNAL ;
    PORT
      LAYER M3 ;
        RECT 365.073 388.608 365.097 388.800 ;
    END
  END scales[47]
  PIN scales[48]
    DIRECTION INPUT ;
    USE SIGNAL ;
    PORT
      LAYER M5 ;
        RECT 365.520 388.608 365.544 388.800 ;
    END
  END scales[48]
  PIN scales[49]
    DIRECTION INPUT ;
    USE SIGNAL ;
    PORT
      LAYER M3 ;
        RECT 365.973 388.608 365.997 388.800 ;
    END
  END scales[49]
  PIN scales[50]
    DIRECTION INPUT ;
    USE SIGNAL ;
    PORT
      LAYER M5 ;
        RECT 366.384 388.608 366.408 388.800 ;
    END
  END scales[50]
  PIN scales[51]
    DIRECTION INPUT ;
    USE SIGNAL ;
    PORT
      LAYER M3 ;
        RECT 366.837 388.608 366.861 388.800 ;
    END
  END scales[51]
  PIN scales[52]
    DIRECTION INPUT ;
    USE SIGNAL ;
    PORT
      LAYER M5 ;
        RECT 367.296 388.608 367.320 388.800 ;
    END
  END scales[52]
  PIN scales[53]
    DIRECTION INPUT ;
    USE SIGNAL ;
    PORT
      LAYER M3 ;
        RECT 367.737 388.608 367.761 388.800 ;
    END
  END scales[53]
  PIN scales[54]
    DIRECTION INPUT ;
    USE SIGNAL ;
    PORT
      LAYER M5 ;
        RECT 368.160 388.608 368.184 388.800 ;
    END
  END scales[54]
  PIN scales[55]
    DIRECTION INPUT ;
    USE SIGNAL ;
    PORT
      LAYER M3 ;
        RECT 368.637 388.608 368.661 388.800 ;
    END
  END scales[55]
  PIN scales[56]
    DIRECTION INPUT ;
    USE SIGNAL ;
    PORT
      LAYER M5 ;
        RECT 369.072 388.608 369.096 388.800 ;
    END
  END scales[56]
  PIN scales[57]
    DIRECTION INPUT ;
    USE SIGNAL ;
    PORT
      LAYER M3 ;
        RECT 369.501 388.608 369.525 388.800 ;
    END
  END scales[57]
  PIN scales[58]
    DIRECTION INPUT ;
    USE SIGNAL ;
    PORT
      LAYER M5 ;
        RECT 369.936 388.608 369.960 388.800 ;
    END
  END scales[58]
  PIN scales[59]
    DIRECTION INPUT ;
    USE SIGNAL ;
    PORT
      LAYER M3 ;
        RECT 370.401 388.608 370.425 388.800 ;
    END
  END scales[59]
  PIN scales[60]
    DIRECTION INPUT ;
    USE SIGNAL ;
    PORT
      LAYER M5 ;
        RECT 370.848 388.608 370.872 388.800 ;
    END
  END scales[60]
  PIN scales[61]
    DIRECTION INPUT ;
    USE SIGNAL ;
    PORT
      LAYER M3 ;
        RECT 371.301 388.608 371.325 388.800 ;
    END
  END scales[61]
  PIN scales[62]
    DIRECTION INPUT ;
    USE SIGNAL ;
    PORT
      LAYER M5 ;
        RECT 371.760 388.608 371.784 388.800 ;
    END
  END scales[62]
  PIN scales[63]
    DIRECTION INPUT ;
    USE SIGNAL ;
    PORT
      LAYER M3 ;
        RECT 372.165 388.608 372.189 388.800 ;
    END
  END scales[63]
  PIN scales[64]
    DIRECTION INPUT ;
    USE SIGNAL ;
    PORT
      LAYER M5 ;
        RECT 372.624 388.608 372.648 388.800 ;
    END
  END scales[64]
  PIN scales[65]
    DIRECTION INPUT ;
    USE SIGNAL ;
    PORT
      LAYER M3 ;
        RECT 373.065 388.608 373.089 388.800 ;
    END
  END scales[65]
  PIN scales[66]
    DIRECTION INPUT ;
    USE SIGNAL ;
    PORT
      LAYER M5 ;
        RECT 373.536 388.608 373.560 388.800 ;
    END
  END scales[66]
  PIN scales[67]
    DIRECTION INPUT ;
    USE SIGNAL ;
    PORT
      LAYER M3 ;
        RECT 373.965 388.608 373.989 388.800 ;
    END
  END scales[67]
  PIN scales[68]
    DIRECTION INPUT ;
    USE SIGNAL ;
    PORT
      LAYER M5 ;
        RECT 374.400 388.608 374.424 388.800 ;
    END
  END scales[68]
  PIN scales[69]
    DIRECTION INPUT ;
    USE SIGNAL ;
    PORT
      LAYER M3 ;
        RECT 374.865 388.608 374.889 388.800 ;
    END
  END scales[69]
  PIN scales[70]
    DIRECTION INPUT ;
    USE SIGNAL ;
    PORT
      LAYER M5 ;
        RECT 375.312 388.608 375.336 388.800 ;
    END
  END scales[70]
  PIN scales[71]
    DIRECTION INPUT ;
    USE SIGNAL ;
    PORT
      LAYER M3 ;
        RECT 375.729 388.608 375.753 388.800 ;
    END
  END scales[71]
  PIN scales[72]
    DIRECTION INPUT ;
    USE SIGNAL ;
    PORT
      LAYER M5 ;
        RECT 376.176 388.608 376.200 388.800 ;
    END
  END scales[72]
  PIN scales[73]
    DIRECTION INPUT ;
    USE SIGNAL ;
    PORT
      LAYER M3 ;
        RECT 376.629 388.608 376.653 388.800 ;
    END
  END scales[73]
  PIN scales[74]
    DIRECTION INPUT ;
    USE SIGNAL ;
    PORT
      LAYER M5 ;
        RECT 377.088 388.608 377.112 388.800 ;
    END
  END scales[74]
  PIN scales[75]
    DIRECTION INPUT ;
    USE SIGNAL ;
    PORT
      LAYER M3 ;
        RECT 377.529 388.608 377.553 388.800 ;
    END
  END scales[75]
  PIN scales[76]
    DIRECTION INPUT ;
    USE SIGNAL ;
    PORT
      LAYER M5 ;
        RECT 377.952 388.608 377.976 388.800 ;
    END
  END scales[76]
  PIN scales[77]
    DIRECTION INPUT ;
    USE SIGNAL ;
    PORT
      LAYER M3 ;
        RECT 378.393 388.608 378.417 388.800 ;
    END
  END scales[77]
  PIN scales[78]
    DIRECTION INPUT ;
    USE SIGNAL ;
    PORT
      LAYER M5 ;
        RECT 378.864 388.608 378.888 388.800 ;
    END
  END scales[78]
  PIN scales[79]
    DIRECTION INPUT ;
    USE SIGNAL ;
    PORT
      LAYER M3 ;
        RECT 379.293 388.608 379.317 388.800 ;
    END
  END scales[79]
  PIN scales[80]
    DIRECTION INPUT ;
    USE SIGNAL ;
    PORT
      LAYER M5 ;
        RECT 379.728 388.608 379.752 388.800 ;
    END
  END scales[80]
  PIN scales[81]
    DIRECTION INPUT ;
    USE SIGNAL ;
    PORT
      LAYER M3 ;
        RECT 380.193 388.608 380.217 388.800 ;
    END
  END scales[81]
  PIN scales[82]
    DIRECTION INPUT ;
    USE SIGNAL ;
    PORT
      LAYER M5 ;
        RECT 380.640 388.608 380.664 388.800 ;
    END
  END scales[82]
  PIN scales[83]
    DIRECTION INPUT ;
    USE SIGNAL ;
    PORT
      LAYER M3 ;
        RECT 381.057 388.608 381.081 388.800 ;
    END
  END scales[83]
  PIN scales[84]
    DIRECTION INPUT ;
    USE SIGNAL ;
    PORT
      LAYER M5 ;
        RECT 381.504 388.608 381.528 388.800 ;
    END
  END scales[84]
  PIN scales[85]
    DIRECTION INPUT ;
    USE SIGNAL ;
    PORT
      LAYER M3 ;
        RECT 381.957 388.608 381.981 388.800 ;
    END
  END scales[85]
  PIN scales[86]
    DIRECTION INPUT ;
    USE SIGNAL ;
    PORT
      LAYER M5 ;
        RECT 382.416 388.608 382.440 388.800 ;
    END
  END scales[86]
  PIN scales[87]
    DIRECTION INPUT ;
    USE SIGNAL ;
    PORT
      LAYER M3 ;
        RECT 382.857 388.608 382.881 388.800 ;
    END
  END scales[87]
  PIN scales[88]
    DIRECTION INPUT ;
    USE SIGNAL ;
    PORT
      LAYER M5 ;
        RECT 383.280 388.608 383.304 388.800 ;
    END
  END scales[88]
  PIN scales[89]
    DIRECTION INPUT ;
    USE SIGNAL ;
    PORT
      LAYER M3 ;
        RECT 383.721 388.608 383.745 388.800 ;
    END
  END scales[89]
  PIN scales[90]
    DIRECTION INPUT ;
    USE SIGNAL ;
    PORT
      LAYER M5 ;
        RECT 384.192 388.608 384.216 388.800 ;
    END
  END scales[90]
  PIN scales[91]
    DIRECTION INPUT ;
    USE SIGNAL ;
    PORT
      LAYER M3 ;
        RECT 384.621 388.608 384.645 388.800 ;
    END
  END scales[91]
  PIN scales[92]
    DIRECTION INPUT ;
    USE SIGNAL ;
    PORT
      LAYER M5 ;
        RECT 385.056 388.608 385.080 388.800 ;
    END
  END scales[92]
  PIN scales[93]
    DIRECTION INPUT ;
    USE SIGNAL ;
    PORT
      LAYER M3 ;
        RECT 385.521 388.608 385.545 388.800 ;
    END
  END scales[93]
  PIN scales[94]
    DIRECTION INPUT ;
    USE SIGNAL ;
    PORT
      LAYER M5 ;
        RECT 385.968 388.608 385.992 388.800 ;
    END
  END scales[94]
  PIN scales[95]
    DIRECTION INPUT ;
    USE SIGNAL ;
    PORT
      LAYER M3 ;
        RECT 386.421 388.608 386.445 388.800 ;
    END
  END scales[95]
  PIN result_v
    DIRECTION OUTPUT ;
    USE SIGNAL ;
    PORT
      LAYER M4 ;
        RECT 388.608 2.400 388.800 2.424 ;
    END
  END result_v
  PIN result[0]
    DIRECTION OUTPUT ;
    USE SIGNAL ;
    PORT
      LAYER M4 ;
        RECT 388.608 2.880 388.800 2.904 ;
    END
  END result[0]
  PIN result[1]
    DIRECTION OUTPUT ;
    USE SIGNAL ;
    PORT
      LAYER M4 ;
        RECT 388.608 3.408 388.800 3.432 ;
    END
  END result[1]
  PIN result[2]
    DIRECTION OUTPUT ;
    USE SIGNAL ;
    PORT
      LAYER M4 ;
        RECT 388.608 3.888 388.800 3.912 ;
    END
  END result[2]
  PIN result[3]
    DIRECTION OUTPUT ;
    USE SIGNAL ;
    PORT
      LAYER M4 ;
        RECT 388.608 4.416 388.800 4.440 ;
    END
  END result[3]
  PIN result[4]
    DIRECTION OUTPUT ;
    USE SIGNAL ;
    PORT
      LAYER M4 ;
        RECT 388.608 4.896 388.800 4.920 ;
    END
  END result[4]
  PIN result[5]
    DIRECTION OUTPUT ;
    USE SIGNAL ;
    PORT
      LAYER M4 ;
        RECT 388.608 5.376 388.800 5.400 ;
    END
  END result[5]
  PIN result[6]
    DIRECTION OUTPUT ;
    USE SIGNAL ;
    PORT
      LAYER M4 ;
        RECT 388.608 5.904 388.800 5.928 ;
    END
  END result[6]
  PIN result[7]
    DIRECTION OUTPUT ;
    USE SIGNAL ;
    PORT
      LAYER M4 ;
        RECT 388.608 6.384 388.800 6.408 ;
    END
  END result[7]
  PIN result[8]
    DIRECTION OUTPUT ;
    USE SIGNAL ;
    PORT
      LAYER M4 ;
        RECT 388.608 6.912 388.800 6.936 ;
    END
  END result[8]
  PIN result[9]
    DIRECTION OUTPUT ;
    USE SIGNAL ;
    PORT
      LAYER M4 ;
        RECT 388.608 7.392 388.800 7.416 ;
    END
  END result[9]
  PIN result[10]
    DIRECTION OUTPUT ;
    USE SIGNAL ;
    PORT
      LAYER M4 ;
        RECT 388.608 7.872 388.800 7.896 ;
    END
  END result[10]
  PIN result[11]
    DIRECTION OUTPUT ;
    USE SIGNAL ;
    PORT
      LAYER M4 ;
        RECT 388.608 8.400 388.800 8.424 ;
    END
  END result[11]
  PIN result[12]
    DIRECTION OUTPUT ;
    USE SIGNAL ;
    PORT
      LAYER M4 ;
        RECT 388.608 8.880 388.800 8.904 ;
    END
  END result[12]
  PIN result[13]
    DIRECTION OUTPUT ;
    USE SIGNAL ;
    PORT
      LAYER M4 ;
        RECT 388.608 9.408 388.800 9.432 ;
    END
  END result[13]
  PIN result[14]
    DIRECTION OUTPUT ;
    USE SIGNAL ;
    PORT
      LAYER M4 ;
        RECT 388.608 9.888 388.800 9.912 ;
    END
  END result[14]
  PIN result[15]
    DIRECTION OUTPUT ;
    USE SIGNAL ;
    PORT
      LAYER M4 ;
        RECT 388.608 10.368 388.800 10.392 ;
    END
  END result[15]
  PIN result[16]
    DIRECTION OUTPUT ;
    USE SIGNAL ;
    PORT
      LAYER M4 ;
        RECT 388.608 10.896 388.800 10.920 ;
    END
  END result[16]
  PIN result[17]
    DIRECTION OUTPUT ;
    USE SIGNAL ;
    PORT
      LAYER M4 ;
        RECT 388.608 11.376 388.800 11.400 ;
    END
  END result[17]
  PIN result[18]
    DIRECTION OUTPUT ;
    USE SIGNAL ;
    PORT
      LAYER M4 ;
        RECT 388.608 11.904 388.800 11.928 ;
    END
  END result[18]
  PIN result[19]
    DIRECTION OUTPUT ;
    USE SIGNAL ;
    PORT
      LAYER M4 ;
        RECT 388.608 12.384 388.800 12.408 ;
    END
  END result[19]
  PIN result[20]
    DIRECTION OUTPUT ;
    USE SIGNAL ;
    PORT
      LAYER M4 ;
        RECT 388.608 12.864 388.800 12.888 ;
    END
  END result[20]
  PIN result[21]
    DIRECTION OUTPUT ;
    USE SIGNAL ;
    PORT
      LAYER M4 ;
        RECT 388.608 13.392 388.800 13.416 ;
    END
  END result[21]
  PIN result[22]
    DIRECTION OUTPUT ;
    USE SIGNAL ;
    PORT
      LAYER M4 ;
        RECT 388.608 13.872 388.800 13.896 ;
    END
  END result[22]
  PIN result[23]
    DIRECTION OUTPUT ;
    USE SIGNAL ;
    PORT
      LAYER M4 ;
        RECT 388.608 14.400 388.800 14.424 ;
    END
  END result[23]
  PIN result[24]
    DIRECTION OUTPUT ;
    USE SIGNAL ;
    PORT
      LAYER M4 ;
        RECT 388.608 14.880 388.800 14.904 ;
    END
  END result[24]
  PIN result[25]
    DIRECTION OUTPUT ;
    USE SIGNAL ;
    PORT
      LAYER M4 ;
        RECT 388.608 15.360 388.800 15.384 ;
    END
  END result[25]
  PIN result[26]
    DIRECTION OUTPUT ;
    USE SIGNAL ;
    PORT
      LAYER M4 ;
        RECT 388.608 15.888 388.800 15.912 ;
    END
  END result[26]
  PIN result[27]
    DIRECTION OUTPUT ;
    USE SIGNAL ;
    PORT
      LAYER M4 ;
        RECT 388.608 16.368 388.800 16.392 ;
    END
  END result[27]
  PIN result[28]
    DIRECTION OUTPUT ;
    USE SIGNAL ;
    PORT
      LAYER M4 ;
        RECT 388.608 16.896 388.800 16.920 ;
    END
  END result[28]
  PIN result[29]
    DIRECTION OUTPUT ;
    USE SIGNAL ;
    PORT
      LAYER M4 ;
        RECT 388.608 17.376 388.800 17.400 ;
    END
  END result[29]
  PIN result[30]
    DIRECTION OUTPUT ;
    USE SIGNAL ;
    PORT
      LAYER M4 ;
        RECT 388.608 17.856 388.800 17.880 ;
    END
  END result[30]
  PIN result[31]
    DIRECTION OUTPUT ;
    USE SIGNAL ;
    PORT
      LAYER M4 ;
        RECT 388.608 18.384 388.800 18.408 ;
    END
  END result[31]
  PIN result[32]
    DIRECTION OUTPUT ;
    USE SIGNAL ;
    PORT
      LAYER M4 ;
        RECT 388.608 18.864 388.800 18.888 ;
    END
  END result[32]
  PIN result[33]
    DIRECTION OUTPUT ;
    USE SIGNAL ;
    PORT
      LAYER M4 ;
        RECT 388.608 19.392 388.800 19.416 ;
    END
  END result[33]
  PIN result[34]
    DIRECTION OUTPUT ;
    USE SIGNAL ;
    PORT
      LAYER M4 ;
        RECT 388.608 19.872 388.800 19.896 ;
    END
  END result[34]
  PIN result[35]
    DIRECTION OUTPUT ;
    USE SIGNAL ;
    PORT
      LAYER M4 ;
        RECT 388.608 20.352 388.800 20.376 ;
    END
  END result[35]
  PIN result[36]
    DIRECTION OUTPUT ;
    USE SIGNAL ;
    PORT
      LAYER M4 ;
        RECT 388.608 20.880 388.800 20.904 ;
    END
  END result[36]
  PIN result[37]
    DIRECTION OUTPUT ;
    USE SIGNAL ;
    PORT
      LAYER M4 ;
        RECT 388.608 21.360 388.800 21.384 ;
    END
  END result[37]
  PIN result[38]
    DIRECTION OUTPUT ;
    USE SIGNAL ;
    PORT
      LAYER M4 ;
        RECT 388.608 21.888 388.800 21.912 ;
    END
  END result[38]
  PIN result[39]
    DIRECTION OUTPUT ;
    USE SIGNAL ;
    PORT
      LAYER M4 ;
        RECT 388.608 22.368 388.800 22.392 ;
    END
  END result[39]
  PIN result[40]
    DIRECTION OUTPUT ;
    USE SIGNAL ;
    PORT
      LAYER M4 ;
        RECT 388.608 22.848 388.800 22.872 ;
    END
  END result[40]
  PIN result[41]
    DIRECTION OUTPUT ;
    USE SIGNAL ;
    PORT
      LAYER M4 ;
        RECT 388.608 23.376 388.800 23.400 ;
    END
  END result[41]
  PIN result[42]
    DIRECTION OUTPUT ;
    USE SIGNAL ;
    PORT
      LAYER M4 ;
        RECT 388.608 23.856 388.800 23.880 ;
    END
  END result[42]
  PIN result[43]
    DIRECTION OUTPUT ;
    USE SIGNAL ;
    PORT
      LAYER M4 ;
        RECT 388.608 24.384 388.800 24.408 ;
    END
  END result[43]
  PIN result[44]
    DIRECTION OUTPUT ;
    USE SIGNAL ;
    PORT
      LAYER M4 ;
        RECT 388.608 24.864 388.800 24.888 ;
    END
  END result[44]
  PIN result[45]
    DIRECTION OUTPUT ;
    USE SIGNAL ;
    PORT
      LAYER M4 ;
        RECT 388.608 25.344 388.800 25.368 ;
    END
  END result[45]
  PIN result[46]
    DIRECTION OUTPUT ;
    USE SIGNAL ;
    PORT
      LAYER M4 ;
        RECT 388.608 25.872 388.800 25.896 ;
    END
  END result[46]
  PIN result[47]
    DIRECTION OUTPUT ;
    USE SIGNAL ;
    PORT
      LAYER M4 ;
        RECT 388.608 26.352 388.800 26.376 ;
    END
  END result[47]
  PIN result[48]
    DIRECTION OUTPUT ;
    USE SIGNAL ;
    PORT
      LAYER M4 ;
        RECT 388.608 26.880 388.800 26.904 ;
    END
  END result[48]
  PIN result[49]
    DIRECTION OUTPUT ;
    USE SIGNAL ;
    PORT
      LAYER M4 ;
        RECT 388.608 27.360 388.800 27.384 ;
    END
  END result[49]
  PIN result[50]
    DIRECTION OUTPUT ;
    USE SIGNAL ;
    PORT
      LAYER M4 ;
        RECT 388.608 27.840 388.800 27.864 ;
    END
  END result[50]
  PIN result[51]
    DIRECTION OUTPUT ;
    USE SIGNAL ;
    PORT
      LAYER M4 ;
        RECT 388.608 28.368 388.800 28.392 ;
    END
  END result[51]
  PIN result[52]
    DIRECTION OUTPUT ;
    USE SIGNAL ;
    PORT
      LAYER M4 ;
        RECT 388.608 28.848 388.800 28.872 ;
    END
  END result[52]
  PIN result[53]
    DIRECTION OUTPUT ;
    USE SIGNAL ;
    PORT
      LAYER M4 ;
        RECT 388.608 29.376 388.800 29.400 ;
    END
  END result[53]
  PIN result[54]
    DIRECTION OUTPUT ;
    USE SIGNAL ;
    PORT
      LAYER M4 ;
        RECT 388.608 29.856 388.800 29.880 ;
    END
  END result[54]
  PIN result[55]
    DIRECTION OUTPUT ;
    USE SIGNAL ;
    PORT
      LAYER M4 ;
        RECT 388.608 30.336 388.800 30.360 ;
    END
  END result[55]
  PIN result[56]
    DIRECTION OUTPUT ;
    USE SIGNAL ;
    PORT
      LAYER M4 ;
        RECT 388.608 30.864 388.800 30.888 ;
    END
  END result[56]
  PIN result[57]
    DIRECTION OUTPUT ;
    USE SIGNAL ;
    PORT
      LAYER M4 ;
        RECT 388.608 31.344 388.800 31.368 ;
    END
  END result[57]
  PIN result[58]
    DIRECTION OUTPUT ;
    USE SIGNAL ;
    PORT
      LAYER M4 ;
        RECT 388.608 31.872 388.800 31.896 ;
    END
  END result[58]
  PIN result[59]
    DIRECTION OUTPUT ;
    USE SIGNAL ;
    PORT
      LAYER M4 ;
        RECT 388.608 32.352 388.800 32.376 ;
    END
  END result[59]
  PIN result[60]
    DIRECTION OUTPUT ;
    USE SIGNAL ;
    PORT
      LAYER M4 ;
        RECT 388.608 32.880 388.800 32.904 ;
    END
  END result[60]
  PIN result[61]
    DIRECTION OUTPUT ;
    USE SIGNAL ;
    PORT
      LAYER M4 ;
        RECT 388.608 33.360 388.800 33.384 ;
    END
  END result[61]
  PIN result[62]
    DIRECTION OUTPUT ;
    USE SIGNAL ;
    PORT
      LAYER M4 ;
        RECT 388.608 33.840 388.800 33.864 ;
    END
  END result[62]
  PIN result[63]
    DIRECTION OUTPUT ;
    USE SIGNAL ;
    PORT
      LAYER M4 ;
        RECT 388.608 34.368 388.800 34.392 ;
    END
  END result[63]
  PIN result[64]
    DIRECTION OUTPUT ;
    USE SIGNAL ;
    PORT
      LAYER M4 ;
        RECT 388.608 34.848 388.800 34.872 ;
    END
  END result[64]
  PIN result[65]
    DIRECTION OUTPUT ;
    USE SIGNAL ;
    PORT
      LAYER M4 ;
        RECT 388.608 35.376 388.800 35.400 ;
    END
  END result[65]
  PIN result[66]
    DIRECTION OUTPUT ;
    USE SIGNAL ;
    PORT
      LAYER M4 ;
        RECT 388.608 35.856 388.800 35.880 ;
    END
  END result[66]
  PIN result[67]
    DIRECTION OUTPUT ;
    USE SIGNAL ;
    PORT
      LAYER M4 ;
        RECT 388.608 36.336 388.800 36.360 ;
    END
  END result[67]
  PIN result[68]
    DIRECTION OUTPUT ;
    USE SIGNAL ;
    PORT
      LAYER M4 ;
        RECT 388.608 36.864 388.800 36.888 ;
    END
  END result[68]
  PIN result[69]
    DIRECTION OUTPUT ;
    USE SIGNAL ;
    PORT
      LAYER M4 ;
        RECT 388.608 37.344 388.800 37.368 ;
    END
  END result[69]
  PIN result[70]
    DIRECTION OUTPUT ;
    USE SIGNAL ;
    PORT
      LAYER M4 ;
        RECT 388.608 37.872 388.800 37.896 ;
    END
  END result[70]
  PIN result[71]
    DIRECTION OUTPUT ;
    USE SIGNAL ;
    PORT
      LAYER M4 ;
        RECT 388.608 38.352 388.800 38.376 ;
    END
  END result[71]
  PIN result[72]
    DIRECTION OUTPUT ;
    USE SIGNAL ;
    PORT
      LAYER M4 ;
        RECT 388.608 38.832 388.800 38.856 ;
    END
  END result[72]
  PIN result[73]
    DIRECTION OUTPUT ;
    USE SIGNAL ;
    PORT
      LAYER M4 ;
        RECT 388.608 39.360 388.800 39.384 ;
    END
  END result[73]
  PIN result[74]
    DIRECTION OUTPUT ;
    USE SIGNAL ;
    PORT
      LAYER M4 ;
        RECT 388.608 39.840 388.800 39.864 ;
    END
  END result[74]
  PIN result[75]
    DIRECTION OUTPUT ;
    USE SIGNAL ;
    PORT
      LAYER M4 ;
        RECT 388.608 40.368 388.800 40.392 ;
    END
  END result[75]
  PIN result[76]
    DIRECTION OUTPUT ;
    USE SIGNAL ;
    PORT
      LAYER M4 ;
        RECT 388.608 40.848 388.800 40.872 ;
    END
  END result[76]
  PIN result[77]
    DIRECTION OUTPUT ;
    USE SIGNAL ;
    PORT
      LAYER M4 ;
        RECT 388.608 41.328 388.800 41.352 ;
    END
  END result[77]
  PIN result[78]
    DIRECTION OUTPUT ;
    USE SIGNAL ;
    PORT
      LAYER M4 ;
        RECT 388.608 41.856 388.800 41.880 ;
    END
  END result[78]
  PIN result[79]
    DIRECTION OUTPUT ;
    USE SIGNAL ;
    PORT
      LAYER M4 ;
        RECT 388.608 42.336 388.800 42.360 ;
    END
  END result[79]
  PIN result[80]
    DIRECTION OUTPUT ;
    USE SIGNAL ;
    PORT
      LAYER M4 ;
        RECT 388.608 42.864 388.800 42.888 ;
    END
  END result[80]
  PIN result[81]
    DIRECTION OUTPUT ;
    USE SIGNAL ;
    PORT
      LAYER M4 ;
        RECT 388.608 43.344 388.800 43.368 ;
    END
  END result[81]
  PIN result[82]
    DIRECTION OUTPUT ;
    USE SIGNAL ;
    PORT
      LAYER M4 ;
        RECT 388.608 43.824 388.800 43.848 ;
    END
  END result[82]
  PIN result[83]
    DIRECTION OUTPUT ;
    USE SIGNAL ;
    PORT
      LAYER M4 ;
        RECT 388.608 44.352 388.800 44.376 ;
    END
  END result[83]
  PIN result[84]
    DIRECTION OUTPUT ;
    USE SIGNAL ;
    PORT
      LAYER M4 ;
        RECT 388.608 44.832 388.800 44.856 ;
    END
  END result[84]
  PIN result[85]
    DIRECTION OUTPUT ;
    USE SIGNAL ;
    PORT
      LAYER M4 ;
        RECT 388.608 45.360 388.800 45.384 ;
    END
  END result[85]
  PIN result[86]
    DIRECTION OUTPUT ;
    USE SIGNAL ;
    PORT
      LAYER M4 ;
        RECT 388.608 45.840 388.800 45.864 ;
    END
  END result[86]
  PIN result[87]
    DIRECTION OUTPUT ;
    USE SIGNAL ;
    PORT
      LAYER M4 ;
        RECT 388.608 46.320 388.800 46.344 ;
    END
  END result[87]
  PIN result[88]
    DIRECTION OUTPUT ;
    USE SIGNAL ;
    PORT
      LAYER M4 ;
        RECT 388.608 46.848 388.800 46.872 ;
    END
  END result[88]
  PIN result[89]
    DIRECTION OUTPUT ;
    USE SIGNAL ;
    PORT
      LAYER M4 ;
        RECT 388.608 47.328 388.800 47.352 ;
    END
  END result[89]
  PIN result[90]
    DIRECTION OUTPUT ;
    USE SIGNAL ;
    PORT
      LAYER M4 ;
        RECT 388.608 47.856 388.800 47.880 ;
    END
  END result[90]
  PIN result[91]
    DIRECTION OUTPUT ;
    USE SIGNAL ;
    PORT
      LAYER M4 ;
        RECT 388.608 48.336 388.800 48.360 ;
    END
  END result[91]
  PIN result[92]
    DIRECTION OUTPUT ;
    USE SIGNAL ;
    PORT
      LAYER M4 ;
        RECT 388.608 48.816 388.800 48.840 ;
    END
  END result[92]
  PIN result[93]
    DIRECTION OUTPUT ;
    USE SIGNAL ;
    PORT
      LAYER M4 ;
        RECT 388.608 49.344 388.800 49.368 ;
    END
  END result[93]
  PIN result[94]
    DIRECTION OUTPUT ;
    USE SIGNAL ;
    PORT
      LAYER M4 ;
        RECT 388.608 49.824 388.800 49.848 ;
    END
  END result[94]
  PIN result[95]
    DIRECTION OUTPUT ;
    USE SIGNAL ;
    PORT
      LAYER M4 ;
        RECT 388.608 50.352 388.800 50.376 ;
    END
  END result[95]
  PIN result[96]
    DIRECTION OUTPUT ;
    USE SIGNAL ;
    PORT
      LAYER M4 ;
        RECT 388.608 50.832 388.800 50.856 ;
    END
  END result[96]
  PIN result[97]
    DIRECTION OUTPUT ;
    USE SIGNAL ;
    PORT
      LAYER M4 ;
        RECT 388.608 51.312 388.800 51.336 ;
    END
  END result[97]
  PIN result[98]
    DIRECTION OUTPUT ;
    USE SIGNAL ;
    PORT
      LAYER M4 ;
        RECT 388.608 51.840 388.800 51.864 ;
    END
  END result[98]
  PIN result[99]
    DIRECTION OUTPUT ;
    USE SIGNAL ;
    PORT
      LAYER M4 ;
        RECT 388.608 52.320 388.800 52.344 ;
    END
  END result[99]
  PIN result[100]
    DIRECTION OUTPUT ;
    USE SIGNAL ;
    PORT
      LAYER M4 ;
        RECT 388.608 52.848 388.800 52.872 ;
    END
  END result[100]
  PIN result[101]
    DIRECTION OUTPUT ;
    USE SIGNAL ;
    PORT
      LAYER M4 ;
        RECT 388.608 53.328 388.800 53.352 ;
    END
  END result[101]
  PIN result[102]
    DIRECTION OUTPUT ;
    USE SIGNAL ;
    PORT
      LAYER M4 ;
        RECT 388.608 53.808 388.800 53.832 ;
    END
  END result[102]
  PIN result[103]
    DIRECTION OUTPUT ;
    USE SIGNAL ;
    PORT
      LAYER M4 ;
        RECT 388.608 54.336 388.800 54.360 ;
    END
  END result[103]
  PIN result[104]
    DIRECTION OUTPUT ;
    USE SIGNAL ;
    PORT
      LAYER M4 ;
        RECT 388.608 54.816 388.800 54.840 ;
    END
  END result[104]
  PIN result[105]
    DIRECTION OUTPUT ;
    USE SIGNAL ;
    PORT
      LAYER M4 ;
        RECT 388.608 55.344 388.800 55.368 ;
    END
  END result[105]
  PIN result[106]
    DIRECTION OUTPUT ;
    USE SIGNAL ;
    PORT
      LAYER M4 ;
        RECT 388.608 55.824 388.800 55.848 ;
    END
  END result[106]
  PIN result[107]
    DIRECTION OUTPUT ;
    USE SIGNAL ;
    PORT
      LAYER M4 ;
        RECT 388.608 56.304 388.800 56.328 ;
    END
  END result[107]
  PIN result[108]
    DIRECTION OUTPUT ;
    USE SIGNAL ;
    PORT
      LAYER M4 ;
        RECT 388.608 56.832 388.800 56.856 ;
    END
  END result[108]
  PIN result[109]
    DIRECTION OUTPUT ;
    USE SIGNAL ;
    PORT
      LAYER M4 ;
        RECT 388.608 57.312 388.800 57.336 ;
    END
  END result[109]
  PIN result[110]
    DIRECTION OUTPUT ;
    USE SIGNAL ;
    PORT
      LAYER M4 ;
        RECT 388.608 57.840 388.800 57.864 ;
    END
  END result[110]
  PIN result[111]
    DIRECTION OUTPUT ;
    USE SIGNAL ;
    PORT
      LAYER M4 ;
        RECT 388.608 58.320 388.800 58.344 ;
    END
  END result[111]
  PIN result[112]
    DIRECTION OUTPUT ;
    USE SIGNAL ;
    PORT
      LAYER M4 ;
        RECT 388.608 58.800 388.800 58.824 ;
    END
  END result[112]
  PIN result[113]
    DIRECTION OUTPUT ;
    USE SIGNAL ;
    PORT
      LAYER M4 ;
        RECT 388.608 59.328 388.800 59.352 ;
    END
  END result[113]
  PIN result[114]
    DIRECTION OUTPUT ;
    USE SIGNAL ;
    PORT
      LAYER M4 ;
        RECT 388.608 59.808 388.800 59.832 ;
    END
  END result[114]
  PIN result[115]
    DIRECTION OUTPUT ;
    USE SIGNAL ;
    PORT
      LAYER M4 ;
        RECT 388.608 60.336 388.800 60.360 ;
    END
  END result[115]
  PIN result[116]
    DIRECTION OUTPUT ;
    USE SIGNAL ;
    PORT
      LAYER M4 ;
        RECT 388.608 60.816 388.800 60.840 ;
    END
  END result[116]
  PIN result[117]
    DIRECTION OUTPUT ;
    USE SIGNAL ;
    PORT
      LAYER M4 ;
        RECT 388.608 61.296 388.800 61.320 ;
    END
  END result[117]
  PIN result[118]
    DIRECTION OUTPUT ;
    USE SIGNAL ;
    PORT
      LAYER M4 ;
        RECT 388.608 61.824 388.800 61.848 ;
    END
  END result[118]
  PIN result[119]
    DIRECTION OUTPUT ;
    USE SIGNAL ;
    PORT
      LAYER M4 ;
        RECT 388.608 62.304 388.800 62.328 ;
    END
  END result[119]
  PIN result[120]
    DIRECTION OUTPUT ;
    USE SIGNAL ;
    PORT
      LAYER M4 ;
        RECT 388.608 62.832 388.800 62.856 ;
    END
  END result[120]
  PIN result[121]
    DIRECTION OUTPUT ;
    USE SIGNAL ;
    PORT
      LAYER M4 ;
        RECT 388.608 63.312 388.800 63.336 ;
    END
  END result[121]
  PIN result[122]
    DIRECTION OUTPUT ;
    USE SIGNAL ;
    PORT
      LAYER M4 ;
        RECT 388.608 63.792 388.800 63.816 ;
    END
  END result[122]
  PIN result[123]
    DIRECTION OUTPUT ;
    USE SIGNAL ;
    PORT
      LAYER M4 ;
        RECT 388.608 64.320 388.800 64.344 ;
    END
  END result[123]
  PIN result[124]
    DIRECTION OUTPUT ;
    USE SIGNAL ;
    PORT
      LAYER M4 ;
        RECT 388.608 64.800 388.800 64.824 ;
    END
  END result[124]
  PIN result[125]
    DIRECTION OUTPUT ;
    USE SIGNAL ;
    PORT
      LAYER M4 ;
        RECT 388.608 65.328 388.800 65.352 ;
    END
  END result[125]
  PIN result[126]
    DIRECTION OUTPUT ;
    USE SIGNAL ;
    PORT
      LAYER M4 ;
        RECT 388.608 65.808 388.800 65.832 ;
    END
  END result[126]
  PIN result[127]
    DIRECTION OUTPUT ;
    USE SIGNAL ;
    PORT
      LAYER M4 ;
        RECT 388.608 66.288 388.800 66.312 ;
    END
  END result[127]
  PIN result[128]
    DIRECTION OUTPUT ;
    USE SIGNAL ;
    PORT
      LAYER M4 ;
        RECT 388.608 66.816 388.800 66.840 ;
    END
  END result[128]
  PIN result[129]
    DIRECTION OUTPUT ;
    USE SIGNAL ;
    PORT
      LAYER M4 ;
        RECT 388.608 67.296 388.800 67.320 ;
    END
  END result[129]
  PIN result[130]
    DIRECTION OUTPUT ;
    USE SIGNAL ;
    PORT
      LAYER M4 ;
        RECT 388.608 67.824 388.800 67.848 ;
    END
  END result[130]
  PIN result[131]
    DIRECTION OUTPUT ;
    USE SIGNAL ;
    PORT
      LAYER M4 ;
        RECT 388.608 68.304 388.800 68.328 ;
    END
  END result[131]
  PIN result[132]
    DIRECTION OUTPUT ;
    USE SIGNAL ;
    PORT
      LAYER M4 ;
        RECT 388.608 68.784 388.800 68.808 ;
    END
  END result[132]
  PIN result[133]
    DIRECTION OUTPUT ;
    USE SIGNAL ;
    PORT
      LAYER M4 ;
        RECT 388.608 69.312 388.800 69.336 ;
    END
  END result[133]
  PIN result[134]
    DIRECTION OUTPUT ;
    USE SIGNAL ;
    PORT
      LAYER M4 ;
        RECT 388.608 69.792 388.800 69.816 ;
    END
  END result[134]
  PIN result[135]
    DIRECTION OUTPUT ;
    USE SIGNAL ;
    PORT
      LAYER M4 ;
        RECT 388.608 70.320 388.800 70.344 ;
    END
  END result[135]
  PIN result[136]
    DIRECTION OUTPUT ;
    USE SIGNAL ;
    PORT
      LAYER M4 ;
        RECT 388.608 70.800 388.800 70.824 ;
    END
  END result[136]
  PIN result[137]
    DIRECTION OUTPUT ;
    USE SIGNAL ;
    PORT
      LAYER M4 ;
        RECT 388.608 71.328 388.800 71.352 ;
    END
  END result[137]
  PIN result[138]
    DIRECTION OUTPUT ;
    USE SIGNAL ;
    PORT
      LAYER M4 ;
        RECT 388.608 71.808 388.800 71.832 ;
    END
  END result[138]
  PIN result[139]
    DIRECTION OUTPUT ;
    USE SIGNAL ;
    PORT
      LAYER M4 ;
        RECT 388.608 72.288 388.800 72.312 ;
    END
  END result[139]
  PIN result[140]
    DIRECTION OUTPUT ;
    USE SIGNAL ;
    PORT
      LAYER M4 ;
        RECT 388.608 72.816 388.800 72.840 ;
    END
  END result[140]
  PIN result[141]
    DIRECTION OUTPUT ;
    USE SIGNAL ;
    PORT
      LAYER M4 ;
        RECT 388.608 73.296 388.800 73.320 ;
    END
  END result[141]
  PIN result[142]
    DIRECTION OUTPUT ;
    USE SIGNAL ;
    PORT
      LAYER M4 ;
        RECT 388.608 73.824 388.800 73.848 ;
    END
  END result[142]
  PIN result[143]
    DIRECTION OUTPUT ;
    USE SIGNAL ;
    PORT
      LAYER M4 ;
        RECT 388.608 74.304 388.800 74.328 ;
    END
  END result[143]
  PIN result[144]
    DIRECTION OUTPUT ;
    USE SIGNAL ;
    PORT
      LAYER M4 ;
        RECT 388.608 74.784 388.800 74.808 ;
    END
  END result[144]
  PIN result[145]
    DIRECTION OUTPUT ;
    USE SIGNAL ;
    PORT
      LAYER M4 ;
        RECT 388.608 75.312 388.800 75.336 ;
    END
  END result[145]
  PIN result[146]
    DIRECTION OUTPUT ;
    USE SIGNAL ;
    PORT
      LAYER M4 ;
        RECT 388.608 75.792 388.800 75.816 ;
    END
  END result[146]
  PIN result[147]
    DIRECTION OUTPUT ;
    USE SIGNAL ;
    PORT
      LAYER M4 ;
        RECT 388.608 76.320 388.800 76.344 ;
    END
  END result[147]
  PIN result[148]
    DIRECTION OUTPUT ;
    USE SIGNAL ;
    PORT
      LAYER M4 ;
        RECT 388.608 76.800 388.800 76.824 ;
    END
  END result[148]
  PIN result[149]
    DIRECTION OUTPUT ;
    USE SIGNAL ;
    PORT
      LAYER M4 ;
        RECT 388.608 77.280 388.800 77.304 ;
    END
  END result[149]
  PIN result[150]
    DIRECTION OUTPUT ;
    USE SIGNAL ;
    PORT
      LAYER M4 ;
        RECT 388.608 77.808 388.800 77.832 ;
    END
  END result[150]
  PIN result[151]
    DIRECTION OUTPUT ;
    USE SIGNAL ;
    PORT
      LAYER M4 ;
        RECT 388.608 78.288 388.800 78.312 ;
    END
  END result[151]
  PIN result[152]
    DIRECTION OUTPUT ;
    USE SIGNAL ;
    PORT
      LAYER M4 ;
        RECT 388.608 78.816 388.800 78.840 ;
    END
  END result[152]
  PIN result[153]
    DIRECTION OUTPUT ;
    USE SIGNAL ;
    PORT
      LAYER M4 ;
        RECT 388.608 79.296 388.800 79.320 ;
    END
  END result[153]
  PIN result[154]
    DIRECTION OUTPUT ;
    USE SIGNAL ;
    PORT
      LAYER M4 ;
        RECT 388.608 79.776 388.800 79.800 ;
    END
  END result[154]
  PIN result[155]
    DIRECTION OUTPUT ;
    USE SIGNAL ;
    PORT
      LAYER M4 ;
        RECT 388.608 80.304 388.800 80.328 ;
    END
  END result[155]
  PIN result[156]
    DIRECTION OUTPUT ;
    USE SIGNAL ;
    PORT
      LAYER M4 ;
        RECT 388.608 80.784 388.800 80.808 ;
    END
  END result[156]
  PIN result[157]
    DIRECTION OUTPUT ;
    USE SIGNAL ;
    PORT
      LAYER M4 ;
        RECT 388.608 81.312 388.800 81.336 ;
    END
  END result[157]
  PIN result[158]
    DIRECTION OUTPUT ;
    USE SIGNAL ;
    PORT
      LAYER M4 ;
        RECT 388.608 81.792 388.800 81.816 ;
    END
  END result[158]
  PIN result[159]
    DIRECTION OUTPUT ;
    USE SIGNAL ;
    PORT
      LAYER M4 ;
        RECT 388.608 82.272 388.800 82.296 ;
    END
  END result[159]
  PIN result[160]
    DIRECTION OUTPUT ;
    USE SIGNAL ;
    PORT
      LAYER M4 ;
        RECT 388.608 82.800 388.800 82.824 ;
    END
  END result[160]
  PIN result[161]
    DIRECTION OUTPUT ;
    USE SIGNAL ;
    PORT
      LAYER M4 ;
        RECT 388.608 83.280 388.800 83.304 ;
    END
  END result[161]
  PIN result[162]
    DIRECTION OUTPUT ;
    USE SIGNAL ;
    PORT
      LAYER M4 ;
        RECT 388.608 83.808 388.800 83.832 ;
    END
  END result[162]
  PIN result[163]
    DIRECTION OUTPUT ;
    USE SIGNAL ;
    PORT
      LAYER M4 ;
        RECT 388.608 84.288 388.800 84.312 ;
    END
  END result[163]
  PIN result[164]
    DIRECTION OUTPUT ;
    USE SIGNAL ;
    PORT
      LAYER M4 ;
        RECT 388.608 84.768 388.800 84.792 ;
    END
  END result[164]
  PIN result[165]
    DIRECTION OUTPUT ;
    USE SIGNAL ;
    PORT
      LAYER M4 ;
        RECT 388.608 85.296 388.800 85.320 ;
    END
  END result[165]
  PIN result[166]
    DIRECTION OUTPUT ;
    USE SIGNAL ;
    PORT
      LAYER M4 ;
        RECT 388.608 85.776 388.800 85.800 ;
    END
  END result[166]
  PIN result[167]
    DIRECTION OUTPUT ;
    USE SIGNAL ;
    PORT
      LAYER M4 ;
        RECT 388.608 86.304 388.800 86.328 ;
    END
  END result[167]
  PIN result[168]
    DIRECTION OUTPUT ;
    USE SIGNAL ;
    PORT
      LAYER M4 ;
        RECT 388.608 86.784 388.800 86.808 ;
    END
  END result[168]
  PIN result[169]
    DIRECTION OUTPUT ;
    USE SIGNAL ;
    PORT
      LAYER M4 ;
        RECT 388.608 87.264 388.800 87.288 ;
    END
  END result[169]
  PIN result[170]
    DIRECTION OUTPUT ;
    USE SIGNAL ;
    PORT
      LAYER M4 ;
        RECT 388.608 87.792 388.800 87.816 ;
    END
  END result[170]
  PIN result[171]
    DIRECTION OUTPUT ;
    USE SIGNAL ;
    PORT
      LAYER M4 ;
        RECT 388.608 88.272 388.800 88.296 ;
    END
  END result[171]
  PIN result[172]
    DIRECTION OUTPUT ;
    USE SIGNAL ;
    PORT
      LAYER M4 ;
        RECT 388.608 88.800 388.800 88.824 ;
    END
  END result[172]
  PIN result[173]
    DIRECTION OUTPUT ;
    USE SIGNAL ;
    PORT
      LAYER M4 ;
        RECT 388.608 89.280 388.800 89.304 ;
    END
  END result[173]
  PIN result[174]
    DIRECTION OUTPUT ;
    USE SIGNAL ;
    PORT
      LAYER M4 ;
        RECT 388.608 89.760 388.800 89.784 ;
    END
  END result[174]
  PIN result[175]
    DIRECTION OUTPUT ;
    USE SIGNAL ;
    PORT
      LAYER M4 ;
        RECT 388.608 90.288 388.800 90.312 ;
    END
  END result[175]
  PIN result[176]
    DIRECTION OUTPUT ;
    USE SIGNAL ;
    PORT
      LAYER M4 ;
        RECT 388.608 90.768 388.800 90.792 ;
    END
  END result[176]
  PIN result[177]
    DIRECTION OUTPUT ;
    USE SIGNAL ;
    PORT
      LAYER M4 ;
        RECT 388.608 91.296 388.800 91.320 ;
    END
  END result[177]
  PIN result[178]
    DIRECTION OUTPUT ;
    USE SIGNAL ;
    PORT
      LAYER M4 ;
        RECT 388.608 91.776 388.800 91.800 ;
    END
  END result[178]
  PIN result[179]
    DIRECTION OUTPUT ;
    USE SIGNAL ;
    PORT
      LAYER M4 ;
        RECT 388.608 92.256 388.800 92.280 ;
    END
  END result[179]
  PIN result[180]
    DIRECTION OUTPUT ;
    USE SIGNAL ;
    PORT
      LAYER M4 ;
        RECT 388.608 92.784 388.800 92.808 ;
    END
  END result[180]
  PIN result[181]
    DIRECTION OUTPUT ;
    USE SIGNAL ;
    PORT
      LAYER M4 ;
        RECT 388.608 93.264 388.800 93.288 ;
    END
  END result[181]
  PIN result[182]
    DIRECTION OUTPUT ;
    USE SIGNAL ;
    PORT
      LAYER M4 ;
        RECT 388.608 93.792 388.800 93.816 ;
    END
  END result[182]
  PIN result[183]
    DIRECTION OUTPUT ;
    USE SIGNAL ;
    PORT
      LAYER M4 ;
        RECT 388.608 94.272 388.800 94.296 ;
    END
  END result[183]
  PIN result[184]
    DIRECTION OUTPUT ;
    USE SIGNAL ;
    PORT
      LAYER M4 ;
        RECT 388.608 94.752 388.800 94.776 ;
    END
  END result[184]
  PIN result[185]
    DIRECTION OUTPUT ;
    USE SIGNAL ;
    PORT
      LAYER M4 ;
        RECT 388.608 95.280 388.800 95.304 ;
    END
  END result[185]
  PIN result[186]
    DIRECTION OUTPUT ;
    USE SIGNAL ;
    PORT
      LAYER M4 ;
        RECT 388.608 95.760 388.800 95.784 ;
    END
  END result[186]
  PIN result[187]
    DIRECTION OUTPUT ;
    USE SIGNAL ;
    PORT
      LAYER M4 ;
        RECT 388.608 96.288 388.800 96.312 ;
    END
  END result[187]
  PIN result[188]
    DIRECTION OUTPUT ;
    USE SIGNAL ;
    PORT
      LAYER M4 ;
        RECT 388.608 96.768 388.800 96.792 ;
    END
  END result[188]
  PIN result[189]
    DIRECTION OUTPUT ;
    USE SIGNAL ;
    PORT
      LAYER M4 ;
        RECT 388.608 97.248 388.800 97.272 ;
    END
  END result[189]
  PIN result[190]
    DIRECTION OUTPUT ;
    USE SIGNAL ;
    PORT
      LAYER M4 ;
        RECT 388.608 97.776 388.800 97.800 ;
    END
  END result[190]
  PIN result[191]
    DIRECTION OUTPUT ;
    USE SIGNAL ;
    PORT
      LAYER M4 ;
        RECT 388.608 98.256 388.800 98.280 ;
    END
  END result[191]
  PIN result[192]
    DIRECTION OUTPUT ;
    USE SIGNAL ;
    PORT
      LAYER M4 ;
        RECT 388.608 98.784 388.800 98.808 ;
    END
  END result[192]
  PIN result[193]
    DIRECTION OUTPUT ;
    USE SIGNAL ;
    PORT
      LAYER M4 ;
        RECT 388.608 99.264 388.800 99.288 ;
    END
  END result[193]
  PIN result[194]
    DIRECTION OUTPUT ;
    USE SIGNAL ;
    PORT
      LAYER M4 ;
        RECT 388.608 99.744 388.800 99.768 ;
    END
  END result[194]
  PIN result[195]
    DIRECTION OUTPUT ;
    USE SIGNAL ;
    PORT
      LAYER M4 ;
        RECT 388.608 100.272 388.800 100.296 ;
    END
  END result[195]
  PIN result[196]
    DIRECTION OUTPUT ;
    USE SIGNAL ;
    PORT
      LAYER M4 ;
        RECT 388.608 100.752 388.800 100.776 ;
    END
  END result[196]
  PIN result[197]
    DIRECTION OUTPUT ;
    USE SIGNAL ;
    PORT
      LAYER M4 ;
        RECT 388.608 101.280 388.800 101.304 ;
    END
  END result[197]
  PIN result[198]
    DIRECTION OUTPUT ;
    USE SIGNAL ;
    PORT
      LAYER M4 ;
        RECT 388.608 101.760 388.800 101.784 ;
    END
  END result[198]
  PIN result[199]
    DIRECTION OUTPUT ;
    USE SIGNAL ;
    PORT
      LAYER M4 ;
        RECT 388.608 102.240 388.800 102.264 ;
    END
  END result[199]
  PIN result[200]
    DIRECTION OUTPUT ;
    USE SIGNAL ;
    PORT
      LAYER M4 ;
        RECT 388.608 102.768 388.800 102.792 ;
    END
  END result[200]
  PIN result[201]
    DIRECTION OUTPUT ;
    USE SIGNAL ;
    PORT
      LAYER M4 ;
        RECT 388.608 103.248 388.800 103.272 ;
    END
  END result[201]
  PIN result[202]
    DIRECTION OUTPUT ;
    USE SIGNAL ;
    PORT
      LAYER M4 ;
        RECT 388.608 103.776 388.800 103.800 ;
    END
  END result[202]
  PIN result[203]
    DIRECTION OUTPUT ;
    USE SIGNAL ;
    PORT
      LAYER M4 ;
        RECT 388.608 104.256 388.800 104.280 ;
    END
  END result[203]
  PIN result[204]
    DIRECTION OUTPUT ;
    USE SIGNAL ;
    PORT
      LAYER M4 ;
        RECT 388.608 104.736 388.800 104.760 ;
    END
  END result[204]
  PIN result[205]
    DIRECTION OUTPUT ;
    USE SIGNAL ;
    PORT
      LAYER M4 ;
        RECT 388.608 105.264 388.800 105.288 ;
    END
  END result[205]
  PIN result[206]
    DIRECTION OUTPUT ;
    USE SIGNAL ;
    PORT
      LAYER M4 ;
        RECT 388.608 105.744 388.800 105.768 ;
    END
  END result[206]
  PIN result[207]
    DIRECTION OUTPUT ;
    USE SIGNAL ;
    PORT
      LAYER M4 ;
        RECT 388.608 106.272 388.800 106.296 ;
    END
  END result[207]
  PIN result[208]
    DIRECTION OUTPUT ;
    USE SIGNAL ;
    PORT
      LAYER M4 ;
        RECT 388.608 106.752 388.800 106.776 ;
    END
  END result[208]
  PIN result[209]
    DIRECTION OUTPUT ;
    USE SIGNAL ;
    PORT
      LAYER M4 ;
        RECT 388.608 107.232 388.800 107.256 ;
    END
  END result[209]
  PIN result[210]
    DIRECTION OUTPUT ;
    USE SIGNAL ;
    PORT
      LAYER M4 ;
        RECT 388.608 107.760 388.800 107.784 ;
    END
  END result[210]
  PIN result[211]
    DIRECTION OUTPUT ;
    USE SIGNAL ;
    PORT
      LAYER M4 ;
        RECT 388.608 108.240 388.800 108.264 ;
    END
  END result[211]
  PIN result[212]
    DIRECTION OUTPUT ;
    USE SIGNAL ;
    PORT
      LAYER M4 ;
        RECT 388.608 108.768 388.800 108.792 ;
    END
  END result[212]
  PIN result[213]
    DIRECTION OUTPUT ;
    USE SIGNAL ;
    PORT
      LAYER M4 ;
        RECT 388.608 109.248 388.800 109.272 ;
    END
  END result[213]
  PIN result[214]
    DIRECTION OUTPUT ;
    USE SIGNAL ;
    PORT
      LAYER M4 ;
        RECT 388.608 109.776 388.800 109.800 ;
    END
  END result[214]
  PIN result[215]
    DIRECTION OUTPUT ;
    USE SIGNAL ;
    PORT
      LAYER M4 ;
        RECT 388.608 110.256 388.800 110.280 ;
    END
  END result[215]
  PIN result[216]
    DIRECTION OUTPUT ;
    USE SIGNAL ;
    PORT
      LAYER M4 ;
        RECT 388.608 110.736 388.800 110.760 ;
    END
  END result[216]
  PIN result[217]
    DIRECTION OUTPUT ;
    USE SIGNAL ;
    PORT
      LAYER M4 ;
        RECT 388.608 111.264 388.800 111.288 ;
    END
  END result[217]
  PIN result[218]
    DIRECTION OUTPUT ;
    USE SIGNAL ;
    PORT
      LAYER M4 ;
        RECT 388.608 111.744 388.800 111.768 ;
    END
  END result[218]
  PIN result[219]
    DIRECTION OUTPUT ;
    USE SIGNAL ;
    PORT
      LAYER M4 ;
        RECT 388.608 112.272 388.800 112.296 ;
    END
  END result[219]
  PIN result[220]
    DIRECTION OUTPUT ;
    USE SIGNAL ;
    PORT
      LAYER M4 ;
        RECT 388.608 112.752 388.800 112.776 ;
    END
  END result[220]
  PIN result[221]
    DIRECTION OUTPUT ;
    USE SIGNAL ;
    PORT
      LAYER M4 ;
        RECT 388.608 113.232 388.800 113.256 ;
    END
  END result[221]
  PIN result[222]
    DIRECTION OUTPUT ;
    USE SIGNAL ;
    PORT
      LAYER M4 ;
        RECT 388.608 113.760 388.800 113.784 ;
    END
  END result[222]
  PIN result[223]
    DIRECTION OUTPUT ;
    USE SIGNAL ;
    PORT
      LAYER M4 ;
        RECT 388.608 114.240 388.800 114.264 ;
    END
  END result[223]
  PIN result[224]
    DIRECTION OUTPUT ;
    USE SIGNAL ;
    PORT
      LAYER M4 ;
        RECT 388.608 114.768 388.800 114.792 ;
    END
  END result[224]
  PIN result[225]
    DIRECTION OUTPUT ;
    USE SIGNAL ;
    PORT
      LAYER M4 ;
        RECT 388.608 115.248 388.800 115.272 ;
    END
  END result[225]
  PIN result[226]
    DIRECTION OUTPUT ;
    USE SIGNAL ;
    PORT
      LAYER M4 ;
        RECT 388.608 115.728 388.800 115.752 ;
    END
  END result[226]
  PIN result[227]
    DIRECTION OUTPUT ;
    USE SIGNAL ;
    PORT
      LAYER M4 ;
        RECT 388.608 116.256 388.800 116.280 ;
    END
  END result[227]
  PIN result[228]
    DIRECTION OUTPUT ;
    USE SIGNAL ;
    PORT
      LAYER M4 ;
        RECT 388.608 116.736 388.800 116.760 ;
    END
  END result[228]
  PIN result[229]
    DIRECTION OUTPUT ;
    USE SIGNAL ;
    PORT
      LAYER M4 ;
        RECT 388.608 117.264 388.800 117.288 ;
    END
  END result[229]
  PIN result[230]
    DIRECTION OUTPUT ;
    USE SIGNAL ;
    PORT
      LAYER M4 ;
        RECT 388.608 117.744 388.800 117.768 ;
    END
  END result[230]
  PIN result[231]
    DIRECTION OUTPUT ;
    USE SIGNAL ;
    PORT
      LAYER M4 ;
        RECT 388.608 118.224 388.800 118.248 ;
    END
  END result[231]
  PIN result[232]
    DIRECTION OUTPUT ;
    USE SIGNAL ;
    PORT
      LAYER M4 ;
        RECT 388.608 118.752 388.800 118.776 ;
    END
  END result[232]
  PIN result[233]
    DIRECTION OUTPUT ;
    USE SIGNAL ;
    PORT
      LAYER M4 ;
        RECT 388.608 119.232 388.800 119.256 ;
    END
  END result[233]
  PIN result[234]
    DIRECTION OUTPUT ;
    USE SIGNAL ;
    PORT
      LAYER M4 ;
        RECT 388.608 119.760 388.800 119.784 ;
    END
  END result[234]
  PIN result[235]
    DIRECTION OUTPUT ;
    USE SIGNAL ;
    PORT
      LAYER M4 ;
        RECT 388.608 120.240 388.800 120.264 ;
    END
  END result[235]
  PIN result[236]
    DIRECTION OUTPUT ;
    USE SIGNAL ;
    PORT
      LAYER M4 ;
        RECT 388.608 120.720 388.800 120.744 ;
    END
  END result[236]
  PIN result[237]
    DIRECTION OUTPUT ;
    USE SIGNAL ;
    PORT
      LAYER M4 ;
        RECT 388.608 121.248 388.800 121.272 ;
    END
  END result[237]
  PIN result[238]
    DIRECTION OUTPUT ;
    USE SIGNAL ;
    PORT
      LAYER M4 ;
        RECT 388.608 121.728 388.800 121.752 ;
    END
  END result[238]
  PIN result[239]
    DIRECTION OUTPUT ;
    USE SIGNAL ;
    PORT
      LAYER M4 ;
        RECT 388.608 122.256 388.800 122.280 ;
    END
  END result[239]
  PIN result[240]
    DIRECTION OUTPUT ;
    USE SIGNAL ;
    PORT
      LAYER M4 ;
        RECT 388.608 122.736 388.800 122.760 ;
    END
  END result[240]
  PIN result[241]
    DIRECTION OUTPUT ;
    USE SIGNAL ;
    PORT
      LAYER M4 ;
        RECT 388.608 123.216 388.800 123.240 ;
    END
  END result[241]
  PIN result[242]
    DIRECTION OUTPUT ;
    USE SIGNAL ;
    PORT
      LAYER M4 ;
        RECT 388.608 123.744 388.800 123.768 ;
    END
  END result[242]
  PIN result[243]
    DIRECTION OUTPUT ;
    USE SIGNAL ;
    PORT
      LAYER M4 ;
        RECT 388.608 124.224 388.800 124.248 ;
    END
  END result[243]
  PIN result[244]
    DIRECTION OUTPUT ;
    USE SIGNAL ;
    PORT
      LAYER M4 ;
        RECT 388.608 124.752 388.800 124.776 ;
    END
  END result[244]
  PIN result[245]
    DIRECTION OUTPUT ;
    USE SIGNAL ;
    PORT
      LAYER M4 ;
        RECT 388.608 125.232 388.800 125.256 ;
    END
  END result[245]
  PIN result[246]
    DIRECTION OUTPUT ;
    USE SIGNAL ;
    PORT
      LAYER M4 ;
        RECT 388.608 125.712 388.800 125.736 ;
    END
  END result[246]
  PIN result[247]
    DIRECTION OUTPUT ;
    USE SIGNAL ;
    PORT
      LAYER M4 ;
        RECT 388.608 126.240 388.800 126.264 ;
    END
  END result[247]
  PIN result[248]
    DIRECTION OUTPUT ;
    USE SIGNAL ;
    PORT
      LAYER M4 ;
        RECT 388.608 126.720 388.800 126.744 ;
    END
  END result[248]
  PIN result[249]
    DIRECTION OUTPUT ;
    USE SIGNAL ;
    PORT
      LAYER M4 ;
        RECT 388.608 127.248 388.800 127.272 ;
    END
  END result[249]
  PIN result[250]
    DIRECTION OUTPUT ;
    USE SIGNAL ;
    PORT
      LAYER M4 ;
        RECT 388.608 127.728 388.800 127.752 ;
    END
  END result[250]
  PIN result[251]
    DIRECTION OUTPUT ;
    USE SIGNAL ;
    PORT
      LAYER M4 ;
        RECT 388.608 128.208 388.800 128.232 ;
    END
  END result[251]
  PIN result[252]
    DIRECTION OUTPUT ;
    USE SIGNAL ;
    PORT
      LAYER M4 ;
        RECT 388.608 128.736 388.800 128.760 ;
    END
  END result[252]
  PIN result[253]
    DIRECTION OUTPUT ;
    USE SIGNAL ;
    PORT
      LAYER M4 ;
        RECT 388.608 129.216 388.800 129.240 ;
    END
  END result[253]
  PIN result[254]
    DIRECTION OUTPUT ;
    USE SIGNAL ;
    PORT
      LAYER M4 ;
        RECT 388.608 129.744 388.800 129.768 ;
    END
  END result[254]
  PIN result[255]
    DIRECTION OUTPUT ;
    USE SIGNAL ;
    PORT
      LAYER M4 ;
        RECT 388.608 130.224 388.800 130.248 ;
    END
  END result[255]
  PIN result[256]
    DIRECTION OUTPUT ;
    USE SIGNAL ;
    PORT
      LAYER M4 ;
        RECT 388.608 130.704 388.800 130.728 ;
    END
  END result[256]
  PIN result[257]
    DIRECTION OUTPUT ;
    USE SIGNAL ;
    PORT
      LAYER M4 ;
        RECT 388.608 131.232 388.800 131.256 ;
    END
  END result[257]
  PIN result[258]
    DIRECTION OUTPUT ;
    USE SIGNAL ;
    PORT
      LAYER M4 ;
        RECT 388.608 131.712 388.800 131.736 ;
    END
  END result[258]
  PIN result[259]
    DIRECTION OUTPUT ;
    USE SIGNAL ;
    PORT
      LAYER M4 ;
        RECT 388.608 132.240 388.800 132.264 ;
    END
  END result[259]
  PIN result[260]
    DIRECTION OUTPUT ;
    USE SIGNAL ;
    PORT
      LAYER M4 ;
        RECT 388.608 132.720 388.800 132.744 ;
    END
  END result[260]
  PIN result[261]
    DIRECTION OUTPUT ;
    USE SIGNAL ;
    PORT
      LAYER M4 ;
        RECT 388.608 133.200 388.800 133.224 ;
    END
  END result[261]
  PIN result[262]
    DIRECTION OUTPUT ;
    USE SIGNAL ;
    PORT
      LAYER M4 ;
        RECT 388.608 133.728 388.800 133.752 ;
    END
  END result[262]
  PIN result[263]
    DIRECTION OUTPUT ;
    USE SIGNAL ;
    PORT
      LAYER M4 ;
        RECT 388.608 134.208 388.800 134.232 ;
    END
  END result[263]
  PIN result[264]
    DIRECTION OUTPUT ;
    USE SIGNAL ;
    PORT
      LAYER M4 ;
        RECT 388.608 134.736 388.800 134.760 ;
    END
  END result[264]
  PIN result[265]
    DIRECTION OUTPUT ;
    USE SIGNAL ;
    PORT
      LAYER M4 ;
        RECT 388.608 135.216 388.800 135.240 ;
    END
  END result[265]
  PIN result[266]
    DIRECTION OUTPUT ;
    USE SIGNAL ;
    PORT
      LAYER M4 ;
        RECT 388.608 135.696 388.800 135.720 ;
    END
  END result[266]
  PIN result[267]
    DIRECTION OUTPUT ;
    USE SIGNAL ;
    PORT
      LAYER M4 ;
        RECT 388.608 136.224 388.800 136.248 ;
    END
  END result[267]
  PIN result[268]
    DIRECTION OUTPUT ;
    USE SIGNAL ;
    PORT
      LAYER M4 ;
        RECT 388.608 136.704 388.800 136.728 ;
    END
  END result[268]
  PIN result[269]
    DIRECTION OUTPUT ;
    USE SIGNAL ;
    PORT
      LAYER M4 ;
        RECT 388.608 137.232 388.800 137.256 ;
    END
  END result[269]
  PIN result[270]
    DIRECTION OUTPUT ;
    USE SIGNAL ;
    PORT
      LAYER M4 ;
        RECT 388.608 137.712 388.800 137.736 ;
    END
  END result[270]
  PIN result[271]
    DIRECTION OUTPUT ;
    USE SIGNAL ;
    PORT
      LAYER M4 ;
        RECT 388.608 138.192 388.800 138.216 ;
    END
  END result[271]
  PIN result[272]
    DIRECTION OUTPUT ;
    USE SIGNAL ;
    PORT
      LAYER M4 ;
        RECT 388.608 138.720 388.800 138.744 ;
    END
  END result[272]
  PIN result[273]
    DIRECTION OUTPUT ;
    USE SIGNAL ;
    PORT
      LAYER M4 ;
        RECT 388.608 139.200 388.800 139.224 ;
    END
  END result[273]
  PIN result[274]
    DIRECTION OUTPUT ;
    USE SIGNAL ;
    PORT
      LAYER M4 ;
        RECT 388.608 139.728 388.800 139.752 ;
    END
  END result[274]
  PIN result[275]
    DIRECTION OUTPUT ;
    USE SIGNAL ;
    PORT
      LAYER M4 ;
        RECT 388.608 140.208 388.800 140.232 ;
    END
  END result[275]
  PIN result[276]
    DIRECTION OUTPUT ;
    USE SIGNAL ;
    PORT
      LAYER M4 ;
        RECT 388.608 140.688 388.800 140.712 ;
    END
  END result[276]
  PIN result[277]
    DIRECTION OUTPUT ;
    USE SIGNAL ;
    PORT
      LAYER M4 ;
        RECT 388.608 141.216 388.800 141.240 ;
    END
  END result[277]
  PIN result[278]
    DIRECTION OUTPUT ;
    USE SIGNAL ;
    PORT
      LAYER M4 ;
        RECT 388.608 141.696 388.800 141.720 ;
    END
  END result[278]
  PIN result[279]
    DIRECTION OUTPUT ;
    USE SIGNAL ;
    PORT
      LAYER M4 ;
        RECT 388.608 142.224 388.800 142.248 ;
    END
  END result[279]
  PIN result[280]
    DIRECTION OUTPUT ;
    USE SIGNAL ;
    PORT
      LAYER M4 ;
        RECT 388.608 142.704 388.800 142.728 ;
    END
  END result[280]
  PIN result[281]
    DIRECTION OUTPUT ;
    USE SIGNAL ;
    PORT
      LAYER M4 ;
        RECT 388.608 143.184 388.800 143.208 ;
    END
  END result[281]
  PIN result[282]
    DIRECTION OUTPUT ;
    USE SIGNAL ;
    PORT
      LAYER M4 ;
        RECT 388.608 143.712 388.800 143.736 ;
    END
  END result[282]
  PIN result[283]
    DIRECTION OUTPUT ;
    USE SIGNAL ;
    PORT
      LAYER M4 ;
        RECT 388.608 144.192 388.800 144.216 ;
    END
  END result[283]
  PIN result[284]
    DIRECTION OUTPUT ;
    USE SIGNAL ;
    PORT
      LAYER M4 ;
        RECT 388.608 144.720 388.800 144.744 ;
    END
  END result[284]
  PIN result[285]
    DIRECTION OUTPUT ;
    USE SIGNAL ;
    PORT
      LAYER M4 ;
        RECT 388.608 145.200 388.800 145.224 ;
    END
  END result[285]
  PIN result[286]
    DIRECTION OUTPUT ;
    USE SIGNAL ;
    PORT
      LAYER M4 ;
        RECT 388.608 145.680 388.800 145.704 ;
    END
  END result[286]
  PIN result[287]
    DIRECTION OUTPUT ;
    USE SIGNAL ;
    PORT
      LAYER M4 ;
        RECT 388.608 146.208 388.800 146.232 ;
    END
  END result[287]
  PIN result[288]
    DIRECTION OUTPUT ;
    USE SIGNAL ;
    PORT
      LAYER M4 ;
        RECT 388.608 146.688 388.800 146.712 ;
    END
  END result[288]
  PIN result[289]
    DIRECTION OUTPUT ;
    USE SIGNAL ;
    PORT
      LAYER M4 ;
        RECT 388.608 147.216 388.800 147.240 ;
    END
  END result[289]
  PIN result[290]
    DIRECTION OUTPUT ;
    USE SIGNAL ;
    PORT
      LAYER M4 ;
        RECT 388.608 147.696 388.800 147.720 ;
    END
  END result[290]
  PIN result[291]
    DIRECTION OUTPUT ;
    USE SIGNAL ;
    PORT
      LAYER M4 ;
        RECT 388.608 148.224 388.800 148.248 ;
    END
  END result[291]
  PIN result[292]
    DIRECTION OUTPUT ;
    USE SIGNAL ;
    PORT
      LAYER M4 ;
        RECT 388.608 148.704 388.800 148.728 ;
    END
  END result[292]
  PIN result[293]
    DIRECTION OUTPUT ;
    USE SIGNAL ;
    PORT
      LAYER M4 ;
        RECT 388.608 149.184 388.800 149.208 ;
    END
  END result[293]
  PIN result[294]
    DIRECTION OUTPUT ;
    USE SIGNAL ;
    PORT
      LAYER M4 ;
        RECT 388.608 149.712 388.800 149.736 ;
    END
  END result[294]
  PIN result[295]
    DIRECTION OUTPUT ;
    USE SIGNAL ;
    PORT
      LAYER M4 ;
        RECT 388.608 150.192 388.800 150.216 ;
    END
  END result[295]
  PIN result[296]
    DIRECTION OUTPUT ;
    USE SIGNAL ;
    PORT
      LAYER M4 ;
        RECT 388.608 150.720 388.800 150.744 ;
    END
  END result[296]
  PIN result[297]
    DIRECTION OUTPUT ;
    USE SIGNAL ;
    PORT
      LAYER M4 ;
        RECT 388.608 151.200 388.800 151.224 ;
    END
  END result[297]
  PIN result[298]
    DIRECTION OUTPUT ;
    USE SIGNAL ;
    PORT
      LAYER M4 ;
        RECT 388.608 151.680 388.800 151.704 ;
    END
  END result[298]
  PIN result[299]
    DIRECTION OUTPUT ;
    USE SIGNAL ;
    PORT
      LAYER M4 ;
        RECT 388.608 152.208 388.800 152.232 ;
    END
  END result[299]
  PIN result[300]
    DIRECTION OUTPUT ;
    USE SIGNAL ;
    PORT
      LAYER M4 ;
        RECT 388.608 152.688 388.800 152.712 ;
    END
  END result[300]
  PIN result[301]
    DIRECTION OUTPUT ;
    USE SIGNAL ;
    PORT
      LAYER M4 ;
        RECT 388.608 153.216 388.800 153.240 ;
    END
  END result[301]
  PIN result[302]
    DIRECTION OUTPUT ;
    USE SIGNAL ;
    PORT
      LAYER M4 ;
        RECT 388.608 153.696 388.800 153.720 ;
    END
  END result[302]
  PIN result[303]
    DIRECTION OUTPUT ;
    USE SIGNAL ;
    PORT
      LAYER M4 ;
        RECT 388.608 154.176 388.800 154.200 ;
    END
  END result[303]
  PIN result[304]
    DIRECTION OUTPUT ;
    USE SIGNAL ;
    PORT
      LAYER M4 ;
        RECT 388.608 154.704 388.800 154.728 ;
    END
  END result[304]
  PIN result[305]
    DIRECTION OUTPUT ;
    USE SIGNAL ;
    PORT
      LAYER M4 ;
        RECT 388.608 155.184 388.800 155.208 ;
    END
  END result[305]
  PIN result[306]
    DIRECTION OUTPUT ;
    USE SIGNAL ;
    PORT
      LAYER M4 ;
        RECT 388.608 155.712 388.800 155.736 ;
    END
  END result[306]
  PIN result[307]
    DIRECTION OUTPUT ;
    USE SIGNAL ;
    PORT
      LAYER M4 ;
        RECT 388.608 156.192 388.800 156.216 ;
    END
  END result[307]
  PIN result[308]
    DIRECTION OUTPUT ;
    USE SIGNAL ;
    PORT
      LAYER M4 ;
        RECT 388.608 156.672 388.800 156.696 ;
    END
  END result[308]
  PIN result[309]
    DIRECTION OUTPUT ;
    USE SIGNAL ;
    PORT
      LAYER M4 ;
        RECT 388.608 157.200 388.800 157.224 ;
    END
  END result[309]
  PIN result[310]
    DIRECTION OUTPUT ;
    USE SIGNAL ;
    PORT
      LAYER M4 ;
        RECT 388.608 157.680 388.800 157.704 ;
    END
  END result[310]
  PIN result[311]
    DIRECTION OUTPUT ;
    USE SIGNAL ;
    PORT
      LAYER M4 ;
        RECT 388.608 158.208 388.800 158.232 ;
    END
  END result[311]
  PIN result[312]
    DIRECTION OUTPUT ;
    USE SIGNAL ;
    PORT
      LAYER M4 ;
        RECT 388.608 158.688 388.800 158.712 ;
    END
  END result[312]
  PIN result[313]
    DIRECTION OUTPUT ;
    USE SIGNAL ;
    PORT
      LAYER M4 ;
        RECT 388.608 159.168 388.800 159.192 ;
    END
  END result[313]
  PIN result[314]
    DIRECTION OUTPUT ;
    USE SIGNAL ;
    PORT
      LAYER M4 ;
        RECT 388.608 159.696 388.800 159.720 ;
    END
  END result[314]
  PIN result[315]
    DIRECTION OUTPUT ;
    USE SIGNAL ;
    PORT
      LAYER M4 ;
        RECT 388.608 160.176 388.800 160.200 ;
    END
  END result[315]
  PIN result[316]
    DIRECTION OUTPUT ;
    USE SIGNAL ;
    PORT
      LAYER M4 ;
        RECT 388.608 160.704 388.800 160.728 ;
    END
  END result[316]
  PIN result[317]
    DIRECTION OUTPUT ;
    USE SIGNAL ;
    PORT
      LAYER M4 ;
        RECT 388.608 161.184 388.800 161.208 ;
    END
  END result[317]
  PIN result[318]
    DIRECTION OUTPUT ;
    USE SIGNAL ;
    PORT
      LAYER M4 ;
        RECT 388.608 161.664 388.800 161.688 ;
    END
  END result[318]
  PIN result[319]
    DIRECTION OUTPUT ;
    USE SIGNAL ;
    PORT
      LAYER M4 ;
        RECT 388.608 162.192 388.800 162.216 ;
    END
  END result[319]
  PIN result[320]
    DIRECTION OUTPUT ;
    USE SIGNAL ;
    PORT
      LAYER M4 ;
        RECT 388.608 162.672 388.800 162.696 ;
    END
  END result[320]
  PIN result[321]
    DIRECTION OUTPUT ;
    USE SIGNAL ;
    PORT
      LAYER M4 ;
        RECT 388.608 163.200 388.800 163.224 ;
    END
  END result[321]
  PIN result[322]
    DIRECTION OUTPUT ;
    USE SIGNAL ;
    PORT
      LAYER M4 ;
        RECT 388.608 163.680 388.800 163.704 ;
    END
  END result[322]
  PIN result[323]
    DIRECTION OUTPUT ;
    USE SIGNAL ;
    PORT
      LAYER M4 ;
        RECT 388.608 164.160 388.800 164.184 ;
    END
  END result[323]
  PIN result[324]
    DIRECTION OUTPUT ;
    USE SIGNAL ;
    PORT
      LAYER M4 ;
        RECT 388.608 164.688 388.800 164.712 ;
    END
  END result[324]
  PIN result[325]
    DIRECTION OUTPUT ;
    USE SIGNAL ;
    PORT
      LAYER M4 ;
        RECT 388.608 165.168 388.800 165.192 ;
    END
  END result[325]
  PIN result[326]
    DIRECTION OUTPUT ;
    USE SIGNAL ;
    PORT
      LAYER M4 ;
        RECT 388.608 165.696 388.800 165.720 ;
    END
  END result[326]
  PIN result[327]
    DIRECTION OUTPUT ;
    USE SIGNAL ;
    PORT
      LAYER M4 ;
        RECT 388.608 166.176 388.800 166.200 ;
    END
  END result[327]
  PIN result[328]
    DIRECTION OUTPUT ;
    USE SIGNAL ;
    PORT
      LAYER M4 ;
        RECT 388.608 166.656 388.800 166.680 ;
    END
  END result[328]
  PIN result[329]
    DIRECTION OUTPUT ;
    USE SIGNAL ;
    PORT
      LAYER M4 ;
        RECT 388.608 167.184 388.800 167.208 ;
    END
  END result[329]
  PIN result[330]
    DIRECTION OUTPUT ;
    USE SIGNAL ;
    PORT
      LAYER M4 ;
        RECT 388.608 167.664 388.800 167.688 ;
    END
  END result[330]
  PIN result[331]
    DIRECTION OUTPUT ;
    USE SIGNAL ;
    PORT
      LAYER M4 ;
        RECT 388.608 168.192 388.800 168.216 ;
    END
  END result[331]
  PIN result[332]
    DIRECTION OUTPUT ;
    USE SIGNAL ;
    PORT
      LAYER M4 ;
        RECT 388.608 168.672 388.800 168.696 ;
    END
  END result[332]
  PIN result[333]
    DIRECTION OUTPUT ;
    USE SIGNAL ;
    PORT
      LAYER M4 ;
        RECT 388.608 169.152 388.800 169.176 ;
    END
  END result[333]
  PIN result[334]
    DIRECTION OUTPUT ;
    USE SIGNAL ;
    PORT
      LAYER M4 ;
        RECT 388.608 169.680 388.800 169.704 ;
    END
  END result[334]
  PIN result[335]
    DIRECTION OUTPUT ;
    USE SIGNAL ;
    PORT
      LAYER M4 ;
        RECT 388.608 170.160 388.800 170.184 ;
    END
  END result[335]
  PIN result[336]
    DIRECTION OUTPUT ;
    USE SIGNAL ;
    PORT
      LAYER M4 ;
        RECT 388.608 170.688 388.800 170.712 ;
    END
  END result[336]
  PIN result[337]
    DIRECTION OUTPUT ;
    USE SIGNAL ;
    PORT
      LAYER M4 ;
        RECT 388.608 171.168 388.800 171.192 ;
    END
  END result[337]
  PIN result[338]
    DIRECTION OUTPUT ;
    USE SIGNAL ;
    PORT
      LAYER M4 ;
        RECT 388.608 171.648 388.800 171.672 ;
    END
  END result[338]
  PIN result[339]
    DIRECTION OUTPUT ;
    USE SIGNAL ;
    PORT
      LAYER M4 ;
        RECT 388.608 172.176 388.800 172.200 ;
    END
  END result[339]
  PIN result[340]
    DIRECTION OUTPUT ;
    USE SIGNAL ;
    PORT
      LAYER M4 ;
        RECT 388.608 172.656 388.800 172.680 ;
    END
  END result[340]
  PIN result[341]
    DIRECTION OUTPUT ;
    USE SIGNAL ;
    PORT
      LAYER M4 ;
        RECT 388.608 173.184 388.800 173.208 ;
    END
  END result[341]
  PIN result[342]
    DIRECTION OUTPUT ;
    USE SIGNAL ;
    PORT
      LAYER M4 ;
        RECT 388.608 173.664 388.800 173.688 ;
    END
  END result[342]
  PIN result[343]
    DIRECTION OUTPUT ;
    USE SIGNAL ;
    PORT
      LAYER M4 ;
        RECT 388.608 174.144 388.800 174.168 ;
    END
  END result[343]
  PIN result[344]
    DIRECTION OUTPUT ;
    USE SIGNAL ;
    PORT
      LAYER M4 ;
        RECT 388.608 174.672 388.800 174.696 ;
    END
  END result[344]
  PIN result[345]
    DIRECTION OUTPUT ;
    USE SIGNAL ;
    PORT
      LAYER M4 ;
        RECT 388.608 175.152 388.800 175.176 ;
    END
  END result[345]
  PIN result[346]
    DIRECTION OUTPUT ;
    USE SIGNAL ;
    PORT
      LAYER M4 ;
        RECT 388.608 175.680 388.800 175.704 ;
    END
  END result[346]
  PIN result[347]
    DIRECTION OUTPUT ;
    USE SIGNAL ;
    PORT
      LAYER M4 ;
        RECT 388.608 176.160 388.800 176.184 ;
    END
  END result[347]
  PIN result[348]
    DIRECTION OUTPUT ;
    USE SIGNAL ;
    PORT
      LAYER M4 ;
        RECT 388.608 176.640 388.800 176.664 ;
    END
  END result[348]
  PIN result[349]
    DIRECTION OUTPUT ;
    USE SIGNAL ;
    PORT
      LAYER M4 ;
        RECT 388.608 177.168 388.800 177.192 ;
    END
  END result[349]
  PIN result[350]
    DIRECTION OUTPUT ;
    USE SIGNAL ;
    PORT
      LAYER M4 ;
        RECT 388.608 177.648 388.800 177.672 ;
    END
  END result[350]
  PIN result[351]
    DIRECTION OUTPUT ;
    USE SIGNAL ;
    PORT
      LAYER M4 ;
        RECT 388.608 178.176 388.800 178.200 ;
    END
  END result[351]
  PIN result[352]
    DIRECTION OUTPUT ;
    USE SIGNAL ;
    PORT
      LAYER M4 ;
        RECT 388.608 178.656 388.800 178.680 ;
    END
  END result[352]
  PIN result[353]
    DIRECTION OUTPUT ;
    USE SIGNAL ;
    PORT
      LAYER M4 ;
        RECT 388.608 179.136 388.800 179.160 ;
    END
  END result[353]
  PIN result[354]
    DIRECTION OUTPUT ;
    USE SIGNAL ;
    PORT
      LAYER M4 ;
        RECT 388.608 179.664 388.800 179.688 ;
    END
  END result[354]
  PIN result[355]
    DIRECTION OUTPUT ;
    USE SIGNAL ;
    PORT
      LAYER M4 ;
        RECT 388.608 180.144 388.800 180.168 ;
    END
  END result[355]
  PIN result[356]
    DIRECTION OUTPUT ;
    USE SIGNAL ;
    PORT
      LAYER M4 ;
        RECT 388.608 180.672 388.800 180.696 ;
    END
  END result[356]
  PIN result[357]
    DIRECTION OUTPUT ;
    USE SIGNAL ;
    PORT
      LAYER M4 ;
        RECT 388.608 181.152 388.800 181.176 ;
    END
  END result[357]
  PIN result[358]
    DIRECTION OUTPUT ;
    USE SIGNAL ;
    PORT
      LAYER M4 ;
        RECT 388.608 181.632 388.800 181.656 ;
    END
  END result[358]
  PIN result[359]
    DIRECTION OUTPUT ;
    USE SIGNAL ;
    PORT
      LAYER M4 ;
        RECT 388.608 182.160 388.800 182.184 ;
    END
  END result[359]
  PIN result[360]
    DIRECTION OUTPUT ;
    USE SIGNAL ;
    PORT
      LAYER M4 ;
        RECT 388.608 182.640 388.800 182.664 ;
    END
  END result[360]
  PIN result[361]
    DIRECTION OUTPUT ;
    USE SIGNAL ;
    PORT
      LAYER M4 ;
        RECT 388.608 183.168 388.800 183.192 ;
    END
  END result[361]
  PIN result[362]
    DIRECTION OUTPUT ;
    USE SIGNAL ;
    PORT
      LAYER M4 ;
        RECT 388.608 183.648 388.800 183.672 ;
    END
  END result[362]
  PIN result[363]
    DIRECTION OUTPUT ;
    USE SIGNAL ;
    PORT
      LAYER M4 ;
        RECT 388.608 184.128 388.800 184.152 ;
    END
  END result[363]
  PIN result[364]
    DIRECTION OUTPUT ;
    USE SIGNAL ;
    PORT
      LAYER M4 ;
        RECT 388.608 184.656 388.800 184.680 ;
    END
  END result[364]
  PIN result[365]
    DIRECTION OUTPUT ;
    USE SIGNAL ;
    PORT
      LAYER M4 ;
        RECT 388.608 185.136 388.800 185.160 ;
    END
  END result[365]
  PIN result[366]
    DIRECTION OUTPUT ;
    USE SIGNAL ;
    PORT
      LAYER M4 ;
        RECT 388.608 185.664 388.800 185.688 ;
    END
  END result[366]
  PIN result[367]
    DIRECTION OUTPUT ;
    USE SIGNAL ;
    PORT
      LAYER M4 ;
        RECT 388.608 186.144 388.800 186.168 ;
    END
  END result[367]
  PIN result[368]
    DIRECTION OUTPUT ;
    USE SIGNAL ;
    PORT
      LAYER M4 ;
        RECT 388.608 186.672 388.800 186.696 ;
    END
  END result[368]
  PIN result[369]
    DIRECTION OUTPUT ;
    USE SIGNAL ;
    PORT
      LAYER M4 ;
        RECT 388.608 187.152 388.800 187.176 ;
    END
  END result[369]
  PIN result[370]
    DIRECTION OUTPUT ;
    USE SIGNAL ;
    PORT
      LAYER M4 ;
        RECT 388.608 187.632 388.800 187.656 ;
    END
  END result[370]
  PIN result[371]
    DIRECTION OUTPUT ;
    USE SIGNAL ;
    PORT
      LAYER M4 ;
        RECT 388.608 188.160 388.800 188.184 ;
    END
  END result[371]
  PIN result[372]
    DIRECTION OUTPUT ;
    USE SIGNAL ;
    PORT
      LAYER M4 ;
        RECT 388.608 188.640 388.800 188.664 ;
    END
  END result[372]
  PIN result[373]
    DIRECTION OUTPUT ;
    USE SIGNAL ;
    PORT
      LAYER M4 ;
        RECT 388.608 189.168 388.800 189.192 ;
    END
  END result[373]
  PIN result[374]
    DIRECTION OUTPUT ;
    USE SIGNAL ;
    PORT
      LAYER M4 ;
        RECT 388.608 189.648 388.800 189.672 ;
    END
  END result[374]
  PIN result[375]
    DIRECTION OUTPUT ;
    USE SIGNAL ;
    PORT
      LAYER M4 ;
        RECT 388.608 190.128 388.800 190.152 ;
    END
  END result[375]
  PIN result[376]
    DIRECTION OUTPUT ;
    USE SIGNAL ;
    PORT
      LAYER M4 ;
        RECT 388.608 190.656 388.800 190.680 ;
    END
  END result[376]
  PIN result[377]
    DIRECTION OUTPUT ;
    USE SIGNAL ;
    PORT
      LAYER M4 ;
        RECT 388.608 191.136 388.800 191.160 ;
    END
  END result[377]
  PIN result[378]
    DIRECTION OUTPUT ;
    USE SIGNAL ;
    PORT
      LAYER M4 ;
        RECT 388.608 191.664 388.800 191.688 ;
    END
  END result[378]
  PIN result[379]
    DIRECTION OUTPUT ;
    USE SIGNAL ;
    PORT
      LAYER M4 ;
        RECT 388.608 192.144 388.800 192.168 ;
    END
  END result[379]
  PIN result[380]
    DIRECTION OUTPUT ;
    USE SIGNAL ;
    PORT
      LAYER M4 ;
        RECT 388.608 192.624 388.800 192.648 ;
    END
  END result[380]
  PIN result[381]
    DIRECTION OUTPUT ;
    USE SIGNAL ;
    PORT
      LAYER M4 ;
        RECT 388.608 193.152 388.800 193.176 ;
    END
  END result[381]
  PIN result[382]
    DIRECTION OUTPUT ;
    USE SIGNAL ;
    PORT
      LAYER M4 ;
        RECT 388.608 193.632 388.800 193.656 ;
    END
  END result[382]
  PIN result[383]
    DIRECTION OUTPUT ;
    USE SIGNAL ;
    PORT
      LAYER M4 ;
        RECT 388.608 194.160 388.800 194.184 ;
    END
  END result[383]
  PIN result[384]
    DIRECTION OUTPUT ;
    USE SIGNAL ;
    PORT
      LAYER M4 ;
        RECT 388.608 194.640 388.800 194.664 ;
    END
  END result[384]
  PIN result[385]
    DIRECTION OUTPUT ;
    USE SIGNAL ;
    PORT
      LAYER M4 ;
        RECT 388.608 195.120 388.800 195.144 ;
    END
  END result[385]
  PIN result[386]
    DIRECTION OUTPUT ;
    USE SIGNAL ;
    PORT
      LAYER M4 ;
        RECT 388.608 195.648 388.800 195.672 ;
    END
  END result[386]
  PIN result[387]
    DIRECTION OUTPUT ;
    USE SIGNAL ;
    PORT
      LAYER M4 ;
        RECT 388.608 196.128 388.800 196.152 ;
    END
  END result[387]
  PIN result[388]
    DIRECTION OUTPUT ;
    USE SIGNAL ;
    PORT
      LAYER M4 ;
        RECT 388.608 196.656 388.800 196.680 ;
    END
  END result[388]
  PIN result[389]
    DIRECTION OUTPUT ;
    USE SIGNAL ;
    PORT
      LAYER M4 ;
        RECT 388.608 197.136 388.800 197.160 ;
    END
  END result[389]
  PIN result[390]
    DIRECTION OUTPUT ;
    USE SIGNAL ;
    PORT
      LAYER M4 ;
        RECT 388.608 197.616 388.800 197.640 ;
    END
  END result[390]
  PIN result[391]
    DIRECTION OUTPUT ;
    USE SIGNAL ;
    PORT
      LAYER M4 ;
        RECT 388.608 198.144 388.800 198.168 ;
    END
  END result[391]
  PIN result[392]
    DIRECTION OUTPUT ;
    USE SIGNAL ;
    PORT
      LAYER M4 ;
        RECT 388.608 198.624 388.800 198.648 ;
    END
  END result[392]
  PIN result[393]
    DIRECTION OUTPUT ;
    USE SIGNAL ;
    PORT
      LAYER M4 ;
        RECT 388.608 199.152 388.800 199.176 ;
    END
  END result[393]
  PIN result[394]
    DIRECTION OUTPUT ;
    USE SIGNAL ;
    PORT
      LAYER M4 ;
        RECT 388.608 199.632 388.800 199.656 ;
    END
  END result[394]
  PIN result[395]
    DIRECTION OUTPUT ;
    USE SIGNAL ;
    PORT
      LAYER M4 ;
        RECT 388.608 200.112 388.800 200.136 ;
    END
  END result[395]
  PIN result[396]
    DIRECTION OUTPUT ;
    USE SIGNAL ;
    PORT
      LAYER M4 ;
        RECT 388.608 200.640 388.800 200.664 ;
    END
  END result[396]
  PIN result[397]
    DIRECTION OUTPUT ;
    USE SIGNAL ;
    PORT
      LAYER M4 ;
        RECT 388.608 201.120 388.800 201.144 ;
    END
  END result[397]
  PIN result[398]
    DIRECTION OUTPUT ;
    USE SIGNAL ;
    PORT
      LAYER M4 ;
        RECT 388.608 201.648 388.800 201.672 ;
    END
  END result[398]
  PIN result[399]
    DIRECTION OUTPUT ;
    USE SIGNAL ;
    PORT
      LAYER M4 ;
        RECT 388.608 202.128 388.800 202.152 ;
    END
  END result[399]
  PIN result[400]
    DIRECTION OUTPUT ;
    USE SIGNAL ;
    PORT
      LAYER M4 ;
        RECT 388.608 202.608 388.800 202.632 ;
    END
  END result[400]
  PIN result[401]
    DIRECTION OUTPUT ;
    USE SIGNAL ;
    PORT
      LAYER M4 ;
        RECT 388.608 203.136 388.800 203.160 ;
    END
  END result[401]
  PIN result[402]
    DIRECTION OUTPUT ;
    USE SIGNAL ;
    PORT
      LAYER M4 ;
        RECT 388.608 203.616 388.800 203.640 ;
    END
  END result[402]
  PIN result[403]
    DIRECTION OUTPUT ;
    USE SIGNAL ;
    PORT
      LAYER M4 ;
        RECT 388.608 204.144 388.800 204.168 ;
    END
  END result[403]
  PIN result[404]
    DIRECTION OUTPUT ;
    USE SIGNAL ;
    PORT
      LAYER M4 ;
        RECT 388.608 204.624 388.800 204.648 ;
    END
  END result[404]
  PIN result[405]
    DIRECTION OUTPUT ;
    USE SIGNAL ;
    PORT
      LAYER M4 ;
        RECT 388.608 205.104 388.800 205.128 ;
    END
  END result[405]
  PIN result[406]
    DIRECTION OUTPUT ;
    USE SIGNAL ;
    PORT
      LAYER M4 ;
        RECT 388.608 205.632 388.800 205.656 ;
    END
  END result[406]
  PIN result[407]
    DIRECTION OUTPUT ;
    USE SIGNAL ;
    PORT
      LAYER M4 ;
        RECT 388.608 206.112 388.800 206.136 ;
    END
  END result[407]
  PIN result[408]
    DIRECTION OUTPUT ;
    USE SIGNAL ;
    PORT
      LAYER M4 ;
        RECT 388.608 206.640 388.800 206.664 ;
    END
  END result[408]
  PIN result[409]
    DIRECTION OUTPUT ;
    USE SIGNAL ;
    PORT
      LAYER M4 ;
        RECT 388.608 207.120 388.800 207.144 ;
    END
  END result[409]
  PIN result[410]
    DIRECTION OUTPUT ;
    USE SIGNAL ;
    PORT
      LAYER M4 ;
        RECT 388.608 207.600 388.800 207.624 ;
    END
  END result[410]
  PIN result[411]
    DIRECTION OUTPUT ;
    USE SIGNAL ;
    PORT
      LAYER M4 ;
        RECT 388.608 208.128 388.800 208.152 ;
    END
  END result[411]
  PIN result[412]
    DIRECTION OUTPUT ;
    USE SIGNAL ;
    PORT
      LAYER M4 ;
        RECT 388.608 208.608 388.800 208.632 ;
    END
  END result[412]
  PIN result[413]
    DIRECTION OUTPUT ;
    USE SIGNAL ;
    PORT
      LAYER M4 ;
        RECT 388.608 209.136 388.800 209.160 ;
    END
  END result[413]
  PIN result[414]
    DIRECTION OUTPUT ;
    USE SIGNAL ;
    PORT
      LAYER M4 ;
        RECT 388.608 209.616 388.800 209.640 ;
    END
  END result[414]
  PIN result[415]
    DIRECTION OUTPUT ;
    USE SIGNAL ;
    PORT
      LAYER M4 ;
        RECT 388.608 210.096 388.800 210.120 ;
    END
  END result[415]
  PIN result[416]
    DIRECTION OUTPUT ;
    USE SIGNAL ;
    PORT
      LAYER M4 ;
        RECT 388.608 210.624 388.800 210.648 ;
    END
  END result[416]
  PIN result[417]
    DIRECTION OUTPUT ;
    USE SIGNAL ;
    PORT
      LAYER M4 ;
        RECT 388.608 211.104 388.800 211.128 ;
    END
  END result[417]
  PIN result[418]
    DIRECTION OUTPUT ;
    USE SIGNAL ;
    PORT
      LAYER M4 ;
        RECT 388.608 211.632 388.800 211.656 ;
    END
  END result[418]
  PIN result[419]
    DIRECTION OUTPUT ;
    USE SIGNAL ;
    PORT
      LAYER M4 ;
        RECT 388.608 212.112 388.800 212.136 ;
    END
  END result[419]
  PIN result[420]
    DIRECTION OUTPUT ;
    USE SIGNAL ;
    PORT
      LAYER M4 ;
        RECT 388.608 212.592 388.800 212.616 ;
    END
  END result[420]
  PIN result[421]
    DIRECTION OUTPUT ;
    USE SIGNAL ;
    PORT
      LAYER M4 ;
        RECT 388.608 213.120 388.800 213.144 ;
    END
  END result[421]
  PIN result[422]
    DIRECTION OUTPUT ;
    USE SIGNAL ;
    PORT
      LAYER M4 ;
        RECT 388.608 213.600 388.800 213.624 ;
    END
  END result[422]
  PIN result[423]
    DIRECTION OUTPUT ;
    USE SIGNAL ;
    PORT
      LAYER M4 ;
        RECT 388.608 214.128 388.800 214.152 ;
    END
  END result[423]
  PIN result[424]
    DIRECTION OUTPUT ;
    USE SIGNAL ;
    PORT
      LAYER M4 ;
        RECT 388.608 214.608 388.800 214.632 ;
    END
  END result[424]
  PIN result[425]
    DIRECTION OUTPUT ;
    USE SIGNAL ;
    PORT
      LAYER M4 ;
        RECT 388.608 215.088 388.800 215.112 ;
    END
  END result[425]
  PIN result[426]
    DIRECTION OUTPUT ;
    USE SIGNAL ;
    PORT
      LAYER M4 ;
        RECT 388.608 215.616 388.800 215.640 ;
    END
  END result[426]
  PIN result[427]
    DIRECTION OUTPUT ;
    USE SIGNAL ;
    PORT
      LAYER M4 ;
        RECT 388.608 216.096 388.800 216.120 ;
    END
  END result[427]
  PIN result[428]
    DIRECTION OUTPUT ;
    USE SIGNAL ;
    PORT
      LAYER M4 ;
        RECT 388.608 216.624 388.800 216.648 ;
    END
  END result[428]
  PIN result[429]
    DIRECTION OUTPUT ;
    USE SIGNAL ;
    PORT
      LAYER M4 ;
        RECT 388.608 217.104 388.800 217.128 ;
    END
  END result[429]
  PIN result[430]
    DIRECTION OUTPUT ;
    USE SIGNAL ;
    PORT
      LAYER M4 ;
        RECT 388.608 217.584 388.800 217.608 ;
    END
  END result[430]
  PIN result[431]
    DIRECTION OUTPUT ;
    USE SIGNAL ;
    PORT
      LAYER M4 ;
        RECT 388.608 218.112 388.800 218.136 ;
    END
  END result[431]
  PIN result[432]
    DIRECTION OUTPUT ;
    USE SIGNAL ;
    PORT
      LAYER M4 ;
        RECT 388.608 218.592 388.800 218.616 ;
    END
  END result[432]
  PIN result[433]
    DIRECTION OUTPUT ;
    USE SIGNAL ;
    PORT
      LAYER M4 ;
        RECT 388.608 219.120 388.800 219.144 ;
    END
  END result[433]
  PIN result[434]
    DIRECTION OUTPUT ;
    USE SIGNAL ;
    PORT
      LAYER M4 ;
        RECT 388.608 219.600 388.800 219.624 ;
    END
  END result[434]
  PIN result[435]
    DIRECTION OUTPUT ;
    USE SIGNAL ;
    PORT
      LAYER M4 ;
        RECT 388.608 220.080 388.800 220.104 ;
    END
  END result[435]
  PIN result[436]
    DIRECTION OUTPUT ;
    USE SIGNAL ;
    PORT
      LAYER M4 ;
        RECT 388.608 220.608 388.800 220.632 ;
    END
  END result[436]
  PIN result[437]
    DIRECTION OUTPUT ;
    USE SIGNAL ;
    PORT
      LAYER M4 ;
        RECT 388.608 221.088 388.800 221.112 ;
    END
  END result[437]
  PIN result[438]
    DIRECTION OUTPUT ;
    USE SIGNAL ;
    PORT
      LAYER M4 ;
        RECT 388.608 221.616 388.800 221.640 ;
    END
  END result[438]
  PIN result[439]
    DIRECTION OUTPUT ;
    USE SIGNAL ;
    PORT
      LAYER M4 ;
        RECT 388.608 222.096 388.800 222.120 ;
    END
  END result[439]
  PIN result[440]
    DIRECTION OUTPUT ;
    USE SIGNAL ;
    PORT
      LAYER M4 ;
        RECT 388.608 222.576 388.800 222.600 ;
    END
  END result[440]
  PIN result[441]
    DIRECTION OUTPUT ;
    USE SIGNAL ;
    PORT
      LAYER M4 ;
        RECT 388.608 223.104 388.800 223.128 ;
    END
  END result[441]
  PIN result[442]
    DIRECTION OUTPUT ;
    USE SIGNAL ;
    PORT
      LAYER M4 ;
        RECT 388.608 223.584 388.800 223.608 ;
    END
  END result[442]
  PIN result[443]
    DIRECTION OUTPUT ;
    USE SIGNAL ;
    PORT
      LAYER M4 ;
        RECT 388.608 224.112 388.800 224.136 ;
    END
  END result[443]
  PIN result[444]
    DIRECTION OUTPUT ;
    USE SIGNAL ;
    PORT
      LAYER M4 ;
        RECT 388.608 224.592 388.800 224.616 ;
    END
  END result[444]
  PIN result[445]
    DIRECTION OUTPUT ;
    USE SIGNAL ;
    PORT
      LAYER M4 ;
        RECT 388.608 225.120 388.800 225.144 ;
    END
  END result[445]
  PIN result[446]
    DIRECTION OUTPUT ;
    USE SIGNAL ;
    PORT
      LAYER M4 ;
        RECT 388.608 225.600 388.800 225.624 ;
    END
  END result[446]
  PIN result[447]
    DIRECTION OUTPUT ;
    USE SIGNAL ;
    PORT
      LAYER M4 ;
        RECT 388.608 226.080 388.800 226.104 ;
    END
  END result[447]
  PIN result[448]
    DIRECTION OUTPUT ;
    USE SIGNAL ;
    PORT
      LAYER M4 ;
        RECT 388.608 226.608 388.800 226.632 ;
    END
  END result[448]
  PIN result[449]
    DIRECTION OUTPUT ;
    USE SIGNAL ;
    PORT
      LAYER M4 ;
        RECT 388.608 227.088 388.800 227.112 ;
    END
  END result[449]
  PIN result[450]
    DIRECTION OUTPUT ;
    USE SIGNAL ;
    PORT
      LAYER M4 ;
        RECT 388.608 227.616 388.800 227.640 ;
    END
  END result[450]
  PIN result[451]
    DIRECTION OUTPUT ;
    USE SIGNAL ;
    PORT
      LAYER M4 ;
        RECT 388.608 228.096 388.800 228.120 ;
    END
  END result[451]
  PIN result[452]
    DIRECTION OUTPUT ;
    USE SIGNAL ;
    PORT
      LAYER M4 ;
        RECT 388.608 228.576 388.800 228.600 ;
    END
  END result[452]
  PIN result[453]
    DIRECTION OUTPUT ;
    USE SIGNAL ;
    PORT
      LAYER M4 ;
        RECT 388.608 229.104 388.800 229.128 ;
    END
  END result[453]
  PIN result[454]
    DIRECTION OUTPUT ;
    USE SIGNAL ;
    PORT
      LAYER M4 ;
        RECT 388.608 229.584 388.800 229.608 ;
    END
  END result[454]
  PIN result[455]
    DIRECTION OUTPUT ;
    USE SIGNAL ;
    PORT
      LAYER M4 ;
        RECT 388.608 230.112 388.800 230.136 ;
    END
  END result[455]
  PIN result[456]
    DIRECTION OUTPUT ;
    USE SIGNAL ;
    PORT
      LAYER M4 ;
        RECT 388.608 230.592 388.800 230.616 ;
    END
  END result[456]
  PIN result[457]
    DIRECTION OUTPUT ;
    USE SIGNAL ;
    PORT
      LAYER M4 ;
        RECT 388.608 231.072 388.800 231.096 ;
    END
  END result[457]
  PIN result[458]
    DIRECTION OUTPUT ;
    USE SIGNAL ;
    PORT
      LAYER M4 ;
        RECT 388.608 231.600 388.800 231.624 ;
    END
  END result[458]
  PIN result[459]
    DIRECTION OUTPUT ;
    USE SIGNAL ;
    PORT
      LAYER M4 ;
        RECT 388.608 232.080 388.800 232.104 ;
    END
  END result[459]
  PIN result[460]
    DIRECTION OUTPUT ;
    USE SIGNAL ;
    PORT
      LAYER M4 ;
        RECT 388.608 232.608 388.800 232.632 ;
    END
  END result[460]
  PIN result[461]
    DIRECTION OUTPUT ;
    USE SIGNAL ;
    PORT
      LAYER M4 ;
        RECT 388.608 233.088 388.800 233.112 ;
    END
  END result[461]
  PIN result[462]
    DIRECTION OUTPUT ;
    USE SIGNAL ;
    PORT
      LAYER M4 ;
        RECT 388.608 233.568 388.800 233.592 ;
    END
  END result[462]
  PIN result[463]
    DIRECTION OUTPUT ;
    USE SIGNAL ;
    PORT
      LAYER M4 ;
        RECT 388.608 234.096 388.800 234.120 ;
    END
  END result[463]
  PIN result[464]
    DIRECTION OUTPUT ;
    USE SIGNAL ;
    PORT
      LAYER M4 ;
        RECT 388.608 234.576 388.800 234.600 ;
    END
  END result[464]
  PIN result[465]
    DIRECTION OUTPUT ;
    USE SIGNAL ;
    PORT
      LAYER M4 ;
        RECT 388.608 235.104 388.800 235.128 ;
    END
  END result[465]
  PIN result[466]
    DIRECTION OUTPUT ;
    USE SIGNAL ;
    PORT
      LAYER M4 ;
        RECT 388.608 235.584 388.800 235.608 ;
    END
  END result[466]
  PIN result[467]
    DIRECTION OUTPUT ;
    USE SIGNAL ;
    PORT
      LAYER M4 ;
        RECT 388.608 236.064 388.800 236.088 ;
    END
  END result[467]
  PIN result[468]
    DIRECTION OUTPUT ;
    USE SIGNAL ;
    PORT
      LAYER M4 ;
        RECT 388.608 236.592 388.800 236.616 ;
    END
  END result[468]
  PIN result[469]
    DIRECTION OUTPUT ;
    USE SIGNAL ;
    PORT
      LAYER M4 ;
        RECT 388.608 237.072 388.800 237.096 ;
    END
  END result[469]
  PIN result[470]
    DIRECTION OUTPUT ;
    USE SIGNAL ;
    PORT
      LAYER M4 ;
        RECT 388.608 237.600 388.800 237.624 ;
    END
  END result[470]
  PIN result[471]
    DIRECTION OUTPUT ;
    USE SIGNAL ;
    PORT
      LAYER M4 ;
        RECT 388.608 238.080 388.800 238.104 ;
    END
  END result[471]
  PIN result[472]
    DIRECTION OUTPUT ;
    USE SIGNAL ;
    PORT
      LAYER M4 ;
        RECT 388.608 238.560 388.800 238.584 ;
    END
  END result[472]
  PIN result[473]
    DIRECTION OUTPUT ;
    USE SIGNAL ;
    PORT
      LAYER M4 ;
        RECT 388.608 239.088 388.800 239.112 ;
    END
  END result[473]
  PIN result[474]
    DIRECTION OUTPUT ;
    USE SIGNAL ;
    PORT
      LAYER M4 ;
        RECT 388.608 239.568 388.800 239.592 ;
    END
  END result[474]
  PIN result[475]
    DIRECTION OUTPUT ;
    USE SIGNAL ;
    PORT
      LAYER M4 ;
        RECT 388.608 240.096 388.800 240.120 ;
    END
  END result[475]
  PIN result[476]
    DIRECTION OUTPUT ;
    USE SIGNAL ;
    PORT
      LAYER M4 ;
        RECT 388.608 240.576 388.800 240.600 ;
    END
  END result[476]
  PIN result[477]
    DIRECTION OUTPUT ;
    USE SIGNAL ;
    PORT
      LAYER M4 ;
        RECT 388.608 241.056 388.800 241.080 ;
    END
  END result[477]
  PIN result[478]
    DIRECTION OUTPUT ;
    USE SIGNAL ;
    PORT
      LAYER M4 ;
        RECT 388.608 241.584 388.800 241.608 ;
    END
  END result[478]
  PIN result[479]
    DIRECTION OUTPUT ;
    USE SIGNAL ;
    PORT
      LAYER M4 ;
        RECT 388.608 242.064 388.800 242.088 ;
    END
  END result[479]
  PIN result[480]
    DIRECTION OUTPUT ;
    USE SIGNAL ;
    PORT
      LAYER M4 ;
        RECT 388.608 242.592 388.800 242.616 ;
    END
  END result[480]
  PIN result[481]
    DIRECTION OUTPUT ;
    USE SIGNAL ;
    PORT
      LAYER M4 ;
        RECT 388.608 243.072 388.800 243.096 ;
    END
  END result[481]
  PIN result[482]
    DIRECTION OUTPUT ;
    USE SIGNAL ;
    PORT
      LAYER M4 ;
        RECT 388.608 243.552 388.800 243.576 ;
    END
  END result[482]
  PIN result[483]
    DIRECTION OUTPUT ;
    USE SIGNAL ;
    PORT
      LAYER M4 ;
        RECT 388.608 244.080 388.800 244.104 ;
    END
  END result[483]
  PIN result[484]
    DIRECTION OUTPUT ;
    USE SIGNAL ;
    PORT
      LAYER M4 ;
        RECT 388.608 244.560 388.800 244.584 ;
    END
  END result[484]
  PIN result[485]
    DIRECTION OUTPUT ;
    USE SIGNAL ;
    PORT
      LAYER M4 ;
        RECT 388.608 245.088 388.800 245.112 ;
    END
  END result[485]
  PIN result[486]
    DIRECTION OUTPUT ;
    USE SIGNAL ;
    PORT
      LAYER M4 ;
        RECT 388.608 245.568 388.800 245.592 ;
    END
  END result[486]
  PIN result[487]
    DIRECTION OUTPUT ;
    USE SIGNAL ;
    PORT
      LAYER M4 ;
        RECT 388.608 246.048 388.800 246.072 ;
    END
  END result[487]
  PIN result[488]
    DIRECTION OUTPUT ;
    USE SIGNAL ;
    PORT
      LAYER M4 ;
        RECT 388.608 246.576 388.800 246.600 ;
    END
  END result[488]
  PIN result[489]
    DIRECTION OUTPUT ;
    USE SIGNAL ;
    PORT
      LAYER M4 ;
        RECT 388.608 247.056 388.800 247.080 ;
    END
  END result[489]
  PIN result[490]
    DIRECTION OUTPUT ;
    USE SIGNAL ;
    PORT
      LAYER M4 ;
        RECT 388.608 247.584 388.800 247.608 ;
    END
  END result[490]
  PIN result[491]
    DIRECTION OUTPUT ;
    USE SIGNAL ;
    PORT
      LAYER M4 ;
        RECT 388.608 248.064 388.800 248.088 ;
    END
  END result[491]
  PIN result[492]
    DIRECTION OUTPUT ;
    USE SIGNAL ;
    PORT
      LAYER M4 ;
        RECT 388.608 248.544 388.800 248.568 ;
    END
  END result[492]
  PIN result[493]
    DIRECTION OUTPUT ;
    USE SIGNAL ;
    PORT
      LAYER M4 ;
        RECT 388.608 249.072 388.800 249.096 ;
    END
  END result[493]
  PIN result[494]
    DIRECTION OUTPUT ;
    USE SIGNAL ;
    PORT
      LAYER M4 ;
        RECT 388.608 249.552 388.800 249.576 ;
    END
  END result[494]
  PIN result[495]
    DIRECTION OUTPUT ;
    USE SIGNAL ;
    PORT
      LAYER M4 ;
        RECT 388.608 250.080 388.800 250.104 ;
    END
  END result[495]
  PIN result[496]
    DIRECTION OUTPUT ;
    USE SIGNAL ;
    PORT
      LAYER M4 ;
        RECT 388.608 250.560 388.800 250.584 ;
    END
  END result[496]
  PIN result[497]
    DIRECTION OUTPUT ;
    USE SIGNAL ;
    PORT
      LAYER M4 ;
        RECT 388.608 251.040 388.800 251.064 ;
    END
  END result[497]
  PIN result[498]
    DIRECTION OUTPUT ;
    USE SIGNAL ;
    PORT
      LAYER M4 ;
        RECT 388.608 251.568 388.800 251.592 ;
    END
  END result[498]
  PIN result[499]
    DIRECTION OUTPUT ;
    USE SIGNAL ;
    PORT
      LAYER M4 ;
        RECT 388.608 252.048 388.800 252.072 ;
    END
  END result[499]
  PIN result[500]
    DIRECTION OUTPUT ;
    USE SIGNAL ;
    PORT
      LAYER M4 ;
        RECT 388.608 252.576 388.800 252.600 ;
    END
  END result[500]
  PIN result[501]
    DIRECTION OUTPUT ;
    USE SIGNAL ;
    PORT
      LAYER M4 ;
        RECT 388.608 253.056 388.800 253.080 ;
    END
  END result[501]
  PIN result[502]
    DIRECTION OUTPUT ;
    USE SIGNAL ;
    PORT
      LAYER M4 ;
        RECT 388.608 253.536 388.800 253.560 ;
    END
  END result[502]
  PIN result[503]
    DIRECTION OUTPUT ;
    USE SIGNAL ;
    PORT
      LAYER M4 ;
        RECT 388.608 254.064 388.800 254.088 ;
    END
  END result[503]
  PIN result[504]
    DIRECTION OUTPUT ;
    USE SIGNAL ;
    PORT
      LAYER M4 ;
        RECT 388.608 254.544 388.800 254.568 ;
    END
  END result[504]
  PIN result[505]
    DIRECTION OUTPUT ;
    USE SIGNAL ;
    PORT
      LAYER M4 ;
        RECT 388.608 255.072 388.800 255.096 ;
    END
  END result[505]
  PIN result[506]
    DIRECTION OUTPUT ;
    USE SIGNAL ;
    PORT
      LAYER M4 ;
        RECT 388.608 255.552 388.800 255.576 ;
    END
  END result[506]
  PIN result[507]
    DIRECTION OUTPUT ;
    USE SIGNAL ;
    PORT
      LAYER M4 ;
        RECT 388.608 256.032 388.800 256.056 ;
    END
  END result[507]
  PIN result[508]
    DIRECTION OUTPUT ;
    USE SIGNAL ;
    PORT
      LAYER M4 ;
        RECT 388.608 256.560 388.800 256.584 ;
    END
  END result[508]
  PIN result[509]
    DIRECTION OUTPUT ;
    USE SIGNAL ;
    PORT
      LAYER M4 ;
        RECT 388.608 257.040 388.800 257.064 ;
    END
  END result[509]
  PIN result[510]
    DIRECTION OUTPUT ;
    USE SIGNAL ;
    PORT
      LAYER M4 ;
        RECT 388.608 257.568 388.800 257.592 ;
    END
  END result[510]
  PIN result[511]
    DIRECTION OUTPUT ;
    USE SIGNAL ;
    PORT
      LAYER M4 ;
        RECT 388.608 258.048 388.800 258.072 ;
    END
  END result[511]
  PIN result[512]
    DIRECTION OUTPUT ;
    USE SIGNAL ;
    PORT
      LAYER M4 ;
        RECT 388.608 258.528 388.800 258.552 ;
    END
  END result[512]
  PIN result[513]
    DIRECTION OUTPUT ;
    USE SIGNAL ;
    PORT
      LAYER M4 ;
        RECT 388.608 259.056 388.800 259.080 ;
    END
  END result[513]
  PIN result[514]
    DIRECTION OUTPUT ;
    USE SIGNAL ;
    PORT
      LAYER M4 ;
        RECT 388.608 259.536 388.800 259.560 ;
    END
  END result[514]
  PIN result[515]
    DIRECTION OUTPUT ;
    USE SIGNAL ;
    PORT
      LAYER M4 ;
        RECT 388.608 260.064 388.800 260.088 ;
    END
  END result[515]
  PIN result[516]
    DIRECTION OUTPUT ;
    USE SIGNAL ;
    PORT
      LAYER M4 ;
        RECT 388.608 260.544 388.800 260.568 ;
    END
  END result[516]
  PIN result[517]
    DIRECTION OUTPUT ;
    USE SIGNAL ;
    PORT
      LAYER M4 ;
        RECT 388.608 261.024 388.800 261.048 ;
    END
  END result[517]
  PIN result[518]
    DIRECTION OUTPUT ;
    USE SIGNAL ;
    PORT
      LAYER M4 ;
        RECT 388.608 261.552 388.800 261.576 ;
    END
  END result[518]
  PIN result[519]
    DIRECTION OUTPUT ;
    USE SIGNAL ;
    PORT
      LAYER M4 ;
        RECT 388.608 262.032 388.800 262.056 ;
    END
  END result[519]
  PIN result[520]
    DIRECTION OUTPUT ;
    USE SIGNAL ;
    PORT
      LAYER M4 ;
        RECT 388.608 262.560 388.800 262.584 ;
    END
  END result[520]
  PIN result[521]
    DIRECTION OUTPUT ;
    USE SIGNAL ;
    PORT
      LAYER M4 ;
        RECT 388.608 263.040 388.800 263.064 ;
    END
  END result[521]
  PIN result[522]
    DIRECTION OUTPUT ;
    USE SIGNAL ;
    PORT
      LAYER M4 ;
        RECT 388.608 263.568 388.800 263.592 ;
    END
  END result[522]
  PIN result[523]
    DIRECTION OUTPUT ;
    USE SIGNAL ;
    PORT
      LAYER M4 ;
        RECT 388.608 264.048 388.800 264.072 ;
    END
  END result[523]
  PIN result[524]
    DIRECTION OUTPUT ;
    USE SIGNAL ;
    PORT
      LAYER M4 ;
        RECT 388.608 264.528 388.800 264.552 ;
    END
  END result[524]
  PIN result[525]
    DIRECTION OUTPUT ;
    USE SIGNAL ;
    PORT
      LAYER M4 ;
        RECT 388.608 265.056 388.800 265.080 ;
    END
  END result[525]
  PIN result[526]
    DIRECTION OUTPUT ;
    USE SIGNAL ;
    PORT
      LAYER M4 ;
        RECT 388.608 265.536 388.800 265.560 ;
    END
  END result[526]
  PIN result[527]
    DIRECTION OUTPUT ;
    USE SIGNAL ;
    PORT
      LAYER M4 ;
        RECT 388.608 266.064 388.800 266.088 ;
    END
  END result[527]
  PIN result[528]
    DIRECTION OUTPUT ;
    USE SIGNAL ;
    PORT
      LAYER M4 ;
        RECT 388.608 266.544 388.800 266.568 ;
    END
  END result[528]
  PIN result[529]
    DIRECTION OUTPUT ;
    USE SIGNAL ;
    PORT
      LAYER M4 ;
        RECT 388.608 267.024 388.800 267.048 ;
    END
  END result[529]
  PIN result[530]
    DIRECTION OUTPUT ;
    USE SIGNAL ;
    PORT
      LAYER M4 ;
        RECT 388.608 267.552 388.800 267.576 ;
    END
  END result[530]
  PIN result[531]
    DIRECTION OUTPUT ;
    USE SIGNAL ;
    PORT
      LAYER M4 ;
        RECT 388.608 268.032 388.800 268.056 ;
    END
  END result[531]
  PIN result[532]
    DIRECTION OUTPUT ;
    USE SIGNAL ;
    PORT
      LAYER M4 ;
        RECT 388.608 268.560 388.800 268.584 ;
    END
  END result[532]
  PIN result[533]
    DIRECTION OUTPUT ;
    USE SIGNAL ;
    PORT
      LAYER M4 ;
        RECT 388.608 269.040 388.800 269.064 ;
    END
  END result[533]
  PIN result[534]
    DIRECTION OUTPUT ;
    USE SIGNAL ;
    PORT
      LAYER M4 ;
        RECT 388.608 269.520 388.800 269.544 ;
    END
  END result[534]
  PIN result[535]
    DIRECTION OUTPUT ;
    USE SIGNAL ;
    PORT
      LAYER M4 ;
        RECT 388.608 270.048 388.800 270.072 ;
    END
  END result[535]
  PIN result[536]
    DIRECTION OUTPUT ;
    USE SIGNAL ;
    PORT
      LAYER M4 ;
        RECT 388.608 270.528 388.800 270.552 ;
    END
  END result[536]
  PIN result[537]
    DIRECTION OUTPUT ;
    USE SIGNAL ;
    PORT
      LAYER M4 ;
        RECT 388.608 271.056 388.800 271.080 ;
    END
  END result[537]
  PIN result[538]
    DIRECTION OUTPUT ;
    USE SIGNAL ;
    PORT
      LAYER M4 ;
        RECT 388.608 271.536 388.800 271.560 ;
    END
  END result[538]
  PIN result[539]
    DIRECTION OUTPUT ;
    USE SIGNAL ;
    PORT
      LAYER M4 ;
        RECT 388.608 272.016 388.800 272.040 ;
    END
  END result[539]
  PIN result[540]
    DIRECTION OUTPUT ;
    USE SIGNAL ;
    PORT
      LAYER M4 ;
        RECT 388.608 272.544 388.800 272.568 ;
    END
  END result[540]
  PIN result[541]
    DIRECTION OUTPUT ;
    USE SIGNAL ;
    PORT
      LAYER M4 ;
        RECT 388.608 273.024 388.800 273.048 ;
    END
  END result[541]
  PIN result[542]
    DIRECTION OUTPUT ;
    USE SIGNAL ;
    PORT
      LAYER M4 ;
        RECT 388.608 273.552 388.800 273.576 ;
    END
  END result[542]
  PIN result[543]
    DIRECTION OUTPUT ;
    USE SIGNAL ;
    PORT
      LAYER M4 ;
        RECT 388.608 274.032 388.800 274.056 ;
    END
  END result[543]
  PIN result[544]
    DIRECTION OUTPUT ;
    USE SIGNAL ;
    PORT
      LAYER M4 ;
        RECT 388.608 274.512 388.800 274.536 ;
    END
  END result[544]
  PIN result[545]
    DIRECTION OUTPUT ;
    USE SIGNAL ;
    PORT
      LAYER M4 ;
        RECT 388.608 275.040 388.800 275.064 ;
    END
  END result[545]
  PIN result[546]
    DIRECTION OUTPUT ;
    USE SIGNAL ;
    PORT
      LAYER M4 ;
        RECT 388.608 275.520 388.800 275.544 ;
    END
  END result[546]
  PIN result[547]
    DIRECTION OUTPUT ;
    USE SIGNAL ;
    PORT
      LAYER M4 ;
        RECT 388.608 276.048 388.800 276.072 ;
    END
  END result[547]
  PIN result[548]
    DIRECTION OUTPUT ;
    USE SIGNAL ;
    PORT
      LAYER M4 ;
        RECT 388.608 276.528 388.800 276.552 ;
    END
  END result[548]
  PIN result[549]
    DIRECTION OUTPUT ;
    USE SIGNAL ;
    PORT
      LAYER M4 ;
        RECT 388.608 277.008 388.800 277.032 ;
    END
  END result[549]
  PIN result[550]
    DIRECTION OUTPUT ;
    USE SIGNAL ;
    PORT
      LAYER M4 ;
        RECT 388.608 277.536 388.800 277.560 ;
    END
  END result[550]
  PIN result[551]
    DIRECTION OUTPUT ;
    USE SIGNAL ;
    PORT
      LAYER M4 ;
        RECT 388.608 278.016 388.800 278.040 ;
    END
  END result[551]
  PIN result[552]
    DIRECTION OUTPUT ;
    USE SIGNAL ;
    PORT
      LAYER M4 ;
        RECT 388.608 278.544 388.800 278.568 ;
    END
  END result[552]
  PIN result[553]
    DIRECTION OUTPUT ;
    USE SIGNAL ;
    PORT
      LAYER M4 ;
        RECT 388.608 279.024 388.800 279.048 ;
    END
  END result[553]
  PIN result[554]
    DIRECTION OUTPUT ;
    USE SIGNAL ;
    PORT
      LAYER M4 ;
        RECT 388.608 279.504 388.800 279.528 ;
    END
  END result[554]
  PIN result[555]
    DIRECTION OUTPUT ;
    USE SIGNAL ;
    PORT
      LAYER M4 ;
        RECT 388.608 280.032 388.800 280.056 ;
    END
  END result[555]
  PIN result[556]
    DIRECTION OUTPUT ;
    USE SIGNAL ;
    PORT
      LAYER M4 ;
        RECT 388.608 280.512 388.800 280.536 ;
    END
  END result[556]
  PIN result[557]
    DIRECTION OUTPUT ;
    USE SIGNAL ;
    PORT
      LAYER M4 ;
        RECT 388.608 281.040 388.800 281.064 ;
    END
  END result[557]
  PIN result[558]
    DIRECTION OUTPUT ;
    USE SIGNAL ;
    PORT
      LAYER M4 ;
        RECT 388.608 281.520 388.800 281.544 ;
    END
  END result[558]
  PIN result[559]
    DIRECTION OUTPUT ;
    USE SIGNAL ;
    PORT
      LAYER M4 ;
        RECT 388.608 282.000 388.800 282.024 ;
    END
  END result[559]
  PIN result[560]
    DIRECTION OUTPUT ;
    USE SIGNAL ;
    PORT
      LAYER M4 ;
        RECT 388.608 282.528 388.800 282.552 ;
    END
  END result[560]
  PIN result[561]
    DIRECTION OUTPUT ;
    USE SIGNAL ;
    PORT
      LAYER M4 ;
        RECT 388.608 283.008 388.800 283.032 ;
    END
  END result[561]
  PIN result[562]
    DIRECTION OUTPUT ;
    USE SIGNAL ;
    PORT
      LAYER M4 ;
        RECT 388.608 283.536 388.800 283.560 ;
    END
  END result[562]
  PIN result[563]
    DIRECTION OUTPUT ;
    USE SIGNAL ;
    PORT
      LAYER M4 ;
        RECT 388.608 284.016 388.800 284.040 ;
    END
  END result[563]
  PIN result[564]
    DIRECTION OUTPUT ;
    USE SIGNAL ;
    PORT
      LAYER M4 ;
        RECT 388.608 284.496 388.800 284.520 ;
    END
  END result[564]
  PIN result[565]
    DIRECTION OUTPUT ;
    USE SIGNAL ;
    PORT
      LAYER M4 ;
        RECT 388.608 285.024 388.800 285.048 ;
    END
  END result[565]
  PIN result[566]
    DIRECTION OUTPUT ;
    USE SIGNAL ;
    PORT
      LAYER M4 ;
        RECT 388.608 285.504 388.800 285.528 ;
    END
  END result[566]
  PIN result[567]
    DIRECTION OUTPUT ;
    USE SIGNAL ;
    PORT
      LAYER M4 ;
        RECT 388.608 286.032 388.800 286.056 ;
    END
  END result[567]
  PIN result[568]
    DIRECTION OUTPUT ;
    USE SIGNAL ;
    PORT
      LAYER M4 ;
        RECT 388.608 286.512 388.800 286.536 ;
    END
  END result[568]
  PIN result[569]
    DIRECTION OUTPUT ;
    USE SIGNAL ;
    PORT
      LAYER M4 ;
        RECT 388.608 286.992 388.800 287.016 ;
    END
  END result[569]
  PIN result[570]
    DIRECTION OUTPUT ;
    USE SIGNAL ;
    PORT
      LAYER M4 ;
        RECT 388.608 287.520 388.800 287.544 ;
    END
  END result[570]
  PIN result[571]
    DIRECTION OUTPUT ;
    USE SIGNAL ;
    PORT
      LAYER M4 ;
        RECT 388.608 288.000 388.800 288.024 ;
    END
  END result[571]
  PIN result[572]
    DIRECTION OUTPUT ;
    USE SIGNAL ;
    PORT
      LAYER M4 ;
        RECT 388.608 288.528 388.800 288.552 ;
    END
  END result[572]
  PIN result[573]
    DIRECTION OUTPUT ;
    USE SIGNAL ;
    PORT
      LAYER M4 ;
        RECT 388.608 289.008 388.800 289.032 ;
    END
  END result[573]
  PIN result[574]
    DIRECTION OUTPUT ;
    USE SIGNAL ;
    PORT
      LAYER M4 ;
        RECT 388.608 289.488 388.800 289.512 ;
    END
  END result[574]
  PIN result[575]
    DIRECTION OUTPUT ;
    USE SIGNAL ;
    PORT
      LAYER M4 ;
        RECT 388.608 290.016 388.800 290.040 ;
    END
  END result[575]
  PIN result[576]
    DIRECTION OUTPUT ;
    USE SIGNAL ;
    PORT
      LAYER M4 ;
        RECT 388.608 290.496 388.800 290.520 ;
    END
  END result[576]
  PIN result[577]
    DIRECTION OUTPUT ;
    USE SIGNAL ;
    PORT
      LAYER M4 ;
        RECT 388.608 291.024 388.800 291.048 ;
    END
  END result[577]
  PIN result[578]
    DIRECTION OUTPUT ;
    USE SIGNAL ;
    PORT
      LAYER M4 ;
        RECT 388.608 291.504 388.800 291.528 ;
    END
  END result[578]
  PIN result[579]
    DIRECTION OUTPUT ;
    USE SIGNAL ;
    PORT
      LAYER M4 ;
        RECT 388.608 291.984 388.800 292.008 ;
    END
  END result[579]
  PIN result[580]
    DIRECTION OUTPUT ;
    USE SIGNAL ;
    PORT
      LAYER M4 ;
        RECT 388.608 292.512 388.800 292.536 ;
    END
  END result[580]
  PIN result[581]
    DIRECTION OUTPUT ;
    USE SIGNAL ;
    PORT
      LAYER M4 ;
        RECT 388.608 292.992 388.800 293.016 ;
    END
  END result[581]
  PIN result[582]
    DIRECTION OUTPUT ;
    USE SIGNAL ;
    PORT
      LAYER M4 ;
        RECT 388.608 293.520 388.800 293.544 ;
    END
  END result[582]
  PIN result[583]
    DIRECTION OUTPUT ;
    USE SIGNAL ;
    PORT
      LAYER M4 ;
        RECT 388.608 294.000 388.800 294.024 ;
    END
  END result[583]
  PIN result[584]
    DIRECTION OUTPUT ;
    USE SIGNAL ;
    PORT
      LAYER M4 ;
        RECT 388.608 294.480 388.800 294.504 ;
    END
  END result[584]
  PIN result[585]
    DIRECTION OUTPUT ;
    USE SIGNAL ;
    PORT
      LAYER M4 ;
        RECT 388.608 295.008 388.800 295.032 ;
    END
  END result[585]
  PIN result[586]
    DIRECTION OUTPUT ;
    USE SIGNAL ;
    PORT
      LAYER M4 ;
        RECT 388.608 295.488 388.800 295.512 ;
    END
  END result[586]
  PIN result[587]
    DIRECTION OUTPUT ;
    USE SIGNAL ;
    PORT
      LAYER M4 ;
        RECT 388.608 296.016 388.800 296.040 ;
    END
  END result[587]
  PIN result[588]
    DIRECTION OUTPUT ;
    USE SIGNAL ;
    PORT
      LAYER M4 ;
        RECT 388.608 296.496 388.800 296.520 ;
    END
  END result[588]
  PIN result[589]
    DIRECTION OUTPUT ;
    USE SIGNAL ;
    PORT
      LAYER M4 ;
        RECT 388.608 296.976 388.800 297.000 ;
    END
  END result[589]
  PIN result[590]
    DIRECTION OUTPUT ;
    USE SIGNAL ;
    PORT
      LAYER M4 ;
        RECT 388.608 297.504 388.800 297.528 ;
    END
  END result[590]
  PIN result[591]
    DIRECTION OUTPUT ;
    USE SIGNAL ;
    PORT
      LAYER M4 ;
        RECT 388.608 297.984 388.800 298.008 ;
    END
  END result[591]
  PIN result[592]
    DIRECTION OUTPUT ;
    USE SIGNAL ;
    PORT
      LAYER M4 ;
        RECT 388.608 298.512 388.800 298.536 ;
    END
  END result[592]
  PIN result[593]
    DIRECTION OUTPUT ;
    USE SIGNAL ;
    PORT
      LAYER M4 ;
        RECT 388.608 298.992 388.800 299.016 ;
    END
  END result[593]
  PIN result[594]
    DIRECTION OUTPUT ;
    USE SIGNAL ;
    PORT
      LAYER M4 ;
        RECT 388.608 299.472 388.800 299.496 ;
    END
  END result[594]
  PIN result[595]
    DIRECTION OUTPUT ;
    USE SIGNAL ;
    PORT
      LAYER M4 ;
        RECT 388.608 300.000 388.800 300.024 ;
    END
  END result[595]
  PIN result[596]
    DIRECTION OUTPUT ;
    USE SIGNAL ;
    PORT
      LAYER M4 ;
        RECT 388.608 300.480 388.800 300.504 ;
    END
  END result[596]
  PIN result[597]
    DIRECTION OUTPUT ;
    USE SIGNAL ;
    PORT
      LAYER M4 ;
        RECT 388.608 301.008 388.800 301.032 ;
    END
  END result[597]
  PIN result[598]
    DIRECTION OUTPUT ;
    USE SIGNAL ;
    PORT
      LAYER M4 ;
        RECT 388.608 301.488 388.800 301.512 ;
    END
  END result[598]
  PIN result[599]
    DIRECTION OUTPUT ;
    USE SIGNAL ;
    PORT
      LAYER M4 ;
        RECT 388.608 302.016 388.800 302.040 ;
    END
  END result[599]
  PIN result[600]
    DIRECTION OUTPUT ;
    USE SIGNAL ;
    PORT
      LAYER M4 ;
        RECT 388.608 302.496 388.800 302.520 ;
    END
  END result[600]
  PIN result[601]
    DIRECTION OUTPUT ;
    USE SIGNAL ;
    PORT
      LAYER M4 ;
        RECT 388.608 302.976 388.800 303.000 ;
    END
  END result[601]
  PIN result[602]
    DIRECTION OUTPUT ;
    USE SIGNAL ;
    PORT
      LAYER M4 ;
        RECT 388.608 303.504 388.800 303.528 ;
    END
  END result[602]
  PIN result[603]
    DIRECTION OUTPUT ;
    USE SIGNAL ;
    PORT
      LAYER M4 ;
        RECT 388.608 303.984 388.800 304.008 ;
    END
  END result[603]
  PIN result[604]
    DIRECTION OUTPUT ;
    USE SIGNAL ;
    PORT
      LAYER M4 ;
        RECT 388.608 304.512 388.800 304.536 ;
    END
  END result[604]
  PIN result[605]
    DIRECTION OUTPUT ;
    USE SIGNAL ;
    PORT
      LAYER M4 ;
        RECT 388.608 304.992 388.800 305.016 ;
    END
  END result[605]
  PIN result[606]
    DIRECTION OUTPUT ;
    USE SIGNAL ;
    PORT
      LAYER M4 ;
        RECT 388.608 305.472 388.800 305.496 ;
    END
  END result[606]
  PIN result[607]
    DIRECTION OUTPUT ;
    USE SIGNAL ;
    PORT
      LAYER M4 ;
        RECT 388.608 306.000 388.800 306.024 ;
    END
  END result[607]
  PIN result[608]
    DIRECTION OUTPUT ;
    USE SIGNAL ;
    PORT
      LAYER M4 ;
        RECT 388.608 306.480 388.800 306.504 ;
    END
  END result[608]
  PIN result[609]
    DIRECTION OUTPUT ;
    USE SIGNAL ;
    PORT
      LAYER M4 ;
        RECT 388.608 307.008 388.800 307.032 ;
    END
  END result[609]
  PIN result[610]
    DIRECTION OUTPUT ;
    USE SIGNAL ;
    PORT
      LAYER M4 ;
        RECT 388.608 307.488 388.800 307.512 ;
    END
  END result[610]
  PIN result[611]
    DIRECTION OUTPUT ;
    USE SIGNAL ;
    PORT
      LAYER M4 ;
        RECT 388.608 307.968 388.800 307.992 ;
    END
  END result[611]
  PIN result[612]
    DIRECTION OUTPUT ;
    USE SIGNAL ;
    PORT
      LAYER M4 ;
        RECT 388.608 308.496 388.800 308.520 ;
    END
  END result[612]
  PIN result[613]
    DIRECTION OUTPUT ;
    USE SIGNAL ;
    PORT
      LAYER M4 ;
        RECT 388.608 308.976 388.800 309.000 ;
    END
  END result[613]
  PIN result[614]
    DIRECTION OUTPUT ;
    USE SIGNAL ;
    PORT
      LAYER M4 ;
        RECT 388.608 309.504 388.800 309.528 ;
    END
  END result[614]
  PIN result[615]
    DIRECTION OUTPUT ;
    USE SIGNAL ;
    PORT
      LAYER M4 ;
        RECT 388.608 309.984 388.800 310.008 ;
    END
  END result[615]
  PIN result[616]
    DIRECTION OUTPUT ;
    USE SIGNAL ;
    PORT
      LAYER M4 ;
        RECT 388.608 310.464 388.800 310.488 ;
    END
  END result[616]
  PIN result[617]
    DIRECTION OUTPUT ;
    USE SIGNAL ;
    PORT
      LAYER M4 ;
        RECT 388.608 310.992 388.800 311.016 ;
    END
  END result[617]
  PIN result[618]
    DIRECTION OUTPUT ;
    USE SIGNAL ;
    PORT
      LAYER M4 ;
        RECT 388.608 311.472 388.800 311.496 ;
    END
  END result[618]
  PIN result[619]
    DIRECTION OUTPUT ;
    USE SIGNAL ;
    PORT
      LAYER M4 ;
        RECT 388.608 312.000 388.800 312.024 ;
    END
  END result[619]
  PIN result[620]
    DIRECTION OUTPUT ;
    USE SIGNAL ;
    PORT
      LAYER M4 ;
        RECT 388.608 312.480 388.800 312.504 ;
    END
  END result[620]
  PIN result[621]
    DIRECTION OUTPUT ;
    USE SIGNAL ;
    PORT
      LAYER M4 ;
        RECT 388.608 312.960 388.800 312.984 ;
    END
  END result[621]
  PIN result[622]
    DIRECTION OUTPUT ;
    USE SIGNAL ;
    PORT
      LAYER M4 ;
        RECT 388.608 313.488 388.800 313.512 ;
    END
  END result[622]
  PIN result[623]
    DIRECTION OUTPUT ;
    USE SIGNAL ;
    PORT
      LAYER M4 ;
        RECT 388.608 313.968 388.800 313.992 ;
    END
  END result[623]
  PIN result[624]
    DIRECTION OUTPUT ;
    USE SIGNAL ;
    PORT
      LAYER M4 ;
        RECT 388.608 314.496 388.800 314.520 ;
    END
  END result[624]
  PIN result[625]
    DIRECTION OUTPUT ;
    USE SIGNAL ;
    PORT
      LAYER M4 ;
        RECT 388.608 314.976 388.800 315.000 ;
    END
  END result[625]
  PIN result[626]
    DIRECTION OUTPUT ;
    USE SIGNAL ;
    PORT
      LAYER M4 ;
        RECT 388.608 315.456 388.800 315.480 ;
    END
  END result[626]
  PIN result[627]
    DIRECTION OUTPUT ;
    USE SIGNAL ;
    PORT
      LAYER M4 ;
        RECT 388.608 315.984 388.800 316.008 ;
    END
  END result[627]
  PIN result[628]
    DIRECTION OUTPUT ;
    USE SIGNAL ;
    PORT
      LAYER M4 ;
        RECT 388.608 316.464 388.800 316.488 ;
    END
  END result[628]
  PIN result[629]
    DIRECTION OUTPUT ;
    USE SIGNAL ;
    PORT
      LAYER M4 ;
        RECT 388.608 316.992 388.800 317.016 ;
    END
  END result[629]
  PIN result[630]
    DIRECTION OUTPUT ;
    USE SIGNAL ;
    PORT
      LAYER M4 ;
        RECT 388.608 317.472 388.800 317.496 ;
    END
  END result[630]
  PIN result[631]
    DIRECTION OUTPUT ;
    USE SIGNAL ;
    PORT
      LAYER M4 ;
        RECT 388.608 317.952 388.800 317.976 ;
    END
  END result[631]
  PIN result[632]
    DIRECTION OUTPUT ;
    USE SIGNAL ;
    PORT
      LAYER M4 ;
        RECT 388.608 318.480 388.800 318.504 ;
    END
  END result[632]
  PIN result[633]
    DIRECTION OUTPUT ;
    USE SIGNAL ;
    PORT
      LAYER M4 ;
        RECT 388.608 318.960 388.800 318.984 ;
    END
  END result[633]
  PIN result[634]
    DIRECTION OUTPUT ;
    USE SIGNAL ;
    PORT
      LAYER M4 ;
        RECT 388.608 319.488 388.800 319.512 ;
    END
  END result[634]
  PIN result[635]
    DIRECTION OUTPUT ;
    USE SIGNAL ;
    PORT
      LAYER M4 ;
        RECT 388.608 319.968 388.800 319.992 ;
    END
  END result[635]
  PIN result[636]
    DIRECTION OUTPUT ;
    USE SIGNAL ;
    PORT
      LAYER M4 ;
        RECT 388.608 320.448 388.800 320.472 ;
    END
  END result[636]
  PIN result[637]
    DIRECTION OUTPUT ;
    USE SIGNAL ;
    PORT
      LAYER M4 ;
        RECT 388.608 320.976 388.800 321.000 ;
    END
  END result[637]
  PIN result[638]
    DIRECTION OUTPUT ;
    USE SIGNAL ;
    PORT
      LAYER M4 ;
        RECT 388.608 321.456 388.800 321.480 ;
    END
  END result[638]
  PIN result[639]
    DIRECTION OUTPUT ;
    USE SIGNAL ;
    PORT
      LAYER M4 ;
        RECT 388.608 321.984 388.800 322.008 ;
    END
  END result[639]
  PIN result[640]
    DIRECTION OUTPUT ;
    USE SIGNAL ;
    PORT
      LAYER M4 ;
        RECT 388.608 322.464 388.800 322.488 ;
    END
  END result[640]
  PIN result[641]
    DIRECTION OUTPUT ;
    USE SIGNAL ;
    PORT
      LAYER M4 ;
        RECT 388.608 322.944 388.800 322.968 ;
    END
  END result[641]
  PIN result[642]
    DIRECTION OUTPUT ;
    USE SIGNAL ;
    PORT
      LAYER M4 ;
        RECT 388.608 323.472 388.800 323.496 ;
    END
  END result[642]
  PIN result[643]
    DIRECTION OUTPUT ;
    USE SIGNAL ;
    PORT
      LAYER M4 ;
        RECT 388.608 323.952 388.800 323.976 ;
    END
  END result[643]
  PIN result[644]
    DIRECTION OUTPUT ;
    USE SIGNAL ;
    PORT
      LAYER M4 ;
        RECT 388.608 324.480 388.800 324.504 ;
    END
  END result[644]
  PIN result[645]
    DIRECTION OUTPUT ;
    USE SIGNAL ;
    PORT
      LAYER M4 ;
        RECT 388.608 324.960 388.800 324.984 ;
    END
  END result[645]
  PIN result[646]
    DIRECTION OUTPUT ;
    USE SIGNAL ;
    PORT
      LAYER M4 ;
        RECT 388.608 325.440 388.800 325.464 ;
    END
  END result[646]
  PIN result[647]
    DIRECTION OUTPUT ;
    USE SIGNAL ;
    PORT
      LAYER M4 ;
        RECT 388.608 325.968 388.800 325.992 ;
    END
  END result[647]
  PIN result[648]
    DIRECTION OUTPUT ;
    USE SIGNAL ;
    PORT
      LAYER M4 ;
        RECT 388.608 326.448 388.800 326.472 ;
    END
  END result[648]
  PIN result[649]
    DIRECTION OUTPUT ;
    USE SIGNAL ;
    PORT
      LAYER M4 ;
        RECT 388.608 326.976 388.800 327.000 ;
    END
  END result[649]
  PIN result[650]
    DIRECTION OUTPUT ;
    USE SIGNAL ;
    PORT
      LAYER M4 ;
        RECT 388.608 327.456 388.800 327.480 ;
    END
  END result[650]
  PIN result[651]
    DIRECTION OUTPUT ;
    USE SIGNAL ;
    PORT
      LAYER M4 ;
        RECT 388.608 327.936 388.800 327.960 ;
    END
  END result[651]
  PIN result[652]
    DIRECTION OUTPUT ;
    USE SIGNAL ;
    PORT
      LAYER M4 ;
        RECT 388.608 328.464 388.800 328.488 ;
    END
  END result[652]
  PIN result[653]
    DIRECTION OUTPUT ;
    USE SIGNAL ;
    PORT
      LAYER M4 ;
        RECT 388.608 328.944 388.800 328.968 ;
    END
  END result[653]
  PIN result[654]
    DIRECTION OUTPUT ;
    USE SIGNAL ;
    PORT
      LAYER M4 ;
        RECT 388.608 329.472 388.800 329.496 ;
    END
  END result[654]
  PIN result[655]
    DIRECTION OUTPUT ;
    USE SIGNAL ;
    PORT
      LAYER M4 ;
        RECT 388.608 329.952 388.800 329.976 ;
    END
  END result[655]
  PIN result[656]
    DIRECTION OUTPUT ;
    USE SIGNAL ;
    PORT
      LAYER M4 ;
        RECT 388.608 330.432 388.800 330.456 ;
    END
  END result[656]
  PIN result[657]
    DIRECTION OUTPUT ;
    USE SIGNAL ;
    PORT
      LAYER M4 ;
        RECT 388.608 330.960 388.800 330.984 ;
    END
  END result[657]
  PIN result[658]
    DIRECTION OUTPUT ;
    USE SIGNAL ;
    PORT
      LAYER M4 ;
        RECT 388.608 331.440 388.800 331.464 ;
    END
  END result[658]
  PIN result[659]
    DIRECTION OUTPUT ;
    USE SIGNAL ;
    PORT
      LAYER M4 ;
        RECT 388.608 331.968 388.800 331.992 ;
    END
  END result[659]
  PIN result[660]
    DIRECTION OUTPUT ;
    USE SIGNAL ;
    PORT
      LAYER M4 ;
        RECT 388.608 332.448 388.800 332.472 ;
    END
  END result[660]
  PIN result[661]
    DIRECTION OUTPUT ;
    USE SIGNAL ;
    PORT
      LAYER M4 ;
        RECT 388.608 332.928 388.800 332.952 ;
    END
  END result[661]
  PIN result[662]
    DIRECTION OUTPUT ;
    USE SIGNAL ;
    PORT
      LAYER M4 ;
        RECT 388.608 333.456 388.800 333.480 ;
    END
  END result[662]
  PIN result[663]
    DIRECTION OUTPUT ;
    USE SIGNAL ;
    PORT
      LAYER M4 ;
        RECT 388.608 333.936 388.800 333.960 ;
    END
  END result[663]
  PIN result[664]
    DIRECTION OUTPUT ;
    USE SIGNAL ;
    PORT
      LAYER M4 ;
        RECT 388.608 334.464 388.800 334.488 ;
    END
  END result[664]
  PIN result[665]
    DIRECTION OUTPUT ;
    USE SIGNAL ;
    PORT
      LAYER M4 ;
        RECT 388.608 334.944 388.800 334.968 ;
    END
  END result[665]
  PIN result[666]
    DIRECTION OUTPUT ;
    USE SIGNAL ;
    PORT
      LAYER M4 ;
        RECT 388.608 335.424 388.800 335.448 ;
    END
  END result[666]
  PIN result[667]
    DIRECTION OUTPUT ;
    USE SIGNAL ;
    PORT
      LAYER M4 ;
        RECT 388.608 335.952 388.800 335.976 ;
    END
  END result[667]
  PIN result[668]
    DIRECTION OUTPUT ;
    USE SIGNAL ;
    PORT
      LAYER M4 ;
        RECT 388.608 336.432 388.800 336.456 ;
    END
  END result[668]
  PIN result[669]
    DIRECTION OUTPUT ;
    USE SIGNAL ;
    PORT
      LAYER M4 ;
        RECT 388.608 336.960 388.800 336.984 ;
    END
  END result[669]
  PIN result[670]
    DIRECTION OUTPUT ;
    USE SIGNAL ;
    PORT
      LAYER M4 ;
        RECT 388.608 337.440 388.800 337.464 ;
    END
  END result[670]
  PIN result[671]
    DIRECTION OUTPUT ;
    USE SIGNAL ;
    PORT
      LAYER M4 ;
        RECT 388.608 337.920 388.800 337.944 ;
    END
  END result[671]
  PIN result[672]
    DIRECTION OUTPUT ;
    USE SIGNAL ;
    PORT
      LAYER M4 ;
        RECT 388.608 338.448 388.800 338.472 ;
    END
  END result[672]
  PIN result[673]
    DIRECTION OUTPUT ;
    USE SIGNAL ;
    PORT
      LAYER M4 ;
        RECT 388.608 338.928 388.800 338.952 ;
    END
  END result[673]
  PIN result[674]
    DIRECTION OUTPUT ;
    USE SIGNAL ;
    PORT
      LAYER M4 ;
        RECT 388.608 339.456 388.800 339.480 ;
    END
  END result[674]
  PIN result[675]
    DIRECTION OUTPUT ;
    USE SIGNAL ;
    PORT
      LAYER M4 ;
        RECT 388.608 339.936 388.800 339.960 ;
    END
  END result[675]
  PIN result[676]
    DIRECTION OUTPUT ;
    USE SIGNAL ;
    PORT
      LAYER M4 ;
        RECT 388.608 340.464 388.800 340.488 ;
    END
  END result[676]
  PIN result[677]
    DIRECTION OUTPUT ;
    USE SIGNAL ;
    PORT
      LAYER M4 ;
        RECT 388.608 340.944 388.800 340.968 ;
    END
  END result[677]
  PIN result[678]
    DIRECTION OUTPUT ;
    USE SIGNAL ;
    PORT
      LAYER M4 ;
        RECT 388.608 341.424 388.800 341.448 ;
    END
  END result[678]
  PIN result[679]
    DIRECTION OUTPUT ;
    USE SIGNAL ;
    PORT
      LAYER M4 ;
        RECT 388.608 341.952 388.800 341.976 ;
    END
  END result[679]
  PIN result[680]
    DIRECTION OUTPUT ;
    USE SIGNAL ;
    PORT
      LAYER M4 ;
        RECT 388.608 342.432 388.800 342.456 ;
    END
  END result[680]
  PIN result[681]
    DIRECTION OUTPUT ;
    USE SIGNAL ;
    PORT
      LAYER M4 ;
        RECT 388.608 342.960 388.800 342.984 ;
    END
  END result[681]
  PIN result[682]
    DIRECTION OUTPUT ;
    USE SIGNAL ;
    PORT
      LAYER M4 ;
        RECT 388.608 343.440 388.800 343.464 ;
    END
  END result[682]
  PIN result[683]
    DIRECTION OUTPUT ;
    USE SIGNAL ;
    PORT
      LAYER M4 ;
        RECT 388.608 343.920 388.800 343.944 ;
    END
  END result[683]
  PIN result[684]
    DIRECTION OUTPUT ;
    USE SIGNAL ;
    PORT
      LAYER M4 ;
        RECT 388.608 344.448 388.800 344.472 ;
    END
  END result[684]
  PIN result[685]
    DIRECTION OUTPUT ;
    USE SIGNAL ;
    PORT
      LAYER M4 ;
        RECT 388.608 344.928 388.800 344.952 ;
    END
  END result[685]
  PIN result[686]
    DIRECTION OUTPUT ;
    USE SIGNAL ;
    PORT
      LAYER M4 ;
        RECT 388.608 345.456 388.800 345.480 ;
    END
  END result[686]
  PIN result[687]
    DIRECTION OUTPUT ;
    USE SIGNAL ;
    PORT
      LAYER M4 ;
        RECT 388.608 345.936 388.800 345.960 ;
    END
  END result[687]
  PIN result[688]
    DIRECTION OUTPUT ;
    USE SIGNAL ;
    PORT
      LAYER M4 ;
        RECT 388.608 346.416 388.800 346.440 ;
    END
  END result[688]
  PIN result[689]
    DIRECTION OUTPUT ;
    USE SIGNAL ;
    PORT
      LAYER M4 ;
        RECT 388.608 346.944 388.800 346.968 ;
    END
  END result[689]
  PIN result[690]
    DIRECTION OUTPUT ;
    USE SIGNAL ;
    PORT
      LAYER M4 ;
        RECT 388.608 347.424 388.800 347.448 ;
    END
  END result[690]
  PIN result[691]
    DIRECTION OUTPUT ;
    USE SIGNAL ;
    PORT
      LAYER M4 ;
        RECT 388.608 347.952 388.800 347.976 ;
    END
  END result[691]
  PIN result[692]
    DIRECTION OUTPUT ;
    USE SIGNAL ;
    PORT
      LAYER M4 ;
        RECT 388.608 348.432 388.800 348.456 ;
    END
  END result[692]
  PIN result[693]
    DIRECTION OUTPUT ;
    USE SIGNAL ;
    PORT
      LAYER M4 ;
        RECT 388.608 348.912 388.800 348.936 ;
    END
  END result[693]
  PIN result[694]
    DIRECTION OUTPUT ;
    USE SIGNAL ;
    PORT
      LAYER M4 ;
        RECT 388.608 349.440 388.800 349.464 ;
    END
  END result[694]
  PIN result[695]
    DIRECTION OUTPUT ;
    USE SIGNAL ;
    PORT
      LAYER M4 ;
        RECT 388.608 349.920 388.800 349.944 ;
    END
  END result[695]
  PIN result[696]
    DIRECTION OUTPUT ;
    USE SIGNAL ;
    PORT
      LAYER M4 ;
        RECT 388.608 350.448 388.800 350.472 ;
    END
  END result[696]
  PIN result[697]
    DIRECTION OUTPUT ;
    USE SIGNAL ;
    PORT
      LAYER M4 ;
        RECT 388.608 350.928 388.800 350.952 ;
    END
  END result[697]
  PIN result[698]
    DIRECTION OUTPUT ;
    USE SIGNAL ;
    PORT
      LAYER M4 ;
        RECT 388.608 351.408 388.800 351.432 ;
    END
  END result[698]
  PIN result[699]
    DIRECTION OUTPUT ;
    USE SIGNAL ;
    PORT
      LAYER M4 ;
        RECT 388.608 351.936 388.800 351.960 ;
    END
  END result[699]
  PIN result[700]
    DIRECTION OUTPUT ;
    USE SIGNAL ;
    PORT
      LAYER M4 ;
        RECT 388.608 352.416 388.800 352.440 ;
    END
  END result[700]
  PIN result[701]
    DIRECTION OUTPUT ;
    USE SIGNAL ;
    PORT
      LAYER M4 ;
        RECT 388.608 352.944 388.800 352.968 ;
    END
  END result[701]
  PIN result[702]
    DIRECTION OUTPUT ;
    USE SIGNAL ;
    PORT
      LAYER M4 ;
        RECT 388.608 353.424 388.800 353.448 ;
    END
  END result[702]
  PIN result[703]
    DIRECTION OUTPUT ;
    USE SIGNAL ;
    PORT
      LAYER M4 ;
        RECT 388.608 353.904 388.800 353.928 ;
    END
  END result[703]
  PIN result[704]
    DIRECTION OUTPUT ;
    USE SIGNAL ;
    PORT
      LAYER M4 ;
        RECT 388.608 354.432 388.800 354.456 ;
    END
  END result[704]
  PIN result[705]
    DIRECTION OUTPUT ;
    USE SIGNAL ;
    PORT
      LAYER M4 ;
        RECT 388.608 354.912 388.800 354.936 ;
    END
  END result[705]
  PIN result[706]
    DIRECTION OUTPUT ;
    USE SIGNAL ;
    PORT
      LAYER M4 ;
        RECT 388.608 355.440 388.800 355.464 ;
    END
  END result[706]
  PIN result[707]
    DIRECTION OUTPUT ;
    USE SIGNAL ;
    PORT
      LAYER M4 ;
        RECT 388.608 355.920 388.800 355.944 ;
    END
  END result[707]
  PIN result[708]
    DIRECTION OUTPUT ;
    USE SIGNAL ;
    PORT
      LAYER M4 ;
        RECT 388.608 356.400 388.800 356.424 ;
    END
  END result[708]
  PIN result[709]
    DIRECTION OUTPUT ;
    USE SIGNAL ;
    PORT
      LAYER M4 ;
        RECT 388.608 356.928 388.800 356.952 ;
    END
  END result[709]
  PIN result[710]
    DIRECTION OUTPUT ;
    USE SIGNAL ;
    PORT
      LAYER M4 ;
        RECT 388.608 357.408 388.800 357.432 ;
    END
  END result[710]
  PIN result[711]
    DIRECTION OUTPUT ;
    USE SIGNAL ;
    PORT
      LAYER M4 ;
        RECT 388.608 357.936 388.800 357.960 ;
    END
  END result[711]
  PIN result[712]
    DIRECTION OUTPUT ;
    USE SIGNAL ;
    PORT
      LAYER M4 ;
        RECT 388.608 358.416 388.800 358.440 ;
    END
  END result[712]
  PIN result[713]
    DIRECTION OUTPUT ;
    USE SIGNAL ;
    PORT
      LAYER M4 ;
        RECT 388.608 358.896 388.800 358.920 ;
    END
  END result[713]
  PIN result[714]
    DIRECTION OUTPUT ;
    USE SIGNAL ;
    PORT
      LAYER M4 ;
        RECT 388.608 359.424 388.800 359.448 ;
    END
  END result[714]
  PIN result[715]
    DIRECTION OUTPUT ;
    USE SIGNAL ;
    PORT
      LAYER M4 ;
        RECT 388.608 359.904 388.800 359.928 ;
    END
  END result[715]
  PIN result[716]
    DIRECTION OUTPUT ;
    USE SIGNAL ;
    PORT
      LAYER M4 ;
        RECT 388.608 360.432 388.800 360.456 ;
    END
  END result[716]
  PIN result[717]
    DIRECTION OUTPUT ;
    USE SIGNAL ;
    PORT
      LAYER M4 ;
        RECT 388.608 360.912 388.800 360.936 ;
    END
  END result[717]
  PIN result[718]
    DIRECTION OUTPUT ;
    USE SIGNAL ;
    PORT
      LAYER M4 ;
        RECT 388.608 361.392 388.800 361.416 ;
    END
  END result[718]
  PIN result[719]
    DIRECTION OUTPUT ;
    USE SIGNAL ;
    PORT
      LAYER M4 ;
        RECT 388.608 361.920 388.800 361.944 ;
    END
  END result[719]
  PIN result[720]
    DIRECTION OUTPUT ;
    USE SIGNAL ;
    PORT
      LAYER M4 ;
        RECT 388.608 362.400 388.800 362.424 ;
    END
  END result[720]
  PIN result[721]
    DIRECTION OUTPUT ;
    USE SIGNAL ;
    PORT
      LAYER M4 ;
        RECT 388.608 362.928 388.800 362.952 ;
    END
  END result[721]
  PIN result[722]
    DIRECTION OUTPUT ;
    USE SIGNAL ;
    PORT
      LAYER M4 ;
        RECT 388.608 363.408 388.800 363.432 ;
    END
  END result[722]
  PIN result[723]
    DIRECTION OUTPUT ;
    USE SIGNAL ;
    PORT
      LAYER M4 ;
        RECT 388.608 363.888 388.800 363.912 ;
    END
  END result[723]
  PIN result[724]
    DIRECTION OUTPUT ;
    USE SIGNAL ;
    PORT
      LAYER M4 ;
        RECT 388.608 364.416 388.800 364.440 ;
    END
  END result[724]
  PIN result[725]
    DIRECTION OUTPUT ;
    USE SIGNAL ;
    PORT
      LAYER M4 ;
        RECT 388.608 364.896 388.800 364.920 ;
    END
  END result[725]
  PIN result[726]
    DIRECTION OUTPUT ;
    USE SIGNAL ;
    PORT
      LAYER M4 ;
        RECT 388.608 365.424 388.800 365.448 ;
    END
  END result[726]
  PIN result[727]
    DIRECTION OUTPUT ;
    USE SIGNAL ;
    PORT
      LAYER M4 ;
        RECT 388.608 365.904 388.800 365.928 ;
    END
  END result[727]
  PIN result[728]
    DIRECTION OUTPUT ;
    USE SIGNAL ;
    PORT
      LAYER M4 ;
        RECT 388.608 366.384 388.800 366.408 ;
    END
  END result[728]
  PIN result[729]
    DIRECTION OUTPUT ;
    USE SIGNAL ;
    PORT
      LAYER M4 ;
        RECT 388.608 366.912 388.800 366.936 ;
    END
  END result[729]
  PIN result[730]
    DIRECTION OUTPUT ;
    USE SIGNAL ;
    PORT
      LAYER M4 ;
        RECT 388.608 367.392 388.800 367.416 ;
    END
  END result[730]
  PIN result[731]
    DIRECTION OUTPUT ;
    USE SIGNAL ;
    PORT
      LAYER M4 ;
        RECT 388.608 367.920 388.800 367.944 ;
    END
  END result[731]
  PIN result[732]
    DIRECTION OUTPUT ;
    USE SIGNAL ;
    PORT
      LAYER M4 ;
        RECT 388.608 368.400 388.800 368.424 ;
    END
  END result[732]
  PIN result[733]
    DIRECTION OUTPUT ;
    USE SIGNAL ;
    PORT
      LAYER M4 ;
        RECT 388.608 368.880 388.800 368.904 ;
    END
  END result[733]
  PIN result[734]
    DIRECTION OUTPUT ;
    USE SIGNAL ;
    PORT
      LAYER M4 ;
        RECT 388.608 369.408 388.800 369.432 ;
    END
  END result[734]
  PIN result[735]
    DIRECTION OUTPUT ;
    USE SIGNAL ;
    PORT
      LAYER M4 ;
        RECT 388.608 369.888 388.800 369.912 ;
    END
  END result[735]
  PIN result[736]
    DIRECTION OUTPUT ;
    USE SIGNAL ;
    PORT
      LAYER M4 ;
        RECT 388.608 370.416 388.800 370.440 ;
    END
  END result[736]
  PIN result[737]
    DIRECTION OUTPUT ;
    USE SIGNAL ;
    PORT
      LAYER M4 ;
        RECT 388.608 370.896 388.800 370.920 ;
    END
  END result[737]
  PIN result[738]
    DIRECTION OUTPUT ;
    USE SIGNAL ;
    PORT
      LAYER M4 ;
        RECT 388.608 371.376 388.800 371.400 ;
    END
  END result[738]
  PIN result[739]
    DIRECTION OUTPUT ;
    USE SIGNAL ;
    PORT
      LAYER M4 ;
        RECT 388.608 371.904 388.800 371.928 ;
    END
  END result[739]
  PIN result[740]
    DIRECTION OUTPUT ;
    USE SIGNAL ;
    PORT
      LAYER M4 ;
        RECT 388.608 372.384 388.800 372.408 ;
    END
  END result[740]
  PIN result[741]
    DIRECTION OUTPUT ;
    USE SIGNAL ;
    PORT
      LAYER M4 ;
        RECT 388.608 372.912 388.800 372.936 ;
    END
  END result[741]
  PIN result[742]
    DIRECTION OUTPUT ;
    USE SIGNAL ;
    PORT
      LAYER M4 ;
        RECT 388.608 373.392 388.800 373.416 ;
    END
  END result[742]
  PIN result[743]
    DIRECTION OUTPUT ;
    USE SIGNAL ;
    PORT
      LAYER M4 ;
        RECT 388.608 373.872 388.800 373.896 ;
    END
  END result[743]
  PIN result[744]
    DIRECTION OUTPUT ;
    USE SIGNAL ;
    PORT
      LAYER M4 ;
        RECT 388.608 374.400 388.800 374.424 ;
    END
  END result[744]
  PIN result[745]
    DIRECTION OUTPUT ;
    USE SIGNAL ;
    PORT
      LAYER M4 ;
        RECT 388.608 374.880 388.800 374.904 ;
    END
  END result[745]
  PIN result[746]
    DIRECTION OUTPUT ;
    USE SIGNAL ;
    PORT
      LAYER M4 ;
        RECT 388.608 375.408 388.800 375.432 ;
    END
  END result[746]
  PIN result[747]
    DIRECTION OUTPUT ;
    USE SIGNAL ;
    PORT
      LAYER M4 ;
        RECT 388.608 375.888 388.800 375.912 ;
    END
  END result[747]
  PIN result[748]
    DIRECTION OUTPUT ;
    USE SIGNAL ;
    PORT
      LAYER M4 ;
        RECT 388.608 376.368 388.800 376.392 ;
    END
  END result[748]
  PIN result[749]
    DIRECTION OUTPUT ;
    USE SIGNAL ;
    PORT
      LAYER M4 ;
        RECT 388.608 376.896 388.800 376.920 ;
    END
  END result[749]
  PIN result[750]
    DIRECTION OUTPUT ;
    USE SIGNAL ;
    PORT
      LAYER M4 ;
        RECT 388.608 377.376 388.800 377.400 ;
    END
  END result[750]
  PIN result[751]
    DIRECTION OUTPUT ;
    USE SIGNAL ;
    PORT
      LAYER M4 ;
        RECT 388.608 377.904 388.800 377.928 ;
    END
  END result[751]
  PIN result[752]
    DIRECTION OUTPUT ;
    USE SIGNAL ;
    PORT
      LAYER M4 ;
        RECT 388.608 378.384 388.800 378.408 ;
    END
  END result[752]
  PIN result[753]
    DIRECTION OUTPUT ;
    USE SIGNAL ;
    PORT
      LAYER M4 ;
        RECT 388.608 378.912 388.800 378.936 ;
    END
  END result[753]
  PIN result[754]
    DIRECTION OUTPUT ;
    USE SIGNAL ;
    PORT
      LAYER M4 ;
        RECT 388.608 379.392 388.800 379.416 ;
    END
  END result[754]
  PIN result[755]
    DIRECTION OUTPUT ;
    USE SIGNAL ;
    PORT
      LAYER M4 ;
        RECT 388.608 379.872 388.800 379.896 ;
    END
  END result[755]
  PIN result[756]
    DIRECTION OUTPUT ;
    USE SIGNAL ;
    PORT
      LAYER M4 ;
        RECT 388.608 380.400 388.800 380.424 ;
    END
  END result[756]
  PIN result[757]
    DIRECTION OUTPUT ;
    USE SIGNAL ;
    PORT
      LAYER M4 ;
        RECT 388.608 380.880 388.800 380.904 ;
    END
  END result[757]
  PIN result[758]
    DIRECTION OUTPUT ;
    USE SIGNAL ;
    PORT
      LAYER M4 ;
        RECT 388.608 381.408 388.800 381.432 ;
    END
  END result[758]
  PIN result[759]
    DIRECTION OUTPUT ;
    USE SIGNAL ;
    PORT
      LAYER M4 ;
        RECT 388.608 381.888 388.800 381.912 ;
    END
  END result[759]
  PIN result[760]
    DIRECTION OUTPUT ;
    USE SIGNAL ;
    PORT
      LAYER M4 ;
        RECT 388.608 382.368 388.800 382.392 ;
    END
  END result[760]
  PIN result[761]
    DIRECTION OUTPUT ;
    USE SIGNAL ;
    PORT
      LAYER M4 ;
        RECT 388.608 382.896 388.800 382.920 ;
    END
  END result[761]
  PIN result[762]
    DIRECTION OUTPUT ;
    USE SIGNAL ;
    PORT
      LAYER M4 ;
        RECT 388.608 383.376 388.800 383.400 ;
    END
  END result[762]
  PIN result[763]
    DIRECTION OUTPUT ;
    USE SIGNAL ;
    PORT
      LAYER M4 ;
        RECT 388.608 383.904 388.800 383.928 ;
    END
  END result[763]
  PIN result[764]
    DIRECTION OUTPUT ;
    USE SIGNAL ;
    PORT
      LAYER M4 ;
        RECT 388.608 384.384 388.800 384.408 ;
    END
  END result[764]
  PIN result[765]
    DIRECTION OUTPUT ;
    USE SIGNAL ;
    PORT
      LAYER M4 ;
        RECT 388.608 384.864 388.800 384.888 ;
    END
  END result[765]
  PIN result[766]
    DIRECTION OUTPUT ;
    USE SIGNAL ;
    PORT
      LAYER M4 ;
        RECT 388.608 385.392 388.800 385.416 ;
    END
  END result[766]
  PIN result[767]
    DIRECTION OUTPUT ;
    USE SIGNAL ;
    PORT
      LAYER M4 ;
        RECT 388.608 385.872 388.800 385.896 ;
    END
  END result[767]
  PIN fault
    DIRECTION OUTPUT ;
    USE SIGNAL ;
    PORT
      LAYER M4 ;
        RECT 388.608 386.400 388.800 386.424 ;
    END
  END fault
  PIN clk
    DIRECTION INPUT ;
    USE CLOCK ;
    PORT
      LAYER M5 ;
        RECT 98.256 0.000 98.280 0.192 ;
    END
  END clk
  PIN rst_n
    DIRECTION INPUT ;
    USE SIGNAL ;
    PORT
      LAYER M3 ;
        RECT 290.517 0.000 290.541 0.192 ;
    END
  END rst_n
  PIN VDD
    DIRECTION INOUT ;
    USE POWER ;
    PORT
      LAYER M5 ;
        RECT 2.460 0.500 2.580 388.300 ;
        RECT 7.860 0.500 7.980 388.300 ;
        RECT 13.260 0.500 13.380 388.300 ;
        RECT 18.660 0.500 18.780 388.300 ;
        RECT 24.060 0.500 24.180 388.300 ;
        RECT 29.460 0.500 29.580 388.300 ;
        RECT 34.860 0.500 34.980 388.300 ;
        RECT 40.260 0.500 40.380 388.300 ;
        RECT 45.660 0.500 45.780 388.300 ;
        RECT 51.060 0.500 51.180 388.300 ;
        RECT 56.460 0.500 56.580 388.300 ;
        RECT 61.860 0.500 61.980 388.300 ;
        RECT 67.260 0.500 67.380 388.300 ;
        RECT 72.660 0.500 72.780 388.300 ;
        RECT 78.060 0.500 78.180 388.300 ;
        RECT 83.460 0.500 83.580 388.300 ;
        RECT 88.860 0.500 88.980 388.300 ;
        RECT 94.260 0.500 94.380 388.300 ;
        RECT 99.660 0.500 99.780 388.300 ;
        RECT 105.060 0.500 105.180 388.300 ;
        RECT 110.460 0.500 110.580 388.300 ;
        RECT 115.860 0.500 115.980 388.300 ;
        RECT 121.260 0.500 121.380 388.300 ;
        RECT 126.660 0.500 126.780 388.300 ;
        RECT 132.060 0.500 132.180 388.300 ;
        RECT 137.460 0.500 137.580 388.300 ;
        RECT 142.860 0.500 142.980 388.300 ;
        RECT 148.260 0.500 148.380 388.300 ;
        RECT 153.660 0.500 153.780 388.300 ;
        RECT 159.060 0.500 159.180 388.300 ;
        RECT 164.460 0.500 164.580 388.300 ;
        RECT 169.860 0.500 169.980 388.300 ;
        RECT 175.260 0.500 175.380 388.300 ;
        RECT 180.660 0.500 180.780 388.300 ;
        RECT 186.060 0.500 186.180 388.300 ;
        RECT 191.460 0.500 191.580 388.300 ;
        RECT 196.860 0.500 196.980 388.300 ;
        RECT 202.260 0.500 202.380 388.300 ;
        RECT 207.660 0.500 207.780 388.300 ;
        RECT 213.060 0.500 213.180 388.300 ;
        RECT 218.460 0.500 218.580 388.300 ;
        RECT 223.860 0.500 223.980 388.300 ;
        RECT 229.260 0.500 229.380 388.300 ;
        RECT 234.660 0.500 234.780 388.300 ;
        RECT 240.060 0.500 240.180 388.300 ;
        RECT 245.460 0.500 245.580 388.300 ;
        RECT 250.860 0.500 250.980 388.300 ;
        RECT 256.260 0.500 256.380 388.300 ;
        RECT 261.660 0.500 261.780 388.300 ;
        RECT 267.060 0.500 267.180 388.300 ;
        RECT 272.460 0.500 272.580 388.300 ;
        RECT 277.860 0.500 277.980 388.300 ;
        RECT 283.260 0.500 283.380 388.300 ;
        RECT 288.660 0.500 288.780 388.300 ;
        RECT 294.060 0.500 294.180 388.300 ;
        RECT 299.460 0.500 299.580 388.300 ;
        RECT 304.860 0.500 304.980 388.300 ;
        RECT 310.260 0.500 310.380 388.300 ;
        RECT 315.660 0.500 315.780 388.300 ;
        RECT 321.060 0.500 321.180 388.300 ;
        RECT 326.460 0.500 326.580 388.300 ;
        RECT 331.860 0.500 331.980 388.300 ;
        RECT 337.260 0.500 337.380 388.300 ;
        RECT 342.660 0.500 342.780 388.300 ;
        RECT 348.060 0.500 348.180 388.300 ;
        RECT 353.460 0.500 353.580 388.300 ;
        RECT 358.860 0.500 358.980 388.300 ;
        RECT 364.260 0.500 364.380 388.300 ;
        RECT 369.660 0.500 369.780 388.300 ;
        RECT 375.060 0.500 375.180 388.300 ;
        RECT 380.460 0.500 380.580 388.300 ;
        RECT 385.860 0.500 385.980 388.300 ;
    END
  END VDD
  PIN VSS
    DIRECTION INOUT ;
    USE GROUND ;
    PORT
      LAYER M5 ;
        RECT 2.652 0.500 2.772 388.300 ;
        RECT 8.052 0.500 8.172 388.300 ;
        RECT 13.452 0.500 13.572 388.300 ;
        RECT 18.852 0.500 18.972 388.300 ;
        RECT 24.252 0.500 24.372 388.300 ;
        RECT 29.652 0.500 29.772 388.300 ;
        RECT 35.052 0.500 35.172 388.300 ;
        RECT 40.452 0.500 40.572 388.300 ;
        RECT 45.852 0.500 45.972 388.300 ;
        RECT 51.252 0.500 51.372 388.300 ;
        RECT 56.652 0.500 56.772 388.300 ;
        RECT 62.052 0.500 62.172 388.300 ;
        RECT 67.452 0.500 67.572 388.300 ;
        RECT 72.852 0.500 72.972 388.300 ;
        RECT 78.252 0.500 78.372 388.300 ;
        RECT 83.652 0.500 83.772 388.300 ;
        RECT 89.052 0.500 89.172 388.300 ;
        RECT 94.452 0.500 94.572 388.300 ;
        RECT 99.852 0.500 99.972 388.300 ;
        RECT 105.252 0.500 105.372 388.300 ;
        RECT 110.652 0.500 110.772 388.300 ;
        RECT 116.052 0.500 116.172 388.300 ;
        RECT 121.452 0.500 121.572 388.300 ;
        RECT 126.852 0.500 126.972 388.300 ;
        RECT 132.252 0.500 132.372 388.300 ;
        RECT 137.652 0.500 137.772 388.300 ;
        RECT 143.052 0.500 143.172 388.300 ;
        RECT 148.452 0.500 148.572 388.300 ;
        RECT 153.852 0.500 153.972 388.300 ;
        RECT 159.252 0.500 159.372 388.300 ;
        RECT 164.652 0.500 164.772 388.300 ;
        RECT 170.052 0.500 170.172 388.300 ;
        RECT 175.452 0.500 175.572 388.300 ;
        RECT 180.852 0.500 180.972 388.300 ;
        RECT 186.252 0.500 186.372 388.300 ;
        RECT 191.652 0.500 191.772 388.300 ;
        RECT 197.052 0.500 197.172 388.300 ;
        RECT 202.452 0.500 202.572 388.300 ;
        RECT 207.852 0.500 207.972 388.300 ;
        RECT 213.252 0.500 213.372 388.300 ;
        RECT 218.652 0.500 218.772 388.300 ;
        RECT 224.052 0.500 224.172 388.300 ;
        RECT 229.452 0.500 229.572 388.300 ;
        RECT 234.852 0.500 234.972 388.300 ;
        RECT 240.252 0.500 240.372 388.300 ;
        RECT 245.652 0.500 245.772 388.300 ;
        RECT 251.052 0.500 251.172 388.300 ;
        RECT 256.452 0.500 256.572 388.300 ;
        RECT 261.852 0.500 261.972 388.300 ;
        RECT 267.252 0.500 267.372 388.300 ;
        RECT 272.652 0.500 272.772 388.300 ;
        RECT 278.052 0.500 278.172 388.300 ;
        RECT 283.452 0.500 283.572 388.300 ;
        RECT 288.852 0.500 288.972 388.300 ;
        RECT 294.252 0.500 294.372 388.300 ;
        RECT 299.652 0.500 299.772 388.300 ;
        RECT 305.052 0.500 305.172 388.300 ;
        RECT 310.452 0.500 310.572 388.300 ;
        RECT 315.852 0.500 315.972 388.300 ;
        RECT 321.252 0.500 321.372 388.300 ;
        RECT 326.652 0.500 326.772 388.300 ;
        RECT 332.052 0.500 332.172 388.300 ;
        RECT 337.452 0.500 337.572 388.300 ;
        RECT 342.852 0.500 342.972 388.300 ;
        RECT 348.252 0.500 348.372 388.300 ;
        RECT 353.652 0.500 353.772 388.300 ;
        RECT 359.052 0.500 359.172 388.300 ;
        RECT 364.452 0.500 364.572 388.300 ;
        RECT 369.852 0.500 369.972 388.300 ;
        RECT 375.252 0.500 375.372 388.300 ;
        RECT 380.652 0.500 380.772 388.300 ;
        RECT 386.052 0.500 386.172 388.300 ;
    END
  END VSS
  OBS
    LAYER M1 ;
      RECT 0.500 0.500 388.300 388.300 ;
    LAYER M2 ;
      RECT 0.500 0.500 388.300 388.300 ;
    LAYER M3 ;
      RECT 10.800 0.500 87.456 378.000 ;
      RECT 87.456 10.800 109.080 378.000 ;
      RECT 109.080 0.500 279.717 378.000 ;
      RECT 279.717 10.800 301.341 378.000 ;
      RECT 301.341 0.500 378.000 378.000 ;
    LAYER M4 ;
      RECT 10.800 0.500 87.456 378.000 ;
      RECT 87.456 10.800 109.080 378.000 ;
      RECT 109.080 0.500 279.717 378.000 ;
      RECT 279.717 10.800 301.341 378.000 ;
      RECT 301.341 0.500 378.000 378.000 ;
    LAYER M5 ;
      RECT 10.800 0.900 13.260 378.000 ;
      RECT 13.380 0.900 13.452 378.000 ;
      RECT 13.572 0.900 18.660 378.000 ;
      RECT 18.780 0.900 18.852 378.000 ;
      RECT 18.972 0.900 24.060 378.000 ;
      RECT 24.180 0.900 24.252 378.000 ;
      RECT 24.372 0.900 29.460 378.000 ;
      RECT 29.580 0.900 29.652 378.000 ;
      RECT 29.772 0.900 34.860 378.000 ;
      RECT 34.980 0.900 35.052 378.000 ;
      RECT 35.172 0.900 40.260 378.000 ;
      RECT 40.380 0.900 40.452 378.000 ;
      RECT 40.572 0.900 45.660 378.000 ;
      RECT 45.780 0.900 45.852 378.000 ;
      RECT 45.972 0.900 51.060 378.000 ;
      RECT 51.180 0.900 51.252 378.000 ;
      RECT 51.372 0.900 56.460 378.000 ;
      RECT 56.580 0.900 56.652 378.000 ;
      RECT 56.772 0.900 61.860 378.000 ;
      RECT 61.980 0.900 62.052 378.000 ;
      RECT 62.172 0.900 67.260 378.000 ;
      RECT 67.380 0.900 67.452 378.000 ;
      RECT 67.572 0.900 72.660 378.000 ;
      RECT 72.780 0.900 72.852 378.000 ;
      RECT 72.972 0.900 78.060 378.000 ;
      RECT 78.180 0.900 78.252 378.000 ;
      RECT 78.372 0.900 83.460 378.000 ;
      RECT 83.580 0.900 83.652 378.000 ;
      RECT 83.772 0.900 87.456 378.000 ;
      RECT 87.456 10.800 88.860 378.000 ;
      RECT 88.980 10.800 89.052 378.000 ;
      RECT 89.172 10.800 94.260 378.000 ;
      RECT 94.380 10.800 94.452 378.000 ;
      RECT 94.572 10.800 99.660 378.000 ;
      RECT 99.780 10.800 99.852 378.000 ;
      RECT 99.972 10.800 105.060 378.000 ;
      RECT 105.180 10.800 105.252 378.000 ;
      RECT 105.372 10.800 109.080 378.000 ;
      RECT 109.080 0.900 110.460 378.000 ;
      RECT 110.580 0.900 110.652 378.000 ;
      RECT 110.772 0.900 115.860 378.000 ;
      RECT 115.980 0.900 116.052 378.000 ;
      RECT 116.172 0.900 121.260 378.000 ;
      RECT 121.380 0.900 121.452 378.000 ;
      RECT 121.572 0.900 126.660 378.000 ;
      RECT 126.780 0.900 126.852 378.000 ;
      RECT 126.972 0.900 132.060 378.000 ;
      RECT 132.180 0.900 132.252 378.000 ;
      RECT 132.372 0.900 137.460 378.000 ;
      RECT 137.580 0.900 137.652 378.000 ;
      RECT 137.772 0.900 142.860 378.000 ;
      RECT 142.980 0.900 143.052 378.000 ;
      RECT 143.172 0.900 148.260 378.000 ;
      RECT 148.380 0.900 148.452 378.000 ;
      RECT 148.572 0.900 153.660 378.000 ;
      RECT 153.780 0.900 153.852 378.000 ;
      RECT 153.972 0.900 159.060 378.000 ;
      RECT 159.180 0.900 159.252 378.000 ;
      RECT 159.372 0.900 164.460 378.000 ;
      RECT 164.580 0.900 164.652 378.000 ;
      RECT 164.772 0.900 169.860 378.000 ;
      RECT 169.980 0.900 170.052 378.000 ;
      RECT 170.172 0.900 175.260 378.000 ;
      RECT 175.380 0.900 175.452 378.000 ;
      RECT 175.572 0.900 180.660 378.000 ;
      RECT 180.780 0.900 180.852 378.000 ;
      RECT 180.972 0.900 186.060 378.000 ;
      RECT 186.180 0.900 186.252 378.000 ;
      RECT 186.372 0.900 191.460 378.000 ;
      RECT 191.580 0.900 191.652 378.000 ;
      RECT 191.772 0.900 196.860 378.000 ;
      RECT 196.980 0.900 197.052 378.000 ;
      RECT 197.172 0.900 202.260 378.000 ;
      RECT 202.380 0.900 202.452 378.000 ;
      RECT 202.572 0.900 207.660 378.000 ;
      RECT 207.780 0.900 207.852 378.000 ;
      RECT 207.972 0.900 213.060 378.000 ;
      RECT 213.180 0.900 213.252 378.000 ;
      RECT 213.372 0.900 218.460 378.000 ;
      RECT 218.580 0.900 218.652 378.000 ;
      RECT 218.772 0.900 223.860 378.000 ;
      RECT 223.980 0.900 224.052 378.000 ;
      RECT 224.172 0.900 229.260 378.000 ;
      RECT 229.380 0.900 229.452 378.000 ;
      RECT 229.572 0.900 234.660 378.000 ;
      RECT 234.780 0.900 234.852 378.000 ;
      RECT 234.972 0.900 240.060 378.000 ;
      RECT 240.180 0.900 240.252 378.000 ;
      RECT 240.372 0.900 245.460 378.000 ;
      RECT 245.580 0.900 245.652 378.000 ;
      RECT 245.772 0.900 250.860 378.000 ;
      RECT 250.980 0.900 251.052 378.000 ;
      RECT 251.172 0.900 256.260 378.000 ;
      RECT 256.380 0.900 256.452 378.000 ;
      RECT 256.572 0.900 261.660 378.000 ;
      RECT 261.780 0.900 261.852 378.000 ;
      RECT 261.972 0.900 267.060 378.000 ;
      RECT 267.180 0.900 267.252 378.000 ;
      RECT 267.372 0.900 272.460 378.000 ;
      RECT 272.580 0.900 272.652 378.000 ;
      RECT 272.772 0.900 277.860 378.000 ;
      RECT 277.980 0.900 278.052 378.000 ;
      RECT 278.172 0.900 279.717 378.000 ;
      RECT 279.717 10.800 283.260 378.000 ;
      RECT 283.380 10.800 283.452 378.000 ;
      RECT 283.572 10.800 288.660 378.000 ;
      RECT 288.780 10.800 288.852 378.000 ;
      RECT 288.972 10.800 294.060 378.000 ;
      RECT 294.180 10.800 294.252 378.000 ;
      RECT 294.372 10.800 299.460 378.000 ;
      RECT 299.580 10.800 299.652 378.000 ;
      RECT 299.772 10.800 301.341 378.000 ;
      RECT 301.341 0.900 304.860 378.000 ;
      RECT 304.980 0.900 305.052 378.000 ;
      RECT 305.172 0.900 310.260 378.000 ;
      RECT 310.380 0.900 310.452 378.000 ;
      RECT 310.572 0.900 315.660 378.000 ;
      RECT 315.780 0.900 315.852 378.000 ;
      RECT 315.972 0.900 321.060 378.000 ;
      RECT 321.180 0.900 321.252 378.000 ;
      RECT 321.372 0.900 326.460 378.000 ;
      RECT 326.580 0.900 326.652 378.000 ;
      RECT 326.772 0.900 331.860 378.000 ;
      RECT 331.980 0.900 332.052 378.000 ;
      RECT 332.172 0.900 337.260 378.000 ;
      RECT 337.380 0.900 337.452 378.000 ;
      RECT 337.572 0.900 342.660 378.000 ;
      RECT 342.780 0.900 342.852 378.000 ;
      RECT 342.972 0.900 348.060 378.000 ;
      RECT 348.180 0.900 348.252 378.000 ;
      RECT 348.372 0.900 353.460 378.000 ;
      RECT 353.580 0.900 353.652 378.000 ;
      RECT 353.772 0.900 358.860 378.000 ;
      RECT 358.980 0.900 359.052 378.000 ;
      RECT 359.172 0.900 364.260 378.000 ;
      RECT 364.380 0.900 364.452 378.000 ;
      RECT 364.572 0.900 369.660 378.000 ;
      RECT 369.780 0.900 369.852 378.000 ;
      RECT 369.972 0.900 375.060 378.000 ;
      RECT 375.180 0.900 375.252 378.000 ;
      RECT 375.372 0.900 378.000 378.000 ;
  END
END ot_hbm_hc_tail_child_static
END LIBRARY
